VERSION 5.8 ;
BUSBITCHARS "[]" ;
DIVIDERCHAR "/" ;
UNITS
    DATABASE MICRONS 1000 ;
END UNITS

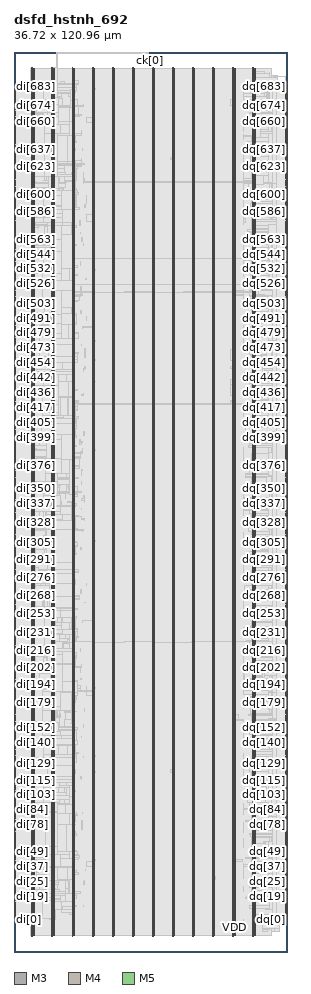
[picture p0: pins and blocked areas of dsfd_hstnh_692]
MACRO dsfd_hstnh_692
  FOREIGN dsfd_hstnh_692 0 0 ;
  CLASS BLOCK ;
  SIZE 36.72 BY 120.96 ;
  PIN ck[0]
    DIRECTION INPUT ;
    USE SIGNAL ;
    PORT
      LAYER M3 ;
        RECT  18.36 120.816 18.378 120.96 ;
    END
    PORT
      LAYER M3 ;
        RECT  18.18 120.793 18.378 120.828 ;
    END
  END ck[0]
  PIN di[0]
    DIRECTION INPUT ;
    USE SIGNAL ;
    PORT
      LAYER M4 ;
        RECT  0 4.416 0.192 4.44 ;
    END
  END di[0]
  PIN di[100]
    DIRECTION INPUT ;
    USE SIGNAL ;
    PORT
      LAYER M4 ;
        RECT  0 20.64 0.192 20.664 ;
    END
  END di[100]
  PIN di[101]
    DIRECTION INPUT ;
    USE SIGNAL ;
    PORT
      LAYER M4 ;
        RECT  0 20.784 0.192 20.808 ;
    END
  END di[101]
  PIN di[102]
    DIRECTION INPUT ;
    USE SIGNAL ;
    PORT
      LAYER M4 ;
        RECT  0 20.976 0.192 21 ;
    END
  END di[102]
  PIN di[103]
    DIRECTION INPUT ;
    USE SIGNAL ;
    PORT
      LAYER M4 ;
        RECT  0 21.12 0.192 21.144 ;
    END
  END di[103]
  PIN di[104]
    DIRECTION INPUT ;
    USE SIGNAL ;
    PORT
      LAYER M4 ;
        RECT  0 21.312 0.192 21.336 ;
    END
  END di[104]
  PIN di[105]
    DIRECTION INPUT ;
    USE SIGNAL ;
    PORT
      LAYER M4 ;
        RECT  0 21.456 0.192 21.48 ;
    END
  END di[105]
  PIN di[106]
    DIRECTION INPUT ;
    USE SIGNAL ;
    PORT
      LAYER M4 ;
        RECT  0 21.6 0.192 21.624 ;
    END
  END di[106]
  PIN di[107]
    DIRECTION INPUT ;
    USE SIGNAL ;
    PORT
      LAYER M4 ;
        RECT  0 21.792 0.192 21.816 ;
    END
  END di[107]
  PIN di[108]
    DIRECTION INPUT ;
    USE SIGNAL ;
    PORT
      LAYER M4 ;
        RECT  0 21.936 0.192 21.96 ;
    END
  END di[108]
  PIN di[109]
    DIRECTION INPUT ;
    USE SIGNAL ;
    PORT
      LAYER M4 ;
        RECT  0 22.128 0.192 22.152 ;
    END
  END di[109]
  PIN di[10]
    DIRECTION INPUT ;
    USE SIGNAL ;
    PORT
      LAYER M4 ;
        RECT  0 6.048 0.192 6.072 ;
    END
  END di[10]
  PIN di[110]
    DIRECTION INPUT ;
    USE SIGNAL ;
    PORT
      LAYER M4 ;
        RECT  0 22.272 0.192 22.296 ;
    END
  END di[110]
  PIN di[111]
    DIRECTION INPUT ;
    USE SIGNAL ;
    PORT
      LAYER M4 ;
        RECT  0 22.416 0.192 22.44 ;
    END
  END di[111]
  PIN di[112]
    DIRECTION INPUT ;
    USE SIGNAL ;
    PORT
      LAYER M4 ;
        RECT  0 22.608 0.192 22.632 ;
    END
  END di[112]
  PIN di[113]
    DIRECTION INPUT ;
    USE SIGNAL ;
    PORT
      LAYER M4 ;
        RECT  0 22.752 0.192 22.776 ;
    END
  END di[113]
  PIN di[114]
    DIRECTION INPUT ;
    USE SIGNAL ;
    PORT
      LAYER M4 ;
        RECT  0 22.896 0.192 22.92 ;
    END
  END di[114]
  PIN di[115]
    DIRECTION INPUT ;
    USE SIGNAL ;
    PORT
      LAYER M4 ;
        RECT  0 23.088 0.192 23.112 ;
    END
  END di[115]
  PIN di[116]
    DIRECTION INPUT ;
    USE SIGNAL ;
    PORT
      LAYER M4 ;
        RECT  0 23.232 0.192 23.256 ;
    END
  END di[116]
  PIN di[117]
    DIRECTION INPUT ;
    USE SIGNAL ;
    PORT
      LAYER M4 ;
        RECT  0 23.424 0.192 23.448 ;
    END
  END di[117]
  PIN di[118]
    DIRECTION INPUT ;
    USE SIGNAL ;
    PORT
      LAYER M4 ;
        RECT  0 23.568 0.192 23.592 ;
    END
  END di[118]
  PIN di[119]
    DIRECTION INPUT ;
    USE SIGNAL ;
    PORT
      LAYER M4 ;
        RECT  0 23.712 0.192 23.736 ;
    END
  END di[119]
  PIN di[11]
    DIRECTION INPUT ;
    USE SIGNAL ;
    PORT
      LAYER M4 ;
        RECT  0 6.192 0.192 6.216 ;
    END
  END di[11]
  PIN di[120]
    DIRECTION INPUT ;
    USE SIGNAL ;
    PORT
      LAYER M4 ;
        RECT  0 23.904 0.192 23.928 ;
    END
  END di[120]
  PIN di[121]
    DIRECTION INPUT ;
    USE SIGNAL ;
    PORT
      LAYER M4 ;
        RECT  0 24.048 0.192 24.072 ;
    END
  END di[121]
  PIN di[122]
    DIRECTION INPUT ;
    USE SIGNAL ;
    PORT
      LAYER M4 ;
        RECT  0 24.192 0.192 24.216 ;
    END
  END di[122]
  PIN di[123]
    DIRECTION INPUT ;
    USE SIGNAL ;
    PORT
      LAYER M4 ;
        RECT  0 24.384 0.192 24.408 ;
    END
  END di[123]
  PIN di[124]
    DIRECTION INPUT ;
    USE SIGNAL ;
    PORT
      LAYER M4 ;
        RECT  0 24.528 0.192 24.552 ;
    END
  END di[124]
  PIN di[125]
    DIRECTION INPUT ;
    USE SIGNAL ;
    PORT
      LAYER M4 ;
        RECT  0 24.72 0.192 24.744 ;
    END
  END di[125]
  PIN di[126]
    DIRECTION INPUT ;
    USE SIGNAL ;
    PORT
      LAYER M4 ;
        RECT  0 24.864 0.192 24.888 ;
    END
  END di[126]
  PIN di[127]
    DIRECTION INPUT ;
    USE SIGNAL ;
    PORT
      LAYER M4 ;
        RECT  0 25.008 0.192 25.032 ;
    END
  END di[127]
  PIN di[128]
    DIRECTION INPUT ;
    USE SIGNAL ;
    PORT
      LAYER M4 ;
        RECT  0 25.2 0.192 25.224 ;
    END
  END di[128]
  PIN di[129]
    DIRECTION INPUT ;
    USE SIGNAL ;
    PORT
      LAYER M4 ;
        RECT  0 25.344 0.192 25.368 ;
    END
  END di[129]
  PIN di[12]
    DIRECTION INPUT ;
    USE SIGNAL ;
    PORT
      LAYER M4 ;
        RECT  0 6.384 0.192 6.408 ;
    END
  END di[12]
  PIN di[130]
    DIRECTION INPUT ;
    USE SIGNAL ;
    PORT
      LAYER M4 ;
        RECT  0 25.536 0.192 25.56 ;
    END
  END di[130]
  PIN di[131]
    DIRECTION INPUT ;
    USE SIGNAL ;
    PORT
      LAYER M4 ;
        RECT  0 25.68 0.192 25.704 ;
    END
  END di[131]
  PIN di[132]
    DIRECTION INPUT ;
    USE SIGNAL ;
    PORT
      LAYER M4 ;
        RECT  0 25.824 0.192 25.848 ;
    END
  END di[132]
  PIN di[133]
    DIRECTION INPUT ;
    USE SIGNAL ;
    PORT
      LAYER M4 ;
        RECT  0 26.016 0.192 26.04 ;
    END
  END di[133]
  PIN di[134]
    DIRECTION INPUT ;
    USE SIGNAL ;
    PORT
      LAYER M4 ;
        RECT  0 26.16 0.192 26.184 ;
    END
  END di[134]
  PIN di[135]
    DIRECTION INPUT ;
    USE SIGNAL ;
    PORT
      LAYER M4 ;
        RECT  0 26.304 0.192 26.328 ;
    END
  END di[135]
  PIN di[136]
    DIRECTION INPUT ;
    USE SIGNAL ;
    PORT
      LAYER M4 ;
        RECT  0 26.496 0.192 26.52 ;
    END
  END di[136]
  PIN di[137]
    DIRECTION INPUT ;
    USE SIGNAL ;
    PORT
      LAYER M4 ;
        RECT  0 26.64 0.192 26.664 ;
    END
  END di[137]
  PIN di[138]
    DIRECTION INPUT ;
    USE SIGNAL ;
    PORT
      LAYER M4 ;
        RECT  0 26.832 0.192 26.856 ;
    END
  END di[138]
  PIN di[139]
    DIRECTION INPUT ;
    USE SIGNAL ;
    PORT
      LAYER M4 ;
        RECT  0 26.976 0.192 27 ;
    END
  END di[139]
  PIN di[13]
    DIRECTION INPUT ;
    USE SIGNAL ;
    PORT
      LAYER M4 ;
        RECT  0 6.528 0.192 6.552 ;
    END
  END di[13]
  PIN di[140]
    DIRECTION INPUT ;
    USE SIGNAL ;
    PORT
      LAYER M4 ;
        RECT  0 27.12 0.192 27.144 ;
    END
  END di[140]
  PIN di[141]
    DIRECTION INPUT ;
    USE SIGNAL ;
    PORT
      LAYER M4 ;
        RECT  0 27.312 0.192 27.336 ;
    END
  END di[141]
  PIN di[142]
    DIRECTION INPUT ;
    USE SIGNAL ;
    PORT
      LAYER M4 ;
        RECT  0 27.456 0.192 27.48 ;
    END
  END di[142]
  PIN di[143]
    DIRECTION INPUT ;
    USE SIGNAL ;
    PORT
      LAYER M4 ;
        RECT  0 27.6 0.192 27.624 ;
    END
  END di[143]
  PIN di[144]
    DIRECTION INPUT ;
    USE SIGNAL ;
    PORT
      LAYER M4 ;
        RECT  0 27.792 0.192 27.816 ;
    END
  END di[144]
  PIN di[145]
    DIRECTION INPUT ;
    USE SIGNAL ;
    PORT
      LAYER M4 ;
        RECT  0 27.936 0.192 27.96 ;
    END
  END di[145]
  PIN di[146]
    DIRECTION INPUT ;
    USE SIGNAL ;
    PORT
      LAYER M4 ;
        RECT  0 28.128 0.192 28.152 ;
    END
  END di[146]
  PIN di[147]
    DIRECTION INPUT ;
    USE SIGNAL ;
    PORT
      LAYER M4 ;
        RECT  0 28.272 0.192 28.296 ;
    END
  END di[147]
  PIN di[148]
    DIRECTION INPUT ;
    USE SIGNAL ;
    PORT
      LAYER M4 ;
        RECT  0 28.416 0.192 28.44 ;
    END
  END di[148]
  PIN di[149]
    DIRECTION INPUT ;
    USE SIGNAL ;
    PORT
      LAYER M4 ;
        RECT  0 28.608 0.192 28.632 ;
    END
  END di[149]
  PIN di[14]
    DIRECTION INPUT ;
    USE SIGNAL ;
    PORT
      LAYER M4 ;
        RECT  0 6.672 0.192 6.696 ;
    END
  END di[14]
  PIN di[150]
    DIRECTION INPUT ;
    USE SIGNAL ;
    PORT
      LAYER M4 ;
        RECT  0 28.752 0.192 28.776 ;
    END
  END di[150]
  PIN di[151]
    DIRECTION INPUT ;
    USE SIGNAL ;
    PORT
      LAYER M4 ;
        RECT  0 28.944 0.192 28.968 ;
    END
  END di[151]
  PIN di[152]
    DIRECTION INPUT ;
    USE SIGNAL ;
    PORT
      LAYER M4 ;
        RECT  0 29.088 0.192 29.112 ;
    END
  END di[152]
  PIN di[153]
    DIRECTION INPUT ;
    USE SIGNAL ;
    PORT
      LAYER M4 ;
        RECT  0 29.232 0.192 29.256 ;
    END
  END di[153]
  PIN di[154]
    DIRECTION INPUT ;
    USE SIGNAL ;
    PORT
      LAYER M4 ;
        RECT  0 29.424 0.192 29.448 ;
    END
  END di[154]
  PIN di[155]
    DIRECTION INPUT ;
    USE SIGNAL ;
    PORT
      LAYER M4 ;
        RECT  0 29.568 0.192 29.592 ;
    END
  END di[155]
  PIN di[156]
    DIRECTION INPUT ;
    USE SIGNAL ;
    PORT
      LAYER M4 ;
        RECT  0 29.712 0.192 29.736 ;
    END
  END di[156]
  PIN di[157]
    DIRECTION INPUT ;
    USE SIGNAL ;
    PORT
      LAYER M4 ;
        RECT  0 29.904 0.192 29.928 ;
    END
  END di[157]
  PIN di[158]
    DIRECTION INPUT ;
    USE SIGNAL ;
    PORT
      LAYER M4 ;
        RECT  0 30.048 0.192 30.072 ;
    END
  END di[158]
  PIN di[159]
    DIRECTION INPUT ;
    USE SIGNAL ;
    PORT
      LAYER M4 ;
        RECT  0 30.24 0.192 30.264 ;
    END
  END di[159]
  PIN di[15]
    DIRECTION INPUT ;
    USE SIGNAL ;
    PORT
      LAYER M4 ;
        RECT  0 6.864 0.192 6.888 ;
    END
  END di[15]
  PIN di[160]
    DIRECTION INPUT ;
    USE SIGNAL ;
    PORT
      LAYER M4 ;
        RECT  0 30.384 0.192 30.408 ;
    END
  END di[160]
  PIN di[161]
    DIRECTION INPUT ;
    USE SIGNAL ;
    PORT
      LAYER M4 ;
        RECT  0 30.528 0.192 30.552 ;
    END
  END di[161]
  PIN di[162]
    DIRECTION INPUT ;
    USE SIGNAL ;
    PORT
      LAYER M4 ;
        RECT  0 30.72 0.192 30.744 ;
    END
  END di[162]
  PIN di[163]
    DIRECTION INPUT ;
    USE SIGNAL ;
    PORT
      LAYER M4 ;
        RECT  0 30.864 0.192 30.888 ;
    END
  END di[163]
  PIN di[164]
    DIRECTION INPUT ;
    USE SIGNAL ;
    PORT
      LAYER M4 ;
        RECT  0 31.056 0.192 31.08 ;
    END
  END di[164]
  PIN di[165]
    DIRECTION INPUT ;
    USE SIGNAL ;
    PORT
      LAYER M4 ;
        RECT  0 31.2 0.192 31.224 ;
    END
  END di[165]
  PIN di[166]
    DIRECTION INPUT ;
    USE SIGNAL ;
    PORT
      LAYER M4 ;
        RECT  0 31.344 0.192 31.368 ;
    END
  END di[166]
  PIN di[167]
    DIRECTION INPUT ;
    USE SIGNAL ;
    PORT
      LAYER M4 ;
        RECT  0 31.536 0.192 31.56 ;
    END
  END di[167]
  PIN di[168]
    DIRECTION INPUT ;
    USE SIGNAL ;
    PORT
      LAYER M4 ;
        RECT  0 31.68 0.192 31.704 ;
    END
  END di[168]
  PIN di[169]
    DIRECTION INPUT ;
    USE SIGNAL ;
    PORT
      LAYER M4 ;
        RECT  0 31.824 0.192 31.848 ;
    END
  END di[169]
  PIN di[16]
    DIRECTION INPUT ;
    USE SIGNAL ;
    PORT
      LAYER M4 ;
        RECT  0 7.008 0.192 7.032 ;
    END
  END di[16]
  PIN di[170]
    DIRECTION INPUT ;
    USE SIGNAL ;
    PORT
      LAYER M4 ;
        RECT  0 32.016 0.192 32.04 ;
    END
  END di[170]
  PIN di[171]
    DIRECTION INPUT ;
    USE SIGNAL ;
    PORT
      LAYER M4 ;
        RECT  0 32.16 0.192 32.184 ;
    END
  END di[171]
  PIN di[172]
    DIRECTION INPUT ;
    USE SIGNAL ;
    PORT
      LAYER M4 ;
        RECT  0 32.352 0.192 32.376 ;
    END
  END di[172]
  PIN di[173]
    DIRECTION INPUT ;
    USE SIGNAL ;
    PORT
      LAYER M4 ;
        RECT  0 32.496 0.192 32.52 ;
    END
  END di[173]
  PIN di[174]
    DIRECTION INPUT ;
    USE SIGNAL ;
    PORT
      LAYER M4 ;
        RECT  0 32.64 0.192 32.664 ;
    END
  END di[174]
  PIN di[175]
    DIRECTION INPUT ;
    USE SIGNAL ;
    PORT
      LAYER M4 ;
        RECT  0 32.832 0.192 32.856 ;
    END
  END di[175]
  PIN di[176]
    DIRECTION INPUT ;
    USE SIGNAL ;
    PORT
      LAYER M4 ;
        RECT  0 32.976 0.192 33 ;
    END
  END di[176]
  PIN di[177]
    DIRECTION INPUT ;
    USE SIGNAL ;
    PORT
      LAYER M4 ;
        RECT  0 33.12 0.192 33.144 ;
    END
  END di[177]
  PIN di[178]
    DIRECTION INPUT ;
    USE SIGNAL ;
    PORT
      LAYER M4 ;
        RECT  0 33.312 0.192 33.336 ;
    END
  END di[178]
  PIN di[179]
    DIRECTION INPUT ;
    USE SIGNAL ;
    PORT
      LAYER M4 ;
        RECT  0 33.456 0.192 33.48 ;
    END
  END di[179]
  PIN di[17]
    DIRECTION INPUT ;
    USE SIGNAL ;
    PORT
      LAYER M4 ;
        RECT  0 7.152 0.192 7.176 ;
    END
  END di[17]
  PIN di[180]
    DIRECTION INPUT ;
    USE SIGNAL ;
    PORT
      LAYER M4 ;
        RECT  0 33.648 0.192 33.672 ;
    END
  END di[180]
  PIN di[181]
    DIRECTION INPUT ;
    USE SIGNAL ;
    PORT
      LAYER M4 ;
        RECT  0 33.792 0.192 33.816 ;
    END
  END di[181]
  PIN di[182]
    DIRECTION INPUT ;
    USE SIGNAL ;
    PORT
      LAYER M4 ;
        RECT  0 33.936 0.192 33.96 ;
    END
  END di[182]
  PIN di[183]
    DIRECTION INPUT ;
    USE SIGNAL ;
    PORT
      LAYER M4 ;
        RECT  0 34.128 0.192 34.152 ;
    END
  END di[183]
  PIN di[184]
    DIRECTION INPUT ;
    USE SIGNAL ;
    PORT
      LAYER M4 ;
        RECT  0 34.272 0.192 34.296 ;
    END
  END di[184]
  PIN di[185]
    DIRECTION INPUT ;
    USE SIGNAL ;
    PORT
      LAYER M4 ;
        RECT  0 34.464 0.192 34.488 ;
    END
  END di[185]
  PIN di[186]
    DIRECTION INPUT ;
    USE SIGNAL ;
    PORT
      LAYER M4 ;
        RECT  0 34.608 0.192 34.632 ;
    END
  END di[186]
  PIN di[187]
    DIRECTION INPUT ;
    USE SIGNAL ;
    PORT
      LAYER M4 ;
        RECT  0 34.752 0.192 34.776 ;
    END
  END di[187]
  PIN di[188]
    DIRECTION INPUT ;
    USE SIGNAL ;
    PORT
      LAYER M4 ;
        RECT  0 34.944 0.192 34.968 ;
    END
  END di[188]
  PIN di[189]
    DIRECTION INPUT ;
    USE SIGNAL ;
    PORT
      LAYER M4 ;
        RECT  0 35.088 0.192 35.112 ;
    END
  END di[189]
  PIN di[18]
    DIRECTION INPUT ;
    USE SIGNAL ;
    PORT
      LAYER M4 ;
        RECT  0 7.344 0.192 7.368 ;
    END
  END di[18]
  PIN di[190]
    DIRECTION INPUT ;
    USE SIGNAL ;
    PORT
      LAYER M4 ;
        RECT  0 35.232 0.192 35.256 ;
    END
  END di[190]
  PIN di[191]
    DIRECTION INPUT ;
    USE SIGNAL ;
    PORT
      LAYER M4 ;
        RECT  0 35.424 0.192 35.448 ;
    END
  END di[191]
  PIN di[192]
    DIRECTION INPUT ;
    USE SIGNAL ;
    PORT
      LAYER M4 ;
        RECT  0 35.568 0.192 35.592 ;
    END
  END di[192]
  PIN di[193]
    DIRECTION INPUT ;
    USE SIGNAL ;
    PORT
      LAYER M4 ;
        RECT  0 35.76 0.192 35.784 ;
    END
  END di[193]
  PIN di[194]
    DIRECTION INPUT ;
    USE SIGNAL ;
    PORT
      LAYER M4 ;
        RECT  0 35.904 0.192 35.928 ;
    END
  END di[194]
  PIN di[195]
    DIRECTION INPUT ;
    USE SIGNAL ;
    PORT
      LAYER M4 ;
        RECT  0 36.048 0.192 36.072 ;
    END
  END di[195]
  PIN di[196]
    DIRECTION INPUT ;
    USE SIGNAL ;
    PORT
      LAYER M4 ;
        RECT  0 36.24 0.192 36.264 ;
    END
  END di[196]
  PIN di[197]
    DIRECTION INPUT ;
    USE SIGNAL ;
    PORT
      LAYER M4 ;
        RECT  0 36.384 0.192 36.408 ;
    END
  END di[197]
  PIN di[198]
    DIRECTION INPUT ;
    USE SIGNAL ;
    PORT
      LAYER M4 ;
        RECT  0 36.528 0.192 36.552 ;
    END
  END di[198]
  PIN di[199]
    DIRECTION INPUT ;
    USE SIGNAL ;
    PORT
      LAYER M4 ;
        RECT  0 36.72 0.192 36.744 ;
    END
  END di[199]
  PIN di[19]
    DIRECTION INPUT ;
    USE SIGNAL ;
    PORT
      LAYER M4 ;
        RECT  0 7.488 0.192 7.512 ;
    END
  END di[19]
  PIN di[1]
    DIRECTION INPUT ;
    USE SIGNAL ;
    PORT
      LAYER M4 ;
        RECT  0 4.56 0.192 4.584 ;
    END
  END di[1]
  PIN di[200]
    DIRECTION INPUT ;
    USE SIGNAL ;
    PORT
      LAYER M4 ;
        RECT  0 36.864 0.192 36.888 ;
    END
  END di[200]
  PIN di[201]
    DIRECTION INPUT ;
    USE SIGNAL ;
    PORT
      LAYER M4 ;
        RECT  0 37.056 0.192 37.08 ;
    END
  END di[201]
  PIN di[202]
    DIRECTION INPUT ;
    USE SIGNAL ;
    PORT
      LAYER M4 ;
        RECT  0 37.2 0.192 37.224 ;
    END
  END di[202]
  PIN di[203]
    DIRECTION INPUT ;
    USE SIGNAL ;
    PORT
      LAYER M4 ;
        RECT  0 37.344 0.192 37.368 ;
    END
  END di[203]
  PIN di[204]
    DIRECTION INPUT ;
    USE SIGNAL ;
    PORT
      LAYER M4 ;
        RECT  0 37.536 0.192 37.56 ;
    END
  END di[204]
  PIN di[205]
    DIRECTION INPUT ;
    USE SIGNAL ;
    PORT
      LAYER M4 ;
        RECT  0 37.68 0.192 37.704 ;
    END
  END di[205]
  PIN di[206]
    DIRECTION INPUT ;
    USE SIGNAL ;
    PORT
      LAYER M4 ;
        RECT  0 37.872 0.192 37.896 ;
    END
  END di[206]
  PIN di[207]
    DIRECTION INPUT ;
    USE SIGNAL ;
    PORT
      LAYER M4 ;
        RECT  0 38.016 0.192 38.04 ;
    END
  END di[207]
  PIN di[208]
    DIRECTION INPUT ;
    USE SIGNAL ;
    PORT
      LAYER M4 ;
        RECT  0 38.16 0.192 38.184 ;
    END
  END di[208]
  PIN di[209]
    DIRECTION INPUT ;
    USE SIGNAL ;
    PORT
      LAYER M4 ;
        RECT  0 38.352 0.192 38.376 ;
    END
  END di[209]
  PIN di[20]
    DIRECTION INPUT ;
    USE SIGNAL ;
    PORT
      LAYER M4 ;
        RECT  0 7.68 0.192 7.704 ;
    END
  END di[20]
  PIN di[210]
    DIRECTION INPUT ;
    USE SIGNAL ;
    PORT
      LAYER M4 ;
        RECT  0 38.496 0.192 38.52 ;
    END
  END di[210]
  PIN di[211]
    DIRECTION INPUT ;
    USE SIGNAL ;
    PORT
      LAYER M4 ;
        RECT  0 38.64 0.192 38.664 ;
    END
  END di[211]
  PIN di[212]
    DIRECTION INPUT ;
    USE SIGNAL ;
    PORT
      LAYER M4 ;
        RECT  0 38.832 0.192 38.856 ;
    END
  END di[212]
  PIN di[213]
    DIRECTION INPUT ;
    USE SIGNAL ;
    PORT
      LAYER M4 ;
        RECT  0 38.976 0.192 39 ;
    END
  END di[213]
  PIN di[214]
    DIRECTION INPUT ;
    USE SIGNAL ;
    PORT
      LAYER M4 ;
        RECT  0 39.168 0.192 39.192 ;
    END
  END di[214]
  PIN di[215]
    DIRECTION INPUT ;
    USE SIGNAL ;
    PORT
      LAYER M4 ;
        RECT  0 39.312 0.192 39.336 ;
    END
  END di[215]
  PIN di[216]
    DIRECTION INPUT ;
    USE SIGNAL ;
    PORT
      LAYER M4 ;
        RECT  0 39.456 0.192 39.48 ;
    END
  END di[216]
  PIN di[217]
    DIRECTION INPUT ;
    USE SIGNAL ;
    PORT
      LAYER M4 ;
        RECT  0 39.648 0.192 39.672 ;
    END
  END di[217]
  PIN di[218]
    DIRECTION INPUT ;
    USE SIGNAL ;
    PORT
      LAYER M4 ;
        RECT  0 39.792 0.192 39.816 ;
    END
  END di[218]
  PIN di[219]
    DIRECTION INPUT ;
    USE SIGNAL ;
    PORT
      LAYER M4 ;
        RECT  0 39.936 0.192 39.96 ;
    END
  END di[219]
  PIN di[21]
    DIRECTION INPUT ;
    USE SIGNAL ;
    PORT
      LAYER M4 ;
        RECT  0 7.824 0.192 7.848 ;
    END
  END di[21]
  PIN di[220]
    DIRECTION INPUT ;
    USE SIGNAL ;
    PORT
      LAYER M4 ;
        RECT  0 40.128 0.192 40.152 ;
    END
  END di[220]
  PIN di[221]
    DIRECTION INPUT ;
    USE SIGNAL ;
    PORT
      LAYER M4 ;
        RECT  0 40.272 0.192 40.296 ;
    END
  END di[221]
  PIN di[222]
    DIRECTION INPUT ;
    USE SIGNAL ;
    PORT
      LAYER M4 ;
        RECT  0 40.464 0.192 40.488 ;
    END
  END di[222]
  PIN di[223]
    DIRECTION INPUT ;
    USE SIGNAL ;
    PORT
      LAYER M4 ;
        RECT  0 40.608 0.192 40.632 ;
    END
  END di[223]
  PIN di[224]
    DIRECTION INPUT ;
    USE SIGNAL ;
    PORT
      LAYER M4 ;
        RECT  0 40.752 0.192 40.776 ;
    END
  END di[224]
  PIN di[225]
    DIRECTION INPUT ;
    USE SIGNAL ;
    PORT
      LAYER M4 ;
        RECT  0 40.944 0.192 40.968 ;
    END
  END di[225]
  PIN di[226]
    DIRECTION INPUT ;
    USE SIGNAL ;
    PORT
      LAYER M4 ;
        RECT  0 41.088 0.192 41.112 ;
    END
  END di[226]
  PIN di[227]
    DIRECTION INPUT ;
    USE SIGNAL ;
    PORT
      LAYER M4 ;
        RECT  0 41.28 0.192 41.304 ;
    END
  END di[227]
  PIN di[228]
    DIRECTION INPUT ;
    USE SIGNAL ;
    PORT
      LAYER M4 ;
        RECT  0 41.424 0.192 41.448 ;
    END
  END di[228]
  PIN di[229]
    DIRECTION INPUT ;
    USE SIGNAL ;
    PORT
      LAYER M4 ;
        RECT  0 41.568 0.192 41.592 ;
    END
  END di[229]
  PIN di[22]
    DIRECTION INPUT ;
    USE SIGNAL ;
    PORT
      LAYER M4 ;
        RECT  0 7.968 0.192 7.992 ;
    END
  END di[22]
  PIN di[230]
    DIRECTION INPUT ;
    USE SIGNAL ;
    PORT
      LAYER M4 ;
        RECT  0 41.76 0.192 41.784 ;
    END
  END di[230]
  PIN di[231]
    DIRECTION INPUT ;
    USE SIGNAL ;
    PORT
      LAYER M4 ;
        RECT  0 41.904 0.192 41.928 ;
    END
  END di[231]
  PIN di[232]
    DIRECTION INPUT ;
    USE SIGNAL ;
    PORT
      LAYER M4 ;
        RECT  0 42.048 0.192 42.072 ;
    END
  END di[232]
  PIN di[233]
    DIRECTION INPUT ;
    USE SIGNAL ;
    PORT
      LAYER M4 ;
        RECT  0 42.24 0.192 42.264 ;
    END
  END di[233]
  PIN di[234]
    DIRECTION INPUT ;
    USE SIGNAL ;
    PORT
      LAYER M4 ;
        RECT  0 42.384 0.192 42.408 ;
    END
  END di[234]
  PIN di[235]
    DIRECTION INPUT ;
    USE SIGNAL ;
    PORT
      LAYER M4 ;
        RECT  0 42.576 0.192 42.6 ;
    END
  END di[235]
  PIN di[236]
    DIRECTION INPUT ;
    USE SIGNAL ;
    PORT
      LAYER M4 ;
        RECT  0 42.72 0.192 42.744 ;
    END
  END di[236]
  PIN di[237]
    DIRECTION INPUT ;
    USE SIGNAL ;
    PORT
      LAYER M4 ;
        RECT  0 42.864 0.192 42.888 ;
    END
  END di[237]
  PIN di[238]
    DIRECTION INPUT ;
    USE SIGNAL ;
    PORT
      LAYER M4 ;
        RECT  0 43.056 0.192 43.08 ;
    END
  END di[238]
  PIN di[239]
    DIRECTION INPUT ;
    USE SIGNAL ;
    PORT
      LAYER M4 ;
        RECT  0 43.2 0.192 43.224 ;
    END
  END di[239]
  PIN di[23]
    DIRECTION INPUT ;
    USE SIGNAL ;
    PORT
      LAYER M4 ;
        RECT  0 8.16 0.192 8.184 ;
    END
  END di[23]
  PIN di[240]
    DIRECTION INPUT ;
    USE SIGNAL ;
    PORT
      LAYER M4 ;
        RECT  0 43.392 0.192 43.416 ;
    END
  END di[240]
  PIN di[241]
    DIRECTION INPUT ;
    USE SIGNAL ;
    PORT
      LAYER M4 ;
        RECT  0 43.536 0.192 43.56 ;
    END
  END di[241]
  PIN di[242]
    DIRECTION INPUT ;
    USE SIGNAL ;
    PORT
      LAYER M4 ;
        RECT  0 43.68 0.192 43.704 ;
    END
  END di[242]
  PIN di[243]
    DIRECTION INPUT ;
    USE SIGNAL ;
    PORT
      LAYER M4 ;
        RECT  0 43.872 0.192 43.896 ;
    END
  END di[243]
  PIN di[244]
    DIRECTION INPUT ;
    USE SIGNAL ;
    PORT
      LAYER M4 ;
        RECT  0 44.016 0.192 44.04 ;
    END
  END di[244]
  PIN di[245]
    DIRECTION INPUT ;
    USE SIGNAL ;
    PORT
      LAYER M4 ;
        RECT  0 44.16 0.192 44.184 ;
    END
  END di[245]
  PIN di[246]
    DIRECTION INPUT ;
    USE SIGNAL ;
    PORT
      LAYER M4 ;
        RECT  0 44.352 0.192 44.376 ;
    END
  END di[246]
  PIN di[247]
    DIRECTION INPUT ;
    USE SIGNAL ;
    PORT
      LAYER M4 ;
        RECT  0 44.496 0.192 44.52 ;
    END
  END di[247]
  PIN di[248]
    DIRECTION INPUT ;
    USE SIGNAL ;
    PORT
      LAYER M4 ;
        RECT  0 44.688 0.192 44.712 ;
    END
  END di[248]
  PIN di[249]
    DIRECTION INPUT ;
    USE SIGNAL ;
    PORT
      LAYER M4 ;
        RECT  0 44.832 0.192 44.856 ;
    END
  END di[249]
  PIN di[24]
    DIRECTION INPUT ;
    USE SIGNAL ;
    PORT
      LAYER M4 ;
        RECT  0 8.304 0.192 8.328 ;
    END
  END di[24]
  PIN di[250]
    DIRECTION INPUT ;
    USE SIGNAL ;
    PORT
      LAYER M4 ;
        RECT  0 44.976 0.192 45 ;
    END
  END di[250]
  PIN di[251]
    DIRECTION INPUT ;
    USE SIGNAL ;
    PORT
      LAYER M4 ;
        RECT  0 45.168 0.192 45.192 ;
    END
  END di[251]
  PIN di[252]
    DIRECTION INPUT ;
    USE SIGNAL ;
    PORT
      LAYER M4 ;
        RECT  0 45.312 0.192 45.336 ;
    END
  END di[252]
  PIN di[253]
    DIRECTION INPUT ;
    USE SIGNAL ;
    PORT
      LAYER M4 ;
        RECT  0 45.456 0.192 45.48 ;
    END
  END di[253]
  PIN di[254]
    DIRECTION INPUT ;
    USE SIGNAL ;
    PORT
      LAYER M4 ;
        RECT  0 45.648 0.192 45.672 ;
    END
  END di[254]
  PIN di[255]
    DIRECTION INPUT ;
    USE SIGNAL ;
    PORT
      LAYER M4 ;
        RECT  0 45.792 0.192 45.816 ;
    END
  END di[255]
  PIN di[256]
    DIRECTION INPUT ;
    USE SIGNAL ;
    PORT
      LAYER M4 ;
        RECT  0 45.984 0.192 46.008 ;
    END
  END di[256]
  PIN di[257]
    DIRECTION INPUT ;
    USE SIGNAL ;
    PORT
      LAYER M4 ;
        RECT  0 46.128 0.192 46.152 ;
    END
  END di[257]
  PIN di[258]
    DIRECTION INPUT ;
    USE SIGNAL ;
    PORT
      LAYER M4 ;
        RECT  0 46.272 0.192 46.296 ;
    END
  END di[258]
  PIN di[259]
    DIRECTION INPUT ;
    USE SIGNAL ;
    PORT
      LAYER M4 ;
        RECT  0 46.464 0.192 46.488 ;
    END
  END di[259]
  PIN di[25]
    DIRECTION INPUT ;
    USE SIGNAL ;
    PORT
      LAYER M4 ;
        RECT  0 8.448 0.192 8.472 ;
    END
  END di[25]
  PIN di[260]
    DIRECTION INPUT ;
    USE SIGNAL ;
    PORT
      LAYER M4 ;
        RECT  0 46.608 0.192 46.632 ;
    END
  END di[260]
  PIN di[261]
    DIRECTION INPUT ;
    USE SIGNAL ;
    PORT
      LAYER M4 ;
        RECT  0 46.8 0.192 46.824 ;
    END
  END di[261]
  PIN di[262]
    DIRECTION INPUT ;
    USE SIGNAL ;
    PORT
      LAYER M4 ;
        RECT  0 46.944 0.192 46.968 ;
    END
  END di[262]
  PIN di[263]
    DIRECTION INPUT ;
    USE SIGNAL ;
    PORT
      LAYER M4 ;
        RECT  0 47.088 0.192 47.112 ;
    END
  END di[263]
  PIN di[264]
    DIRECTION INPUT ;
    USE SIGNAL ;
    PORT
      LAYER M4 ;
        RECT  0 47.28 0.192 47.304 ;
    END
  END di[264]
  PIN di[265]
    DIRECTION INPUT ;
    USE SIGNAL ;
    PORT
      LAYER M4 ;
        RECT  0 47.424 0.192 47.448 ;
    END
  END di[265]
  PIN di[266]
    DIRECTION INPUT ;
    USE SIGNAL ;
    PORT
      LAYER M4 ;
        RECT  0 47.568 0.192 47.592 ;
    END
  END di[266]
  PIN di[267]
    DIRECTION INPUT ;
    USE SIGNAL ;
    PORT
      LAYER M4 ;
        RECT  0 47.76 0.192 47.784 ;
    END
  END di[267]
  PIN di[268]
    DIRECTION INPUT ;
    USE SIGNAL ;
    PORT
      LAYER M4 ;
        RECT  0 47.904 0.192 47.928 ;
    END
  END di[268]
  PIN di[269]
    DIRECTION INPUT ;
    USE SIGNAL ;
    PORT
      LAYER M4 ;
        RECT  0 48.096 0.192 48.12 ;
    END
  END di[269]
  PIN di[26]
    DIRECTION INPUT ;
    USE SIGNAL ;
    PORT
      LAYER M4 ;
        RECT  0 8.64 0.192 8.664 ;
    END
  END di[26]
  PIN di[270]
    DIRECTION INPUT ;
    USE SIGNAL ;
    PORT
      LAYER M4 ;
        RECT  0 48.24 0.192 48.264 ;
    END
  END di[270]
  PIN di[271]
    DIRECTION INPUT ;
    USE SIGNAL ;
    PORT
      LAYER M4 ;
        RECT  0 48.384 0.192 48.408 ;
    END
  END di[271]
  PIN di[272]
    DIRECTION INPUT ;
    USE SIGNAL ;
    PORT
      LAYER M4 ;
        RECT  0 48.576 0.192 48.6 ;
    END
  END di[272]
  PIN di[273]
    DIRECTION INPUT ;
    USE SIGNAL ;
    PORT
      LAYER M4 ;
        RECT  0 48.72 0.192 48.744 ;
    END
  END di[273]
  PIN di[274]
    DIRECTION INPUT ;
    USE SIGNAL ;
    PORT
      LAYER M4 ;
        RECT  0 48.864 0.192 48.888 ;
    END
  END di[274]
  PIN di[275]
    DIRECTION INPUT ;
    USE SIGNAL ;
    PORT
      LAYER M4 ;
        RECT  0 49.056 0.192 49.08 ;
    END
  END di[275]
  PIN di[276]
    DIRECTION INPUT ;
    USE SIGNAL ;
    PORT
      LAYER M4 ;
        RECT  0 49.2 0.192 49.224 ;
    END
  END di[276]
  PIN di[277]
    DIRECTION INPUT ;
    USE SIGNAL ;
    PORT
      LAYER M4 ;
        RECT  0 49.392 0.192 49.416 ;
    END
  END di[277]
  PIN di[278]
    DIRECTION INPUT ;
    USE SIGNAL ;
    PORT
      LAYER M4 ;
        RECT  0 49.536 0.192 49.56 ;
    END
  END di[278]
  PIN di[279]
    DIRECTION INPUT ;
    USE SIGNAL ;
    PORT
      LAYER M4 ;
        RECT  0 49.68 0.192 49.704 ;
    END
  END di[279]
  PIN di[27]
    DIRECTION INPUT ;
    USE SIGNAL ;
    PORT
      LAYER M4 ;
        RECT  0 8.784 0.192 8.808 ;
    END
  END di[27]
  PIN di[280]
    DIRECTION INPUT ;
    USE SIGNAL ;
    PORT
      LAYER M4 ;
        RECT  0 49.872 0.192 49.896 ;
    END
  END di[280]
  PIN di[281]
    DIRECTION INPUT ;
    USE SIGNAL ;
    PORT
      LAYER M4 ;
        RECT  0 50.016 0.192 50.04 ;
    END
  END di[281]
  PIN di[282]
    DIRECTION INPUT ;
    USE SIGNAL ;
    PORT
      LAYER M4 ;
        RECT  0 50.208 0.192 50.232 ;
    END
  END di[282]
  PIN di[283]
    DIRECTION INPUT ;
    USE SIGNAL ;
    PORT
      LAYER M4 ;
        RECT  0 50.352 0.192 50.376 ;
    END
  END di[283]
  PIN di[284]
    DIRECTION INPUT ;
    USE SIGNAL ;
    PORT
      LAYER M4 ;
        RECT  0 50.496 0.192 50.52 ;
    END
  END di[284]
  PIN di[285]
    DIRECTION INPUT ;
    USE SIGNAL ;
    PORT
      LAYER M4 ;
        RECT  0 50.688 0.192 50.712 ;
    END
  END di[285]
  PIN di[286]
    DIRECTION INPUT ;
    USE SIGNAL ;
    PORT
      LAYER M4 ;
        RECT  0 50.832 0.192 50.856 ;
    END
  END di[286]
  PIN di[287]
    DIRECTION INPUT ;
    USE SIGNAL ;
    PORT
      LAYER M4 ;
        RECT  0 50.976 0.192 51 ;
    END
  END di[287]
  PIN di[288]
    DIRECTION INPUT ;
    USE SIGNAL ;
    PORT
      LAYER M4 ;
        RECT  0 51.168 0.192 51.192 ;
    END
  END di[288]
  PIN di[289]
    DIRECTION INPUT ;
    USE SIGNAL ;
    PORT
      LAYER M4 ;
        RECT  0 51.312 0.192 51.336 ;
    END
  END di[289]
  PIN di[28]
    DIRECTION INPUT ;
    USE SIGNAL ;
    PORT
      LAYER M4 ;
        RECT  0 8.976 0.192 9 ;
    END
  END di[28]
  PIN di[290]
    DIRECTION INPUT ;
    USE SIGNAL ;
    PORT
      LAYER M4 ;
        RECT  0 51.504 0.192 51.528 ;
    END
  END di[290]
  PIN di[291]
    DIRECTION INPUT ;
    USE SIGNAL ;
    PORT
      LAYER M4 ;
        RECT  0 51.648 0.192 51.672 ;
    END
  END di[291]
  PIN di[292]
    DIRECTION INPUT ;
    USE SIGNAL ;
    PORT
      LAYER M4 ;
        RECT  0 51.792 0.192 51.816 ;
    END
  END di[292]
  PIN di[293]
    DIRECTION INPUT ;
    USE SIGNAL ;
    PORT
      LAYER M4 ;
        RECT  0 51.984 0.192 52.008 ;
    END
  END di[293]
  PIN di[294]
    DIRECTION INPUT ;
    USE SIGNAL ;
    PORT
      LAYER M4 ;
        RECT  0 52.128 0.192 52.152 ;
    END
  END di[294]
  PIN di[295]
    DIRECTION INPUT ;
    USE SIGNAL ;
    PORT
      LAYER M4 ;
        RECT  0 52.272 0.192 52.296 ;
    END
  END di[295]
  PIN di[296]
    DIRECTION INPUT ;
    USE SIGNAL ;
    PORT
      LAYER M4 ;
        RECT  0 52.464 0.192 52.488 ;
    END
  END di[296]
  PIN di[297]
    DIRECTION INPUT ;
    USE SIGNAL ;
    PORT
      LAYER M4 ;
        RECT  0 52.608 0.192 52.632 ;
    END
  END di[297]
  PIN di[298]
    DIRECTION INPUT ;
    USE SIGNAL ;
    PORT
      LAYER M4 ;
        RECT  0 52.8 0.192 52.824 ;
    END
  END di[298]
  PIN di[299]
    DIRECTION INPUT ;
    USE SIGNAL ;
    PORT
      LAYER M4 ;
        RECT  0 52.944 0.192 52.968 ;
    END
  END di[299]
  PIN di[29]
    DIRECTION INPUT ;
    USE SIGNAL ;
    PORT
      LAYER M4 ;
        RECT  0 9.12 0.192 9.144 ;
    END
  END di[29]
  PIN di[2]
    DIRECTION INPUT ;
    USE SIGNAL ;
    PORT
      LAYER M4 ;
        RECT  0 4.752 0.192 4.776 ;
    END
  END di[2]
  PIN di[300]
    DIRECTION INPUT ;
    USE SIGNAL ;
    PORT
      LAYER M4 ;
        RECT  0 53.088 0.192 53.112 ;
    END
  END di[300]
  PIN di[301]
    DIRECTION INPUT ;
    USE SIGNAL ;
    PORT
      LAYER M4 ;
        RECT  0 53.28 0.192 53.304 ;
    END
  END di[301]
  PIN di[302]
    DIRECTION INPUT ;
    USE SIGNAL ;
    PORT
      LAYER M4 ;
        RECT  0 53.424 0.192 53.448 ;
    END
  END di[302]
  PIN di[303]
    DIRECTION INPUT ;
    USE SIGNAL ;
    PORT
      LAYER M4 ;
        RECT  0 53.616 0.192 53.64 ;
    END
  END di[303]
  PIN di[304]
    DIRECTION INPUT ;
    USE SIGNAL ;
    PORT
      LAYER M4 ;
        RECT  0 53.76 0.192 53.784 ;
    END
  END di[304]
  PIN di[305]
    DIRECTION INPUT ;
    USE SIGNAL ;
    PORT
      LAYER M4 ;
        RECT  0 53.904 0.192 53.928 ;
    END
  END di[305]
  PIN di[306]
    DIRECTION INPUT ;
    USE SIGNAL ;
    PORT
      LAYER M4 ;
        RECT  0 54.096 0.192 54.12 ;
    END
  END di[306]
  PIN di[307]
    DIRECTION INPUT ;
    USE SIGNAL ;
    PORT
      LAYER M4 ;
        RECT  0 54.24 0.192 54.264 ;
    END
  END di[307]
  PIN di[308]
    DIRECTION INPUT ;
    USE SIGNAL ;
    PORT
      LAYER M4 ;
        RECT  0 54.384 0.192 54.408 ;
    END
  END di[308]
  PIN di[309]
    DIRECTION INPUT ;
    USE SIGNAL ;
    PORT
      LAYER M4 ;
        RECT  0 54.576 0.192 54.6 ;
    END
  END di[309]
  PIN di[30]
    DIRECTION INPUT ;
    USE SIGNAL ;
    PORT
      LAYER M4 ;
        RECT  0 9.264 0.192 9.288 ;
    END
  END di[30]
  PIN di[310]
    DIRECTION INPUT ;
    USE SIGNAL ;
    PORT
      LAYER M4 ;
        RECT  0 54.72 0.192 54.744 ;
    END
  END di[310]
  PIN di[311]
    DIRECTION INPUT ;
    USE SIGNAL ;
    PORT
      LAYER M4 ;
        RECT  0 54.912 0.192 54.936 ;
    END
  END di[311]
  PIN di[312]
    DIRECTION INPUT ;
    USE SIGNAL ;
    PORT
      LAYER M4 ;
        RECT  0 55.056 0.192 55.08 ;
    END
  END di[312]
  PIN di[313]
    DIRECTION INPUT ;
    USE SIGNAL ;
    PORT
      LAYER M4 ;
        RECT  0 55.2 0.192 55.224 ;
    END
  END di[313]
  PIN di[314]
    DIRECTION INPUT ;
    USE SIGNAL ;
    PORT
      LAYER M4 ;
        RECT  0 55.392 0.192 55.416 ;
    END
  END di[314]
  PIN di[315]
    DIRECTION INPUT ;
    USE SIGNAL ;
    PORT
      LAYER M4 ;
        RECT  0 55.536 0.192 55.56 ;
    END
  END di[315]
  PIN di[316]
    DIRECTION INPUT ;
    USE SIGNAL ;
    PORT
      LAYER M4 ;
        RECT  0 55.68 0.192 55.704 ;
    END
  END di[316]
  PIN di[317]
    DIRECTION INPUT ;
    USE SIGNAL ;
    PORT
      LAYER M4 ;
        RECT  0 55.872 0.192 55.896 ;
    END
  END di[317]
  PIN di[318]
    DIRECTION INPUT ;
    USE SIGNAL ;
    PORT
      LAYER M4 ;
        RECT  0 56.016 0.192 56.04 ;
    END
  END di[318]
  PIN di[319]
    DIRECTION INPUT ;
    USE SIGNAL ;
    PORT
      LAYER M4 ;
        RECT  0 56.208 0.192 56.232 ;
    END
  END di[319]
  PIN di[31]
    DIRECTION INPUT ;
    USE SIGNAL ;
    PORT
      LAYER M4 ;
        RECT  0 9.456 0.192 9.48 ;
    END
  END di[31]
  PIN di[320]
    DIRECTION INPUT ;
    USE SIGNAL ;
    PORT
      LAYER M4 ;
        RECT  0 56.352 0.192 56.376 ;
    END
  END di[320]
  PIN di[321]
    DIRECTION INPUT ;
    USE SIGNAL ;
    PORT
      LAYER M4 ;
        RECT  0 56.496 0.192 56.52 ;
    END
  END di[321]
  PIN di[322]
    DIRECTION INPUT ;
    USE SIGNAL ;
    PORT
      LAYER M4 ;
        RECT  0 56.688 0.192 56.712 ;
    END
  END di[322]
  PIN di[323]
    DIRECTION INPUT ;
    USE SIGNAL ;
    PORT
      LAYER M4 ;
        RECT  0 56.832 0.192 56.856 ;
    END
  END di[323]
  PIN di[324]
    DIRECTION INPUT ;
    USE SIGNAL ;
    PORT
      LAYER M4 ;
        RECT  0 57.024 0.192 57.048 ;
    END
  END di[324]
  PIN di[325]
    DIRECTION INPUT ;
    USE SIGNAL ;
    PORT
      LAYER M4 ;
        RECT  0 57.168 0.192 57.192 ;
    END
  END di[325]
  PIN di[326]
    DIRECTION INPUT ;
    USE SIGNAL ;
    PORT
      LAYER M4 ;
        RECT  0 57.312 0.192 57.336 ;
    END
  END di[326]
  PIN di[327]
    DIRECTION INPUT ;
    USE SIGNAL ;
    PORT
      LAYER M4 ;
        RECT  0 57.504 0.192 57.528 ;
    END
  END di[327]
  PIN di[328]
    DIRECTION INPUT ;
    USE SIGNAL ;
    PORT
      LAYER M4 ;
        RECT  0 57.648 0.192 57.672 ;
    END
  END di[328]
  PIN di[329]
    DIRECTION INPUT ;
    USE SIGNAL ;
    PORT
      LAYER M4 ;
        RECT  0 57.792 0.192 57.816 ;
    END
  END di[329]
  PIN di[32]
    DIRECTION INPUT ;
    USE SIGNAL ;
    PORT
      LAYER M4 ;
        RECT  0 9.6 0.192 9.624 ;
    END
  END di[32]
  PIN di[330]
    DIRECTION INPUT ;
    USE SIGNAL ;
    PORT
      LAYER M4 ;
        RECT  0 57.984 0.192 58.008 ;
    END
  END di[330]
  PIN di[331]
    DIRECTION INPUT ;
    USE SIGNAL ;
    PORT
      LAYER M4 ;
        RECT  0 58.128 0.192 58.152 ;
    END
  END di[331]
  PIN di[332]
    DIRECTION INPUT ;
    USE SIGNAL ;
    PORT
      LAYER M4 ;
        RECT  0 58.32 0.192 58.344 ;
    END
  END di[332]
  PIN di[333]
    DIRECTION INPUT ;
    USE SIGNAL ;
    PORT
      LAYER M4 ;
        RECT  0 58.464 0.192 58.488 ;
    END
  END di[333]
  PIN di[334]
    DIRECTION INPUT ;
    USE SIGNAL ;
    PORT
      LAYER M4 ;
        RECT  0 58.608 0.192 58.632 ;
    END
  END di[334]
  PIN di[335]
    DIRECTION INPUT ;
    USE SIGNAL ;
    PORT
      LAYER M4 ;
        RECT  0 58.8 0.192 58.824 ;
    END
  END di[335]
  PIN di[336]
    DIRECTION INPUT ;
    USE SIGNAL ;
    PORT
      LAYER M4 ;
        RECT  0 58.944 0.192 58.968 ;
    END
  END di[336]
  PIN di[337]
    DIRECTION INPUT ;
    USE SIGNAL ;
    PORT
      LAYER M4 ;
        RECT  0 59.136 0.192 59.16 ;
    END
  END di[337]
  PIN di[338]
    DIRECTION INPUT ;
    USE SIGNAL ;
    PORT
      LAYER M4 ;
        RECT  0 59.28 0.192 59.304 ;
    END
  END di[338]
  PIN di[339]
    DIRECTION INPUT ;
    USE SIGNAL ;
    PORT
      LAYER M4 ;
        RECT  0 59.424 0.192 59.448 ;
    END
  END di[339]
  PIN di[33]
    DIRECTION INPUT ;
    USE SIGNAL ;
    PORT
      LAYER M4 ;
        RECT  0 9.792 0.192 9.816 ;
    END
  END di[33]
  PIN di[340]
    DIRECTION INPUT ;
    USE SIGNAL ;
    PORT
      LAYER M4 ;
        RECT  0 59.616 0.192 59.64 ;
    END
  END di[340]
  PIN di[341]
    DIRECTION INPUT ;
    USE SIGNAL ;
    PORT
      LAYER M4 ;
        RECT  0 59.76 0.192 59.784 ;
    END
  END di[341]
  PIN di[342]
    DIRECTION INPUT ;
    USE SIGNAL ;
    PORT
      LAYER M4 ;
        RECT  0 59.904 0.192 59.928 ;
    END
  END di[342]
  PIN di[343]
    DIRECTION INPUT ;
    USE SIGNAL ;
    PORT
      LAYER M4 ;
        RECT  0 60.096 0.192 60.12 ;
    END
  END di[343]
  PIN di[344]
    DIRECTION INPUT ;
    USE SIGNAL ;
    PORT
      LAYER M4 ;
        RECT  0 60.24 0.192 60.264 ;
    END
  END di[344]
  PIN di[345]
    DIRECTION INPUT ;
    USE SIGNAL ;
    PORT
      LAYER M4 ;
        RECT  0 60.432 0.192 60.456 ;
    END
  END di[345]
  PIN di[346]
    DIRECTION INPUT ;
    USE SIGNAL ;
    PORT
      LAYER M4 ;
        RECT  0 60.576 0.192 60.6 ;
    END
  END di[346]
  PIN di[347]
    DIRECTION INPUT ;
    USE SIGNAL ;
    PORT
      LAYER M4 ;
        RECT  0 60.72 0.192 60.744 ;
    END
  END di[347]
  PIN di[348]
    DIRECTION INPUT ;
    USE SIGNAL ;
    PORT
      LAYER M4 ;
        RECT  0 60.912 0.192 60.936 ;
    END
  END di[348]
  PIN di[349]
    DIRECTION INPUT ;
    USE SIGNAL ;
    PORT
      LAYER M4 ;
        RECT  0 61.056 0.192 61.08 ;
    END
  END di[349]
  PIN di[34]
    DIRECTION INPUT ;
    USE SIGNAL ;
    PORT
      LAYER M4 ;
        RECT  0 9.936 0.192 9.96 ;
    END
  END di[34]
  PIN di[350]
    DIRECTION INPUT ;
    USE SIGNAL ;
    PORT
      LAYER M4 ;
        RECT  0 61.2 0.192 61.224 ;
    END
  END di[350]
  PIN di[351]
    DIRECTION INPUT ;
    USE SIGNAL ;
    PORT
      LAYER M4 ;
        RECT  0 61.392 0.192 61.416 ;
    END
  END di[351]
  PIN di[352]
    DIRECTION INPUT ;
    USE SIGNAL ;
    PORT
      LAYER M4 ;
        RECT  0 61.536 0.192 61.56 ;
    END
  END di[352]
  PIN di[353]
    DIRECTION INPUT ;
    USE SIGNAL ;
    PORT
      LAYER M4 ;
        RECT  0 61.728 0.192 61.752 ;
    END
  END di[353]
  PIN di[354]
    DIRECTION INPUT ;
    USE SIGNAL ;
    PORT
      LAYER M4 ;
        RECT  0 61.872 0.192 61.896 ;
    END
  END di[354]
  PIN di[355]
    DIRECTION INPUT ;
    USE SIGNAL ;
    PORT
      LAYER M4 ;
        RECT  0 62.016 0.192 62.04 ;
    END
  END di[355]
  PIN di[356]
    DIRECTION INPUT ;
    USE SIGNAL ;
    PORT
      LAYER M4 ;
        RECT  0 62.208 0.192 62.232 ;
    END
  END di[356]
  PIN di[357]
    DIRECTION INPUT ;
    USE SIGNAL ;
    PORT
      LAYER M4 ;
        RECT  0 62.352 0.192 62.376 ;
    END
  END di[357]
  PIN di[358]
    DIRECTION INPUT ;
    USE SIGNAL ;
    PORT
      LAYER M4 ;
        RECT  0 62.544 0.192 62.568 ;
    END
  END di[358]
  PIN di[359]
    DIRECTION INPUT ;
    USE SIGNAL ;
    PORT
      LAYER M4 ;
        RECT  0 62.688 0.192 62.712 ;
    END
  END di[359]
  PIN di[35]
    DIRECTION INPUT ;
    USE SIGNAL ;
    PORT
      LAYER M4 ;
        RECT  0 10.08 0.192 10.104 ;
    END
  END di[35]
  PIN di[360]
    DIRECTION INPUT ;
    USE SIGNAL ;
    PORT
      LAYER M4 ;
        RECT  0 62.832 0.192 62.856 ;
    END
  END di[360]
  PIN di[361]
    DIRECTION INPUT ;
    USE SIGNAL ;
    PORT
      LAYER M4 ;
        RECT  0 63.024 0.192 63.048 ;
    END
  END di[361]
  PIN di[362]
    DIRECTION INPUT ;
    USE SIGNAL ;
    PORT
      LAYER M4 ;
        RECT  0 63.168 0.192 63.192 ;
    END
  END di[362]
  PIN di[363]
    DIRECTION INPUT ;
    USE SIGNAL ;
    PORT
      LAYER M4 ;
        RECT  0 63.312 0.192 63.336 ;
    END
  END di[363]
  PIN di[364]
    DIRECTION INPUT ;
    USE SIGNAL ;
    PORT
      LAYER M4 ;
        RECT  0 63.504 0.192 63.528 ;
    END
  END di[364]
  PIN di[365]
    DIRECTION INPUT ;
    USE SIGNAL ;
    PORT
      LAYER M4 ;
        RECT  0 63.648 0.192 63.672 ;
    END
  END di[365]
  PIN di[366]
    DIRECTION INPUT ;
    USE SIGNAL ;
    PORT
      LAYER M4 ;
        RECT  0 63.84 0.192 63.864 ;
    END
  END di[366]
  PIN di[367]
    DIRECTION INPUT ;
    USE SIGNAL ;
    PORT
      LAYER M4 ;
        RECT  0 63.984 0.192 64.008 ;
    END
  END di[367]
  PIN di[368]
    DIRECTION INPUT ;
    USE SIGNAL ;
    PORT
      LAYER M4 ;
        RECT  0 64.128 0.192 64.152 ;
    END
  END di[368]
  PIN di[369]
    DIRECTION INPUT ;
    USE SIGNAL ;
    PORT
      LAYER M4 ;
        RECT  0 64.32 0.192 64.344 ;
    END
  END di[369]
  PIN di[36]
    DIRECTION INPUT ;
    USE SIGNAL ;
    PORT
      LAYER M4 ;
        RECT  0 10.272 0.192 10.296 ;
    END
  END di[36]
  PIN di[370]
    DIRECTION INPUT ;
    USE SIGNAL ;
    PORT
      LAYER M4 ;
        RECT  0 64.464 0.192 64.488 ;
    END
  END di[370]
  PIN di[371]
    DIRECTION INPUT ;
    USE SIGNAL ;
    PORT
      LAYER M4 ;
        RECT  0 64.608 0.192 64.632 ;
    END
  END di[371]
  PIN di[372]
    DIRECTION INPUT ;
    USE SIGNAL ;
    PORT
      LAYER M4 ;
        RECT  0 64.8 0.192 64.824 ;
    END
  END di[372]
  PIN di[373]
    DIRECTION INPUT ;
    USE SIGNAL ;
    PORT
      LAYER M4 ;
        RECT  0 64.944 0.192 64.968 ;
    END
  END di[373]
  PIN di[374]
    DIRECTION INPUT ;
    USE SIGNAL ;
    PORT
      LAYER M4 ;
        RECT  0 65.136 0.192 65.16 ;
    END
  END di[374]
  PIN di[375]
    DIRECTION INPUT ;
    USE SIGNAL ;
    PORT
      LAYER M4 ;
        RECT  0 65.28 0.192 65.304 ;
    END
  END di[375]
  PIN di[376]
    DIRECTION INPUT ;
    USE SIGNAL ;
    PORT
      LAYER M4 ;
        RECT  0 65.424 0.192 65.448 ;
    END
  END di[376]
  PIN di[377]
    DIRECTION INPUT ;
    USE SIGNAL ;
    PORT
      LAYER M4 ;
        RECT  0 65.616 0.192 65.64 ;
    END
  END di[377]
  PIN di[378]
    DIRECTION INPUT ;
    USE SIGNAL ;
    PORT
      LAYER M4 ;
        RECT  0 65.76 0.192 65.784 ;
    END
  END di[378]
  PIN di[379]
    DIRECTION INPUT ;
    USE SIGNAL ;
    PORT
      LAYER M4 ;
        RECT  0 65.952 0.192 65.976 ;
    END
  END di[379]
  PIN di[37]
    DIRECTION INPUT ;
    USE SIGNAL ;
    PORT
      LAYER M4 ;
        RECT  0 10.416 0.192 10.44 ;
    END
  END di[37]
  PIN di[380]
    DIRECTION INPUT ;
    USE SIGNAL ;
    PORT
      LAYER M4 ;
        RECT  0 66.096 0.192 66.12 ;
    END
  END di[380]
  PIN di[381]
    DIRECTION INPUT ;
    USE SIGNAL ;
    PORT
      LAYER M4 ;
        RECT  0 66.24 0.192 66.264 ;
    END
  END di[381]
  PIN di[382]
    DIRECTION INPUT ;
    USE SIGNAL ;
    PORT
      LAYER M4 ;
        RECT  0 66.432 0.192 66.456 ;
    END
  END di[382]
  PIN di[383]
    DIRECTION INPUT ;
    USE SIGNAL ;
    PORT
      LAYER M4 ;
        RECT  0 66.576 0.192 66.6 ;
    END
  END di[383]
  PIN di[384]
    DIRECTION INPUT ;
    USE SIGNAL ;
    PORT
      LAYER M4 ;
        RECT  0 66.72 0.192 66.744 ;
    END
  END di[384]
  PIN di[385]
    DIRECTION INPUT ;
    USE SIGNAL ;
    PORT
      LAYER M4 ;
        RECT  0 66.912 0.192 66.936 ;
    END
  END di[385]
  PIN di[386]
    DIRECTION INPUT ;
    USE SIGNAL ;
    PORT
      LAYER M4 ;
        RECT  0 67.056 0.192 67.08 ;
    END
  END di[386]
  PIN di[387]
    DIRECTION INPUT ;
    USE SIGNAL ;
    PORT
      LAYER M4 ;
        RECT  0 67.248 0.192 67.272 ;
    END
  END di[387]
  PIN di[388]
    DIRECTION INPUT ;
    USE SIGNAL ;
    PORT
      LAYER M4 ;
        RECT  0 67.392 0.192 67.416 ;
    END
  END di[388]
  PIN di[389]
    DIRECTION INPUT ;
    USE SIGNAL ;
    PORT
      LAYER M4 ;
        RECT  0 67.536 0.192 67.56 ;
    END
  END di[389]
  PIN di[38]
    DIRECTION INPUT ;
    USE SIGNAL ;
    PORT
      LAYER M4 ;
        RECT  0 10.56 0.192 10.584 ;
    END
  END di[38]
  PIN di[390]
    DIRECTION INPUT ;
    USE SIGNAL ;
    PORT
      LAYER M4 ;
        RECT  0 67.728 0.192 67.752 ;
    END
  END di[390]
  PIN di[391]
    DIRECTION INPUT ;
    USE SIGNAL ;
    PORT
      LAYER M4 ;
        RECT  0 67.872 0.192 67.896 ;
    END
  END di[391]
  PIN di[392]
    DIRECTION INPUT ;
    USE SIGNAL ;
    PORT
      LAYER M4 ;
        RECT  0 68.016 0.192 68.04 ;
    END
  END di[392]
  PIN di[393]
    DIRECTION INPUT ;
    USE SIGNAL ;
    PORT
      LAYER M4 ;
        RECT  0 68.208 0.192 68.232 ;
    END
  END di[393]
  PIN di[394]
    DIRECTION INPUT ;
    USE SIGNAL ;
    PORT
      LAYER M4 ;
        RECT  0 68.352 0.192 68.376 ;
    END
  END di[394]
  PIN di[395]
    DIRECTION INPUT ;
    USE SIGNAL ;
    PORT
      LAYER M4 ;
        RECT  0 68.544 0.192 68.568 ;
    END
  END di[395]
  PIN di[396]
    DIRECTION INPUT ;
    USE SIGNAL ;
    PORT
      LAYER M4 ;
        RECT  0 68.688 0.192 68.712 ;
    END
  END di[396]
  PIN di[397]
    DIRECTION INPUT ;
    USE SIGNAL ;
    PORT
      LAYER M4 ;
        RECT  0 68.832 0.192 68.856 ;
    END
  END di[397]
  PIN di[398]
    DIRECTION INPUT ;
    USE SIGNAL ;
    PORT
      LAYER M4 ;
        RECT  0 69.024 0.192 69.048 ;
    END
  END di[398]
  PIN di[399]
    DIRECTION INPUT ;
    USE SIGNAL ;
    PORT
      LAYER M4 ;
        RECT  0 69.168 0.192 69.192 ;
    END
  END di[399]
  PIN di[39]
    DIRECTION INPUT ;
    USE SIGNAL ;
    PORT
      LAYER M4 ;
        RECT  0 10.752 0.192 10.776 ;
    END
  END di[39]
  PIN di[3]
    DIRECTION INPUT ;
    USE SIGNAL ;
    PORT
      LAYER M4 ;
        RECT  0 4.896 0.192 4.92 ;
    END
  END di[3]
  PIN di[400]
    DIRECTION INPUT ;
    USE SIGNAL ;
    PORT
      LAYER M4 ;
        RECT  0 69.36 0.192 69.384 ;
    END
  END di[400]
  PIN di[401]
    DIRECTION INPUT ;
    USE SIGNAL ;
    PORT
      LAYER M4 ;
        RECT  0 69.504 0.192 69.528 ;
    END
  END di[401]
  PIN di[402]
    DIRECTION INPUT ;
    USE SIGNAL ;
    PORT
      LAYER M4 ;
        RECT  0 69.648 0.192 69.672 ;
    END
  END di[402]
  PIN di[403]
    DIRECTION INPUT ;
    USE SIGNAL ;
    PORT
      LAYER M4 ;
        RECT  0 69.84 0.192 69.864 ;
    END
  END di[403]
  PIN di[404]
    DIRECTION INPUT ;
    USE SIGNAL ;
    PORT
      LAYER M4 ;
        RECT  0 69.984 0.192 70.008 ;
    END
  END di[404]
  PIN di[405]
    DIRECTION INPUT ;
    USE SIGNAL ;
    PORT
      LAYER M4 ;
        RECT  0 70.128 0.192 70.152 ;
    END
  END di[405]
  PIN di[406]
    DIRECTION INPUT ;
    USE SIGNAL ;
    PORT
      LAYER M4 ;
        RECT  0 70.32 0.192 70.344 ;
    END
  END di[406]
  PIN di[407]
    DIRECTION INPUT ;
    USE SIGNAL ;
    PORT
      LAYER M4 ;
        RECT  0 70.464 0.192 70.488 ;
    END
  END di[407]
  PIN di[408]
    DIRECTION INPUT ;
    USE SIGNAL ;
    PORT
      LAYER M4 ;
        RECT  0 70.656 0.192 70.68 ;
    END
  END di[408]
  PIN di[409]
    DIRECTION INPUT ;
    USE SIGNAL ;
    PORT
      LAYER M4 ;
        RECT  0 70.8 0.192 70.824 ;
    END
  END di[409]
  PIN di[40]
    DIRECTION INPUT ;
    USE SIGNAL ;
    PORT
      LAYER M4 ;
        RECT  0 10.896 0.192 10.92 ;
    END
  END di[40]
  PIN di[410]
    DIRECTION INPUT ;
    USE SIGNAL ;
    PORT
      LAYER M4 ;
        RECT  0 70.944 0.192 70.968 ;
    END
  END di[410]
  PIN di[411]
    DIRECTION INPUT ;
    USE SIGNAL ;
    PORT
      LAYER M4 ;
        RECT  0 71.136 0.192 71.16 ;
    END
  END di[411]
  PIN di[412]
    DIRECTION INPUT ;
    USE SIGNAL ;
    PORT
      LAYER M4 ;
        RECT  0 71.28 0.192 71.304 ;
    END
  END di[412]
  PIN di[413]
    DIRECTION INPUT ;
    USE SIGNAL ;
    PORT
      LAYER M4 ;
        RECT  0 71.472 0.192 71.496 ;
    END
  END di[413]
  PIN di[414]
    DIRECTION INPUT ;
    USE SIGNAL ;
    PORT
      LAYER M4 ;
        RECT  0 71.616 0.192 71.64 ;
    END
  END di[414]
  PIN di[415]
    DIRECTION INPUT ;
    USE SIGNAL ;
    PORT
      LAYER M4 ;
        RECT  0 71.76 0.192 71.784 ;
    END
  END di[415]
  PIN di[416]
    DIRECTION INPUT ;
    USE SIGNAL ;
    PORT
      LAYER M4 ;
        RECT  0 71.952 0.192 71.976 ;
    END
  END di[416]
  PIN di[417]
    DIRECTION INPUT ;
    USE SIGNAL ;
    PORT
      LAYER M4 ;
        RECT  0 72.096 0.192 72.12 ;
    END
  END di[417]
  PIN di[418]
    DIRECTION INPUT ;
    USE SIGNAL ;
    PORT
      LAYER M4 ;
        RECT  0 72.24 0.192 72.264 ;
    END
  END di[418]
  PIN di[419]
    DIRECTION INPUT ;
    USE SIGNAL ;
    PORT
      LAYER M4 ;
        RECT  0 72.432 0.192 72.456 ;
    END
  END di[419]
  PIN di[41]
    DIRECTION INPUT ;
    USE SIGNAL ;
    PORT
      LAYER M4 ;
        RECT  0 11.088 0.192 11.112 ;
    END
  END di[41]
  PIN di[420]
    DIRECTION INPUT ;
    USE SIGNAL ;
    PORT
      LAYER M4 ;
        RECT  0 72.576 0.192 72.6 ;
    END
  END di[420]
  PIN di[421]
    DIRECTION INPUT ;
    USE SIGNAL ;
    PORT
      LAYER M4 ;
        RECT  0 72.768 0.192 72.792 ;
    END
  END di[421]
  PIN di[422]
    DIRECTION INPUT ;
    USE SIGNAL ;
    PORT
      LAYER M4 ;
        RECT  0 72.912 0.192 72.936 ;
    END
  END di[422]
  PIN di[423]
    DIRECTION INPUT ;
    USE SIGNAL ;
    PORT
      LAYER M4 ;
        RECT  0 73.056 0.192 73.08 ;
    END
  END di[423]
  PIN di[424]
    DIRECTION INPUT ;
    USE SIGNAL ;
    PORT
      LAYER M4 ;
        RECT  0 73.248 0.192 73.272 ;
    END
  END di[424]
  PIN di[425]
    DIRECTION INPUT ;
    USE SIGNAL ;
    PORT
      LAYER M4 ;
        RECT  0 73.392 0.192 73.416 ;
    END
  END di[425]
  PIN di[426]
    DIRECTION INPUT ;
    USE SIGNAL ;
    PORT
      LAYER M4 ;
        RECT  0 73.536 0.192 73.56 ;
    END
  END di[426]
  PIN di[427]
    DIRECTION INPUT ;
    USE SIGNAL ;
    PORT
      LAYER M4 ;
        RECT  0 73.728 0.192 73.752 ;
    END
  END di[427]
  PIN di[428]
    DIRECTION INPUT ;
    USE SIGNAL ;
    PORT
      LAYER M4 ;
        RECT  0 73.872 0.192 73.896 ;
    END
  END di[428]
  PIN di[429]
    DIRECTION INPUT ;
    USE SIGNAL ;
    PORT
      LAYER M4 ;
        RECT  0 74.064 0.192 74.088 ;
    END
  END di[429]
  PIN di[42]
    DIRECTION INPUT ;
    USE SIGNAL ;
    PORT
      LAYER M4 ;
        RECT  0 11.232 0.192 11.256 ;
    END
  END di[42]
  PIN di[430]
    DIRECTION INPUT ;
    USE SIGNAL ;
    PORT
      LAYER M4 ;
        RECT  0 74.208 0.192 74.232 ;
    END
  END di[430]
  PIN di[431]
    DIRECTION INPUT ;
    USE SIGNAL ;
    PORT
      LAYER M4 ;
        RECT  0 74.352 0.192 74.376 ;
    END
  END di[431]
  PIN di[432]
    DIRECTION INPUT ;
    USE SIGNAL ;
    PORT
      LAYER M4 ;
        RECT  0 74.544 0.192 74.568 ;
    END
  END di[432]
  PIN di[433]
    DIRECTION INPUT ;
    USE SIGNAL ;
    PORT
      LAYER M4 ;
        RECT  0 74.688 0.192 74.712 ;
    END
  END di[433]
  PIN di[434]
    DIRECTION INPUT ;
    USE SIGNAL ;
    PORT
      LAYER M4 ;
        RECT  0 74.88 0.192 74.904 ;
    END
  END di[434]
  PIN di[435]
    DIRECTION INPUT ;
    USE SIGNAL ;
    PORT
      LAYER M4 ;
        RECT  0 75.024 0.192 75.048 ;
    END
  END di[435]
  PIN di[436]
    DIRECTION INPUT ;
    USE SIGNAL ;
    PORT
      LAYER M4 ;
        RECT  0 75.168 0.192 75.192 ;
    END
  END di[436]
  PIN di[437]
    DIRECTION INPUT ;
    USE SIGNAL ;
    PORT
      LAYER M4 ;
        RECT  0 75.36 0.192 75.384 ;
    END
  END di[437]
  PIN di[438]
    DIRECTION INPUT ;
    USE SIGNAL ;
    PORT
      LAYER M4 ;
        RECT  0 75.504 0.192 75.528 ;
    END
  END di[438]
  PIN di[439]
    DIRECTION INPUT ;
    USE SIGNAL ;
    PORT
      LAYER M4 ;
        RECT  0 75.648 0.192 75.672 ;
    END
  END di[439]
  PIN di[43]
    DIRECTION INPUT ;
    USE SIGNAL ;
    PORT
      LAYER M4 ;
        RECT  0 11.376 0.192 11.4 ;
    END
  END di[43]
  PIN di[440]
    DIRECTION INPUT ;
    USE SIGNAL ;
    PORT
      LAYER M4 ;
        RECT  0 75.84 0.192 75.864 ;
    END
  END di[440]
  PIN di[441]
    DIRECTION INPUT ;
    USE SIGNAL ;
    PORT
      LAYER M4 ;
        RECT  0 75.984 0.192 76.008 ;
    END
  END di[441]
  PIN di[442]
    DIRECTION INPUT ;
    USE SIGNAL ;
    PORT
      LAYER M4 ;
        RECT  0 76.176 0.192 76.2 ;
    END
  END di[442]
  PIN di[443]
    DIRECTION INPUT ;
    USE SIGNAL ;
    PORT
      LAYER M4 ;
        RECT  0 76.32 0.192 76.344 ;
    END
  END di[443]
  PIN di[444]
    DIRECTION INPUT ;
    USE SIGNAL ;
    PORT
      LAYER M4 ;
        RECT  0 76.464 0.192 76.488 ;
    END
  END di[444]
  PIN di[445]
    DIRECTION INPUT ;
    USE SIGNAL ;
    PORT
      LAYER M4 ;
        RECT  0 76.656 0.192 76.68 ;
    END
  END di[445]
  PIN di[446]
    DIRECTION INPUT ;
    USE SIGNAL ;
    PORT
      LAYER M4 ;
        RECT  0 76.8 0.192 76.824 ;
    END
  END di[446]
  PIN di[447]
    DIRECTION INPUT ;
    USE SIGNAL ;
    PORT
      LAYER M4 ;
        RECT  0 76.944 0.192 76.968 ;
    END
  END di[447]
  PIN di[448]
    DIRECTION INPUT ;
    USE SIGNAL ;
    PORT
      LAYER M4 ;
        RECT  0 77.136 0.192 77.16 ;
    END
  END di[448]
  PIN di[449]
    DIRECTION INPUT ;
    USE SIGNAL ;
    PORT
      LAYER M4 ;
        RECT  0 77.28 0.192 77.304 ;
    END
  END di[449]
  PIN di[44]
    DIRECTION INPUT ;
    USE SIGNAL ;
    PORT
      LAYER M4 ;
        RECT  0 11.568 0.192 11.592 ;
    END
  END di[44]
  PIN di[450]
    DIRECTION INPUT ;
    USE SIGNAL ;
    PORT
      LAYER M4 ;
        RECT  0 77.472 0.192 77.496 ;
    END
  END di[450]
  PIN di[451]
    DIRECTION INPUT ;
    USE SIGNAL ;
    PORT
      LAYER M4 ;
        RECT  0 77.616 0.192 77.64 ;
    END
  END di[451]
  PIN di[452]
    DIRECTION INPUT ;
    USE SIGNAL ;
    PORT
      LAYER M4 ;
        RECT  0 77.76 0.192 77.784 ;
    END
  END di[452]
  PIN di[453]
    DIRECTION INPUT ;
    USE SIGNAL ;
    PORT
      LAYER M4 ;
        RECT  0 77.952 0.192 77.976 ;
    END
  END di[453]
  PIN di[454]
    DIRECTION INPUT ;
    USE SIGNAL ;
    PORT
      LAYER M4 ;
        RECT  0 78.096 0.192 78.12 ;
    END
  END di[454]
  PIN di[455]
    DIRECTION INPUT ;
    USE SIGNAL ;
    PORT
      LAYER M4 ;
        RECT  0 78.288 0.192 78.312 ;
    END
  END di[455]
  PIN di[456]
    DIRECTION INPUT ;
    USE SIGNAL ;
    PORT
      LAYER M4 ;
        RECT  0 78.432 0.192 78.456 ;
    END
  END di[456]
  PIN di[457]
    DIRECTION INPUT ;
    USE SIGNAL ;
    PORT
      LAYER M4 ;
        RECT  0 78.576 0.192 78.6 ;
    END
  END di[457]
  PIN di[458]
    DIRECTION INPUT ;
    USE SIGNAL ;
    PORT
      LAYER M4 ;
        RECT  0 78.768 0.192 78.792 ;
    END
  END di[458]
  PIN di[459]
    DIRECTION INPUT ;
    USE SIGNAL ;
    PORT
      LAYER M4 ;
        RECT  0 78.912 0.192 78.936 ;
    END
  END di[459]
  PIN di[45]
    DIRECTION INPUT ;
    USE SIGNAL ;
    PORT
      LAYER M4 ;
        RECT  0 11.712 0.192 11.736 ;
    END
  END di[45]
  PIN di[460]
    DIRECTION INPUT ;
    USE SIGNAL ;
    PORT
      LAYER M4 ;
        RECT  0 79.056 0.192 79.08 ;
    END
  END di[460]
  PIN di[461]
    DIRECTION INPUT ;
    USE SIGNAL ;
    PORT
      LAYER M4 ;
        RECT  0 79.248 0.192 79.272 ;
    END
  END di[461]
  PIN di[462]
    DIRECTION INPUT ;
    USE SIGNAL ;
    PORT
      LAYER M4 ;
        RECT  0 79.392 0.192 79.416 ;
    END
  END di[462]
  PIN di[463]
    DIRECTION INPUT ;
    USE SIGNAL ;
    PORT
      LAYER M4 ;
        RECT  0 79.584 0.192 79.608 ;
    END
  END di[463]
  PIN di[464]
    DIRECTION INPUT ;
    USE SIGNAL ;
    PORT
      LAYER M4 ;
        RECT  0 79.728 0.192 79.752 ;
    END
  END di[464]
  PIN di[465]
    DIRECTION INPUT ;
    USE SIGNAL ;
    PORT
      LAYER M4 ;
        RECT  0 79.872 0.192 79.896 ;
    END
  END di[465]
  PIN di[466]
    DIRECTION INPUT ;
    USE SIGNAL ;
    PORT
      LAYER M4 ;
        RECT  0 80.064 0.192 80.088 ;
    END
  END di[466]
  PIN di[467]
    DIRECTION INPUT ;
    USE SIGNAL ;
    PORT
      LAYER M4 ;
        RECT  0 80.208 0.192 80.232 ;
    END
  END di[467]
  PIN di[468]
    DIRECTION INPUT ;
    USE SIGNAL ;
    PORT
      LAYER M4 ;
        RECT  0 80.352 0.192 80.376 ;
    END
  END di[468]
  PIN di[469]
    DIRECTION INPUT ;
    USE SIGNAL ;
    PORT
      LAYER M4 ;
        RECT  0 80.544 0.192 80.568 ;
    END
  END di[469]
  PIN di[46]
    DIRECTION INPUT ;
    USE SIGNAL ;
    PORT
      LAYER M4 ;
        RECT  0 11.856 0.192 11.88 ;
    END
  END di[46]
  PIN di[470]
    DIRECTION INPUT ;
    USE SIGNAL ;
    PORT
      LAYER M4 ;
        RECT  0 80.688 0.192 80.712 ;
    END
  END di[470]
  PIN di[471]
    DIRECTION INPUT ;
    USE SIGNAL ;
    PORT
      LAYER M4 ;
        RECT  0 80.88 0.192 80.904 ;
    END
  END di[471]
  PIN di[472]
    DIRECTION INPUT ;
    USE SIGNAL ;
    PORT
      LAYER M4 ;
        RECT  0 81.024 0.192 81.048 ;
    END
  END di[472]
  PIN di[473]
    DIRECTION INPUT ;
    USE SIGNAL ;
    PORT
      LAYER M4 ;
        RECT  0 81.168 0.192 81.192 ;
    END
  END di[473]
  PIN di[474]
    DIRECTION INPUT ;
    USE SIGNAL ;
    PORT
      LAYER M4 ;
        RECT  0 81.36 0.192 81.384 ;
    END
  END di[474]
  PIN di[475]
    DIRECTION INPUT ;
    USE SIGNAL ;
    PORT
      LAYER M4 ;
        RECT  0 81.504 0.192 81.528 ;
    END
  END di[475]
  PIN di[476]
    DIRECTION INPUT ;
    USE SIGNAL ;
    PORT
      LAYER M4 ;
        RECT  0 81.696 0.192 81.72 ;
    END
  END di[476]
  PIN di[477]
    DIRECTION INPUT ;
    USE SIGNAL ;
    PORT
      LAYER M4 ;
        RECT  0 81.84 0.192 81.864 ;
    END
  END di[477]
  PIN di[478]
    DIRECTION INPUT ;
    USE SIGNAL ;
    PORT
      LAYER M4 ;
        RECT  0 81.984 0.192 82.008 ;
    END
  END di[478]
  PIN di[479]
    DIRECTION INPUT ;
    USE SIGNAL ;
    PORT
      LAYER M4 ;
        RECT  0 82.176 0.192 82.2 ;
    END
  END di[479]
  PIN di[47]
    DIRECTION INPUT ;
    USE SIGNAL ;
    PORT
      LAYER M4 ;
        RECT  0 12.048 0.192 12.072 ;
    END
  END di[47]
  PIN di[480]
    DIRECTION INPUT ;
    USE SIGNAL ;
    PORT
      LAYER M4 ;
        RECT  0 82.32 0.192 82.344 ;
    END
  END di[480]
  PIN di[481]
    DIRECTION INPUT ;
    USE SIGNAL ;
    PORT
      LAYER M4 ;
        RECT  0 82.464 0.192 82.488 ;
    END
  END di[481]
  PIN di[482]
    DIRECTION INPUT ;
    USE SIGNAL ;
    PORT
      LAYER M4 ;
        RECT  0 82.656 0.192 82.68 ;
    END
  END di[482]
  PIN di[483]
    DIRECTION INPUT ;
    USE SIGNAL ;
    PORT
      LAYER M4 ;
        RECT  0 82.8 0.192 82.824 ;
    END
  END di[483]
  PIN di[484]
    DIRECTION INPUT ;
    USE SIGNAL ;
    PORT
      LAYER M4 ;
        RECT  0 82.992 0.192 83.016 ;
    END
  END di[484]
  PIN di[485]
    DIRECTION INPUT ;
    USE SIGNAL ;
    PORT
      LAYER M4 ;
        RECT  0 83.136 0.192 83.16 ;
    END
  END di[485]
  PIN di[486]
    DIRECTION INPUT ;
    USE SIGNAL ;
    PORT
      LAYER M4 ;
        RECT  0 83.28 0.192 83.304 ;
    END
  END di[486]
  PIN di[487]
    DIRECTION INPUT ;
    USE SIGNAL ;
    PORT
      LAYER M4 ;
        RECT  0 83.472 0.192 83.496 ;
    END
  END di[487]
  PIN di[488]
    DIRECTION INPUT ;
    USE SIGNAL ;
    PORT
      LAYER M4 ;
        RECT  0 83.616 0.192 83.64 ;
    END
  END di[488]
  PIN di[489]
    DIRECTION INPUT ;
    USE SIGNAL ;
    PORT
      LAYER M4 ;
        RECT  0 83.76 0.192 83.784 ;
    END
  END di[489]
  PIN di[48]
    DIRECTION INPUT ;
    USE SIGNAL ;
    PORT
      LAYER M4 ;
        RECT  0 12.192 0.192 12.216 ;
    END
  END di[48]
  PIN di[490]
    DIRECTION INPUT ;
    USE SIGNAL ;
    PORT
      LAYER M4 ;
        RECT  0 83.952 0.192 83.976 ;
    END
  END di[490]
  PIN di[491]
    DIRECTION INPUT ;
    USE SIGNAL ;
    PORT
      LAYER M4 ;
        RECT  0 84.096 0.192 84.12 ;
    END
  END di[491]
  PIN di[492]
    DIRECTION INPUT ;
    USE SIGNAL ;
    PORT
      LAYER M4 ;
        RECT  0 84.288 0.192 84.312 ;
    END
  END di[492]
  PIN di[493]
    DIRECTION INPUT ;
    USE SIGNAL ;
    PORT
      LAYER M4 ;
        RECT  0 84.432 0.192 84.456 ;
    END
  END di[493]
  PIN di[494]
    DIRECTION INPUT ;
    USE SIGNAL ;
    PORT
      LAYER M4 ;
        RECT  0 84.576 0.192 84.6 ;
    END
  END di[494]
  PIN di[495]
    DIRECTION INPUT ;
    USE SIGNAL ;
    PORT
      LAYER M4 ;
        RECT  0 84.768 0.192 84.792 ;
    END
  END di[495]
  PIN di[496]
    DIRECTION INPUT ;
    USE SIGNAL ;
    PORT
      LAYER M4 ;
        RECT  0 84.912 0.192 84.936 ;
    END
  END di[496]
  PIN di[497]
    DIRECTION INPUT ;
    USE SIGNAL ;
    PORT
      LAYER M4 ;
        RECT  0 85.104 0.192 85.128 ;
    END
  END di[497]
  PIN di[498]
    DIRECTION INPUT ;
    USE SIGNAL ;
    PORT
      LAYER M4 ;
        RECT  0 85.248 0.192 85.272 ;
    END
  END di[498]
  PIN di[499]
    DIRECTION INPUT ;
    USE SIGNAL ;
    PORT
      LAYER M4 ;
        RECT  0 85.392 0.192 85.416 ;
    END
  END di[499]
  PIN di[49]
    DIRECTION INPUT ;
    USE SIGNAL ;
    PORT
      LAYER M4 ;
        RECT  0 12.384 0.192 12.408 ;
    END
  END di[49]
  PIN di[4]
    DIRECTION INPUT ;
    USE SIGNAL ;
    PORT
      LAYER M4 ;
        RECT  0 5.04 0.192 5.064 ;
    END
  END di[4]
  PIN di[500]
    DIRECTION INPUT ;
    USE SIGNAL ;
    PORT
      LAYER M4 ;
        RECT  0 85.584 0.192 85.608 ;
    END
  END di[500]
  PIN di[501]
    DIRECTION INPUT ;
    USE SIGNAL ;
    PORT
      LAYER M4 ;
        RECT  0 85.728 0.192 85.752 ;
    END
  END di[501]
  PIN di[502]
    DIRECTION INPUT ;
    USE SIGNAL ;
    PORT
      LAYER M4 ;
        RECT  0 85.872 0.192 85.896 ;
    END
  END di[502]
  PIN di[503]
    DIRECTION INPUT ;
    USE SIGNAL ;
    PORT
      LAYER M4 ;
        RECT  0 86.064 0.192 86.088 ;
    END
  END di[503]
  PIN di[504]
    DIRECTION INPUT ;
    USE SIGNAL ;
    PORT
      LAYER M4 ;
        RECT  0 86.208 0.192 86.232 ;
    END
  END di[504]
  PIN di[505]
    DIRECTION INPUT ;
    USE SIGNAL ;
    PORT
      LAYER M4 ;
        RECT  0 86.4 0.192 86.424 ;
    END
  END di[505]
  PIN di[506]
    DIRECTION INPUT ;
    USE SIGNAL ;
    PORT
      LAYER M4 ;
        RECT  0 86.544 0.192 86.568 ;
    END
  END di[506]
  PIN di[507]
    DIRECTION INPUT ;
    USE SIGNAL ;
    PORT
      LAYER M4 ;
        RECT  0 86.688 0.192 86.712 ;
    END
  END di[507]
  PIN di[508]
    DIRECTION INPUT ;
    USE SIGNAL ;
    PORT
      LAYER M4 ;
        RECT  0 86.88 0.192 86.904 ;
    END
  END di[508]
  PIN di[509]
    DIRECTION INPUT ;
    USE SIGNAL ;
    PORT
      LAYER M4 ;
        RECT  0 87.024 0.192 87.048 ;
    END
  END di[509]
  PIN di[50]
    DIRECTION INPUT ;
    USE SIGNAL ;
    PORT
      LAYER M4 ;
        RECT  0 12.528 0.192 12.552 ;
    END
  END di[50]
  PIN di[510]
    DIRECTION INPUT ;
    USE SIGNAL ;
    PORT
      LAYER M4 ;
        RECT  0 87.216 0.192 87.24 ;
    END
  END di[510]
  PIN di[511]
    DIRECTION INPUT ;
    USE SIGNAL ;
    PORT
      LAYER M4 ;
        RECT  0 87.36 0.192 87.384 ;
    END
  END di[511]
  PIN di[512]
    DIRECTION INPUT ;
    USE SIGNAL ;
    PORT
      LAYER M4 ;
        RECT  0 87.504 0.192 87.528 ;
    END
  END di[512]
  PIN di[513]
    DIRECTION INPUT ;
    USE SIGNAL ;
    PORT
      LAYER M4 ;
        RECT  0 87.696 0.192 87.72 ;
    END
  END di[513]
  PIN di[514]
    DIRECTION INPUT ;
    USE SIGNAL ;
    PORT
      LAYER M4 ;
        RECT  0 87.84 0.192 87.864 ;
    END
  END di[514]
  PIN di[515]
    DIRECTION INPUT ;
    USE SIGNAL ;
    PORT
      LAYER M4 ;
        RECT  0 87.984 0.192 88.008 ;
    END
  END di[515]
  PIN di[516]
    DIRECTION INPUT ;
    USE SIGNAL ;
    PORT
      LAYER M4 ;
        RECT  0 88.176 0.192 88.2 ;
    END
  END di[516]
  PIN di[517]
    DIRECTION INPUT ;
    USE SIGNAL ;
    PORT
      LAYER M4 ;
        RECT  0 88.32 0.192 88.344 ;
    END
  END di[517]
  PIN di[518]
    DIRECTION INPUT ;
    USE SIGNAL ;
    PORT
      LAYER M4 ;
        RECT  0 88.512 0.192 88.536 ;
    END
  END di[518]
  PIN di[519]
    DIRECTION INPUT ;
    USE SIGNAL ;
    PORT
      LAYER M4 ;
        RECT  0 88.656 0.192 88.68 ;
    END
  END di[519]
  PIN di[51]
    DIRECTION INPUT ;
    USE SIGNAL ;
    PORT
      LAYER M4 ;
        RECT  0 12.672 0.192 12.696 ;
    END
  END di[51]
  PIN di[520]
    DIRECTION INPUT ;
    USE SIGNAL ;
    PORT
      LAYER M4 ;
        RECT  0 88.8 0.192 88.824 ;
    END
  END di[520]
  PIN di[521]
    DIRECTION INPUT ;
    USE SIGNAL ;
    PORT
      LAYER M4 ;
        RECT  0 88.992 0.192 89.016 ;
    END
  END di[521]
  PIN di[522]
    DIRECTION INPUT ;
    USE SIGNAL ;
    PORT
      LAYER M4 ;
        RECT  0 89.136 0.192 89.16 ;
    END
  END di[522]
  PIN di[523]
    DIRECTION INPUT ;
    USE SIGNAL ;
    PORT
      LAYER M4 ;
        RECT  0 89.28 0.192 89.304 ;
    END
  END di[523]
  PIN di[524]
    DIRECTION INPUT ;
    USE SIGNAL ;
    PORT
      LAYER M4 ;
        RECT  0 89.472 0.192 89.496 ;
    END
  END di[524]
  PIN di[525]
    DIRECTION INPUT ;
    USE SIGNAL ;
    PORT
      LAYER M4 ;
        RECT  0 89.616 0.192 89.64 ;
    END
  END di[525]
  PIN di[526]
    DIRECTION INPUT ;
    USE SIGNAL ;
    PORT
      LAYER M4 ;
        RECT  0 89.808 0.192 89.832 ;
    END
  END di[526]
  PIN di[527]
    DIRECTION INPUT ;
    USE SIGNAL ;
    PORT
      LAYER M4 ;
        RECT  0 89.952 0.192 89.976 ;
    END
  END di[527]
  PIN di[528]
    DIRECTION INPUT ;
    USE SIGNAL ;
    PORT
      LAYER M4 ;
        RECT  0 90.096 0.192 90.12 ;
    END
  END di[528]
  PIN di[529]
    DIRECTION INPUT ;
    USE SIGNAL ;
    PORT
      LAYER M4 ;
        RECT  0 90.288 0.192 90.312 ;
    END
  END di[529]
  PIN di[52]
    DIRECTION INPUT ;
    USE SIGNAL ;
    PORT
      LAYER M4 ;
        RECT  0 12.864 0.192 12.888 ;
    END
  END di[52]
  PIN di[530]
    DIRECTION INPUT ;
    USE SIGNAL ;
    PORT
      LAYER M4 ;
        RECT  0 90.432 0.192 90.456 ;
    END
  END di[530]
  PIN di[531]
    DIRECTION INPUT ;
    USE SIGNAL ;
    PORT
      LAYER M4 ;
        RECT  0 90.624 0.192 90.648 ;
    END
  END di[531]
  PIN di[532]
    DIRECTION INPUT ;
    USE SIGNAL ;
    PORT
      LAYER M4 ;
        RECT  0 90.768 0.192 90.792 ;
    END
  END di[532]
  PIN di[533]
    DIRECTION INPUT ;
    USE SIGNAL ;
    PORT
      LAYER M4 ;
        RECT  0 90.912 0.192 90.936 ;
    END
  END di[533]
  PIN di[534]
    DIRECTION INPUT ;
    USE SIGNAL ;
    PORT
      LAYER M4 ;
        RECT  0 91.104 0.192 91.128 ;
    END
  END di[534]
  PIN di[535]
    DIRECTION INPUT ;
    USE SIGNAL ;
    PORT
      LAYER M4 ;
        RECT  0 91.248 0.192 91.272 ;
    END
  END di[535]
  PIN di[536]
    DIRECTION INPUT ;
    USE SIGNAL ;
    PORT
      LAYER M4 ;
        RECT  0 91.392 0.192 91.416 ;
    END
  END di[536]
  PIN di[537]
    DIRECTION INPUT ;
    USE SIGNAL ;
    PORT
      LAYER M4 ;
        RECT  0 91.584 0.192 91.608 ;
    END
  END di[537]
  PIN di[538]
    DIRECTION INPUT ;
    USE SIGNAL ;
    PORT
      LAYER M4 ;
        RECT  0 91.728 0.192 91.752 ;
    END
  END di[538]
  PIN di[539]
    DIRECTION INPUT ;
    USE SIGNAL ;
    PORT
      LAYER M4 ;
        RECT  0 91.92 0.192 91.944 ;
    END
  END di[539]
  PIN di[53]
    DIRECTION INPUT ;
    USE SIGNAL ;
    PORT
      LAYER M4 ;
        RECT  0 13.008 0.192 13.032 ;
    END
  END di[53]
  PIN di[540]
    DIRECTION INPUT ;
    USE SIGNAL ;
    PORT
      LAYER M4 ;
        RECT  0 92.064 0.192 92.088 ;
    END
  END di[540]
  PIN di[541]
    DIRECTION INPUT ;
    USE SIGNAL ;
    PORT
      LAYER M4 ;
        RECT  0 92.208 0.192 92.232 ;
    END
  END di[541]
  PIN di[542]
    DIRECTION INPUT ;
    USE SIGNAL ;
    PORT
      LAYER M4 ;
        RECT  0 92.4 0.192 92.424 ;
    END
  END di[542]
  PIN di[543]
    DIRECTION INPUT ;
    USE SIGNAL ;
    PORT
      LAYER M4 ;
        RECT  0 92.544 0.192 92.568 ;
    END
  END di[543]
  PIN di[544]
    DIRECTION INPUT ;
    USE SIGNAL ;
    PORT
      LAYER M4 ;
        RECT  0 92.688 0.192 92.712 ;
    END
  END di[544]
  PIN di[545]
    DIRECTION INPUT ;
    USE SIGNAL ;
    PORT
      LAYER M4 ;
        RECT  0 92.88 0.192 92.904 ;
    END
  END di[545]
  PIN di[546]
    DIRECTION INPUT ;
    USE SIGNAL ;
    PORT
      LAYER M4 ;
        RECT  0 93.024 0.192 93.048 ;
    END
  END di[546]
  PIN di[547]
    DIRECTION INPUT ;
    USE SIGNAL ;
    PORT
      LAYER M4 ;
        RECT  0 93.216 0.192 93.24 ;
    END
  END di[547]
  PIN di[548]
    DIRECTION INPUT ;
    USE SIGNAL ;
    PORT
      LAYER M4 ;
        RECT  0 93.36 0.192 93.384 ;
    END
  END di[548]
  PIN di[549]
    DIRECTION INPUT ;
    USE SIGNAL ;
    PORT
      LAYER M4 ;
        RECT  0 93.504 0.192 93.528 ;
    END
  END di[549]
  PIN di[54]
    DIRECTION INPUT ;
    USE SIGNAL ;
    PORT
      LAYER M4 ;
        RECT  0 13.2 0.192 13.224 ;
    END
  END di[54]
  PIN di[550]
    DIRECTION INPUT ;
    USE SIGNAL ;
    PORT
      LAYER M4 ;
        RECT  0 93.696 0.192 93.72 ;
    END
  END di[550]
  PIN di[551]
    DIRECTION INPUT ;
    USE SIGNAL ;
    PORT
      LAYER M4 ;
        RECT  0 93.84 0.192 93.864 ;
    END
  END di[551]
  PIN di[552]
    DIRECTION INPUT ;
    USE SIGNAL ;
    PORT
      LAYER M4 ;
        RECT  0 94.032 0.192 94.056 ;
    END
  END di[552]
  PIN di[553]
    DIRECTION INPUT ;
    USE SIGNAL ;
    PORT
      LAYER M4 ;
        RECT  0 94.176 0.192 94.2 ;
    END
  END di[553]
  PIN di[554]
    DIRECTION INPUT ;
    USE SIGNAL ;
    PORT
      LAYER M4 ;
        RECT  0 94.32 0.192 94.344 ;
    END
  END di[554]
  PIN di[555]
    DIRECTION INPUT ;
    USE SIGNAL ;
    PORT
      LAYER M4 ;
        RECT  0 94.512 0.192 94.536 ;
    END
  END di[555]
  PIN di[556]
    DIRECTION INPUT ;
    USE SIGNAL ;
    PORT
      LAYER M4 ;
        RECT  0 94.656 0.192 94.68 ;
    END
  END di[556]
  PIN di[557]
    DIRECTION INPUT ;
    USE SIGNAL ;
    PORT
      LAYER M4 ;
        RECT  0 94.8 0.192 94.824 ;
    END
  END di[557]
  PIN di[558]
    DIRECTION INPUT ;
    USE SIGNAL ;
    PORT
      LAYER M4 ;
        RECT  0 94.992 0.192 95.016 ;
    END
  END di[558]
  PIN di[559]
    DIRECTION INPUT ;
    USE SIGNAL ;
    PORT
      LAYER M4 ;
        RECT  0 95.136 0.192 95.16 ;
    END
  END di[559]
  PIN di[55]
    DIRECTION INPUT ;
    USE SIGNAL ;
    PORT
      LAYER M4 ;
        RECT  0 13.344 0.192 13.368 ;
    END
  END di[55]
  PIN di[560]
    DIRECTION INPUT ;
    USE SIGNAL ;
    PORT
      LAYER M4 ;
        RECT  0 95.328 0.192 95.352 ;
    END
  END di[560]
  PIN di[561]
    DIRECTION INPUT ;
    USE SIGNAL ;
    PORT
      LAYER M4 ;
        RECT  0 95.472 0.192 95.496 ;
    END
  END di[561]
  PIN di[562]
    DIRECTION INPUT ;
    USE SIGNAL ;
    PORT
      LAYER M4 ;
        RECT  0 95.616 0.192 95.64 ;
    END
  END di[562]
  PIN di[563]
    DIRECTION INPUT ;
    USE SIGNAL ;
    PORT
      LAYER M4 ;
        RECT  0 95.808 0.192 95.832 ;
    END
  END di[563]
  PIN di[564]
    DIRECTION INPUT ;
    USE SIGNAL ;
    PORT
      LAYER M4 ;
        RECT  0 95.952 0.192 95.976 ;
    END
  END di[564]
  PIN di[565]
    DIRECTION INPUT ;
    USE SIGNAL ;
    PORT
      LAYER M4 ;
        RECT  0 96.096 0.192 96.12 ;
    END
  END di[565]
  PIN di[566]
    DIRECTION INPUT ;
    USE SIGNAL ;
    PORT
      LAYER M4 ;
        RECT  0 96.288 0.192 96.312 ;
    END
  END di[566]
  PIN di[567]
    DIRECTION INPUT ;
    USE SIGNAL ;
    PORT
      LAYER M4 ;
        RECT  0 96.432 0.192 96.456 ;
    END
  END di[567]
  PIN di[568]
    DIRECTION INPUT ;
    USE SIGNAL ;
    PORT
      LAYER M4 ;
        RECT  0 96.624 0.192 96.648 ;
    END
  END di[568]
  PIN di[569]
    DIRECTION INPUT ;
    USE SIGNAL ;
    PORT
      LAYER M4 ;
        RECT  0 96.768 0.192 96.792 ;
    END
  END di[569]
  PIN di[56]
    DIRECTION INPUT ;
    USE SIGNAL ;
    PORT
      LAYER M4 ;
        RECT  0 13.488 0.192 13.512 ;
    END
  END di[56]
  PIN di[570]
    DIRECTION INPUT ;
    USE SIGNAL ;
    PORT
      LAYER M4 ;
        RECT  0 96.912 0.192 96.936 ;
    END
  END di[570]
  PIN di[571]
    DIRECTION INPUT ;
    USE SIGNAL ;
    PORT
      LAYER M4 ;
        RECT  0 97.104 0.192 97.128 ;
    END
  END di[571]
  PIN di[572]
    DIRECTION INPUT ;
    USE SIGNAL ;
    PORT
      LAYER M4 ;
        RECT  0 97.248 0.192 97.272 ;
    END
  END di[572]
  PIN di[573]
    DIRECTION INPUT ;
    USE SIGNAL ;
    PORT
      LAYER M4 ;
        RECT  0 97.44 0.192 97.464 ;
    END
  END di[573]
  PIN di[574]
    DIRECTION INPUT ;
    USE SIGNAL ;
    PORT
      LAYER M4 ;
        RECT  0 97.584 0.192 97.608 ;
    END
  END di[574]
  PIN di[575]
    DIRECTION INPUT ;
    USE SIGNAL ;
    PORT
      LAYER M4 ;
        RECT  0 97.728 0.192 97.752 ;
    END
  END di[575]
  PIN di[576]
    DIRECTION INPUT ;
    USE SIGNAL ;
    PORT
      LAYER M4 ;
        RECT  0 97.92 0.192 97.944 ;
    END
  END di[576]
  PIN di[577]
    DIRECTION INPUT ;
    USE SIGNAL ;
    PORT
      LAYER M4 ;
        RECT  0 98.064 0.192 98.088 ;
    END
  END di[577]
  PIN di[578]
    DIRECTION INPUT ;
    USE SIGNAL ;
    PORT
      LAYER M4 ;
        RECT  0 98.208 0.192 98.232 ;
    END
  END di[578]
  PIN di[579]
    DIRECTION INPUT ;
    USE SIGNAL ;
    PORT
      LAYER M4 ;
        RECT  0 98.4 0.192 98.424 ;
    END
  END di[579]
  PIN di[57]
    DIRECTION INPUT ;
    USE SIGNAL ;
    PORT
      LAYER M4 ;
        RECT  0 13.68 0.192 13.704 ;
    END
  END di[57]
  PIN di[580]
    DIRECTION INPUT ;
    USE SIGNAL ;
    PORT
      LAYER M4 ;
        RECT  0 98.544 0.192 98.568 ;
    END
  END di[580]
  PIN di[581]
    DIRECTION INPUT ;
    USE SIGNAL ;
    PORT
      LAYER M4 ;
        RECT  0 98.736 0.192 98.76 ;
    END
  END di[581]
  PIN di[582]
    DIRECTION INPUT ;
    USE SIGNAL ;
    PORT
      LAYER M4 ;
        RECT  0 98.88 0.192 98.904 ;
    END
  END di[582]
  PIN di[583]
    DIRECTION INPUT ;
    USE SIGNAL ;
    PORT
      LAYER M4 ;
        RECT  0 99.024 0.192 99.048 ;
    END
  END di[583]
  PIN di[584]
    DIRECTION INPUT ;
    USE SIGNAL ;
    PORT
      LAYER M4 ;
        RECT  0 99.216 0.192 99.24 ;
    END
  END di[584]
  PIN di[585]
    DIRECTION INPUT ;
    USE SIGNAL ;
    PORT
      LAYER M4 ;
        RECT  0 99.36 0.192 99.384 ;
    END
  END di[585]
  PIN di[586]
    DIRECTION INPUT ;
    USE SIGNAL ;
    PORT
      LAYER M4 ;
        RECT  0 99.552 0.192 99.576 ;
    END
  END di[586]
  PIN di[587]
    DIRECTION INPUT ;
    USE SIGNAL ;
    PORT
      LAYER M4 ;
        RECT  0 99.696 0.192 99.72 ;
    END
  END di[587]
  PIN di[588]
    DIRECTION INPUT ;
    USE SIGNAL ;
    PORT
      LAYER M4 ;
        RECT  0 99.84 0.192 99.864 ;
    END
  END di[588]
  PIN di[589]
    DIRECTION INPUT ;
    USE SIGNAL ;
    PORT
      LAYER M4 ;
        RECT  0 100.032 0.192 100.056 ;
    END
  END di[589]
  PIN di[58]
    DIRECTION INPUT ;
    USE SIGNAL ;
    PORT
      LAYER M4 ;
        RECT  0 13.824 0.192 13.848 ;
    END
  END di[58]
  PIN di[590]
    DIRECTION INPUT ;
    USE SIGNAL ;
    PORT
      LAYER M4 ;
        RECT  0 100.176 0.192 100.2 ;
    END
  END di[590]
  PIN di[591]
    DIRECTION INPUT ;
    USE SIGNAL ;
    PORT
      LAYER M4 ;
        RECT  0 100.32 0.192 100.344 ;
    END
  END di[591]
  PIN di[592]
    DIRECTION INPUT ;
    USE SIGNAL ;
    PORT
      LAYER M4 ;
        RECT  0 100.512 0.192 100.536 ;
    END
  END di[592]
  PIN di[593]
    DIRECTION INPUT ;
    USE SIGNAL ;
    PORT
      LAYER M4 ;
        RECT  0 100.656 0.192 100.68 ;
    END
  END di[593]
  PIN di[594]
    DIRECTION INPUT ;
    USE SIGNAL ;
    PORT
      LAYER M4 ;
        RECT  0 100.848 0.192 100.872 ;
    END
  END di[594]
  PIN di[595]
    DIRECTION INPUT ;
    USE SIGNAL ;
    PORT
      LAYER M4 ;
        RECT  0 100.992 0.192 101.016 ;
    END
  END di[595]
  PIN di[596]
    DIRECTION INPUT ;
    USE SIGNAL ;
    PORT
      LAYER M4 ;
        RECT  0 101.136 0.192 101.16 ;
    END
  END di[596]
  PIN di[597]
    DIRECTION INPUT ;
    USE SIGNAL ;
    PORT
      LAYER M4 ;
        RECT  0 101.328 0.192 101.352 ;
    END
  END di[597]
  PIN di[598]
    DIRECTION INPUT ;
    USE SIGNAL ;
    PORT
      LAYER M4 ;
        RECT  0 101.472 0.192 101.496 ;
    END
  END di[598]
  PIN di[599]
    DIRECTION INPUT ;
    USE SIGNAL ;
    PORT
      LAYER M4 ;
        RECT  0 101.616 0.192 101.64 ;
    END
  END di[599]
  PIN di[59]
    DIRECTION INPUT ;
    USE SIGNAL ;
    PORT
      LAYER M4 ;
        RECT  0 13.968 0.192 13.992 ;
    END
  END di[59]
  PIN di[5]
    DIRECTION INPUT ;
    USE SIGNAL ;
    PORT
      LAYER M4 ;
        RECT  0 5.232 0.192 5.256 ;
    END
  END di[5]
  PIN di[600]
    DIRECTION INPUT ;
    USE SIGNAL ;
    PORT
      LAYER M4 ;
        RECT  0 101.808 0.192 101.832 ;
    END
  END di[600]
  PIN di[601]
    DIRECTION INPUT ;
    USE SIGNAL ;
    PORT
      LAYER M4 ;
        RECT  0 101.952 0.192 101.976 ;
    END
  END di[601]
  PIN di[602]
    DIRECTION INPUT ;
    USE SIGNAL ;
    PORT
      LAYER M4 ;
        RECT  0 102.144 0.192 102.168 ;
    END
  END di[602]
  PIN di[603]
    DIRECTION INPUT ;
    USE SIGNAL ;
    PORT
      LAYER M4 ;
        RECT  0 102.288 0.192 102.312 ;
    END
  END di[603]
  PIN di[604]
    DIRECTION INPUT ;
    USE SIGNAL ;
    PORT
      LAYER M4 ;
        RECT  0 102.432 0.192 102.456 ;
    END
  END di[604]
  PIN di[605]
    DIRECTION INPUT ;
    USE SIGNAL ;
    PORT
      LAYER M4 ;
        RECT  0 102.624 0.192 102.648 ;
    END
  END di[605]
  PIN di[606]
    DIRECTION INPUT ;
    USE SIGNAL ;
    PORT
      LAYER M4 ;
        RECT  0 102.768 0.192 102.792 ;
    END
  END di[606]
  PIN di[607]
    DIRECTION INPUT ;
    USE SIGNAL ;
    PORT
      LAYER M4 ;
        RECT  0 102.96 0.192 102.984 ;
    END
  END di[607]
  PIN di[608]
    DIRECTION INPUT ;
    USE SIGNAL ;
    PORT
      LAYER M4 ;
        RECT  0 103.104 0.192 103.128 ;
    END
  END di[608]
  PIN di[609]
    DIRECTION INPUT ;
    USE SIGNAL ;
    PORT
      LAYER M4 ;
        RECT  0 103.248 0.192 103.272 ;
    END
  END di[609]
  PIN di[60]
    DIRECTION INPUT ;
    USE SIGNAL ;
    PORT
      LAYER M4 ;
        RECT  0 14.16 0.192 14.184 ;
    END
  END di[60]
  PIN di[610]
    DIRECTION INPUT ;
    USE SIGNAL ;
    PORT
      LAYER M4 ;
        RECT  0 103.44 0.192 103.464 ;
    END
  END di[610]
  PIN di[611]
    DIRECTION INPUT ;
    USE SIGNAL ;
    PORT
      LAYER M4 ;
        RECT  0 103.584 0.192 103.608 ;
    END
  END di[611]
  PIN di[612]
    DIRECTION INPUT ;
    USE SIGNAL ;
    PORT
      LAYER M4 ;
        RECT  0 103.728 0.192 103.752 ;
    END
  END di[612]
  PIN di[613]
    DIRECTION INPUT ;
    USE SIGNAL ;
    PORT
      LAYER M4 ;
        RECT  0 103.92 0.192 103.944 ;
    END
  END di[613]
  PIN di[614]
    DIRECTION INPUT ;
    USE SIGNAL ;
    PORT
      LAYER M4 ;
        RECT  0 104.064 0.192 104.088 ;
    END
  END di[614]
  PIN di[615]
    DIRECTION INPUT ;
    USE SIGNAL ;
    PORT
      LAYER M4 ;
        RECT  0 104.256 0.192 104.28 ;
    END
  END di[615]
  PIN di[616]
    DIRECTION INPUT ;
    USE SIGNAL ;
    PORT
      LAYER M4 ;
        RECT  0 104.4 0.192 104.424 ;
    END
  END di[616]
  PIN di[617]
    DIRECTION INPUT ;
    USE SIGNAL ;
    PORT
      LAYER M4 ;
        RECT  0 104.544 0.192 104.568 ;
    END
  END di[617]
  PIN di[618]
    DIRECTION INPUT ;
    USE SIGNAL ;
    PORT
      LAYER M4 ;
        RECT  0 104.736 0.192 104.76 ;
    END
  END di[618]
  PIN di[619]
    DIRECTION INPUT ;
    USE SIGNAL ;
    PORT
      LAYER M4 ;
        RECT  0 104.88 0.192 104.904 ;
    END
  END di[619]
  PIN di[61]
    DIRECTION INPUT ;
    USE SIGNAL ;
    PORT
      LAYER M4 ;
        RECT  0 14.304 0.192 14.328 ;
    END
  END di[61]
  PIN di[620]
    DIRECTION INPUT ;
    USE SIGNAL ;
    PORT
      LAYER M4 ;
        RECT  0 105.024 0.192 105.048 ;
    END
  END di[620]
  PIN di[621]
    DIRECTION INPUT ;
    USE SIGNAL ;
    PORT
      LAYER M4 ;
        RECT  0 105.216 0.192 105.24 ;
    END
  END di[621]
  PIN di[622]
    DIRECTION INPUT ;
    USE SIGNAL ;
    PORT
      LAYER M4 ;
        RECT  0 105.36 0.192 105.384 ;
    END
  END di[622]
  PIN di[623]
    DIRECTION INPUT ;
    USE SIGNAL ;
    PORT
      LAYER M4 ;
        RECT  0 105.552 0.192 105.576 ;
    END
  END di[623]
  PIN di[624]
    DIRECTION INPUT ;
    USE SIGNAL ;
    PORT
      LAYER M4 ;
        RECT  0 105.696 0.192 105.72 ;
    END
  END di[624]
  PIN di[625]
    DIRECTION INPUT ;
    USE SIGNAL ;
    PORT
      LAYER M4 ;
        RECT  0 105.84 0.192 105.864 ;
    END
  END di[625]
  PIN di[626]
    DIRECTION INPUT ;
    USE SIGNAL ;
    PORT
      LAYER M4 ;
        RECT  0 106.032 0.192 106.056 ;
    END
  END di[626]
  PIN di[627]
    DIRECTION INPUT ;
    USE SIGNAL ;
    PORT
      LAYER M4 ;
        RECT  0 106.176 0.192 106.2 ;
    END
  END di[627]
  PIN di[628]
    DIRECTION INPUT ;
    USE SIGNAL ;
    PORT
      LAYER M4 ;
        RECT  0 106.368 0.192 106.392 ;
    END
  END di[628]
  PIN di[629]
    DIRECTION INPUT ;
    USE SIGNAL ;
    PORT
      LAYER M4 ;
        RECT  0 106.512 0.192 106.536 ;
    END
  END di[629]
  PIN di[62]
    DIRECTION INPUT ;
    USE SIGNAL ;
    PORT
      LAYER M4 ;
        RECT  0 14.496 0.192 14.52 ;
    END
  END di[62]
  PIN di[630]
    DIRECTION INPUT ;
    USE SIGNAL ;
    PORT
      LAYER M4 ;
        RECT  0 106.656 0.192 106.68 ;
    END
  END di[630]
  PIN di[631]
    DIRECTION INPUT ;
    USE SIGNAL ;
    PORT
      LAYER M4 ;
        RECT  0 106.848 0.192 106.872 ;
    END
  END di[631]
  PIN di[632]
    DIRECTION INPUT ;
    USE SIGNAL ;
    PORT
      LAYER M4 ;
        RECT  0 106.992 0.192 107.016 ;
    END
  END di[632]
  PIN di[633]
    DIRECTION INPUT ;
    USE SIGNAL ;
    PORT
      LAYER M4 ;
        RECT  0 107.136 0.192 107.16 ;
    END
  END di[633]
  PIN di[634]
    DIRECTION INPUT ;
    USE SIGNAL ;
    PORT
      LAYER M4 ;
        RECT  0 107.328 0.192 107.352 ;
    END
  END di[634]
  PIN di[635]
    DIRECTION INPUT ;
    USE SIGNAL ;
    PORT
      LAYER M4 ;
        RECT  0 107.472 0.192 107.496 ;
    END
  END di[635]
  PIN di[636]
    DIRECTION INPUT ;
    USE SIGNAL ;
    PORT
      LAYER M4 ;
        RECT  0 107.664 0.192 107.688 ;
    END
  END di[636]
  PIN di[637]
    DIRECTION INPUT ;
    USE SIGNAL ;
    PORT
      LAYER M4 ;
        RECT  0 107.808 0.192 107.832 ;
    END
  END di[637]
  PIN di[638]
    DIRECTION INPUT ;
    USE SIGNAL ;
    PORT
      LAYER M4 ;
        RECT  0 107.952 0.192 107.976 ;
    END
  END di[638]
  PIN di[639]
    DIRECTION INPUT ;
    USE SIGNAL ;
    PORT
      LAYER M4 ;
        RECT  0 108.144 0.192 108.168 ;
    END
  END di[639]
  PIN di[63]
    DIRECTION INPUT ;
    USE SIGNAL ;
    PORT
      LAYER M4 ;
        RECT  0 14.64 0.192 14.664 ;
    END
  END di[63]
  PIN di[640]
    DIRECTION INPUT ;
    USE SIGNAL ;
    PORT
      LAYER M4 ;
        RECT  0 108.288 0.192 108.312 ;
    END
  END di[640]
  PIN di[641]
    DIRECTION INPUT ;
    USE SIGNAL ;
    PORT
      LAYER M4 ;
        RECT  0 108.432 0.192 108.456 ;
    END
  END di[641]
  PIN di[642]
    DIRECTION INPUT ;
    USE SIGNAL ;
    PORT
      LAYER M4 ;
        RECT  0 108.624 0.192 108.648 ;
    END
  END di[642]
  PIN di[643]
    DIRECTION INPUT ;
    USE SIGNAL ;
    PORT
      LAYER M4 ;
        RECT  0 108.768 0.192 108.792 ;
    END
  END di[643]
  PIN di[644]
    DIRECTION INPUT ;
    USE SIGNAL ;
    PORT
      LAYER M4 ;
        RECT  0 108.96 0.192 108.984 ;
    END
  END di[644]
  PIN di[645]
    DIRECTION INPUT ;
    USE SIGNAL ;
    PORT
      LAYER M4 ;
        RECT  0 109.104 0.192 109.128 ;
    END
  END di[645]
  PIN di[646]
    DIRECTION INPUT ;
    USE SIGNAL ;
    PORT
      LAYER M4 ;
        RECT  0 109.248 0.192 109.272 ;
    END
  END di[646]
  PIN di[647]
    DIRECTION INPUT ;
    USE SIGNAL ;
    PORT
      LAYER M4 ;
        RECT  0 109.44 0.192 109.464 ;
    END
  END di[647]
  PIN di[648]
    DIRECTION INPUT ;
    USE SIGNAL ;
    PORT
      LAYER M4 ;
        RECT  0 109.584 0.192 109.608 ;
    END
  END di[648]
  PIN di[649]
    DIRECTION INPUT ;
    USE SIGNAL ;
    PORT
      LAYER M4 ;
        RECT  0 109.776 0.192 109.8 ;
    END
  END di[649]
  PIN di[64]
    DIRECTION INPUT ;
    USE SIGNAL ;
    PORT
      LAYER M4 ;
        RECT  0 14.784 0.192 14.808 ;
    END
  END di[64]
  PIN di[650]
    DIRECTION INPUT ;
    USE SIGNAL ;
    PORT
      LAYER M4 ;
        RECT  0 109.92 0.192 109.944 ;
    END
  END di[650]
  PIN di[651]
    DIRECTION INPUT ;
    USE SIGNAL ;
    PORT
      LAYER M4 ;
        RECT  0 110.064 0.192 110.088 ;
    END
  END di[651]
  PIN di[652]
    DIRECTION INPUT ;
    USE SIGNAL ;
    PORT
      LAYER M4 ;
        RECT  0 110.256 0.192 110.28 ;
    END
  END di[652]
  PIN di[653]
    DIRECTION INPUT ;
    USE SIGNAL ;
    PORT
      LAYER M4 ;
        RECT  0 110.4 0.192 110.424 ;
    END
  END di[653]
  PIN di[654]
    DIRECTION INPUT ;
    USE SIGNAL ;
    PORT
      LAYER M4 ;
        RECT  0 110.544 0.192 110.568 ;
    END
  END di[654]
  PIN di[655]
    DIRECTION INPUT ;
    USE SIGNAL ;
    PORT
      LAYER M4 ;
        RECT  0 110.736 0.192 110.76 ;
    END
  END di[655]
  PIN di[656]
    DIRECTION INPUT ;
    USE SIGNAL ;
    PORT
      LAYER M4 ;
        RECT  0 110.88 0.192 110.904 ;
    END
  END di[656]
  PIN di[657]
    DIRECTION INPUT ;
    USE SIGNAL ;
    PORT
      LAYER M4 ;
        RECT  0 111.072 0.192 111.096 ;
    END
  END di[657]
  PIN di[658]
    DIRECTION INPUT ;
    USE SIGNAL ;
    PORT
      LAYER M4 ;
        RECT  0 111.216 0.192 111.24 ;
    END
  END di[658]
  PIN di[659]
    DIRECTION INPUT ;
    USE SIGNAL ;
    PORT
      LAYER M4 ;
        RECT  0 111.36 0.192 111.384 ;
    END
  END di[659]
  PIN di[65]
    DIRECTION INPUT ;
    USE SIGNAL ;
    PORT
      LAYER M4 ;
        RECT  0 14.976 0.192 15 ;
    END
  END di[65]
  PIN di[660]
    DIRECTION INPUT ;
    USE SIGNAL ;
    PORT
      LAYER M4 ;
        RECT  0 111.552 0.192 111.576 ;
    END
  END di[660]
  PIN di[661]
    DIRECTION INPUT ;
    USE SIGNAL ;
    PORT
      LAYER M4 ;
        RECT  0 111.696 0.192 111.72 ;
    END
  END di[661]
  PIN di[662]
    DIRECTION INPUT ;
    USE SIGNAL ;
    PORT
      LAYER M4 ;
        RECT  0 111.84 0.192 111.864 ;
    END
  END di[662]
  PIN di[663]
    DIRECTION INPUT ;
    USE SIGNAL ;
    PORT
      LAYER M4 ;
        RECT  0 112.032 0.192 112.056 ;
    END
  END di[663]
  PIN di[664]
    DIRECTION INPUT ;
    USE SIGNAL ;
    PORT
      LAYER M4 ;
        RECT  0 112.176 0.192 112.2 ;
    END
  END di[664]
  PIN di[665]
    DIRECTION INPUT ;
    USE SIGNAL ;
    PORT
      LAYER M4 ;
        RECT  0 112.368 0.192 112.392 ;
    END
  END di[665]
  PIN di[666]
    DIRECTION INPUT ;
    USE SIGNAL ;
    PORT
      LAYER M4 ;
        RECT  0 112.512 0.192 112.536 ;
    END
  END di[666]
  PIN di[667]
    DIRECTION INPUT ;
    USE SIGNAL ;
    PORT
      LAYER M4 ;
        RECT  0 112.656 0.192 112.68 ;
    END
  END di[667]
  PIN di[668]
    DIRECTION INPUT ;
    USE SIGNAL ;
    PORT
      LAYER M4 ;
        RECT  0 112.848 0.192 112.872 ;
    END
  END di[668]
  PIN di[669]
    DIRECTION INPUT ;
    USE SIGNAL ;
    PORT
      LAYER M4 ;
        RECT  0 112.992 0.192 113.016 ;
    END
  END di[669]
  PIN di[66]
    DIRECTION INPUT ;
    USE SIGNAL ;
    PORT
      LAYER M4 ;
        RECT  0 15.12 0.192 15.144 ;
    END
  END di[66]
  PIN di[670]
    DIRECTION INPUT ;
    USE SIGNAL ;
    PORT
      LAYER M4 ;
        RECT  0 113.184 0.192 113.208 ;
    END
  END di[670]
  PIN di[671]
    DIRECTION INPUT ;
    USE SIGNAL ;
    PORT
      LAYER M4 ;
        RECT  0 113.328 0.192 113.352 ;
    END
  END di[671]
  PIN di[672]
    DIRECTION INPUT ;
    USE SIGNAL ;
    PORT
      LAYER M4 ;
        RECT  0 113.472 0.192 113.496 ;
    END
  END di[672]
  PIN di[673]
    DIRECTION INPUT ;
    USE SIGNAL ;
    PORT
      LAYER M4 ;
        RECT  0 113.664 0.192 113.688 ;
    END
  END di[673]
  PIN di[674]
    DIRECTION INPUT ;
    USE SIGNAL ;
    PORT
      LAYER M4 ;
        RECT  0 113.808 0.192 113.832 ;
    END
  END di[674]
  PIN di[675]
    DIRECTION INPUT ;
    USE SIGNAL ;
    PORT
      LAYER M4 ;
        RECT  0 113.952 0.192 113.976 ;
    END
  END di[675]
  PIN di[676]
    DIRECTION INPUT ;
    USE SIGNAL ;
    PORT
      LAYER M4 ;
        RECT  0 114.144 0.192 114.168 ;
    END
  END di[676]
  PIN di[677]
    DIRECTION INPUT ;
    USE SIGNAL ;
    PORT
      LAYER M4 ;
        RECT  0 114.288 0.192 114.312 ;
    END
  END di[677]
  PIN di[678]
    DIRECTION INPUT ;
    USE SIGNAL ;
    PORT
      LAYER M4 ;
        RECT  0 114.48 0.192 114.504 ;
    END
  END di[678]
  PIN di[679]
    DIRECTION INPUT ;
    USE SIGNAL ;
    PORT
      LAYER M4 ;
        RECT  0 114.624 0.192 114.648 ;
    END
  END di[679]
  PIN di[67]
    DIRECTION INPUT ;
    USE SIGNAL ;
    PORT
      LAYER M4 ;
        RECT  0 15.312 0.192 15.336 ;
    END
  END di[67]
  PIN di[680]
    DIRECTION INPUT ;
    USE SIGNAL ;
    PORT
      LAYER M4 ;
        RECT  0 114.768 0.192 114.792 ;
    END
  END di[680]
  PIN di[681]
    DIRECTION INPUT ;
    USE SIGNAL ;
    PORT
      LAYER M4 ;
        RECT  0 114.96 0.192 114.984 ;
    END
  END di[681]
  PIN di[682]
    DIRECTION INPUT ;
    USE SIGNAL ;
    PORT
      LAYER M4 ;
        RECT  0 115.104 0.192 115.128 ;
    END
  END di[682]
  PIN di[683]
    DIRECTION INPUT ;
    USE SIGNAL ;
    PORT
      LAYER M4 ;
        RECT  0 115.296 0.192 115.32 ;
    END
  END di[683]
  PIN di[684]
    DIRECTION INPUT ;
    USE SIGNAL ;
    PORT
      LAYER M4 ;
        RECT  0 115.44 0.192 115.464 ;
    END
  END di[684]
  PIN di[685]
    DIRECTION INPUT ;
    USE SIGNAL ;
    PORT
      LAYER M4 ;
        RECT  0 115.584 0.192 115.608 ;
    END
  END di[685]
  PIN di[686]
    DIRECTION INPUT ;
    USE SIGNAL ;
    PORT
      LAYER M4 ;
        RECT  0 115.776 0.192 115.8 ;
    END
  END di[686]
  PIN di[687]
    DIRECTION INPUT ;
    USE SIGNAL ;
    PORT
      LAYER M4 ;
        RECT  0 115.92 0.192 115.944 ;
    END
  END di[687]
  PIN di[688]
    DIRECTION INPUT ;
    USE SIGNAL ;
    PORT
      LAYER M4 ;
        RECT  0 116.064 0.192 116.088 ;
    END
  END di[688]
  PIN di[689]
    DIRECTION INPUT ;
    USE SIGNAL ;
    PORT
      LAYER M4 ;
        RECT  0 116.256 0.192 116.28 ;
    END
  END di[689]
  PIN di[68]
    DIRECTION INPUT ;
    USE SIGNAL ;
    PORT
      LAYER M4 ;
        RECT  0 15.456 0.192 15.48 ;
    END
  END di[68]
  PIN di[690]
    DIRECTION INPUT ;
    USE SIGNAL ;
    PORT
      LAYER M4 ;
        RECT  0 116.4 0.192 116.424 ;
    END
  END di[690]
  PIN di[691]
    DIRECTION INPUT ;
    USE SIGNAL ;
    PORT
      LAYER M4 ;
        RECT  0 116.592 0.192 116.616 ;
    END
  END di[691]
  PIN di[69]
    DIRECTION INPUT ;
    USE SIGNAL ;
    PORT
      LAYER M4 ;
        RECT  0 15.6 0.192 15.624 ;
    END
  END di[69]
  PIN di[6]
    DIRECTION INPUT ;
    USE SIGNAL ;
    PORT
      LAYER M4 ;
        RECT  0 5.376 0.192 5.4 ;
    END
  END di[6]
  PIN di[70]
    DIRECTION INPUT ;
    USE SIGNAL ;
    PORT
      LAYER M4 ;
        RECT  0 15.792 0.192 15.816 ;
    END
  END di[70]
  PIN di[71]
    DIRECTION INPUT ;
    USE SIGNAL ;
    PORT
      LAYER M4 ;
        RECT  0 15.936 0.192 15.96 ;
    END
  END di[71]
  PIN di[72]
    DIRECTION INPUT ;
    USE SIGNAL ;
    PORT
      LAYER M4 ;
        RECT  0 16.08 0.192 16.104 ;
    END
  END di[72]
  PIN di[73]
    DIRECTION INPUT ;
    USE SIGNAL ;
    PORT
      LAYER M4 ;
        RECT  0 16.272 0.192 16.296 ;
    END
  END di[73]
  PIN di[74]
    DIRECTION INPUT ;
    USE SIGNAL ;
    PORT
      LAYER M4 ;
        RECT  0 16.416 0.192 16.44 ;
    END
  END di[74]
  PIN di[75]
    DIRECTION INPUT ;
    USE SIGNAL ;
    PORT
      LAYER M4 ;
        RECT  0 16.608 0.192 16.632 ;
    END
  END di[75]
  PIN di[76]
    DIRECTION INPUT ;
    USE SIGNAL ;
    PORT
      LAYER M4 ;
        RECT  0 16.752 0.192 16.776 ;
    END
  END di[76]
  PIN di[77]
    DIRECTION INPUT ;
    USE SIGNAL ;
    PORT
      LAYER M4 ;
        RECT  0 16.896 0.192 16.92 ;
    END
  END di[77]
  PIN di[78]
    DIRECTION INPUT ;
    USE SIGNAL ;
    PORT
      LAYER M4 ;
        RECT  0 17.088 0.192 17.112 ;
    END
  END di[78]
  PIN di[79]
    DIRECTION INPUT ;
    USE SIGNAL ;
    PORT
      LAYER M4 ;
        RECT  0 17.232 0.192 17.256 ;
    END
  END di[79]
  PIN di[7]
    DIRECTION INPUT ;
    USE SIGNAL ;
    PORT
      LAYER M4 ;
        RECT  0 5.568 0.192 5.592 ;
    END
  END di[7]
  PIN di[80]
    DIRECTION INPUT ;
    USE SIGNAL ;
    PORT
      LAYER M4 ;
        RECT  0 17.376 0.192 17.4 ;
    END
  END di[80]
  PIN di[81]
    DIRECTION INPUT ;
    USE SIGNAL ;
    PORT
      LAYER M4 ;
        RECT  0 17.568 0.192 17.592 ;
    END
  END di[81]
  PIN di[82]
    DIRECTION INPUT ;
    USE SIGNAL ;
    PORT
      LAYER M4 ;
        RECT  0 17.712 0.192 17.736 ;
    END
  END di[82]
  PIN di[83]
    DIRECTION INPUT ;
    USE SIGNAL ;
    PORT
      LAYER M4 ;
        RECT  0 17.904 0.192 17.928 ;
    END
  END di[83]
  PIN di[84]
    DIRECTION INPUT ;
    USE SIGNAL ;
    PORT
      LAYER M4 ;
        RECT  0 18.048 0.192 18.072 ;
    END
  END di[84]
  PIN di[85]
    DIRECTION INPUT ;
    USE SIGNAL ;
    PORT
      LAYER M4 ;
        RECT  0 18.192 0.192 18.216 ;
    END
  END di[85]
  PIN di[86]
    DIRECTION INPUT ;
    USE SIGNAL ;
    PORT
      LAYER M4 ;
        RECT  0 18.384 0.192 18.408 ;
    END
  END di[86]
  PIN di[87]
    DIRECTION INPUT ;
    USE SIGNAL ;
    PORT
      LAYER M4 ;
        RECT  0 18.528 0.192 18.552 ;
    END
  END di[87]
  PIN di[88]
    DIRECTION INPUT ;
    USE SIGNAL ;
    PORT
      LAYER M4 ;
        RECT  0 18.72 0.192 18.744 ;
    END
  END di[88]
  PIN di[89]
    DIRECTION INPUT ;
    USE SIGNAL ;
    PORT
      LAYER M4 ;
        RECT  0 18.864 0.192 18.888 ;
    END
  END di[89]
  PIN di[8]
    DIRECTION INPUT ;
    USE SIGNAL ;
    PORT
      LAYER M4 ;
        RECT  0 5.712 0.192 5.736 ;
    END
  END di[8]
  PIN di[90]
    DIRECTION INPUT ;
    USE SIGNAL ;
    PORT
      LAYER M4 ;
        RECT  0 19.008 0.192 19.032 ;
    END
  END di[90]
  PIN di[91]
    DIRECTION INPUT ;
    USE SIGNAL ;
    PORT
      LAYER M4 ;
        RECT  0 19.2 0.192 19.224 ;
    END
  END di[91]
  PIN di[92]
    DIRECTION INPUT ;
    USE SIGNAL ;
    PORT
      LAYER M4 ;
        RECT  0 19.344 0.192 19.368 ;
    END
  END di[92]
  PIN di[93]
    DIRECTION INPUT ;
    USE SIGNAL ;
    PORT
      LAYER M4 ;
        RECT  0 19.488 0.192 19.512 ;
    END
  END di[93]
  PIN di[94]
    DIRECTION INPUT ;
    USE SIGNAL ;
    PORT
      LAYER M4 ;
        RECT  0 19.68 0.192 19.704 ;
    END
  END di[94]
  PIN di[95]
    DIRECTION INPUT ;
    USE SIGNAL ;
    PORT
      LAYER M4 ;
        RECT  0 19.824 0.192 19.848 ;
    END
  END di[95]
  PIN di[96]
    DIRECTION INPUT ;
    USE SIGNAL ;
    PORT
      LAYER M4 ;
        RECT  0 20.016 0.192 20.04 ;
    END
  END di[96]
  PIN di[97]
    DIRECTION INPUT ;
    USE SIGNAL ;
    PORT
      LAYER M4 ;
        RECT  0 20.16 0.192 20.184 ;
    END
  END di[97]
  PIN di[98]
    DIRECTION INPUT ;
    USE SIGNAL ;
    PORT
      LAYER M4 ;
        RECT  0 20.304 0.192 20.328 ;
    END
  END di[98]
  PIN di[99]
    DIRECTION INPUT ;
    USE SIGNAL ;
    PORT
      LAYER M4 ;
        RECT  0 20.496 0.192 20.52 ;
    END
  END di[99]
  PIN di[9]
    DIRECTION INPUT ;
    USE SIGNAL ;
    PORT
      LAYER M4 ;
        RECT  0 5.856 0.192 5.88 ;
    END
  END di[9]
  PIN dq[0]
    DIRECTION OUTPUT ;
    USE SIGNAL ;
    PORT
      LAYER M4 ;
        RECT  36.528 4.416 36.72 4.44 ;
    END
  END dq[0]
  PIN dq[100]
    DIRECTION OUTPUT ;
    USE SIGNAL ;
    PORT
      LAYER M4 ;
        RECT  36.528 20.64 36.72 20.664 ;
    END
  END dq[100]
  PIN dq[101]
    DIRECTION OUTPUT ;
    USE SIGNAL ;
    PORT
      LAYER M4 ;
        RECT  36.528 20.784 36.72 20.808 ;
    END
  END dq[101]
  PIN dq[102]
    DIRECTION OUTPUT ;
    USE SIGNAL ;
    PORT
      LAYER M4 ;
        RECT  36.528 20.976 36.72 21 ;
    END
  END dq[102]
  PIN dq[103]
    DIRECTION OUTPUT ;
    USE SIGNAL ;
    PORT
      LAYER M4 ;
        RECT  36.528 21.12 36.72 21.144 ;
    END
  END dq[103]
  PIN dq[104]
    DIRECTION OUTPUT ;
    USE SIGNAL ;
    PORT
      LAYER M4 ;
        RECT  36.528 21.312 36.72 21.336 ;
    END
  END dq[104]
  PIN dq[105]
    DIRECTION OUTPUT ;
    USE SIGNAL ;
    PORT
      LAYER M4 ;
        RECT  36.528 21.456 36.72 21.48 ;
    END
  END dq[105]
  PIN dq[106]
    DIRECTION OUTPUT ;
    USE SIGNAL ;
    PORT
      LAYER M4 ;
        RECT  36.528 21.6 36.72 21.624 ;
    END
  END dq[106]
  PIN dq[107]
    DIRECTION OUTPUT ;
    USE SIGNAL ;
    PORT
      LAYER M4 ;
        RECT  36.528 21.792 36.72 21.816 ;
    END
  END dq[107]
  PIN dq[108]
    DIRECTION OUTPUT ;
    USE SIGNAL ;
    PORT
      LAYER M4 ;
        RECT  36.528 21.936 36.72 21.96 ;
    END
  END dq[108]
  PIN dq[109]
    DIRECTION OUTPUT ;
    USE SIGNAL ;
    PORT
      LAYER M4 ;
        RECT  36.528 22.128 36.72 22.152 ;
    END
  END dq[109]
  PIN dq[10]
    DIRECTION OUTPUT ;
    USE SIGNAL ;
    PORT
      LAYER M4 ;
        RECT  36.528 6.048 36.72 6.072 ;
    END
  END dq[10]
  PIN dq[110]
    DIRECTION OUTPUT ;
    USE SIGNAL ;
    PORT
      LAYER M4 ;
        RECT  36.528 22.272 36.72 22.296 ;
    END
  END dq[110]
  PIN dq[111]
    DIRECTION OUTPUT ;
    USE SIGNAL ;
    PORT
      LAYER M4 ;
        RECT  36.528 22.416 36.72 22.44 ;
    END
  END dq[111]
  PIN dq[112]
    DIRECTION OUTPUT ;
    USE SIGNAL ;
    PORT
      LAYER M4 ;
        RECT  36.528 22.608 36.72 22.632 ;
    END
  END dq[112]
  PIN dq[113]
    DIRECTION OUTPUT ;
    USE SIGNAL ;
    PORT
      LAYER M4 ;
        RECT  36.528 22.752 36.72 22.776 ;
    END
  END dq[113]
  PIN dq[114]
    DIRECTION OUTPUT ;
    USE SIGNAL ;
    PORT
      LAYER M4 ;
        RECT  36.528 22.896 36.72 22.92 ;
    END
  END dq[114]
  PIN dq[115]
    DIRECTION OUTPUT ;
    USE SIGNAL ;
    PORT
      LAYER M4 ;
        RECT  36.528 23.088 36.72 23.112 ;
    END
  END dq[115]
  PIN dq[116]
    DIRECTION OUTPUT ;
    USE SIGNAL ;
    PORT
      LAYER M4 ;
        RECT  36.528 23.232 36.72 23.256 ;
    END
  END dq[116]
  PIN dq[117]
    DIRECTION OUTPUT ;
    USE SIGNAL ;
    PORT
      LAYER M4 ;
        RECT  36.528 23.424 36.72 23.448 ;
    END
  END dq[117]
  PIN dq[118]
    DIRECTION OUTPUT ;
    USE SIGNAL ;
    PORT
      LAYER M4 ;
        RECT  36.528 23.568 36.72 23.592 ;
    END
  END dq[118]
  PIN dq[119]
    DIRECTION OUTPUT ;
    USE SIGNAL ;
    PORT
      LAYER M4 ;
        RECT  36.528 23.712 36.72 23.736 ;
    END
  END dq[119]
  PIN dq[11]
    DIRECTION OUTPUT ;
    USE SIGNAL ;
    PORT
      LAYER M4 ;
        RECT  36.528 6.192 36.72 6.216 ;
    END
  END dq[11]
  PIN dq[120]
    DIRECTION OUTPUT ;
    USE SIGNAL ;
    PORT
      LAYER M4 ;
        RECT  36.528 23.904 36.72 23.928 ;
    END
  END dq[120]
  PIN dq[121]
    DIRECTION OUTPUT ;
    USE SIGNAL ;
    PORT
      LAYER M4 ;
        RECT  36.528 24.048 36.72 24.072 ;
    END
  END dq[121]
  PIN dq[122]
    DIRECTION OUTPUT ;
    USE SIGNAL ;
    PORT
      LAYER M4 ;
        RECT  36.528 24.192 36.72 24.216 ;
    END
  END dq[122]
  PIN dq[123]
    DIRECTION OUTPUT ;
    USE SIGNAL ;
    PORT
      LAYER M4 ;
        RECT  36.528 24.384 36.72 24.408 ;
    END
  END dq[123]
  PIN dq[124]
    DIRECTION OUTPUT ;
    USE SIGNAL ;
    PORT
      LAYER M4 ;
        RECT  36.528 24.528 36.72 24.552 ;
    END
  END dq[124]
  PIN dq[125]
    DIRECTION OUTPUT ;
    USE SIGNAL ;
    PORT
      LAYER M4 ;
        RECT  36.528 24.72 36.72 24.744 ;
    END
  END dq[125]
  PIN dq[126]
    DIRECTION OUTPUT ;
    USE SIGNAL ;
    PORT
      LAYER M4 ;
        RECT  36.528 24.864 36.72 24.888 ;
    END
  END dq[126]
  PIN dq[127]
    DIRECTION OUTPUT ;
    USE SIGNAL ;
    PORT
      LAYER M4 ;
        RECT  36.528 25.008 36.72 25.032 ;
    END
  END dq[127]
  PIN dq[128]
    DIRECTION OUTPUT ;
    USE SIGNAL ;
    PORT
      LAYER M4 ;
        RECT  36.528 25.2 36.72 25.224 ;
    END
  END dq[128]
  PIN dq[129]
    DIRECTION OUTPUT ;
    USE SIGNAL ;
    PORT
      LAYER M4 ;
        RECT  36.528 25.344 36.72 25.368 ;
    END
  END dq[129]
  PIN dq[12]
    DIRECTION OUTPUT ;
    USE SIGNAL ;
    PORT
      LAYER M4 ;
        RECT  36.528 6.384 36.72 6.408 ;
    END
  END dq[12]
  PIN dq[130]
    DIRECTION OUTPUT ;
    USE SIGNAL ;
    PORT
      LAYER M4 ;
        RECT  36.528 25.536 36.72 25.56 ;
    END
  END dq[130]
  PIN dq[131]
    DIRECTION OUTPUT ;
    USE SIGNAL ;
    PORT
      LAYER M4 ;
        RECT  36.528 25.68 36.72 25.704 ;
    END
  END dq[131]
  PIN dq[132]
    DIRECTION OUTPUT ;
    USE SIGNAL ;
    PORT
      LAYER M4 ;
        RECT  36.528 25.824 36.72 25.848 ;
    END
  END dq[132]
  PIN dq[133]
    DIRECTION OUTPUT ;
    USE SIGNAL ;
    PORT
      LAYER M4 ;
        RECT  36.528 26.016 36.72 26.04 ;
    END
  END dq[133]
  PIN dq[134]
    DIRECTION OUTPUT ;
    USE SIGNAL ;
    PORT
      LAYER M4 ;
        RECT  36.528 26.16 36.72 26.184 ;
    END
  END dq[134]
  PIN dq[135]
    DIRECTION OUTPUT ;
    USE SIGNAL ;
    PORT
      LAYER M4 ;
        RECT  36.528 26.304 36.72 26.328 ;
    END
  END dq[135]
  PIN dq[136]
    DIRECTION OUTPUT ;
    USE SIGNAL ;
    PORT
      LAYER M4 ;
        RECT  36.528 26.496 36.72 26.52 ;
    END
  END dq[136]
  PIN dq[137]
    DIRECTION OUTPUT ;
    USE SIGNAL ;
    PORT
      LAYER M4 ;
        RECT  36.528 26.64 36.72 26.664 ;
    END
  END dq[137]
  PIN dq[138]
    DIRECTION OUTPUT ;
    USE SIGNAL ;
    PORT
      LAYER M4 ;
        RECT  36.528 26.832 36.72 26.856 ;
    END
  END dq[138]
  PIN dq[139]
    DIRECTION OUTPUT ;
    USE SIGNAL ;
    PORT
      LAYER M4 ;
        RECT  36.528 26.976 36.72 27 ;
    END
  END dq[139]
  PIN dq[13]
    DIRECTION OUTPUT ;
    USE SIGNAL ;
    PORT
      LAYER M4 ;
        RECT  36.528 6.528 36.72 6.552 ;
    END
  END dq[13]
  PIN dq[140]
    DIRECTION OUTPUT ;
    USE SIGNAL ;
    PORT
      LAYER M4 ;
        RECT  36.528 27.12 36.72 27.144 ;
    END
  END dq[140]
  PIN dq[141]
    DIRECTION OUTPUT ;
    USE SIGNAL ;
    PORT
      LAYER M4 ;
        RECT  36.528 27.312 36.72 27.336 ;
    END
  END dq[141]
  PIN dq[142]
    DIRECTION OUTPUT ;
    USE SIGNAL ;
    PORT
      LAYER M4 ;
        RECT  36.528 27.456 36.72 27.48 ;
    END
  END dq[142]
  PIN dq[143]
    DIRECTION OUTPUT ;
    USE SIGNAL ;
    PORT
      LAYER M4 ;
        RECT  36.528 27.6 36.72 27.624 ;
    END
  END dq[143]
  PIN dq[144]
    DIRECTION OUTPUT ;
    USE SIGNAL ;
    PORT
      LAYER M4 ;
        RECT  36.528 27.792 36.72 27.816 ;
    END
  END dq[144]
  PIN dq[145]
    DIRECTION OUTPUT ;
    USE SIGNAL ;
    PORT
      LAYER M4 ;
        RECT  36.528 27.936 36.72 27.96 ;
    END
  END dq[145]
  PIN dq[146]
    DIRECTION OUTPUT ;
    USE SIGNAL ;
    PORT
      LAYER M4 ;
        RECT  36.528 28.128 36.72 28.152 ;
    END
  END dq[146]
  PIN dq[147]
    DIRECTION OUTPUT ;
    USE SIGNAL ;
    PORT
      LAYER M4 ;
        RECT  36.528 28.272 36.72 28.296 ;
    END
  END dq[147]
  PIN dq[148]
    DIRECTION OUTPUT ;
    USE SIGNAL ;
    PORT
      LAYER M4 ;
        RECT  36.528 28.416 36.72 28.44 ;
    END
  END dq[148]
  PIN dq[149]
    DIRECTION OUTPUT ;
    USE SIGNAL ;
    PORT
      LAYER M4 ;
        RECT  36.528 28.608 36.72 28.632 ;
    END
  END dq[149]
  PIN dq[14]
    DIRECTION OUTPUT ;
    USE SIGNAL ;
    PORT
      LAYER M4 ;
        RECT  36.528 6.672 36.72 6.696 ;
    END
  END dq[14]
  PIN dq[150]
    DIRECTION OUTPUT ;
    USE SIGNAL ;
    PORT
      LAYER M4 ;
        RECT  36.528 28.752 36.72 28.776 ;
    END
  END dq[150]
  PIN dq[151]
    DIRECTION OUTPUT ;
    USE SIGNAL ;
    PORT
      LAYER M4 ;
        RECT  36.528 28.944 36.72 28.968 ;
    END
  END dq[151]
  PIN dq[152]
    DIRECTION OUTPUT ;
    USE SIGNAL ;
    PORT
      LAYER M4 ;
        RECT  36.528 29.088 36.72 29.112 ;
    END
  END dq[152]
  PIN dq[153]
    DIRECTION OUTPUT ;
    USE SIGNAL ;
    PORT
      LAYER M4 ;
        RECT  36.528 29.232 36.72 29.256 ;
    END
  END dq[153]
  PIN dq[154]
    DIRECTION OUTPUT ;
    USE SIGNAL ;
    PORT
      LAYER M4 ;
        RECT  36.528 29.424 36.72 29.448 ;
    END
  END dq[154]
  PIN dq[155]
    DIRECTION OUTPUT ;
    USE SIGNAL ;
    PORT
      LAYER M4 ;
        RECT  36.528 29.568 36.72 29.592 ;
    END
  END dq[155]
  PIN dq[156]
    DIRECTION OUTPUT ;
    USE SIGNAL ;
    PORT
      LAYER M4 ;
        RECT  36.528 29.712 36.72 29.736 ;
    END
  END dq[156]
  PIN dq[157]
    DIRECTION OUTPUT ;
    USE SIGNAL ;
    PORT
      LAYER M4 ;
        RECT  36.528 29.904 36.72 29.928 ;
    END
  END dq[157]
  PIN dq[158]
    DIRECTION OUTPUT ;
    USE SIGNAL ;
    PORT
      LAYER M4 ;
        RECT  36.528 30.048 36.72 30.072 ;
    END
  END dq[158]
  PIN dq[159]
    DIRECTION OUTPUT ;
    USE SIGNAL ;
    PORT
      LAYER M4 ;
        RECT  36.528 30.24 36.72 30.264 ;
    END
  END dq[159]
  PIN dq[15]
    DIRECTION OUTPUT ;
    USE SIGNAL ;
    PORT
      LAYER M4 ;
        RECT  36.528 6.864 36.72 6.888 ;
    END
  END dq[15]
  PIN dq[160]
    DIRECTION OUTPUT ;
    USE SIGNAL ;
    PORT
      LAYER M4 ;
        RECT  36.528 30.384 36.72 30.408 ;
    END
  END dq[160]
  PIN dq[161]
    DIRECTION OUTPUT ;
    USE SIGNAL ;
    PORT
      LAYER M4 ;
        RECT  36.528 30.528 36.72 30.552 ;
    END
  END dq[161]
  PIN dq[162]
    DIRECTION OUTPUT ;
    USE SIGNAL ;
    PORT
      LAYER M4 ;
        RECT  36.528 30.72 36.72 30.744 ;
    END
  END dq[162]
  PIN dq[163]
    DIRECTION OUTPUT ;
    USE SIGNAL ;
    PORT
      LAYER M4 ;
        RECT  36.528 30.864 36.72 30.888 ;
    END
  END dq[163]
  PIN dq[164]
    DIRECTION OUTPUT ;
    USE SIGNAL ;
    PORT
      LAYER M4 ;
        RECT  36.528 31.056 36.72 31.08 ;
    END
  END dq[164]
  PIN dq[165]
    DIRECTION OUTPUT ;
    USE SIGNAL ;
    PORT
      LAYER M4 ;
        RECT  36.528 31.2 36.72 31.224 ;
    END
  END dq[165]
  PIN dq[166]
    DIRECTION OUTPUT ;
    USE SIGNAL ;
    PORT
      LAYER M4 ;
        RECT  36.528 31.344 36.72 31.368 ;
    END
  END dq[166]
  PIN dq[167]
    DIRECTION OUTPUT ;
    USE SIGNAL ;
    PORT
      LAYER M4 ;
        RECT  36.528 31.536 36.72 31.56 ;
    END
  END dq[167]
  PIN dq[168]
    DIRECTION OUTPUT ;
    USE SIGNAL ;
    PORT
      LAYER M4 ;
        RECT  36.528 31.68 36.72 31.704 ;
    END
  END dq[168]
  PIN dq[169]
    DIRECTION OUTPUT ;
    USE SIGNAL ;
    PORT
      LAYER M4 ;
        RECT  36.528 31.824 36.72 31.848 ;
    END
  END dq[169]
  PIN dq[16]
    DIRECTION OUTPUT ;
    USE SIGNAL ;
    PORT
      LAYER M4 ;
        RECT  36.528 7.008 36.72 7.032 ;
    END
  END dq[16]
  PIN dq[170]
    DIRECTION OUTPUT ;
    USE SIGNAL ;
    PORT
      LAYER M4 ;
        RECT  36.528 32.016 36.72 32.04 ;
    END
  END dq[170]
  PIN dq[171]
    DIRECTION OUTPUT ;
    USE SIGNAL ;
    PORT
      LAYER M4 ;
        RECT  36.528 32.16 36.72 32.184 ;
    END
  END dq[171]
  PIN dq[172]
    DIRECTION OUTPUT ;
    USE SIGNAL ;
    PORT
      LAYER M4 ;
        RECT  36.528 32.352 36.72 32.376 ;
    END
  END dq[172]
  PIN dq[173]
    DIRECTION OUTPUT ;
    USE SIGNAL ;
    PORT
      LAYER M4 ;
        RECT  36.528 32.496 36.72 32.52 ;
    END
  END dq[173]
  PIN dq[174]
    DIRECTION OUTPUT ;
    USE SIGNAL ;
    PORT
      LAYER M4 ;
        RECT  36.528 32.64 36.72 32.664 ;
    END
  END dq[174]
  PIN dq[175]
    DIRECTION OUTPUT ;
    USE SIGNAL ;
    PORT
      LAYER M4 ;
        RECT  36.528 32.832 36.72 32.856 ;
    END
  END dq[175]
  PIN dq[176]
    DIRECTION OUTPUT ;
    USE SIGNAL ;
    PORT
      LAYER M4 ;
        RECT  36.528 32.976 36.72 33 ;
    END
  END dq[176]
  PIN dq[177]
    DIRECTION OUTPUT ;
    USE SIGNAL ;
    PORT
      LAYER M4 ;
        RECT  36.528 33.12 36.72 33.144 ;
    END
  END dq[177]
  PIN dq[178]
    DIRECTION OUTPUT ;
    USE SIGNAL ;
    PORT
      LAYER M4 ;
        RECT  36.528 33.312 36.72 33.336 ;
    END
  END dq[178]
  PIN dq[179]
    DIRECTION OUTPUT ;
    USE SIGNAL ;
    PORT
      LAYER M4 ;
        RECT  36.528 33.456 36.72 33.48 ;
    END
  END dq[179]
  PIN dq[17]
    DIRECTION OUTPUT ;
    USE SIGNAL ;
    PORT
      LAYER M4 ;
        RECT  36.528 7.152 36.72 7.176 ;
    END
  END dq[17]
  PIN dq[180]
    DIRECTION OUTPUT ;
    USE SIGNAL ;
    PORT
      LAYER M4 ;
        RECT  36.528 33.648 36.72 33.672 ;
    END
  END dq[180]
  PIN dq[181]
    DIRECTION OUTPUT ;
    USE SIGNAL ;
    PORT
      LAYER M4 ;
        RECT  36.528 33.792 36.72 33.816 ;
    END
  END dq[181]
  PIN dq[182]
    DIRECTION OUTPUT ;
    USE SIGNAL ;
    PORT
      LAYER M4 ;
        RECT  36.528 33.936 36.72 33.96 ;
    END
  END dq[182]
  PIN dq[183]
    DIRECTION OUTPUT ;
    USE SIGNAL ;
    PORT
      LAYER M4 ;
        RECT  36.528 34.128 36.72 34.152 ;
    END
  END dq[183]
  PIN dq[184]
    DIRECTION OUTPUT ;
    USE SIGNAL ;
    PORT
      LAYER M4 ;
        RECT  36.528 34.272 36.72 34.296 ;
    END
  END dq[184]
  PIN dq[185]
    DIRECTION OUTPUT ;
    USE SIGNAL ;
    PORT
      LAYER M4 ;
        RECT  36.528 34.464 36.72 34.488 ;
    END
  END dq[185]
  PIN dq[186]
    DIRECTION OUTPUT ;
    USE SIGNAL ;
    PORT
      LAYER M4 ;
        RECT  36.528 34.608 36.72 34.632 ;
    END
  END dq[186]
  PIN dq[187]
    DIRECTION OUTPUT ;
    USE SIGNAL ;
    PORT
      LAYER M4 ;
        RECT  36.528 34.752 36.72 34.776 ;
    END
  END dq[187]
  PIN dq[188]
    DIRECTION OUTPUT ;
    USE SIGNAL ;
    PORT
      LAYER M4 ;
        RECT  36.528 34.944 36.72 34.968 ;
    END
  END dq[188]
  PIN dq[189]
    DIRECTION OUTPUT ;
    USE SIGNAL ;
    PORT
      LAYER M4 ;
        RECT  36.528 35.088 36.72 35.112 ;
    END
  END dq[189]
  PIN dq[18]
    DIRECTION OUTPUT ;
    USE SIGNAL ;
    PORT
      LAYER M4 ;
        RECT  36.528 7.344 36.72 7.368 ;
    END
  END dq[18]
  PIN dq[190]
    DIRECTION OUTPUT ;
    USE SIGNAL ;
    PORT
      LAYER M4 ;
        RECT  36.528 35.232 36.72 35.256 ;
    END
  END dq[190]
  PIN dq[191]
    DIRECTION OUTPUT ;
    USE SIGNAL ;
    PORT
      LAYER M4 ;
        RECT  36.528 35.424 36.72 35.448 ;
    END
  END dq[191]
  PIN dq[192]
    DIRECTION OUTPUT ;
    USE SIGNAL ;
    PORT
      LAYER M4 ;
        RECT  36.528 35.568 36.72 35.592 ;
    END
  END dq[192]
  PIN dq[193]
    DIRECTION OUTPUT ;
    USE SIGNAL ;
    PORT
      LAYER M4 ;
        RECT  36.528 35.76 36.72 35.784 ;
    END
  END dq[193]
  PIN dq[194]
    DIRECTION OUTPUT ;
    USE SIGNAL ;
    PORT
      LAYER M4 ;
        RECT  36.528 35.904 36.72 35.928 ;
    END
  END dq[194]
  PIN dq[195]
    DIRECTION OUTPUT ;
    USE SIGNAL ;
    PORT
      LAYER M4 ;
        RECT  36.528 36.048 36.72 36.072 ;
    END
  END dq[195]
  PIN dq[196]
    DIRECTION OUTPUT ;
    USE SIGNAL ;
    PORT
      LAYER M4 ;
        RECT  36.528 36.24 36.72 36.264 ;
    END
  END dq[196]
  PIN dq[197]
    DIRECTION OUTPUT ;
    USE SIGNAL ;
    PORT
      LAYER M4 ;
        RECT  36.528 36.384 36.72 36.408 ;
    END
  END dq[197]
  PIN dq[198]
    DIRECTION OUTPUT ;
    USE SIGNAL ;
    PORT
      LAYER M4 ;
        RECT  36.528 36.528 36.72 36.552 ;
    END
  END dq[198]
  PIN dq[199]
    DIRECTION OUTPUT ;
    USE SIGNAL ;
    PORT
      LAYER M4 ;
        RECT  36.528 36.72 36.72 36.744 ;
    END
  END dq[199]
  PIN dq[19]
    DIRECTION OUTPUT ;
    USE SIGNAL ;
    PORT
      LAYER M4 ;
        RECT  36.528 7.488 36.72 7.512 ;
    END
  END dq[19]
  PIN dq[1]
    DIRECTION OUTPUT ;
    USE SIGNAL ;
    PORT
      LAYER M4 ;
        RECT  36.528 4.56 36.72 4.584 ;
    END
  END dq[1]
  PIN dq[200]
    DIRECTION OUTPUT ;
    USE SIGNAL ;
    PORT
      LAYER M4 ;
        RECT  36.528 36.864 36.72 36.888 ;
    END
  END dq[200]
  PIN dq[201]
    DIRECTION OUTPUT ;
    USE SIGNAL ;
    PORT
      LAYER M4 ;
        RECT  36.528 37.056 36.72 37.08 ;
    END
  END dq[201]
  PIN dq[202]
    DIRECTION OUTPUT ;
    USE SIGNAL ;
    PORT
      LAYER M4 ;
        RECT  36.528 37.2 36.72 37.224 ;
    END
  END dq[202]
  PIN dq[203]
    DIRECTION OUTPUT ;
    USE SIGNAL ;
    PORT
      LAYER M4 ;
        RECT  36.528 37.344 36.72 37.368 ;
    END
  END dq[203]
  PIN dq[204]
    DIRECTION OUTPUT ;
    USE SIGNAL ;
    PORT
      LAYER M4 ;
        RECT  36.528 37.536 36.72 37.56 ;
    END
  END dq[204]
  PIN dq[205]
    DIRECTION OUTPUT ;
    USE SIGNAL ;
    PORT
      LAYER M4 ;
        RECT  36.528 37.68 36.72 37.704 ;
    END
  END dq[205]
  PIN dq[206]
    DIRECTION OUTPUT ;
    USE SIGNAL ;
    PORT
      LAYER M4 ;
        RECT  36.528 37.872 36.72 37.896 ;
    END
  END dq[206]
  PIN dq[207]
    DIRECTION OUTPUT ;
    USE SIGNAL ;
    PORT
      LAYER M4 ;
        RECT  36.528 38.016 36.72 38.04 ;
    END
  END dq[207]
  PIN dq[208]
    DIRECTION OUTPUT ;
    USE SIGNAL ;
    PORT
      LAYER M4 ;
        RECT  36.528 38.16 36.72 38.184 ;
    END
  END dq[208]
  PIN dq[209]
    DIRECTION OUTPUT ;
    USE SIGNAL ;
    PORT
      LAYER M4 ;
        RECT  36.528 38.352 36.72 38.376 ;
    END
  END dq[209]
  PIN dq[20]
    DIRECTION OUTPUT ;
    USE SIGNAL ;
    PORT
      LAYER M4 ;
        RECT  36.528 7.68 36.72 7.704 ;
    END
  END dq[20]
  PIN dq[210]
    DIRECTION OUTPUT ;
    USE SIGNAL ;
    PORT
      LAYER M4 ;
        RECT  36.528 38.496 36.72 38.52 ;
    END
  END dq[210]
  PIN dq[211]
    DIRECTION OUTPUT ;
    USE SIGNAL ;
    PORT
      LAYER M4 ;
        RECT  36.528 38.64 36.72 38.664 ;
    END
  END dq[211]
  PIN dq[212]
    DIRECTION OUTPUT ;
    USE SIGNAL ;
    PORT
      LAYER M4 ;
        RECT  36.528 38.832 36.72 38.856 ;
    END
  END dq[212]
  PIN dq[213]
    DIRECTION OUTPUT ;
    USE SIGNAL ;
    PORT
      LAYER M4 ;
        RECT  36.528 38.976 36.72 39 ;
    END
  END dq[213]
  PIN dq[214]
    DIRECTION OUTPUT ;
    USE SIGNAL ;
    PORT
      LAYER M4 ;
        RECT  36.528 39.168 36.72 39.192 ;
    END
  END dq[214]
  PIN dq[215]
    DIRECTION OUTPUT ;
    USE SIGNAL ;
    PORT
      LAYER M4 ;
        RECT  36.528 39.312 36.72 39.336 ;
    END
  END dq[215]
  PIN dq[216]
    DIRECTION OUTPUT ;
    USE SIGNAL ;
    PORT
      LAYER M4 ;
        RECT  36.528 39.456 36.72 39.48 ;
    END
  END dq[216]
  PIN dq[217]
    DIRECTION OUTPUT ;
    USE SIGNAL ;
    PORT
      LAYER M4 ;
        RECT  36.528 39.648 36.72 39.672 ;
    END
  END dq[217]
  PIN dq[218]
    DIRECTION OUTPUT ;
    USE SIGNAL ;
    PORT
      LAYER M4 ;
        RECT  36.528 39.792 36.72 39.816 ;
    END
  END dq[218]
  PIN dq[219]
    DIRECTION OUTPUT ;
    USE SIGNAL ;
    PORT
      LAYER M4 ;
        RECT  36.528 39.936 36.72 39.96 ;
    END
  END dq[219]
  PIN dq[21]
    DIRECTION OUTPUT ;
    USE SIGNAL ;
    PORT
      LAYER M4 ;
        RECT  36.528 7.824 36.72 7.848 ;
    END
  END dq[21]
  PIN dq[220]
    DIRECTION OUTPUT ;
    USE SIGNAL ;
    PORT
      LAYER M4 ;
        RECT  36.528 40.128 36.72 40.152 ;
    END
  END dq[220]
  PIN dq[221]
    DIRECTION OUTPUT ;
    USE SIGNAL ;
    PORT
      LAYER M4 ;
        RECT  36.528 40.272 36.72 40.296 ;
    END
  END dq[221]
  PIN dq[222]
    DIRECTION OUTPUT ;
    USE SIGNAL ;
    PORT
      LAYER M4 ;
        RECT  36.528 40.464 36.72 40.488 ;
    END
  END dq[222]
  PIN dq[223]
    DIRECTION OUTPUT ;
    USE SIGNAL ;
    PORT
      LAYER M4 ;
        RECT  36.528 40.608 36.72 40.632 ;
    END
  END dq[223]
  PIN dq[224]
    DIRECTION OUTPUT ;
    USE SIGNAL ;
    PORT
      LAYER M4 ;
        RECT  36.528 40.752 36.72 40.776 ;
    END
  END dq[224]
  PIN dq[225]
    DIRECTION OUTPUT ;
    USE SIGNAL ;
    PORT
      LAYER M4 ;
        RECT  36.528 40.944 36.72 40.968 ;
    END
  END dq[225]
  PIN dq[226]
    DIRECTION OUTPUT ;
    USE SIGNAL ;
    PORT
      LAYER M4 ;
        RECT  36.528 41.088 36.72 41.112 ;
    END
  END dq[226]
  PIN dq[227]
    DIRECTION OUTPUT ;
    USE SIGNAL ;
    PORT
      LAYER M4 ;
        RECT  36.528 41.28 36.72 41.304 ;
    END
  END dq[227]
  PIN dq[228]
    DIRECTION OUTPUT ;
    USE SIGNAL ;
    PORT
      LAYER M4 ;
        RECT  36.528 41.424 36.72 41.448 ;
    END
  END dq[228]
  PIN dq[229]
    DIRECTION OUTPUT ;
    USE SIGNAL ;
    PORT
      LAYER M4 ;
        RECT  36.528 41.568 36.72 41.592 ;
    END
  END dq[229]
  PIN dq[22]
    DIRECTION OUTPUT ;
    USE SIGNAL ;
    PORT
      LAYER M4 ;
        RECT  36.528 7.968 36.72 7.992 ;
    END
  END dq[22]
  PIN dq[230]
    DIRECTION OUTPUT ;
    USE SIGNAL ;
    PORT
      LAYER M4 ;
        RECT  36.528 41.76 36.72 41.784 ;
    END
  END dq[230]
  PIN dq[231]
    DIRECTION OUTPUT ;
    USE SIGNAL ;
    PORT
      LAYER M4 ;
        RECT  36.528 41.904 36.72 41.928 ;
    END
  END dq[231]
  PIN dq[232]
    DIRECTION OUTPUT ;
    USE SIGNAL ;
    PORT
      LAYER M4 ;
        RECT  36.528 42.048 36.72 42.072 ;
    END
  END dq[232]
  PIN dq[233]
    DIRECTION OUTPUT ;
    USE SIGNAL ;
    PORT
      LAYER M4 ;
        RECT  36.528 42.24 36.72 42.264 ;
    END
  END dq[233]
  PIN dq[234]
    DIRECTION OUTPUT ;
    USE SIGNAL ;
    PORT
      LAYER M4 ;
        RECT  36.528 42.384 36.72 42.408 ;
    END
  END dq[234]
  PIN dq[235]
    DIRECTION OUTPUT ;
    USE SIGNAL ;
    PORT
      LAYER M4 ;
        RECT  36.528 42.576 36.72 42.6 ;
    END
  END dq[235]
  PIN dq[236]
    DIRECTION OUTPUT ;
    USE SIGNAL ;
    PORT
      LAYER M4 ;
        RECT  36.528 42.72 36.72 42.744 ;
    END
  END dq[236]
  PIN dq[237]
    DIRECTION OUTPUT ;
    USE SIGNAL ;
    PORT
      LAYER M4 ;
        RECT  36.528 42.864 36.72 42.888 ;
    END
  END dq[237]
  PIN dq[238]
    DIRECTION OUTPUT ;
    USE SIGNAL ;
    PORT
      LAYER M4 ;
        RECT  36.528 43.056 36.72 43.08 ;
    END
  END dq[238]
  PIN dq[239]
    DIRECTION OUTPUT ;
    USE SIGNAL ;
    PORT
      LAYER M4 ;
        RECT  36.528 43.2 36.72 43.224 ;
    END
  END dq[239]
  PIN dq[23]
    DIRECTION OUTPUT ;
    USE SIGNAL ;
    PORT
      LAYER M4 ;
        RECT  36.528 8.16 36.72 8.184 ;
    END
  END dq[23]
  PIN dq[240]
    DIRECTION OUTPUT ;
    USE SIGNAL ;
    PORT
      LAYER M4 ;
        RECT  36.528 43.392 36.72 43.416 ;
    END
  END dq[240]
  PIN dq[241]
    DIRECTION OUTPUT ;
    USE SIGNAL ;
    PORT
      LAYER M4 ;
        RECT  36.528 43.536 36.72 43.56 ;
    END
  END dq[241]
  PIN dq[242]
    DIRECTION OUTPUT ;
    USE SIGNAL ;
    PORT
      LAYER M4 ;
        RECT  36.528 43.68 36.72 43.704 ;
    END
  END dq[242]
  PIN dq[243]
    DIRECTION OUTPUT ;
    USE SIGNAL ;
    PORT
      LAYER M4 ;
        RECT  36.528 43.872 36.72 43.896 ;
    END
  END dq[243]
  PIN dq[244]
    DIRECTION OUTPUT ;
    USE SIGNAL ;
    PORT
      LAYER M4 ;
        RECT  36.528 44.016 36.72 44.04 ;
    END
  END dq[244]
  PIN dq[245]
    DIRECTION OUTPUT ;
    USE SIGNAL ;
    PORT
      LAYER M4 ;
        RECT  36.528 44.16 36.72 44.184 ;
    END
  END dq[245]
  PIN dq[246]
    DIRECTION OUTPUT ;
    USE SIGNAL ;
    PORT
      LAYER M4 ;
        RECT  36.528 44.352 36.72 44.376 ;
    END
  END dq[246]
  PIN dq[247]
    DIRECTION OUTPUT ;
    USE SIGNAL ;
    PORT
      LAYER M4 ;
        RECT  36.528 44.496 36.72 44.52 ;
    END
  END dq[247]
  PIN dq[248]
    DIRECTION OUTPUT ;
    USE SIGNAL ;
    PORT
      LAYER M4 ;
        RECT  36.528 44.688 36.72 44.712 ;
    END
  END dq[248]
  PIN dq[249]
    DIRECTION OUTPUT ;
    USE SIGNAL ;
    PORT
      LAYER M4 ;
        RECT  36.528 44.832 36.72 44.856 ;
    END
  END dq[249]
  PIN dq[24]
    DIRECTION OUTPUT ;
    USE SIGNAL ;
    PORT
      LAYER M4 ;
        RECT  36.528 8.304 36.72 8.328 ;
    END
  END dq[24]
  PIN dq[250]
    DIRECTION OUTPUT ;
    USE SIGNAL ;
    PORT
      LAYER M4 ;
        RECT  36.528 44.976 36.72 45 ;
    END
  END dq[250]
  PIN dq[251]
    DIRECTION OUTPUT ;
    USE SIGNAL ;
    PORT
      LAYER M4 ;
        RECT  36.528 45.168 36.72 45.192 ;
    END
  END dq[251]
  PIN dq[252]
    DIRECTION OUTPUT ;
    USE SIGNAL ;
    PORT
      LAYER M4 ;
        RECT  36.528 45.312 36.72 45.336 ;
    END
  END dq[252]
  PIN dq[253]
    DIRECTION OUTPUT ;
    USE SIGNAL ;
    PORT
      LAYER M4 ;
        RECT  36.528 45.456 36.72 45.48 ;
    END
  END dq[253]
  PIN dq[254]
    DIRECTION OUTPUT ;
    USE SIGNAL ;
    PORT
      LAYER M4 ;
        RECT  36.528 45.648 36.72 45.672 ;
    END
  END dq[254]
  PIN dq[255]
    DIRECTION OUTPUT ;
    USE SIGNAL ;
    PORT
      LAYER M4 ;
        RECT  36.528 45.792 36.72 45.816 ;
    END
  END dq[255]
  PIN dq[256]
    DIRECTION OUTPUT ;
    USE SIGNAL ;
    PORT
      LAYER M4 ;
        RECT  36.528 45.984 36.72 46.008 ;
    END
  END dq[256]
  PIN dq[257]
    DIRECTION OUTPUT ;
    USE SIGNAL ;
    PORT
      LAYER M4 ;
        RECT  36.528 46.128 36.72 46.152 ;
    END
  END dq[257]
  PIN dq[258]
    DIRECTION OUTPUT ;
    USE SIGNAL ;
    PORT
      LAYER M4 ;
        RECT  36.528 46.272 36.72 46.296 ;
    END
  END dq[258]
  PIN dq[259]
    DIRECTION OUTPUT ;
    USE SIGNAL ;
    PORT
      LAYER M4 ;
        RECT  36.528 46.464 36.72 46.488 ;
    END
  END dq[259]
  PIN dq[25]
    DIRECTION OUTPUT ;
    USE SIGNAL ;
    PORT
      LAYER M4 ;
        RECT  36.528 8.448 36.72 8.472 ;
    END
  END dq[25]
  PIN dq[260]
    DIRECTION OUTPUT ;
    USE SIGNAL ;
    PORT
      LAYER M4 ;
        RECT  36.528 46.608 36.72 46.632 ;
    END
  END dq[260]
  PIN dq[261]
    DIRECTION OUTPUT ;
    USE SIGNAL ;
    PORT
      LAYER M4 ;
        RECT  36.528 46.8 36.72 46.824 ;
    END
  END dq[261]
  PIN dq[262]
    DIRECTION OUTPUT ;
    USE SIGNAL ;
    PORT
      LAYER M4 ;
        RECT  36.528 46.944 36.72 46.968 ;
    END
  END dq[262]
  PIN dq[263]
    DIRECTION OUTPUT ;
    USE SIGNAL ;
    PORT
      LAYER M4 ;
        RECT  36.528 47.088 36.72 47.112 ;
    END
  END dq[263]
  PIN dq[264]
    DIRECTION OUTPUT ;
    USE SIGNAL ;
    PORT
      LAYER M4 ;
        RECT  36.528 47.28 36.72 47.304 ;
    END
  END dq[264]
  PIN dq[265]
    DIRECTION OUTPUT ;
    USE SIGNAL ;
    PORT
      LAYER M4 ;
        RECT  36.528 47.424 36.72 47.448 ;
    END
  END dq[265]
  PIN dq[266]
    DIRECTION OUTPUT ;
    USE SIGNAL ;
    PORT
      LAYER M4 ;
        RECT  36.528 47.568 36.72 47.592 ;
    END
  END dq[266]
  PIN dq[267]
    DIRECTION OUTPUT ;
    USE SIGNAL ;
    PORT
      LAYER M4 ;
        RECT  36.528 47.76 36.72 47.784 ;
    END
  END dq[267]
  PIN dq[268]
    DIRECTION OUTPUT ;
    USE SIGNAL ;
    PORT
      LAYER M4 ;
        RECT  36.528 47.904 36.72 47.928 ;
    END
  END dq[268]
  PIN dq[269]
    DIRECTION OUTPUT ;
    USE SIGNAL ;
    PORT
      LAYER M4 ;
        RECT  36.528 48.096 36.72 48.12 ;
    END
  END dq[269]
  PIN dq[26]
    DIRECTION OUTPUT ;
    USE SIGNAL ;
    PORT
      LAYER M4 ;
        RECT  36.528 8.64 36.72 8.664 ;
    END
  END dq[26]
  PIN dq[270]
    DIRECTION OUTPUT ;
    USE SIGNAL ;
    PORT
      LAYER M4 ;
        RECT  36.528 48.24 36.72 48.264 ;
    END
  END dq[270]
  PIN dq[271]
    DIRECTION OUTPUT ;
    USE SIGNAL ;
    PORT
      LAYER M4 ;
        RECT  36.528 48.384 36.72 48.408 ;
    END
  END dq[271]
  PIN dq[272]
    DIRECTION OUTPUT ;
    USE SIGNAL ;
    PORT
      LAYER M4 ;
        RECT  36.528 48.576 36.72 48.6 ;
    END
  END dq[272]
  PIN dq[273]
    DIRECTION OUTPUT ;
    USE SIGNAL ;
    PORT
      LAYER M4 ;
        RECT  36.528 48.72 36.72 48.744 ;
    END
  END dq[273]
  PIN dq[274]
    DIRECTION OUTPUT ;
    USE SIGNAL ;
    PORT
      LAYER M4 ;
        RECT  36.528 48.864 36.72 48.888 ;
    END
  END dq[274]
  PIN dq[275]
    DIRECTION OUTPUT ;
    USE SIGNAL ;
    PORT
      LAYER M4 ;
        RECT  36.528 49.056 36.72 49.08 ;
    END
  END dq[275]
  PIN dq[276]
    DIRECTION OUTPUT ;
    USE SIGNAL ;
    PORT
      LAYER M4 ;
        RECT  36.528 49.2 36.72 49.224 ;
    END
  END dq[276]
  PIN dq[277]
    DIRECTION OUTPUT ;
    USE SIGNAL ;
    PORT
      LAYER M4 ;
        RECT  36.528 49.392 36.72 49.416 ;
    END
  END dq[277]
  PIN dq[278]
    DIRECTION OUTPUT ;
    USE SIGNAL ;
    PORT
      LAYER M4 ;
        RECT  36.528 49.536 36.72 49.56 ;
    END
  END dq[278]
  PIN dq[279]
    DIRECTION OUTPUT ;
    USE SIGNAL ;
    PORT
      LAYER M4 ;
        RECT  36.528 49.68 36.72 49.704 ;
    END
  END dq[279]
  PIN dq[27]
    DIRECTION OUTPUT ;
    USE SIGNAL ;
    PORT
      LAYER M4 ;
        RECT  36.528 8.784 36.72 8.808 ;
    END
  END dq[27]
  PIN dq[280]
    DIRECTION OUTPUT ;
    USE SIGNAL ;
    PORT
      LAYER M4 ;
        RECT  36.528 49.872 36.72 49.896 ;
    END
  END dq[280]
  PIN dq[281]
    DIRECTION OUTPUT ;
    USE SIGNAL ;
    PORT
      LAYER M4 ;
        RECT  36.528 50.016 36.72 50.04 ;
    END
  END dq[281]
  PIN dq[282]
    DIRECTION OUTPUT ;
    USE SIGNAL ;
    PORT
      LAYER M4 ;
        RECT  36.528 50.208 36.72 50.232 ;
    END
  END dq[282]
  PIN dq[283]
    DIRECTION OUTPUT ;
    USE SIGNAL ;
    PORT
      LAYER M4 ;
        RECT  36.528 50.352 36.72 50.376 ;
    END
  END dq[283]
  PIN dq[284]
    DIRECTION OUTPUT ;
    USE SIGNAL ;
    PORT
      LAYER M4 ;
        RECT  36.528 50.496 36.72 50.52 ;
    END
  END dq[284]
  PIN dq[285]
    DIRECTION OUTPUT ;
    USE SIGNAL ;
    PORT
      LAYER M4 ;
        RECT  36.528 50.688 36.72 50.712 ;
    END
  END dq[285]
  PIN dq[286]
    DIRECTION OUTPUT ;
    USE SIGNAL ;
    PORT
      LAYER M4 ;
        RECT  36.528 50.832 36.72 50.856 ;
    END
  END dq[286]
  PIN dq[287]
    DIRECTION OUTPUT ;
    USE SIGNAL ;
    PORT
      LAYER M4 ;
        RECT  36.528 50.976 36.72 51 ;
    END
  END dq[287]
  PIN dq[288]
    DIRECTION OUTPUT ;
    USE SIGNAL ;
    PORT
      LAYER M4 ;
        RECT  36.528 51.168 36.72 51.192 ;
    END
  END dq[288]
  PIN dq[289]
    DIRECTION OUTPUT ;
    USE SIGNAL ;
    PORT
      LAYER M4 ;
        RECT  36.528 51.312 36.72 51.336 ;
    END
  END dq[289]
  PIN dq[28]
    DIRECTION OUTPUT ;
    USE SIGNAL ;
    PORT
      LAYER M4 ;
        RECT  36.528 8.976 36.72 9 ;
    END
  END dq[28]
  PIN dq[290]
    DIRECTION OUTPUT ;
    USE SIGNAL ;
    PORT
      LAYER M4 ;
        RECT  36.528 51.504 36.72 51.528 ;
    END
  END dq[290]
  PIN dq[291]
    DIRECTION OUTPUT ;
    USE SIGNAL ;
    PORT
      LAYER M4 ;
        RECT  36.528 51.648 36.72 51.672 ;
    END
  END dq[291]
  PIN dq[292]
    DIRECTION OUTPUT ;
    USE SIGNAL ;
    PORT
      LAYER M4 ;
        RECT  36.528 51.792 36.72 51.816 ;
    END
  END dq[292]
  PIN dq[293]
    DIRECTION OUTPUT ;
    USE SIGNAL ;
    PORT
      LAYER M4 ;
        RECT  36.528 51.984 36.72 52.008 ;
    END
  END dq[293]
  PIN dq[294]
    DIRECTION OUTPUT ;
    USE SIGNAL ;
    PORT
      LAYER M4 ;
        RECT  36.528 52.128 36.72 52.152 ;
    END
  END dq[294]
  PIN dq[295]
    DIRECTION OUTPUT ;
    USE SIGNAL ;
    PORT
      LAYER M4 ;
        RECT  36.528 52.272 36.72 52.296 ;
    END
  END dq[295]
  PIN dq[296]
    DIRECTION OUTPUT ;
    USE SIGNAL ;
    PORT
      LAYER M4 ;
        RECT  36.528 52.464 36.72 52.488 ;
    END
  END dq[296]
  PIN dq[297]
    DIRECTION OUTPUT ;
    USE SIGNAL ;
    PORT
      LAYER M4 ;
        RECT  36.528 52.608 36.72 52.632 ;
    END
  END dq[297]
  PIN dq[298]
    DIRECTION OUTPUT ;
    USE SIGNAL ;
    PORT
      LAYER M4 ;
        RECT  36.528 52.8 36.72 52.824 ;
    END
  END dq[298]
  PIN dq[299]
    DIRECTION OUTPUT ;
    USE SIGNAL ;
    PORT
      LAYER M4 ;
        RECT  36.528 52.944 36.72 52.968 ;
    END
  END dq[299]
  PIN dq[29]
    DIRECTION OUTPUT ;
    USE SIGNAL ;
    PORT
      LAYER M4 ;
        RECT  36.528 9.12 36.72 9.144 ;
    END
  END dq[29]
  PIN dq[2]
    DIRECTION OUTPUT ;
    USE SIGNAL ;
    PORT
      LAYER M4 ;
        RECT  36.528 4.752 36.72 4.776 ;
    END
  END dq[2]
  PIN dq[300]
    DIRECTION OUTPUT ;
    USE SIGNAL ;
    PORT
      LAYER M4 ;
        RECT  36.528 53.088 36.72 53.112 ;
    END
  END dq[300]
  PIN dq[301]
    DIRECTION OUTPUT ;
    USE SIGNAL ;
    PORT
      LAYER M4 ;
        RECT  36.528 53.28 36.72 53.304 ;
    END
  END dq[301]
  PIN dq[302]
    DIRECTION OUTPUT ;
    USE SIGNAL ;
    PORT
      LAYER M4 ;
        RECT  36.528 53.424 36.72 53.448 ;
    END
  END dq[302]
  PIN dq[303]
    DIRECTION OUTPUT ;
    USE SIGNAL ;
    PORT
      LAYER M4 ;
        RECT  36.528 53.616 36.72 53.64 ;
    END
  END dq[303]
  PIN dq[304]
    DIRECTION OUTPUT ;
    USE SIGNAL ;
    PORT
      LAYER M4 ;
        RECT  36.528 53.76 36.72 53.784 ;
    END
  END dq[304]
  PIN dq[305]
    DIRECTION OUTPUT ;
    USE SIGNAL ;
    PORT
      LAYER M4 ;
        RECT  36.528 53.904 36.72 53.928 ;
    END
  END dq[305]
  PIN dq[306]
    DIRECTION OUTPUT ;
    USE SIGNAL ;
    PORT
      LAYER M4 ;
        RECT  36.528 54.096 36.72 54.12 ;
    END
  END dq[306]
  PIN dq[307]
    DIRECTION OUTPUT ;
    USE SIGNAL ;
    PORT
      LAYER M4 ;
        RECT  36.528 54.24 36.72 54.264 ;
    END
  END dq[307]
  PIN dq[308]
    DIRECTION OUTPUT ;
    USE SIGNAL ;
    PORT
      LAYER M4 ;
        RECT  36.528 54.384 36.72 54.408 ;
    END
  END dq[308]
  PIN dq[309]
    DIRECTION OUTPUT ;
    USE SIGNAL ;
    PORT
      LAYER M4 ;
        RECT  36.528 54.576 36.72 54.6 ;
    END
  END dq[309]
  PIN dq[30]
    DIRECTION OUTPUT ;
    USE SIGNAL ;
    PORT
      LAYER M4 ;
        RECT  36.528 9.264 36.72 9.288 ;
    END
  END dq[30]
  PIN dq[310]
    DIRECTION OUTPUT ;
    USE SIGNAL ;
    PORT
      LAYER M4 ;
        RECT  36.528 54.72 36.72 54.744 ;
    END
  END dq[310]
  PIN dq[311]
    DIRECTION OUTPUT ;
    USE SIGNAL ;
    PORT
      LAYER M4 ;
        RECT  36.528 54.912 36.72 54.936 ;
    END
  END dq[311]
  PIN dq[312]
    DIRECTION OUTPUT ;
    USE SIGNAL ;
    PORT
      LAYER M4 ;
        RECT  36.528 55.056 36.72 55.08 ;
    END
  END dq[312]
  PIN dq[313]
    DIRECTION OUTPUT ;
    USE SIGNAL ;
    PORT
      LAYER M4 ;
        RECT  36.528 55.2 36.72 55.224 ;
    END
  END dq[313]
  PIN dq[314]
    DIRECTION OUTPUT ;
    USE SIGNAL ;
    PORT
      LAYER M4 ;
        RECT  36.528 55.392 36.72 55.416 ;
    END
  END dq[314]
  PIN dq[315]
    DIRECTION OUTPUT ;
    USE SIGNAL ;
    PORT
      LAYER M4 ;
        RECT  36.528 55.536 36.72 55.56 ;
    END
  END dq[315]
  PIN dq[316]
    DIRECTION OUTPUT ;
    USE SIGNAL ;
    PORT
      LAYER M4 ;
        RECT  36.528 55.68 36.72 55.704 ;
    END
  END dq[316]
  PIN dq[317]
    DIRECTION OUTPUT ;
    USE SIGNAL ;
    PORT
      LAYER M4 ;
        RECT  36.528 55.872 36.72 55.896 ;
    END
  END dq[317]
  PIN dq[318]
    DIRECTION OUTPUT ;
    USE SIGNAL ;
    PORT
      LAYER M4 ;
        RECT  36.528 56.016 36.72 56.04 ;
    END
  END dq[318]
  PIN dq[319]
    DIRECTION OUTPUT ;
    USE SIGNAL ;
    PORT
      LAYER M4 ;
        RECT  36.528 56.208 36.72 56.232 ;
    END
  END dq[319]
  PIN dq[31]
    DIRECTION OUTPUT ;
    USE SIGNAL ;
    PORT
      LAYER M4 ;
        RECT  36.528 9.456 36.72 9.48 ;
    END
  END dq[31]
  PIN dq[320]
    DIRECTION OUTPUT ;
    USE SIGNAL ;
    PORT
      LAYER M4 ;
        RECT  36.528 56.352 36.72 56.376 ;
    END
  END dq[320]
  PIN dq[321]
    DIRECTION OUTPUT ;
    USE SIGNAL ;
    PORT
      LAYER M4 ;
        RECT  36.528 56.496 36.72 56.52 ;
    END
  END dq[321]
  PIN dq[322]
    DIRECTION OUTPUT ;
    USE SIGNAL ;
    PORT
      LAYER M4 ;
        RECT  36.528 56.688 36.72 56.712 ;
    END
  END dq[322]
  PIN dq[323]
    DIRECTION OUTPUT ;
    USE SIGNAL ;
    PORT
      LAYER M4 ;
        RECT  36.528 56.832 36.72 56.856 ;
    END
  END dq[323]
  PIN dq[324]
    DIRECTION OUTPUT ;
    USE SIGNAL ;
    PORT
      LAYER M4 ;
        RECT  36.528 57.024 36.72 57.048 ;
    END
  END dq[324]
  PIN dq[325]
    DIRECTION OUTPUT ;
    USE SIGNAL ;
    PORT
      LAYER M4 ;
        RECT  36.528 57.168 36.72 57.192 ;
    END
  END dq[325]
  PIN dq[326]
    DIRECTION OUTPUT ;
    USE SIGNAL ;
    PORT
      LAYER M4 ;
        RECT  36.528 57.312 36.72 57.336 ;
    END
  END dq[326]
  PIN dq[327]
    DIRECTION OUTPUT ;
    USE SIGNAL ;
    PORT
      LAYER M4 ;
        RECT  36.528 57.504 36.72 57.528 ;
    END
  END dq[327]
  PIN dq[328]
    DIRECTION OUTPUT ;
    USE SIGNAL ;
    PORT
      LAYER M4 ;
        RECT  36.528 57.648 36.72 57.672 ;
    END
  END dq[328]
  PIN dq[329]
    DIRECTION OUTPUT ;
    USE SIGNAL ;
    PORT
      LAYER M4 ;
        RECT  36.528 57.792 36.72 57.816 ;
    END
  END dq[329]
  PIN dq[32]
    DIRECTION OUTPUT ;
    USE SIGNAL ;
    PORT
      LAYER M4 ;
        RECT  36.528 9.6 36.72 9.624 ;
    END
  END dq[32]
  PIN dq[330]
    DIRECTION OUTPUT ;
    USE SIGNAL ;
    PORT
      LAYER M4 ;
        RECT  36.528 57.984 36.72 58.008 ;
    END
  END dq[330]
  PIN dq[331]
    DIRECTION OUTPUT ;
    USE SIGNAL ;
    PORT
      LAYER M4 ;
        RECT  36.528 58.128 36.72 58.152 ;
    END
  END dq[331]
  PIN dq[332]
    DIRECTION OUTPUT ;
    USE SIGNAL ;
    PORT
      LAYER M4 ;
        RECT  36.528 58.32 36.72 58.344 ;
    END
  END dq[332]
  PIN dq[333]
    DIRECTION OUTPUT ;
    USE SIGNAL ;
    PORT
      LAYER M4 ;
        RECT  36.528 58.464 36.72 58.488 ;
    END
  END dq[333]
  PIN dq[334]
    DIRECTION OUTPUT ;
    USE SIGNAL ;
    PORT
      LAYER M4 ;
        RECT  36.528 58.608 36.72 58.632 ;
    END
  END dq[334]
  PIN dq[335]
    DIRECTION OUTPUT ;
    USE SIGNAL ;
    PORT
      LAYER M4 ;
        RECT  36.528 58.8 36.72 58.824 ;
    END
  END dq[335]
  PIN dq[336]
    DIRECTION OUTPUT ;
    USE SIGNAL ;
    PORT
      LAYER M4 ;
        RECT  36.528 58.944 36.72 58.968 ;
    END
  END dq[336]
  PIN dq[337]
    DIRECTION OUTPUT ;
    USE SIGNAL ;
    PORT
      LAYER M4 ;
        RECT  36.528 59.136 36.72 59.16 ;
    END
  END dq[337]
  PIN dq[338]
    DIRECTION OUTPUT ;
    USE SIGNAL ;
    PORT
      LAYER M4 ;
        RECT  36.528 59.28 36.72 59.304 ;
    END
  END dq[338]
  PIN dq[339]
    DIRECTION OUTPUT ;
    USE SIGNAL ;
    PORT
      LAYER M4 ;
        RECT  36.528 59.424 36.72 59.448 ;
    END
  END dq[339]
  PIN dq[33]
    DIRECTION OUTPUT ;
    USE SIGNAL ;
    PORT
      LAYER M4 ;
        RECT  36.528 9.792 36.72 9.816 ;
    END
  END dq[33]
  PIN dq[340]
    DIRECTION OUTPUT ;
    USE SIGNAL ;
    PORT
      LAYER M4 ;
        RECT  36.528 59.616 36.72 59.64 ;
    END
  END dq[340]
  PIN dq[341]
    DIRECTION OUTPUT ;
    USE SIGNAL ;
    PORT
      LAYER M4 ;
        RECT  36.528 59.76 36.72 59.784 ;
    END
  END dq[341]
  PIN dq[342]
    DIRECTION OUTPUT ;
    USE SIGNAL ;
    PORT
      LAYER M4 ;
        RECT  36.528 59.904 36.72 59.928 ;
    END
  END dq[342]
  PIN dq[343]
    DIRECTION OUTPUT ;
    USE SIGNAL ;
    PORT
      LAYER M4 ;
        RECT  36.528 60.096 36.72 60.12 ;
    END
  END dq[343]
  PIN dq[344]
    DIRECTION OUTPUT ;
    USE SIGNAL ;
    PORT
      LAYER M4 ;
        RECT  36.528 60.24 36.72 60.264 ;
    END
  END dq[344]
  PIN dq[345]
    DIRECTION OUTPUT ;
    USE SIGNAL ;
    PORT
      LAYER M4 ;
        RECT  36.528 60.432 36.72 60.456 ;
    END
  END dq[345]
  PIN dq[346]
    DIRECTION OUTPUT ;
    USE SIGNAL ;
    PORT
      LAYER M4 ;
        RECT  36.528 60.576 36.72 60.6 ;
    END
  END dq[346]
  PIN dq[347]
    DIRECTION OUTPUT ;
    USE SIGNAL ;
    PORT
      LAYER M4 ;
        RECT  36.528 60.72 36.72 60.744 ;
    END
  END dq[347]
  PIN dq[348]
    DIRECTION OUTPUT ;
    USE SIGNAL ;
    PORT
      LAYER M4 ;
        RECT  36.528 60.912 36.72 60.936 ;
    END
  END dq[348]
  PIN dq[349]
    DIRECTION OUTPUT ;
    USE SIGNAL ;
    PORT
      LAYER M4 ;
        RECT  36.528 61.056 36.72 61.08 ;
    END
  END dq[349]
  PIN dq[34]
    DIRECTION OUTPUT ;
    USE SIGNAL ;
    PORT
      LAYER M4 ;
        RECT  36.528 9.936 36.72 9.96 ;
    END
  END dq[34]
  PIN dq[350]
    DIRECTION OUTPUT ;
    USE SIGNAL ;
    PORT
      LAYER M4 ;
        RECT  36.528 61.2 36.72 61.224 ;
    END
  END dq[350]
  PIN dq[351]
    DIRECTION OUTPUT ;
    USE SIGNAL ;
    PORT
      LAYER M4 ;
        RECT  36.528 61.392 36.72 61.416 ;
    END
  END dq[351]
  PIN dq[352]
    DIRECTION OUTPUT ;
    USE SIGNAL ;
    PORT
      LAYER M4 ;
        RECT  36.528 61.536 36.72 61.56 ;
    END
  END dq[352]
  PIN dq[353]
    DIRECTION OUTPUT ;
    USE SIGNAL ;
    PORT
      LAYER M4 ;
        RECT  36.528 61.728 36.72 61.752 ;
    END
  END dq[353]
  PIN dq[354]
    DIRECTION OUTPUT ;
    USE SIGNAL ;
    PORT
      LAYER M4 ;
        RECT  36.528 61.872 36.72 61.896 ;
    END
  END dq[354]
  PIN dq[355]
    DIRECTION OUTPUT ;
    USE SIGNAL ;
    PORT
      LAYER M4 ;
        RECT  36.528 62.016 36.72 62.04 ;
    END
  END dq[355]
  PIN dq[356]
    DIRECTION OUTPUT ;
    USE SIGNAL ;
    PORT
      LAYER M4 ;
        RECT  36.528 62.208 36.72 62.232 ;
    END
  END dq[356]
  PIN dq[357]
    DIRECTION OUTPUT ;
    USE SIGNAL ;
    PORT
      LAYER M4 ;
        RECT  36.528 62.352 36.72 62.376 ;
    END
  END dq[357]
  PIN dq[358]
    DIRECTION OUTPUT ;
    USE SIGNAL ;
    PORT
      LAYER M4 ;
        RECT  36.528 62.544 36.72 62.568 ;
    END
  END dq[358]
  PIN dq[359]
    DIRECTION OUTPUT ;
    USE SIGNAL ;
    PORT
      LAYER M4 ;
        RECT  36.528 62.688 36.72 62.712 ;
    END
  END dq[359]
  PIN dq[35]
    DIRECTION OUTPUT ;
    USE SIGNAL ;
    PORT
      LAYER M4 ;
        RECT  36.528 10.08 36.72 10.104 ;
    END
  END dq[35]
  PIN dq[360]
    DIRECTION OUTPUT ;
    USE SIGNAL ;
    PORT
      LAYER M4 ;
        RECT  36.528 62.832 36.72 62.856 ;
    END
  END dq[360]
  PIN dq[361]
    DIRECTION OUTPUT ;
    USE SIGNAL ;
    PORT
      LAYER M4 ;
        RECT  36.528 63.024 36.72 63.048 ;
    END
  END dq[361]
  PIN dq[362]
    DIRECTION OUTPUT ;
    USE SIGNAL ;
    PORT
      LAYER M4 ;
        RECT  36.528 63.168 36.72 63.192 ;
    END
  END dq[362]
  PIN dq[363]
    DIRECTION OUTPUT ;
    USE SIGNAL ;
    PORT
      LAYER M4 ;
        RECT  36.528 63.312 36.72 63.336 ;
    END
  END dq[363]
  PIN dq[364]
    DIRECTION OUTPUT ;
    USE SIGNAL ;
    PORT
      LAYER M4 ;
        RECT  36.528 63.504 36.72 63.528 ;
    END
  END dq[364]
  PIN dq[365]
    DIRECTION OUTPUT ;
    USE SIGNAL ;
    PORT
      LAYER M4 ;
        RECT  36.528 63.648 36.72 63.672 ;
    END
  END dq[365]
  PIN dq[366]
    DIRECTION OUTPUT ;
    USE SIGNAL ;
    PORT
      LAYER M4 ;
        RECT  36.528 63.84 36.72 63.864 ;
    END
  END dq[366]
  PIN dq[367]
    DIRECTION OUTPUT ;
    USE SIGNAL ;
    PORT
      LAYER M4 ;
        RECT  36.528 63.984 36.72 64.008 ;
    END
  END dq[367]
  PIN dq[368]
    DIRECTION OUTPUT ;
    USE SIGNAL ;
    PORT
      LAYER M4 ;
        RECT  36.528 64.128 36.72 64.152 ;
    END
  END dq[368]
  PIN dq[369]
    DIRECTION OUTPUT ;
    USE SIGNAL ;
    PORT
      LAYER M4 ;
        RECT  36.528 64.32 36.72 64.344 ;
    END
  END dq[369]
  PIN dq[36]
    DIRECTION OUTPUT ;
    USE SIGNAL ;
    PORT
      LAYER M4 ;
        RECT  36.528 10.272 36.72 10.296 ;
    END
  END dq[36]
  PIN dq[370]
    DIRECTION OUTPUT ;
    USE SIGNAL ;
    PORT
      LAYER M4 ;
        RECT  36.528 64.464 36.72 64.488 ;
    END
  END dq[370]
  PIN dq[371]
    DIRECTION OUTPUT ;
    USE SIGNAL ;
    PORT
      LAYER M4 ;
        RECT  36.528 64.608 36.72 64.632 ;
    END
  END dq[371]
  PIN dq[372]
    DIRECTION OUTPUT ;
    USE SIGNAL ;
    PORT
      LAYER M4 ;
        RECT  36.528 64.8 36.72 64.824 ;
    END
  END dq[372]
  PIN dq[373]
    DIRECTION OUTPUT ;
    USE SIGNAL ;
    PORT
      LAYER M4 ;
        RECT  36.528 64.944 36.72 64.968 ;
    END
  END dq[373]
  PIN dq[374]
    DIRECTION OUTPUT ;
    USE SIGNAL ;
    PORT
      LAYER M4 ;
        RECT  36.528 65.136 36.72 65.16 ;
    END
  END dq[374]
  PIN dq[375]
    DIRECTION OUTPUT ;
    USE SIGNAL ;
    PORT
      LAYER M4 ;
        RECT  36.528 65.28 36.72 65.304 ;
    END
  END dq[375]
  PIN dq[376]
    DIRECTION OUTPUT ;
    USE SIGNAL ;
    PORT
      LAYER M4 ;
        RECT  36.528 65.424 36.72 65.448 ;
    END
  END dq[376]
  PIN dq[377]
    DIRECTION OUTPUT ;
    USE SIGNAL ;
    PORT
      LAYER M4 ;
        RECT  36.528 65.616 36.72 65.64 ;
    END
  END dq[377]
  PIN dq[378]
    DIRECTION OUTPUT ;
    USE SIGNAL ;
    PORT
      LAYER M4 ;
        RECT  36.528 65.76 36.72 65.784 ;
    END
  END dq[378]
  PIN dq[379]
    DIRECTION OUTPUT ;
    USE SIGNAL ;
    PORT
      LAYER M4 ;
        RECT  36.528 65.952 36.72 65.976 ;
    END
  END dq[379]
  PIN dq[37]
    DIRECTION OUTPUT ;
    USE SIGNAL ;
    PORT
      LAYER M4 ;
        RECT  36.528 10.416 36.72 10.44 ;
    END
  END dq[37]
  PIN dq[380]
    DIRECTION OUTPUT ;
    USE SIGNAL ;
    PORT
      LAYER M4 ;
        RECT  36.528 66.096 36.72 66.12 ;
    END
  END dq[380]
  PIN dq[381]
    DIRECTION OUTPUT ;
    USE SIGNAL ;
    PORT
      LAYER M4 ;
        RECT  36.528 66.24 36.72 66.264 ;
    END
  END dq[381]
  PIN dq[382]
    DIRECTION OUTPUT ;
    USE SIGNAL ;
    PORT
      LAYER M4 ;
        RECT  36.528 66.432 36.72 66.456 ;
    END
  END dq[382]
  PIN dq[383]
    DIRECTION OUTPUT ;
    USE SIGNAL ;
    PORT
      LAYER M4 ;
        RECT  36.528 66.576 36.72 66.6 ;
    END
  END dq[383]
  PIN dq[384]
    DIRECTION OUTPUT ;
    USE SIGNAL ;
    PORT
      LAYER M4 ;
        RECT  36.528 66.72 36.72 66.744 ;
    END
  END dq[384]
  PIN dq[385]
    DIRECTION OUTPUT ;
    USE SIGNAL ;
    PORT
      LAYER M4 ;
        RECT  36.528 66.912 36.72 66.936 ;
    END
  END dq[385]
  PIN dq[386]
    DIRECTION OUTPUT ;
    USE SIGNAL ;
    PORT
      LAYER M4 ;
        RECT  36.528 67.056 36.72 67.08 ;
    END
  END dq[386]
  PIN dq[387]
    DIRECTION OUTPUT ;
    USE SIGNAL ;
    PORT
      LAYER M4 ;
        RECT  36.528 67.248 36.72 67.272 ;
    END
  END dq[387]
  PIN dq[388]
    DIRECTION OUTPUT ;
    USE SIGNAL ;
    PORT
      LAYER M4 ;
        RECT  36.528 67.392 36.72 67.416 ;
    END
  END dq[388]
  PIN dq[389]
    DIRECTION OUTPUT ;
    USE SIGNAL ;
    PORT
      LAYER M4 ;
        RECT  36.528 67.536 36.72 67.56 ;
    END
  END dq[389]
  PIN dq[38]
    DIRECTION OUTPUT ;
    USE SIGNAL ;
    PORT
      LAYER M4 ;
        RECT  36.528 10.56 36.72 10.584 ;
    END
  END dq[38]
  PIN dq[390]
    DIRECTION OUTPUT ;
    USE SIGNAL ;
    PORT
      LAYER M4 ;
        RECT  36.528 67.728 36.72 67.752 ;
    END
  END dq[390]
  PIN dq[391]
    DIRECTION OUTPUT ;
    USE SIGNAL ;
    PORT
      LAYER M4 ;
        RECT  36.528 67.872 36.72 67.896 ;
    END
  END dq[391]
  PIN dq[392]
    DIRECTION OUTPUT ;
    USE SIGNAL ;
    PORT
      LAYER M4 ;
        RECT  36.528 68.016 36.72 68.04 ;
    END
  END dq[392]
  PIN dq[393]
    DIRECTION OUTPUT ;
    USE SIGNAL ;
    PORT
      LAYER M4 ;
        RECT  36.528 68.208 36.72 68.232 ;
    END
  END dq[393]
  PIN dq[394]
    DIRECTION OUTPUT ;
    USE SIGNAL ;
    PORT
      LAYER M4 ;
        RECT  36.528 68.352 36.72 68.376 ;
    END
  END dq[394]
  PIN dq[395]
    DIRECTION OUTPUT ;
    USE SIGNAL ;
    PORT
      LAYER M4 ;
        RECT  36.528 68.544 36.72 68.568 ;
    END
  END dq[395]
  PIN dq[396]
    DIRECTION OUTPUT ;
    USE SIGNAL ;
    PORT
      LAYER M4 ;
        RECT  36.528 68.688 36.72 68.712 ;
    END
  END dq[396]
  PIN dq[397]
    DIRECTION OUTPUT ;
    USE SIGNAL ;
    PORT
      LAYER M4 ;
        RECT  36.528 68.832 36.72 68.856 ;
    END
  END dq[397]
  PIN dq[398]
    DIRECTION OUTPUT ;
    USE SIGNAL ;
    PORT
      LAYER M4 ;
        RECT  36.528 69.024 36.72 69.048 ;
    END
  END dq[398]
  PIN dq[399]
    DIRECTION OUTPUT ;
    USE SIGNAL ;
    PORT
      LAYER M4 ;
        RECT  36.528 69.168 36.72 69.192 ;
    END
  END dq[399]
  PIN dq[39]
    DIRECTION OUTPUT ;
    USE SIGNAL ;
    PORT
      LAYER M4 ;
        RECT  36.528 10.752 36.72 10.776 ;
    END
  END dq[39]
  PIN dq[3]
    DIRECTION OUTPUT ;
    USE SIGNAL ;
    PORT
      LAYER M4 ;
        RECT  36.528 4.896 36.72 4.92 ;
    END
  END dq[3]
  PIN dq[400]
    DIRECTION OUTPUT ;
    USE SIGNAL ;
    PORT
      LAYER M4 ;
        RECT  36.528 69.36 36.72 69.384 ;
    END
  END dq[400]
  PIN dq[401]
    DIRECTION OUTPUT ;
    USE SIGNAL ;
    PORT
      LAYER M4 ;
        RECT  36.528 69.504 36.72 69.528 ;
    END
  END dq[401]
  PIN dq[402]
    DIRECTION OUTPUT ;
    USE SIGNAL ;
    PORT
      LAYER M4 ;
        RECT  36.528 69.648 36.72 69.672 ;
    END
  END dq[402]
  PIN dq[403]
    DIRECTION OUTPUT ;
    USE SIGNAL ;
    PORT
      LAYER M4 ;
        RECT  36.528 69.84 36.72 69.864 ;
    END
  END dq[403]
  PIN dq[404]
    DIRECTION OUTPUT ;
    USE SIGNAL ;
    PORT
      LAYER M4 ;
        RECT  36.528 69.984 36.72 70.008 ;
    END
  END dq[404]
  PIN dq[405]
    DIRECTION OUTPUT ;
    USE SIGNAL ;
    PORT
      LAYER M4 ;
        RECT  36.528 70.128 36.72 70.152 ;
    END
  END dq[405]
  PIN dq[406]
    DIRECTION OUTPUT ;
    USE SIGNAL ;
    PORT
      LAYER M4 ;
        RECT  36.528 70.32 36.72 70.344 ;
    END
  END dq[406]
  PIN dq[407]
    DIRECTION OUTPUT ;
    USE SIGNAL ;
    PORT
      LAYER M4 ;
        RECT  36.528 70.464 36.72 70.488 ;
    END
  END dq[407]
  PIN dq[408]
    DIRECTION OUTPUT ;
    USE SIGNAL ;
    PORT
      LAYER M4 ;
        RECT  36.528 70.656 36.72 70.68 ;
    END
  END dq[408]
  PIN dq[409]
    DIRECTION OUTPUT ;
    USE SIGNAL ;
    PORT
      LAYER M4 ;
        RECT  36.528 70.8 36.72 70.824 ;
    END
  END dq[409]
  PIN dq[40]
    DIRECTION OUTPUT ;
    USE SIGNAL ;
    PORT
      LAYER M4 ;
        RECT  36.528 10.896 36.72 10.92 ;
    END
  END dq[40]
  PIN dq[410]
    DIRECTION OUTPUT ;
    USE SIGNAL ;
    PORT
      LAYER M4 ;
        RECT  36.528 70.944 36.72 70.968 ;
    END
  END dq[410]
  PIN dq[411]
    DIRECTION OUTPUT ;
    USE SIGNAL ;
    PORT
      LAYER M4 ;
        RECT  36.528 71.136 36.72 71.16 ;
    END
  END dq[411]
  PIN dq[412]
    DIRECTION OUTPUT ;
    USE SIGNAL ;
    PORT
      LAYER M4 ;
        RECT  36.528 71.28 36.72 71.304 ;
    END
  END dq[412]
  PIN dq[413]
    DIRECTION OUTPUT ;
    USE SIGNAL ;
    PORT
      LAYER M4 ;
        RECT  36.528 71.472 36.72 71.496 ;
    END
  END dq[413]
  PIN dq[414]
    DIRECTION OUTPUT ;
    USE SIGNAL ;
    PORT
      LAYER M4 ;
        RECT  36.528 71.616 36.72 71.64 ;
    END
  END dq[414]
  PIN dq[415]
    DIRECTION OUTPUT ;
    USE SIGNAL ;
    PORT
      LAYER M4 ;
        RECT  36.528 71.76 36.72 71.784 ;
    END
  END dq[415]
  PIN dq[416]
    DIRECTION OUTPUT ;
    USE SIGNAL ;
    PORT
      LAYER M4 ;
        RECT  36.528 71.952 36.72 71.976 ;
    END
  END dq[416]
  PIN dq[417]
    DIRECTION OUTPUT ;
    USE SIGNAL ;
    PORT
      LAYER M4 ;
        RECT  36.528 72.096 36.72 72.12 ;
    END
  END dq[417]
  PIN dq[418]
    DIRECTION OUTPUT ;
    USE SIGNAL ;
    PORT
      LAYER M4 ;
        RECT  36.528 72.24 36.72 72.264 ;
    END
  END dq[418]
  PIN dq[419]
    DIRECTION OUTPUT ;
    USE SIGNAL ;
    PORT
      LAYER M4 ;
        RECT  36.528 72.432 36.72 72.456 ;
    END
  END dq[419]
  PIN dq[41]
    DIRECTION OUTPUT ;
    USE SIGNAL ;
    PORT
      LAYER M4 ;
        RECT  36.528 11.088 36.72 11.112 ;
    END
  END dq[41]
  PIN dq[420]
    DIRECTION OUTPUT ;
    USE SIGNAL ;
    PORT
      LAYER M4 ;
        RECT  36.528 72.576 36.72 72.6 ;
    END
  END dq[420]
  PIN dq[421]
    DIRECTION OUTPUT ;
    USE SIGNAL ;
    PORT
      LAYER M4 ;
        RECT  36.528 72.768 36.72 72.792 ;
    END
  END dq[421]
  PIN dq[422]
    DIRECTION OUTPUT ;
    USE SIGNAL ;
    PORT
      LAYER M4 ;
        RECT  36.528 72.912 36.72 72.936 ;
    END
  END dq[422]
  PIN dq[423]
    DIRECTION OUTPUT ;
    USE SIGNAL ;
    PORT
      LAYER M4 ;
        RECT  36.528 73.056 36.72 73.08 ;
    END
  END dq[423]
  PIN dq[424]
    DIRECTION OUTPUT ;
    USE SIGNAL ;
    PORT
      LAYER M4 ;
        RECT  36.528 73.248 36.72 73.272 ;
    END
  END dq[424]
  PIN dq[425]
    DIRECTION OUTPUT ;
    USE SIGNAL ;
    PORT
      LAYER M4 ;
        RECT  36.528 73.392 36.72 73.416 ;
    END
  END dq[425]
  PIN dq[426]
    DIRECTION OUTPUT ;
    USE SIGNAL ;
    PORT
      LAYER M4 ;
        RECT  36.528 73.536 36.72 73.56 ;
    END
  END dq[426]
  PIN dq[427]
    DIRECTION OUTPUT ;
    USE SIGNAL ;
    PORT
      LAYER M4 ;
        RECT  36.528 73.728 36.72 73.752 ;
    END
  END dq[427]
  PIN dq[428]
    DIRECTION OUTPUT ;
    USE SIGNAL ;
    PORT
      LAYER M4 ;
        RECT  36.528 73.872 36.72 73.896 ;
    END
  END dq[428]
  PIN dq[429]
    DIRECTION OUTPUT ;
    USE SIGNAL ;
    PORT
      LAYER M4 ;
        RECT  36.528 74.064 36.72 74.088 ;
    END
  END dq[429]
  PIN dq[42]
    DIRECTION OUTPUT ;
    USE SIGNAL ;
    PORT
      LAYER M4 ;
        RECT  36.528 11.232 36.72 11.256 ;
    END
  END dq[42]
  PIN dq[430]
    DIRECTION OUTPUT ;
    USE SIGNAL ;
    PORT
      LAYER M4 ;
        RECT  36.528 74.208 36.72 74.232 ;
    END
  END dq[430]
  PIN dq[431]
    DIRECTION OUTPUT ;
    USE SIGNAL ;
    PORT
      LAYER M4 ;
        RECT  36.528 74.352 36.72 74.376 ;
    END
  END dq[431]
  PIN dq[432]
    DIRECTION OUTPUT ;
    USE SIGNAL ;
    PORT
      LAYER M4 ;
        RECT  36.528 74.544 36.72 74.568 ;
    END
  END dq[432]
  PIN dq[433]
    DIRECTION OUTPUT ;
    USE SIGNAL ;
    PORT
      LAYER M4 ;
        RECT  36.528 74.688 36.72 74.712 ;
    END
  END dq[433]
  PIN dq[434]
    DIRECTION OUTPUT ;
    USE SIGNAL ;
    PORT
      LAYER M4 ;
        RECT  36.528 74.88 36.72 74.904 ;
    END
  END dq[434]
  PIN dq[435]
    DIRECTION OUTPUT ;
    USE SIGNAL ;
    PORT
      LAYER M4 ;
        RECT  36.528 75.024 36.72 75.048 ;
    END
  END dq[435]
  PIN dq[436]
    DIRECTION OUTPUT ;
    USE SIGNAL ;
    PORT
      LAYER M4 ;
        RECT  36.528 75.168 36.72 75.192 ;
    END
  END dq[436]
  PIN dq[437]
    DIRECTION OUTPUT ;
    USE SIGNAL ;
    PORT
      LAYER M4 ;
        RECT  36.528 75.36 36.72 75.384 ;
    END
  END dq[437]
  PIN dq[438]
    DIRECTION OUTPUT ;
    USE SIGNAL ;
    PORT
      LAYER M4 ;
        RECT  36.528 75.504 36.72 75.528 ;
    END
  END dq[438]
  PIN dq[439]
    DIRECTION OUTPUT ;
    USE SIGNAL ;
    PORT
      LAYER M4 ;
        RECT  36.528 75.648 36.72 75.672 ;
    END
  END dq[439]
  PIN dq[43]
    DIRECTION OUTPUT ;
    USE SIGNAL ;
    PORT
      LAYER M4 ;
        RECT  36.528 11.376 36.72 11.4 ;
    END
  END dq[43]
  PIN dq[440]
    DIRECTION OUTPUT ;
    USE SIGNAL ;
    PORT
      LAYER M4 ;
        RECT  36.528 75.84 36.72 75.864 ;
    END
  END dq[440]
  PIN dq[441]
    DIRECTION OUTPUT ;
    USE SIGNAL ;
    PORT
      LAYER M4 ;
        RECT  36.528 75.984 36.72 76.008 ;
    END
  END dq[441]
  PIN dq[442]
    DIRECTION OUTPUT ;
    USE SIGNAL ;
    PORT
      LAYER M4 ;
        RECT  36.528 76.176 36.72 76.2 ;
    END
  END dq[442]
  PIN dq[443]
    DIRECTION OUTPUT ;
    USE SIGNAL ;
    PORT
      LAYER M4 ;
        RECT  36.528 76.32 36.72 76.344 ;
    END
  END dq[443]
  PIN dq[444]
    DIRECTION OUTPUT ;
    USE SIGNAL ;
    PORT
      LAYER M4 ;
        RECT  36.528 76.464 36.72 76.488 ;
    END
  END dq[444]
  PIN dq[445]
    DIRECTION OUTPUT ;
    USE SIGNAL ;
    PORT
      LAYER M4 ;
        RECT  36.528 76.656 36.72 76.68 ;
    END
  END dq[445]
  PIN dq[446]
    DIRECTION OUTPUT ;
    USE SIGNAL ;
    PORT
      LAYER M4 ;
        RECT  36.528 76.8 36.72 76.824 ;
    END
  END dq[446]
  PIN dq[447]
    DIRECTION OUTPUT ;
    USE SIGNAL ;
    PORT
      LAYER M4 ;
        RECT  36.528 76.944 36.72 76.968 ;
    END
  END dq[447]
  PIN dq[448]
    DIRECTION OUTPUT ;
    USE SIGNAL ;
    PORT
      LAYER M4 ;
        RECT  36.528 77.136 36.72 77.16 ;
    END
  END dq[448]
  PIN dq[449]
    DIRECTION OUTPUT ;
    USE SIGNAL ;
    PORT
      LAYER M4 ;
        RECT  36.528 77.28 36.72 77.304 ;
    END
  END dq[449]
  PIN dq[44]
    DIRECTION OUTPUT ;
    USE SIGNAL ;
    PORT
      LAYER M4 ;
        RECT  36.528 11.568 36.72 11.592 ;
    END
  END dq[44]
  PIN dq[450]
    DIRECTION OUTPUT ;
    USE SIGNAL ;
    PORT
      LAYER M4 ;
        RECT  36.528 77.472 36.72 77.496 ;
    END
  END dq[450]
  PIN dq[451]
    DIRECTION OUTPUT ;
    USE SIGNAL ;
    PORT
      LAYER M4 ;
        RECT  36.528 77.616 36.72 77.64 ;
    END
  END dq[451]
  PIN dq[452]
    DIRECTION OUTPUT ;
    USE SIGNAL ;
    PORT
      LAYER M4 ;
        RECT  36.528 77.76 36.72 77.784 ;
    END
  END dq[452]
  PIN dq[453]
    DIRECTION OUTPUT ;
    USE SIGNAL ;
    PORT
      LAYER M4 ;
        RECT  36.528 77.952 36.72 77.976 ;
    END
  END dq[453]
  PIN dq[454]
    DIRECTION OUTPUT ;
    USE SIGNAL ;
    PORT
      LAYER M4 ;
        RECT  36.528 78.096 36.72 78.12 ;
    END
  END dq[454]
  PIN dq[455]
    DIRECTION OUTPUT ;
    USE SIGNAL ;
    PORT
      LAYER M4 ;
        RECT  36.528 78.288 36.72 78.312 ;
    END
  END dq[455]
  PIN dq[456]
    DIRECTION OUTPUT ;
    USE SIGNAL ;
    PORT
      LAYER M4 ;
        RECT  36.528 78.432 36.72 78.456 ;
    END
  END dq[456]
  PIN dq[457]
    DIRECTION OUTPUT ;
    USE SIGNAL ;
    PORT
      LAYER M4 ;
        RECT  36.528 78.576 36.72 78.6 ;
    END
  END dq[457]
  PIN dq[458]
    DIRECTION OUTPUT ;
    USE SIGNAL ;
    PORT
      LAYER M4 ;
        RECT  36.528 78.768 36.72 78.792 ;
    END
  END dq[458]
  PIN dq[459]
    DIRECTION OUTPUT ;
    USE SIGNAL ;
    PORT
      LAYER M4 ;
        RECT  36.528 78.912 36.72 78.936 ;
    END
  END dq[459]
  PIN dq[45]
    DIRECTION OUTPUT ;
    USE SIGNAL ;
    PORT
      LAYER M4 ;
        RECT  36.528 11.712 36.72 11.736 ;
    END
  END dq[45]
  PIN dq[460]
    DIRECTION OUTPUT ;
    USE SIGNAL ;
    PORT
      LAYER M4 ;
        RECT  36.528 79.056 36.72 79.08 ;
    END
  END dq[460]
  PIN dq[461]
    DIRECTION OUTPUT ;
    USE SIGNAL ;
    PORT
      LAYER M4 ;
        RECT  36.528 79.248 36.72 79.272 ;
    END
  END dq[461]
  PIN dq[462]
    DIRECTION OUTPUT ;
    USE SIGNAL ;
    PORT
      LAYER M4 ;
        RECT  36.528 79.392 36.72 79.416 ;
    END
  END dq[462]
  PIN dq[463]
    DIRECTION OUTPUT ;
    USE SIGNAL ;
    PORT
      LAYER M4 ;
        RECT  36.528 79.584 36.72 79.608 ;
    END
  END dq[463]
  PIN dq[464]
    DIRECTION OUTPUT ;
    USE SIGNAL ;
    PORT
      LAYER M4 ;
        RECT  36.528 79.728 36.72 79.752 ;
    END
  END dq[464]
  PIN dq[465]
    DIRECTION OUTPUT ;
    USE SIGNAL ;
    PORT
      LAYER M4 ;
        RECT  36.528 79.872 36.72 79.896 ;
    END
  END dq[465]
  PIN dq[466]
    DIRECTION OUTPUT ;
    USE SIGNAL ;
    PORT
      LAYER M4 ;
        RECT  36.528 80.064 36.72 80.088 ;
    END
  END dq[466]
  PIN dq[467]
    DIRECTION OUTPUT ;
    USE SIGNAL ;
    PORT
      LAYER M4 ;
        RECT  36.528 80.208 36.72 80.232 ;
    END
  END dq[467]
  PIN dq[468]
    DIRECTION OUTPUT ;
    USE SIGNAL ;
    PORT
      LAYER M4 ;
        RECT  36.528 80.352 36.72 80.376 ;
    END
  END dq[468]
  PIN dq[469]
    DIRECTION OUTPUT ;
    USE SIGNAL ;
    PORT
      LAYER M4 ;
        RECT  36.528 80.544 36.72 80.568 ;
    END
  END dq[469]
  PIN dq[46]
    DIRECTION OUTPUT ;
    USE SIGNAL ;
    PORT
      LAYER M4 ;
        RECT  36.528 11.856 36.72 11.88 ;
    END
  END dq[46]
  PIN dq[470]
    DIRECTION OUTPUT ;
    USE SIGNAL ;
    PORT
      LAYER M4 ;
        RECT  36.528 80.688 36.72 80.712 ;
    END
  END dq[470]
  PIN dq[471]
    DIRECTION OUTPUT ;
    USE SIGNAL ;
    PORT
      LAYER M4 ;
        RECT  36.528 80.88 36.72 80.904 ;
    END
  END dq[471]
  PIN dq[472]
    DIRECTION OUTPUT ;
    USE SIGNAL ;
    PORT
      LAYER M4 ;
        RECT  36.528 81.024 36.72 81.048 ;
    END
  END dq[472]
  PIN dq[473]
    DIRECTION OUTPUT ;
    USE SIGNAL ;
    PORT
      LAYER M4 ;
        RECT  36.528 81.168 36.72 81.192 ;
    END
  END dq[473]
  PIN dq[474]
    DIRECTION OUTPUT ;
    USE SIGNAL ;
    PORT
      LAYER M4 ;
        RECT  36.528 81.36 36.72 81.384 ;
    END
  END dq[474]
  PIN dq[475]
    DIRECTION OUTPUT ;
    USE SIGNAL ;
    PORT
      LAYER M4 ;
        RECT  36.528 81.504 36.72 81.528 ;
    END
  END dq[475]
  PIN dq[476]
    DIRECTION OUTPUT ;
    USE SIGNAL ;
    PORT
      LAYER M4 ;
        RECT  36.528 81.696 36.72 81.72 ;
    END
  END dq[476]
  PIN dq[477]
    DIRECTION OUTPUT ;
    USE SIGNAL ;
    PORT
      LAYER M4 ;
        RECT  36.528 81.84 36.72 81.864 ;
    END
  END dq[477]
  PIN dq[478]
    DIRECTION OUTPUT ;
    USE SIGNAL ;
    PORT
      LAYER M4 ;
        RECT  36.528 81.984 36.72 82.008 ;
    END
  END dq[478]
  PIN dq[479]
    DIRECTION OUTPUT ;
    USE SIGNAL ;
    PORT
      LAYER M4 ;
        RECT  36.528 82.176 36.72 82.2 ;
    END
  END dq[479]
  PIN dq[47]
    DIRECTION OUTPUT ;
    USE SIGNAL ;
    PORT
      LAYER M4 ;
        RECT  36.528 12.048 36.72 12.072 ;
    END
  END dq[47]
  PIN dq[480]
    DIRECTION OUTPUT ;
    USE SIGNAL ;
    PORT
      LAYER M4 ;
        RECT  36.528 82.32 36.72 82.344 ;
    END
  END dq[480]
  PIN dq[481]
    DIRECTION OUTPUT ;
    USE SIGNAL ;
    PORT
      LAYER M4 ;
        RECT  36.528 82.464 36.72 82.488 ;
    END
  END dq[481]
  PIN dq[482]
    DIRECTION OUTPUT ;
    USE SIGNAL ;
    PORT
      LAYER M4 ;
        RECT  36.528 82.656 36.72 82.68 ;
    END
  END dq[482]
  PIN dq[483]
    DIRECTION OUTPUT ;
    USE SIGNAL ;
    PORT
      LAYER M4 ;
        RECT  36.528 82.8 36.72 82.824 ;
    END
  END dq[483]
  PIN dq[484]
    DIRECTION OUTPUT ;
    USE SIGNAL ;
    PORT
      LAYER M4 ;
        RECT  36.528 82.992 36.72 83.016 ;
    END
  END dq[484]
  PIN dq[485]
    DIRECTION OUTPUT ;
    USE SIGNAL ;
    PORT
      LAYER M4 ;
        RECT  36.528 83.136 36.72 83.16 ;
    END
  END dq[485]
  PIN dq[486]
    DIRECTION OUTPUT ;
    USE SIGNAL ;
    PORT
      LAYER M4 ;
        RECT  36.528 83.28 36.72 83.304 ;
    END
  END dq[486]
  PIN dq[487]
    DIRECTION OUTPUT ;
    USE SIGNAL ;
    PORT
      LAYER M4 ;
        RECT  36.528 83.472 36.72 83.496 ;
    END
  END dq[487]
  PIN dq[488]
    DIRECTION OUTPUT ;
    USE SIGNAL ;
    PORT
      LAYER M4 ;
        RECT  36.528 83.616 36.72 83.64 ;
    END
  END dq[488]
  PIN dq[489]
    DIRECTION OUTPUT ;
    USE SIGNAL ;
    PORT
      LAYER M4 ;
        RECT  36.528 83.76 36.72 83.784 ;
    END
  END dq[489]
  PIN dq[48]
    DIRECTION OUTPUT ;
    USE SIGNAL ;
    PORT
      LAYER M4 ;
        RECT  36.528 12.192 36.72 12.216 ;
    END
  END dq[48]
  PIN dq[490]
    DIRECTION OUTPUT ;
    USE SIGNAL ;
    PORT
      LAYER M4 ;
        RECT  36.528 83.952 36.72 83.976 ;
    END
  END dq[490]
  PIN dq[491]
    DIRECTION OUTPUT ;
    USE SIGNAL ;
    PORT
      LAYER M4 ;
        RECT  36.528 84.096 36.72 84.12 ;
    END
  END dq[491]
  PIN dq[492]
    DIRECTION OUTPUT ;
    USE SIGNAL ;
    PORT
      LAYER M4 ;
        RECT  36.528 84.288 36.72 84.312 ;
    END
  END dq[492]
  PIN dq[493]
    DIRECTION OUTPUT ;
    USE SIGNAL ;
    PORT
      LAYER M4 ;
        RECT  36.528 84.432 36.72 84.456 ;
    END
  END dq[493]
  PIN dq[494]
    DIRECTION OUTPUT ;
    USE SIGNAL ;
    PORT
      LAYER M4 ;
        RECT  36.528 84.576 36.72 84.6 ;
    END
  END dq[494]
  PIN dq[495]
    DIRECTION OUTPUT ;
    USE SIGNAL ;
    PORT
      LAYER M4 ;
        RECT  36.528 84.768 36.72 84.792 ;
    END
  END dq[495]
  PIN dq[496]
    DIRECTION OUTPUT ;
    USE SIGNAL ;
    PORT
      LAYER M4 ;
        RECT  36.528 84.912 36.72 84.936 ;
    END
  END dq[496]
  PIN dq[497]
    DIRECTION OUTPUT ;
    USE SIGNAL ;
    PORT
      LAYER M4 ;
        RECT  36.528 85.104 36.72 85.128 ;
    END
  END dq[497]
  PIN dq[498]
    DIRECTION OUTPUT ;
    USE SIGNAL ;
    PORT
      LAYER M4 ;
        RECT  36.528 85.248 36.72 85.272 ;
    END
  END dq[498]
  PIN dq[499]
    DIRECTION OUTPUT ;
    USE SIGNAL ;
    PORT
      LAYER M4 ;
        RECT  36.528 85.392 36.72 85.416 ;
    END
  END dq[499]
  PIN dq[49]
    DIRECTION OUTPUT ;
    USE SIGNAL ;
    PORT
      LAYER M4 ;
        RECT  36.528 12.384 36.72 12.408 ;
    END
  END dq[49]
  PIN dq[4]
    DIRECTION OUTPUT ;
    USE SIGNAL ;
    PORT
      LAYER M4 ;
        RECT  36.528 5.04 36.72 5.064 ;
    END
  END dq[4]
  PIN dq[500]
    DIRECTION OUTPUT ;
    USE SIGNAL ;
    PORT
      LAYER M4 ;
        RECT  36.528 85.584 36.72 85.608 ;
    END
  END dq[500]
  PIN dq[501]
    DIRECTION OUTPUT ;
    USE SIGNAL ;
    PORT
      LAYER M4 ;
        RECT  36.528 85.728 36.72 85.752 ;
    END
  END dq[501]
  PIN dq[502]
    DIRECTION OUTPUT ;
    USE SIGNAL ;
    PORT
      LAYER M4 ;
        RECT  36.528 85.872 36.72 85.896 ;
    END
  END dq[502]
  PIN dq[503]
    DIRECTION OUTPUT ;
    USE SIGNAL ;
    PORT
      LAYER M4 ;
        RECT  36.528 86.064 36.72 86.088 ;
    END
  END dq[503]
  PIN dq[504]
    DIRECTION OUTPUT ;
    USE SIGNAL ;
    PORT
      LAYER M4 ;
        RECT  36.528 86.208 36.72 86.232 ;
    END
  END dq[504]
  PIN dq[505]
    DIRECTION OUTPUT ;
    USE SIGNAL ;
    PORT
      LAYER M4 ;
        RECT  36.528 86.4 36.72 86.424 ;
    END
  END dq[505]
  PIN dq[506]
    DIRECTION OUTPUT ;
    USE SIGNAL ;
    PORT
      LAYER M4 ;
        RECT  36.528 86.544 36.72 86.568 ;
    END
  END dq[506]
  PIN dq[507]
    DIRECTION OUTPUT ;
    USE SIGNAL ;
    PORT
      LAYER M4 ;
        RECT  36.528 86.688 36.72 86.712 ;
    END
  END dq[507]
  PIN dq[508]
    DIRECTION OUTPUT ;
    USE SIGNAL ;
    PORT
      LAYER M4 ;
        RECT  36.528 86.88 36.72 86.904 ;
    END
  END dq[508]
  PIN dq[509]
    DIRECTION OUTPUT ;
    USE SIGNAL ;
    PORT
      LAYER M4 ;
        RECT  36.528 87.024 36.72 87.048 ;
    END
  END dq[509]
  PIN dq[50]
    DIRECTION OUTPUT ;
    USE SIGNAL ;
    PORT
      LAYER M4 ;
        RECT  36.528 12.528 36.72 12.552 ;
    END
  END dq[50]
  PIN dq[510]
    DIRECTION OUTPUT ;
    USE SIGNAL ;
    PORT
      LAYER M4 ;
        RECT  36.528 87.216 36.72 87.24 ;
    END
  END dq[510]
  PIN dq[511]
    DIRECTION OUTPUT ;
    USE SIGNAL ;
    PORT
      LAYER M4 ;
        RECT  36.528 87.36 36.72 87.384 ;
    END
  END dq[511]
  PIN dq[512]
    DIRECTION OUTPUT ;
    USE SIGNAL ;
    PORT
      LAYER M4 ;
        RECT  36.528 87.504 36.72 87.528 ;
    END
  END dq[512]
  PIN dq[513]
    DIRECTION OUTPUT ;
    USE SIGNAL ;
    PORT
      LAYER M4 ;
        RECT  36.528 87.696 36.72 87.72 ;
    END
  END dq[513]
  PIN dq[514]
    DIRECTION OUTPUT ;
    USE SIGNAL ;
    PORT
      LAYER M4 ;
        RECT  36.528 87.84 36.72 87.864 ;
    END
  END dq[514]
  PIN dq[515]
    DIRECTION OUTPUT ;
    USE SIGNAL ;
    PORT
      LAYER M4 ;
        RECT  36.528 87.984 36.72 88.008 ;
    END
  END dq[515]
  PIN dq[516]
    DIRECTION OUTPUT ;
    USE SIGNAL ;
    PORT
      LAYER M4 ;
        RECT  36.528 88.176 36.72 88.2 ;
    END
  END dq[516]
  PIN dq[517]
    DIRECTION OUTPUT ;
    USE SIGNAL ;
    PORT
      LAYER M4 ;
        RECT  36.528 88.32 36.72 88.344 ;
    END
  END dq[517]
  PIN dq[518]
    DIRECTION OUTPUT ;
    USE SIGNAL ;
    PORT
      LAYER M4 ;
        RECT  36.528 88.512 36.72 88.536 ;
    END
  END dq[518]
  PIN dq[519]
    DIRECTION OUTPUT ;
    USE SIGNAL ;
    PORT
      LAYER M4 ;
        RECT  36.528 88.656 36.72 88.68 ;
    END
  END dq[519]
  PIN dq[51]
    DIRECTION OUTPUT ;
    USE SIGNAL ;
    PORT
      LAYER M4 ;
        RECT  36.528 12.672 36.72 12.696 ;
    END
  END dq[51]
  PIN dq[520]
    DIRECTION OUTPUT ;
    USE SIGNAL ;
    PORT
      LAYER M4 ;
        RECT  36.528 88.8 36.72 88.824 ;
    END
  END dq[520]
  PIN dq[521]
    DIRECTION OUTPUT ;
    USE SIGNAL ;
    PORT
      LAYER M4 ;
        RECT  36.528 88.992 36.72 89.016 ;
    END
  END dq[521]
  PIN dq[522]
    DIRECTION OUTPUT ;
    USE SIGNAL ;
    PORT
      LAYER M4 ;
        RECT  36.528 89.136 36.72 89.16 ;
    END
  END dq[522]
  PIN dq[523]
    DIRECTION OUTPUT ;
    USE SIGNAL ;
    PORT
      LAYER M4 ;
        RECT  36.528 89.28 36.72 89.304 ;
    END
  END dq[523]
  PIN dq[524]
    DIRECTION OUTPUT ;
    USE SIGNAL ;
    PORT
      LAYER M4 ;
        RECT  36.528 89.472 36.72 89.496 ;
    END
  END dq[524]
  PIN dq[525]
    DIRECTION OUTPUT ;
    USE SIGNAL ;
    PORT
      LAYER M4 ;
        RECT  36.528 89.616 36.72 89.64 ;
    END
  END dq[525]
  PIN dq[526]
    DIRECTION OUTPUT ;
    USE SIGNAL ;
    PORT
      LAYER M4 ;
        RECT  36.528 89.808 36.72 89.832 ;
    END
  END dq[526]
  PIN dq[527]
    DIRECTION OUTPUT ;
    USE SIGNAL ;
    PORT
      LAYER M4 ;
        RECT  36.528 89.952 36.72 89.976 ;
    END
  END dq[527]
  PIN dq[528]
    DIRECTION OUTPUT ;
    USE SIGNAL ;
    PORT
      LAYER M4 ;
        RECT  36.528 90.096 36.72 90.12 ;
    END
  END dq[528]
  PIN dq[529]
    DIRECTION OUTPUT ;
    USE SIGNAL ;
    PORT
      LAYER M4 ;
        RECT  36.528 90.288 36.72 90.312 ;
    END
  END dq[529]
  PIN dq[52]
    DIRECTION OUTPUT ;
    USE SIGNAL ;
    PORT
      LAYER M4 ;
        RECT  36.528 12.864 36.72 12.888 ;
    END
  END dq[52]
  PIN dq[530]
    DIRECTION OUTPUT ;
    USE SIGNAL ;
    PORT
      LAYER M4 ;
        RECT  36.528 90.432 36.72 90.456 ;
    END
  END dq[530]
  PIN dq[531]
    DIRECTION OUTPUT ;
    USE SIGNAL ;
    PORT
      LAYER M4 ;
        RECT  36.528 90.624 36.72 90.648 ;
    END
  END dq[531]
  PIN dq[532]
    DIRECTION OUTPUT ;
    USE SIGNAL ;
    PORT
      LAYER M4 ;
        RECT  36.528 90.768 36.72 90.792 ;
    END
  END dq[532]
  PIN dq[533]
    DIRECTION OUTPUT ;
    USE SIGNAL ;
    PORT
      LAYER M4 ;
        RECT  36.528 90.912 36.72 90.936 ;
    END
  END dq[533]
  PIN dq[534]
    DIRECTION OUTPUT ;
    USE SIGNAL ;
    PORT
      LAYER M4 ;
        RECT  36.528 91.104 36.72 91.128 ;
    END
  END dq[534]
  PIN dq[535]
    DIRECTION OUTPUT ;
    USE SIGNAL ;
    PORT
      LAYER M4 ;
        RECT  36.528 91.248 36.72 91.272 ;
    END
  END dq[535]
  PIN dq[536]
    DIRECTION OUTPUT ;
    USE SIGNAL ;
    PORT
      LAYER M4 ;
        RECT  36.528 91.392 36.72 91.416 ;
    END
  END dq[536]
  PIN dq[537]
    DIRECTION OUTPUT ;
    USE SIGNAL ;
    PORT
      LAYER M4 ;
        RECT  36.528 91.584 36.72 91.608 ;
    END
  END dq[537]
  PIN dq[538]
    DIRECTION OUTPUT ;
    USE SIGNAL ;
    PORT
      LAYER M4 ;
        RECT  36.528 91.728 36.72 91.752 ;
    END
  END dq[538]
  PIN dq[539]
    DIRECTION OUTPUT ;
    USE SIGNAL ;
    PORT
      LAYER M4 ;
        RECT  36.528 91.92 36.72 91.944 ;
    END
  END dq[539]
  PIN dq[53]
    DIRECTION OUTPUT ;
    USE SIGNAL ;
    PORT
      LAYER M4 ;
        RECT  36.528 13.008 36.72 13.032 ;
    END
  END dq[53]
  PIN dq[540]
    DIRECTION OUTPUT ;
    USE SIGNAL ;
    PORT
      LAYER M4 ;
        RECT  36.528 92.064 36.72 92.088 ;
    END
  END dq[540]
  PIN dq[541]
    DIRECTION OUTPUT ;
    USE SIGNAL ;
    PORT
      LAYER M4 ;
        RECT  36.528 92.208 36.72 92.232 ;
    END
  END dq[541]
  PIN dq[542]
    DIRECTION OUTPUT ;
    USE SIGNAL ;
    PORT
      LAYER M4 ;
        RECT  36.528 92.4 36.72 92.424 ;
    END
  END dq[542]
  PIN dq[543]
    DIRECTION OUTPUT ;
    USE SIGNAL ;
    PORT
      LAYER M4 ;
        RECT  36.528 92.544 36.72 92.568 ;
    END
  END dq[543]
  PIN dq[544]
    DIRECTION OUTPUT ;
    USE SIGNAL ;
    PORT
      LAYER M4 ;
        RECT  36.528 92.688 36.72 92.712 ;
    END
  END dq[544]
  PIN dq[545]
    DIRECTION OUTPUT ;
    USE SIGNAL ;
    PORT
      LAYER M4 ;
        RECT  36.528 92.88 36.72 92.904 ;
    END
  END dq[545]
  PIN dq[546]
    DIRECTION OUTPUT ;
    USE SIGNAL ;
    PORT
      LAYER M4 ;
        RECT  36.528 93.024 36.72 93.048 ;
    END
  END dq[546]
  PIN dq[547]
    DIRECTION OUTPUT ;
    USE SIGNAL ;
    PORT
      LAYER M4 ;
        RECT  36.528 93.216 36.72 93.24 ;
    END
  END dq[547]
  PIN dq[548]
    DIRECTION OUTPUT ;
    USE SIGNAL ;
    PORT
      LAYER M4 ;
        RECT  36.528 93.36 36.72 93.384 ;
    END
  END dq[548]
  PIN dq[549]
    DIRECTION OUTPUT ;
    USE SIGNAL ;
    PORT
      LAYER M4 ;
        RECT  36.528 93.504 36.72 93.528 ;
    END
  END dq[549]
  PIN dq[54]
    DIRECTION OUTPUT ;
    USE SIGNAL ;
    PORT
      LAYER M4 ;
        RECT  36.528 13.2 36.72 13.224 ;
    END
  END dq[54]
  PIN dq[550]
    DIRECTION OUTPUT ;
    USE SIGNAL ;
    PORT
      LAYER M4 ;
        RECT  36.528 93.696 36.72 93.72 ;
    END
  END dq[550]
  PIN dq[551]
    DIRECTION OUTPUT ;
    USE SIGNAL ;
    PORT
      LAYER M4 ;
        RECT  36.528 93.84 36.72 93.864 ;
    END
  END dq[551]
  PIN dq[552]
    DIRECTION OUTPUT ;
    USE SIGNAL ;
    PORT
      LAYER M4 ;
        RECT  36.528 94.032 36.72 94.056 ;
    END
  END dq[552]
  PIN dq[553]
    DIRECTION OUTPUT ;
    USE SIGNAL ;
    PORT
      LAYER M4 ;
        RECT  36.528 94.176 36.72 94.2 ;
    END
  END dq[553]
  PIN dq[554]
    DIRECTION OUTPUT ;
    USE SIGNAL ;
    PORT
      LAYER M4 ;
        RECT  36.528 94.32 36.72 94.344 ;
    END
  END dq[554]
  PIN dq[555]
    DIRECTION OUTPUT ;
    USE SIGNAL ;
    PORT
      LAYER M4 ;
        RECT  36.528 94.512 36.72 94.536 ;
    END
  END dq[555]
  PIN dq[556]
    DIRECTION OUTPUT ;
    USE SIGNAL ;
    PORT
      LAYER M4 ;
        RECT  36.528 94.656 36.72 94.68 ;
    END
  END dq[556]
  PIN dq[557]
    DIRECTION OUTPUT ;
    USE SIGNAL ;
    PORT
      LAYER M4 ;
        RECT  36.528 94.8 36.72 94.824 ;
    END
  END dq[557]
  PIN dq[558]
    DIRECTION OUTPUT ;
    USE SIGNAL ;
    PORT
      LAYER M4 ;
        RECT  36.528 94.992 36.72 95.016 ;
    END
  END dq[558]
  PIN dq[559]
    DIRECTION OUTPUT ;
    USE SIGNAL ;
    PORT
      LAYER M4 ;
        RECT  36.528 95.136 36.72 95.16 ;
    END
  END dq[559]
  PIN dq[55]
    DIRECTION OUTPUT ;
    USE SIGNAL ;
    PORT
      LAYER M4 ;
        RECT  36.528 13.344 36.72 13.368 ;
    END
  END dq[55]
  PIN dq[560]
    DIRECTION OUTPUT ;
    USE SIGNAL ;
    PORT
      LAYER M4 ;
        RECT  36.528 95.328 36.72 95.352 ;
    END
  END dq[560]
  PIN dq[561]
    DIRECTION OUTPUT ;
    USE SIGNAL ;
    PORT
      LAYER M4 ;
        RECT  36.528 95.472 36.72 95.496 ;
    END
  END dq[561]
  PIN dq[562]
    DIRECTION OUTPUT ;
    USE SIGNAL ;
    PORT
      LAYER M4 ;
        RECT  36.528 95.616 36.72 95.64 ;
    END
  END dq[562]
  PIN dq[563]
    DIRECTION OUTPUT ;
    USE SIGNAL ;
    PORT
      LAYER M4 ;
        RECT  36.528 95.808 36.72 95.832 ;
    END
  END dq[563]
  PIN dq[564]
    DIRECTION OUTPUT ;
    USE SIGNAL ;
    PORT
      LAYER M4 ;
        RECT  36.528 95.952 36.72 95.976 ;
    END
  END dq[564]
  PIN dq[565]
    DIRECTION OUTPUT ;
    USE SIGNAL ;
    PORT
      LAYER M4 ;
        RECT  36.528 96.096 36.72 96.12 ;
    END
  END dq[565]
  PIN dq[566]
    DIRECTION OUTPUT ;
    USE SIGNAL ;
    PORT
      LAYER M4 ;
        RECT  36.528 96.288 36.72 96.312 ;
    END
  END dq[566]
  PIN dq[567]
    DIRECTION OUTPUT ;
    USE SIGNAL ;
    PORT
      LAYER M4 ;
        RECT  36.528 96.432 36.72 96.456 ;
    END
  END dq[567]
  PIN dq[568]
    DIRECTION OUTPUT ;
    USE SIGNAL ;
    PORT
      LAYER M4 ;
        RECT  36.528 96.624 36.72 96.648 ;
    END
  END dq[568]
  PIN dq[569]
    DIRECTION OUTPUT ;
    USE SIGNAL ;
    PORT
      LAYER M4 ;
        RECT  36.528 96.768 36.72 96.792 ;
    END
  END dq[569]
  PIN dq[56]
    DIRECTION OUTPUT ;
    USE SIGNAL ;
    PORT
      LAYER M4 ;
        RECT  36.528 13.488 36.72 13.512 ;
    END
  END dq[56]
  PIN dq[570]
    DIRECTION OUTPUT ;
    USE SIGNAL ;
    PORT
      LAYER M4 ;
        RECT  36.528 96.912 36.72 96.936 ;
    END
  END dq[570]
  PIN dq[571]
    DIRECTION OUTPUT ;
    USE SIGNAL ;
    PORT
      LAYER M4 ;
        RECT  36.528 97.104 36.72 97.128 ;
    END
  END dq[571]
  PIN dq[572]
    DIRECTION OUTPUT ;
    USE SIGNAL ;
    PORT
      LAYER M4 ;
        RECT  36.528 97.248 36.72 97.272 ;
    END
  END dq[572]
  PIN dq[573]
    DIRECTION OUTPUT ;
    USE SIGNAL ;
    PORT
      LAYER M4 ;
        RECT  36.528 97.44 36.72 97.464 ;
    END
  END dq[573]
  PIN dq[574]
    DIRECTION OUTPUT ;
    USE SIGNAL ;
    PORT
      LAYER M4 ;
        RECT  36.528 97.584 36.72 97.608 ;
    END
  END dq[574]
  PIN dq[575]
    DIRECTION OUTPUT ;
    USE SIGNAL ;
    PORT
      LAYER M4 ;
        RECT  36.528 97.728 36.72 97.752 ;
    END
  END dq[575]
  PIN dq[576]
    DIRECTION OUTPUT ;
    USE SIGNAL ;
    PORT
      LAYER M4 ;
        RECT  36.528 97.92 36.72 97.944 ;
    END
  END dq[576]
  PIN dq[577]
    DIRECTION OUTPUT ;
    USE SIGNAL ;
    PORT
      LAYER M4 ;
        RECT  36.528 98.064 36.72 98.088 ;
    END
  END dq[577]
  PIN dq[578]
    DIRECTION OUTPUT ;
    USE SIGNAL ;
    PORT
      LAYER M4 ;
        RECT  36.528 98.208 36.72 98.232 ;
    END
  END dq[578]
  PIN dq[579]
    DIRECTION OUTPUT ;
    USE SIGNAL ;
    PORT
      LAYER M4 ;
        RECT  36.528 98.4 36.72 98.424 ;
    END
  END dq[579]
  PIN dq[57]
    DIRECTION OUTPUT ;
    USE SIGNAL ;
    PORT
      LAYER M4 ;
        RECT  36.528 13.68 36.72 13.704 ;
    END
  END dq[57]
  PIN dq[580]
    DIRECTION OUTPUT ;
    USE SIGNAL ;
    PORT
      LAYER M4 ;
        RECT  36.528 98.544 36.72 98.568 ;
    END
  END dq[580]
  PIN dq[581]
    DIRECTION OUTPUT ;
    USE SIGNAL ;
    PORT
      LAYER M4 ;
        RECT  36.528 98.736 36.72 98.76 ;
    END
  END dq[581]
  PIN dq[582]
    DIRECTION OUTPUT ;
    USE SIGNAL ;
    PORT
      LAYER M4 ;
        RECT  36.528 98.88 36.72 98.904 ;
    END
  END dq[582]
  PIN dq[583]
    DIRECTION OUTPUT ;
    USE SIGNAL ;
    PORT
      LAYER M4 ;
        RECT  36.528 99.024 36.72 99.048 ;
    END
  END dq[583]
  PIN dq[584]
    DIRECTION OUTPUT ;
    USE SIGNAL ;
    PORT
      LAYER M4 ;
        RECT  36.528 99.216 36.72 99.24 ;
    END
  END dq[584]
  PIN dq[585]
    DIRECTION OUTPUT ;
    USE SIGNAL ;
    PORT
      LAYER M4 ;
        RECT  36.528 99.36 36.72 99.384 ;
    END
  END dq[585]
  PIN dq[586]
    DIRECTION OUTPUT ;
    USE SIGNAL ;
    PORT
      LAYER M4 ;
        RECT  36.528 99.552 36.72 99.576 ;
    END
  END dq[586]
  PIN dq[587]
    DIRECTION OUTPUT ;
    USE SIGNAL ;
    PORT
      LAYER M4 ;
        RECT  36.528 99.696 36.72 99.72 ;
    END
  END dq[587]
  PIN dq[588]
    DIRECTION OUTPUT ;
    USE SIGNAL ;
    PORT
      LAYER M4 ;
        RECT  36.528 99.84 36.72 99.864 ;
    END
  END dq[588]
  PIN dq[589]
    DIRECTION OUTPUT ;
    USE SIGNAL ;
    PORT
      LAYER M4 ;
        RECT  36.528 100.032 36.72 100.056 ;
    END
  END dq[589]
  PIN dq[58]
    DIRECTION OUTPUT ;
    USE SIGNAL ;
    PORT
      LAYER M4 ;
        RECT  36.528 13.824 36.72 13.848 ;
    END
  END dq[58]
  PIN dq[590]
    DIRECTION OUTPUT ;
    USE SIGNAL ;
    PORT
      LAYER M4 ;
        RECT  36.528 100.176 36.72 100.2 ;
    END
  END dq[590]
  PIN dq[591]
    DIRECTION OUTPUT ;
    USE SIGNAL ;
    PORT
      LAYER M4 ;
        RECT  36.528 100.32 36.72 100.344 ;
    END
  END dq[591]
  PIN dq[592]
    DIRECTION OUTPUT ;
    USE SIGNAL ;
    PORT
      LAYER M4 ;
        RECT  36.528 100.512 36.72 100.536 ;
    END
  END dq[592]
  PIN dq[593]
    DIRECTION OUTPUT ;
    USE SIGNAL ;
    PORT
      LAYER M4 ;
        RECT  36.528 100.656 36.72 100.68 ;
    END
  END dq[593]
  PIN dq[594]
    DIRECTION OUTPUT ;
    USE SIGNAL ;
    PORT
      LAYER M4 ;
        RECT  36.528 100.848 36.72 100.872 ;
    END
  END dq[594]
  PIN dq[595]
    DIRECTION OUTPUT ;
    USE SIGNAL ;
    PORT
      LAYER M4 ;
        RECT  36.528 100.992 36.72 101.016 ;
    END
  END dq[595]
  PIN dq[596]
    DIRECTION OUTPUT ;
    USE SIGNAL ;
    PORT
      LAYER M4 ;
        RECT  36.528 101.136 36.72 101.16 ;
    END
  END dq[596]
  PIN dq[597]
    DIRECTION OUTPUT ;
    USE SIGNAL ;
    PORT
      LAYER M4 ;
        RECT  36.528 101.328 36.72 101.352 ;
    END
  END dq[597]
  PIN dq[598]
    DIRECTION OUTPUT ;
    USE SIGNAL ;
    PORT
      LAYER M4 ;
        RECT  36.528 101.472 36.72 101.496 ;
    END
  END dq[598]
  PIN dq[599]
    DIRECTION OUTPUT ;
    USE SIGNAL ;
    PORT
      LAYER M4 ;
        RECT  36.528 101.616 36.72 101.64 ;
    END
  END dq[599]
  PIN dq[59]
    DIRECTION OUTPUT ;
    USE SIGNAL ;
    PORT
      LAYER M4 ;
        RECT  36.528 13.968 36.72 13.992 ;
    END
  END dq[59]
  PIN dq[5]
    DIRECTION OUTPUT ;
    USE SIGNAL ;
    PORT
      LAYER M4 ;
        RECT  36.528 5.232 36.72 5.256 ;
    END
  END dq[5]
  PIN dq[600]
    DIRECTION OUTPUT ;
    USE SIGNAL ;
    PORT
      LAYER M4 ;
        RECT  36.528 101.808 36.72 101.832 ;
    END
  END dq[600]
  PIN dq[601]
    DIRECTION OUTPUT ;
    USE SIGNAL ;
    PORT
      LAYER M4 ;
        RECT  36.528 101.952 36.72 101.976 ;
    END
  END dq[601]
  PIN dq[602]
    DIRECTION OUTPUT ;
    USE SIGNAL ;
    PORT
      LAYER M4 ;
        RECT  36.528 102.144 36.72 102.168 ;
    END
  END dq[602]
  PIN dq[603]
    DIRECTION OUTPUT ;
    USE SIGNAL ;
    PORT
      LAYER M4 ;
        RECT  36.528 102.288 36.72 102.312 ;
    END
  END dq[603]
  PIN dq[604]
    DIRECTION OUTPUT ;
    USE SIGNAL ;
    PORT
      LAYER M4 ;
        RECT  36.528 102.432 36.72 102.456 ;
    END
  END dq[604]
  PIN dq[605]
    DIRECTION OUTPUT ;
    USE SIGNAL ;
    PORT
      LAYER M4 ;
        RECT  36.528 102.624 36.72 102.648 ;
    END
  END dq[605]
  PIN dq[606]
    DIRECTION OUTPUT ;
    USE SIGNAL ;
    PORT
      LAYER M4 ;
        RECT  36.528 102.768 36.72 102.792 ;
    END
  END dq[606]
  PIN dq[607]
    DIRECTION OUTPUT ;
    USE SIGNAL ;
    PORT
      LAYER M4 ;
        RECT  36.528 102.96 36.72 102.984 ;
    END
  END dq[607]
  PIN dq[608]
    DIRECTION OUTPUT ;
    USE SIGNAL ;
    PORT
      LAYER M4 ;
        RECT  36.528 103.104 36.72 103.128 ;
    END
  END dq[608]
  PIN dq[609]
    DIRECTION OUTPUT ;
    USE SIGNAL ;
    PORT
      LAYER M4 ;
        RECT  36.528 103.248 36.72 103.272 ;
    END
  END dq[609]
  PIN dq[60]
    DIRECTION OUTPUT ;
    USE SIGNAL ;
    PORT
      LAYER M4 ;
        RECT  36.528 14.16 36.72 14.184 ;
    END
  END dq[60]
  PIN dq[610]
    DIRECTION OUTPUT ;
    USE SIGNAL ;
    PORT
      LAYER M4 ;
        RECT  36.528 103.44 36.72 103.464 ;
    END
  END dq[610]
  PIN dq[611]
    DIRECTION OUTPUT ;
    USE SIGNAL ;
    PORT
      LAYER M4 ;
        RECT  36.528 103.584 36.72 103.608 ;
    END
  END dq[611]
  PIN dq[612]
    DIRECTION OUTPUT ;
    USE SIGNAL ;
    PORT
      LAYER M4 ;
        RECT  36.528 103.728 36.72 103.752 ;
    END
  END dq[612]
  PIN dq[613]
    DIRECTION OUTPUT ;
    USE SIGNAL ;
    PORT
      LAYER M4 ;
        RECT  36.528 103.92 36.72 103.944 ;
    END
  END dq[613]
  PIN dq[614]
    DIRECTION OUTPUT ;
    USE SIGNAL ;
    PORT
      LAYER M4 ;
        RECT  36.528 104.064 36.72 104.088 ;
    END
  END dq[614]
  PIN dq[615]
    DIRECTION OUTPUT ;
    USE SIGNAL ;
    PORT
      LAYER M4 ;
        RECT  36.528 104.256 36.72 104.28 ;
    END
  END dq[615]
  PIN dq[616]
    DIRECTION OUTPUT ;
    USE SIGNAL ;
    PORT
      LAYER M4 ;
        RECT  36.528 104.4 36.72 104.424 ;
    END
  END dq[616]
  PIN dq[617]
    DIRECTION OUTPUT ;
    USE SIGNAL ;
    PORT
      LAYER M4 ;
        RECT  36.528 104.544 36.72 104.568 ;
    END
  END dq[617]
  PIN dq[618]
    DIRECTION OUTPUT ;
    USE SIGNAL ;
    PORT
      LAYER M4 ;
        RECT  36.528 104.736 36.72 104.76 ;
    END
  END dq[618]
  PIN dq[619]
    DIRECTION OUTPUT ;
    USE SIGNAL ;
    PORT
      LAYER M4 ;
        RECT  36.528 104.88 36.72 104.904 ;
    END
  END dq[619]
  PIN dq[61]
    DIRECTION OUTPUT ;
    USE SIGNAL ;
    PORT
      LAYER M4 ;
        RECT  36.528 14.304 36.72 14.328 ;
    END
  END dq[61]
  PIN dq[620]
    DIRECTION OUTPUT ;
    USE SIGNAL ;
    PORT
      LAYER M4 ;
        RECT  36.528 105.024 36.72 105.048 ;
    END
  END dq[620]
  PIN dq[621]
    DIRECTION OUTPUT ;
    USE SIGNAL ;
    PORT
      LAYER M4 ;
        RECT  36.528 105.216 36.72 105.24 ;
    END
  END dq[621]
  PIN dq[622]
    DIRECTION OUTPUT ;
    USE SIGNAL ;
    PORT
      LAYER M4 ;
        RECT  36.528 105.36 36.72 105.384 ;
    END
  END dq[622]
  PIN dq[623]
    DIRECTION OUTPUT ;
    USE SIGNAL ;
    PORT
      LAYER M4 ;
        RECT  36.528 105.552 36.72 105.576 ;
    END
  END dq[623]
  PIN dq[624]
    DIRECTION OUTPUT ;
    USE SIGNAL ;
    PORT
      LAYER M4 ;
        RECT  36.528 105.696 36.72 105.72 ;
    END
  END dq[624]
  PIN dq[625]
    DIRECTION OUTPUT ;
    USE SIGNAL ;
    PORT
      LAYER M4 ;
        RECT  36.528 105.84 36.72 105.864 ;
    END
  END dq[625]
  PIN dq[626]
    DIRECTION OUTPUT ;
    USE SIGNAL ;
    PORT
      LAYER M4 ;
        RECT  36.528 106.032 36.72 106.056 ;
    END
  END dq[626]
  PIN dq[627]
    DIRECTION OUTPUT ;
    USE SIGNAL ;
    PORT
      LAYER M4 ;
        RECT  36.528 106.176 36.72 106.2 ;
    END
  END dq[627]
  PIN dq[628]
    DIRECTION OUTPUT ;
    USE SIGNAL ;
    PORT
      LAYER M4 ;
        RECT  36.528 106.368 36.72 106.392 ;
    END
  END dq[628]
  PIN dq[629]
    DIRECTION OUTPUT ;
    USE SIGNAL ;
    PORT
      LAYER M4 ;
        RECT  36.528 106.512 36.72 106.536 ;
    END
  END dq[629]
  PIN dq[62]
    DIRECTION OUTPUT ;
    USE SIGNAL ;
    PORT
      LAYER M4 ;
        RECT  36.528 14.496 36.72 14.52 ;
    END
  END dq[62]
  PIN dq[630]
    DIRECTION OUTPUT ;
    USE SIGNAL ;
    PORT
      LAYER M4 ;
        RECT  36.528 106.656 36.72 106.68 ;
    END
  END dq[630]
  PIN dq[631]
    DIRECTION OUTPUT ;
    USE SIGNAL ;
    PORT
      LAYER M4 ;
        RECT  36.528 106.848 36.72 106.872 ;
    END
  END dq[631]
  PIN dq[632]
    DIRECTION OUTPUT ;
    USE SIGNAL ;
    PORT
      LAYER M4 ;
        RECT  36.528 106.992 36.72 107.016 ;
    END
  END dq[632]
  PIN dq[633]
    DIRECTION OUTPUT ;
    USE SIGNAL ;
    PORT
      LAYER M4 ;
        RECT  36.528 107.136 36.72 107.16 ;
    END
  END dq[633]
  PIN dq[634]
    DIRECTION OUTPUT ;
    USE SIGNAL ;
    PORT
      LAYER M4 ;
        RECT  36.528 107.328 36.72 107.352 ;
    END
  END dq[634]
  PIN dq[635]
    DIRECTION OUTPUT ;
    USE SIGNAL ;
    PORT
      LAYER M4 ;
        RECT  36.528 107.472 36.72 107.496 ;
    END
  END dq[635]
  PIN dq[636]
    DIRECTION OUTPUT ;
    USE SIGNAL ;
    PORT
      LAYER M4 ;
        RECT  36.528 107.664 36.72 107.688 ;
    END
  END dq[636]
  PIN dq[637]
    DIRECTION OUTPUT ;
    USE SIGNAL ;
    PORT
      LAYER M4 ;
        RECT  36.528 107.808 36.72 107.832 ;
    END
  END dq[637]
  PIN dq[638]
    DIRECTION OUTPUT ;
    USE SIGNAL ;
    PORT
      LAYER M4 ;
        RECT  36.528 107.952 36.72 107.976 ;
    END
  END dq[638]
  PIN dq[639]
    DIRECTION OUTPUT ;
    USE SIGNAL ;
    PORT
      LAYER M4 ;
        RECT  36.528 108.144 36.72 108.168 ;
    END
  END dq[639]
  PIN dq[63]
    DIRECTION OUTPUT ;
    USE SIGNAL ;
    PORT
      LAYER M4 ;
        RECT  36.528 14.64 36.72 14.664 ;
    END
  END dq[63]
  PIN dq[640]
    DIRECTION OUTPUT ;
    USE SIGNAL ;
    PORT
      LAYER M4 ;
        RECT  36.528 108.288 36.72 108.312 ;
    END
  END dq[640]
  PIN dq[641]
    DIRECTION OUTPUT ;
    USE SIGNAL ;
    PORT
      LAYER M4 ;
        RECT  36.528 108.432 36.72 108.456 ;
    END
  END dq[641]
  PIN dq[642]
    DIRECTION OUTPUT ;
    USE SIGNAL ;
    PORT
      LAYER M4 ;
        RECT  36.528 108.624 36.72 108.648 ;
    END
  END dq[642]
  PIN dq[643]
    DIRECTION OUTPUT ;
    USE SIGNAL ;
    PORT
      LAYER M4 ;
        RECT  36.528 108.768 36.72 108.792 ;
    END
  END dq[643]
  PIN dq[644]
    DIRECTION OUTPUT ;
    USE SIGNAL ;
    PORT
      LAYER M4 ;
        RECT  36.528 108.96 36.72 108.984 ;
    END
  END dq[644]
  PIN dq[645]
    DIRECTION OUTPUT ;
    USE SIGNAL ;
    PORT
      LAYER M4 ;
        RECT  36.528 109.104 36.72 109.128 ;
    END
  END dq[645]
  PIN dq[646]
    DIRECTION OUTPUT ;
    USE SIGNAL ;
    PORT
      LAYER M4 ;
        RECT  36.528 109.248 36.72 109.272 ;
    END
  END dq[646]
  PIN dq[647]
    DIRECTION OUTPUT ;
    USE SIGNAL ;
    PORT
      LAYER M4 ;
        RECT  36.528 109.44 36.72 109.464 ;
    END
  END dq[647]
  PIN dq[648]
    DIRECTION OUTPUT ;
    USE SIGNAL ;
    PORT
      LAYER M4 ;
        RECT  36.528 109.584 36.72 109.608 ;
    END
  END dq[648]
  PIN dq[649]
    DIRECTION OUTPUT ;
    USE SIGNAL ;
    PORT
      LAYER M4 ;
        RECT  36.528 109.776 36.72 109.8 ;
    END
  END dq[649]
  PIN dq[64]
    DIRECTION OUTPUT ;
    USE SIGNAL ;
    PORT
      LAYER M4 ;
        RECT  36.528 14.784 36.72 14.808 ;
    END
  END dq[64]
  PIN dq[650]
    DIRECTION OUTPUT ;
    USE SIGNAL ;
    PORT
      LAYER M4 ;
        RECT  36.528 109.92 36.72 109.944 ;
    END
  END dq[650]
  PIN dq[651]
    DIRECTION OUTPUT ;
    USE SIGNAL ;
    PORT
      LAYER M4 ;
        RECT  36.528 110.064 36.72 110.088 ;
    END
  END dq[651]
  PIN dq[652]
    DIRECTION OUTPUT ;
    USE SIGNAL ;
    PORT
      LAYER M4 ;
        RECT  36.528 110.256 36.72 110.28 ;
    END
  END dq[652]
  PIN dq[653]
    DIRECTION OUTPUT ;
    USE SIGNAL ;
    PORT
      LAYER M4 ;
        RECT  36.528 110.4 36.72 110.424 ;
    END
  END dq[653]
  PIN dq[654]
    DIRECTION OUTPUT ;
    USE SIGNAL ;
    PORT
      LAYER M4 ;
        RECT  36.528 110.544 36.72 110.568 ;
    END
  END dq[654]
  PIN dq[655]
    DIRECTION OUTPUT ;
    USE SIGNAL ;
    PORT
      LAYER M4 ;
        RECT  36.528 110.736 36.72 110.76 ;
    END
  END dq[655]
  PIN dq[656]
    DIRECTION OUTPUT ;
    USE SIGNAL ;
    PORT
      LAYER M4 ;
        RECT  36.528 110.88 36.72 110.904 ;
    END
  END dq[656]
  PIN dq[657]
    DIRECTION OUTPUT ;
    USE SIGNAL ;
    PORT
      LAYER M4 ;
        RECT  36.528 111.072 36.72 111.096 ;
    END
  END dq[657]
  PIN dq[658]
    DIRECTION OUTPUT ;
    USE SIGNAL ;
    PORT
      LAYER M4 ;
        RECT  36.528 111.216 36.72 111.24 ;
    END
  END dq[658]
  PIN dq[659]
    DIRECTION OUTPUT ;
    USE SIGNAL ;
    PORT
      LAYER M4 ;
        RECT  36.528 111.36 36.72 111.384 ;
    END
  END dq[659]
  PIN dq[65]
    DIRECTION OUTPUT ;
    USE SIGNAL ;
    PORT
      LAYER M4 ;
        RECT  36.528 14.976 36.72 15 ;
    END
  END dq[65]
  PIN dq[660]
    DIRECTION OUTPUT ;
    USE SIGNAL ;
    PORT
      LAYER M4 ;
        RECT  36.528 111.552 36.72 111.576 ;
    END
  END dq[660]
  PIN dq[661]
    DIRECTION OUTPUT ;
    USE SIGNAL ;
    PORT
      LAYER M4 ;
        RECT  36.528 111.696 36.72 111.72 ;
    END
  END dq[661]
  PIN dq[662]
    DIRECTION OUTPUT ;
    USE SIGNAL ;
    PORT
      LAYER M4 ;
        RECT  36.528 111.84 36.72 111.864 ;
    END
  END dq[662]
  PIN dq[663]
    DIRECTION OUTPUT ;
    USE SIGNAL ;
    PORT
      LAYER M4 ;
        RECT  36.528 112.032 36.72 112.056 ;
    END
  END dq[663]
  PIN dq[664]
    DIRECTION OUTPUT ;
    USE SIGNAL ;
    PORT
      LAYER M4 ;
        RECT  36.528 112.176 36.72 112.2 ;
    END
  END dq[664]
  PIN dq[665]
    DIRECTION OUTPUT ;
    USE SIGNAL ;
    PORT
      LAYER M4 ;
        RECT  36.528 112.368 36.72 112.392 ;
    END
  END dq[665]
  PIN dq[666]
    DIRECTION OUTPUT ;
    USE SIGNAL ;
    PORT
      LAYER M4 ;
        RECT  36.528 112.512 36.72 112.536 ;
    END
  END dq[666]
  PIN dq[667]
    DIRECTION OUTPUT ;
    USE SIGNAL ;
    PORT
      LAYER M4 ;
        RECT  36.528 112.656 36.72 112.68 ;
    END
  END dq[667]
  PIN dq[668]
    DIRECTION OUTPUT ;
    USE SIGNAL ;
    PORT
      LAYER M4 ;
        RECT  36.528 112.848 36.72 112.872 ;
    END
  END dq[668]
  PIN dq[669]
    DIRECTION OUTPUT ;
    USE SIGNAL ;
    PORT
      LAYER M4 ;
        RECT  36.528 112.992 36.72 113.016 ;
    END
  END dq[669]
  PIN dq[66]
    DIRECTION OUTPUT ;
    USE SIGNAL ;
    PORT
      LAYER M4 ;
        RECT  36.528 15.12 36.72 15.144 ;
    END
  END dq[66]
  PIN dq[670]
    DIRECTION OUTPUT ;
    USE SIGNAL ;
    PORT
      LAYER M4 ;
        RECT  36.528 113.184 36.72 113.208 ;
    END
  END dq[670]
  PIN dq[671]
    DIRECTION OUTPUT ;
    USE SIGNAL ;
    PORT
      LAYER M4 ;
        RECT  36.528 113.328 36.72 113.352 ;
    END
  END dq[671]
  PIN dq[672]
    DIRECTION OUTPUT ;
    USE SIGNAL ;
    PORT
      LAYER M4 ;
        RECT  36.528 113.472 36.72 113.496 ;
    END
  END dq[672]
  PIN dq[673]
    DIRECTION OUTPUT ;
    USE SIGNAL ;
    PORT
      LAYER M4 ;
        RECT  36.528 113.664 36.72 113.688 ;
    END
  END dq[673]
  PIN dq[674]
    DIRECTION OUTPUT ;
    USE SIGNAL ;
    PORT
      LAYER M4 ;
        RECT  36.528 113.808 36.72 113.832 ;
    END
  END dq[674]
  PIN dq[675]
    DIRECTION OUTPUT ;
    USE SIGNAL ;
    PORT
      LAYER M4 ;
        RECT  36.528 113.952 36.72 113.976 ;
    END
  END dq[675]
  PIN dq[676]
    DIRECTION OUTPUT ;
    USE SIGNAL ;
    PORT
      LAYER M4 ;
        RECT  36.528 114.144 36.72 114.168 ;
    END
  END dq[676]
  PIN dq[677]
    DIRECTION OUTPUT ;
    USE SIGNAL ;
    PORT
      LAYER M4 ;
        RECT  36.528 114.288 36.72 114.312 ;
    END
  END dq[677]
  PIN dq[678]
    DIRECTION OUTPUT ;
    USE SIGNAL ;
    PORT
      LAYER M4 ;
        RECT  36.528 114.48 36.72 114.504 ;
    END
  END dq[678]
  PIN dq[679]
    DIRECTION OUTPUT ;
    USE SIGNAL ;
    PORT
      LAYER M4 ;
        RECT  36.528 114.624 36.72 114.648 ;
    END
  END dq[679]
  PIN dq[67]
    DIRECTION OUTPUT ;
    USE SIGNAL ;
    PORT
      LAYER M4 ;
        RECT  36.528 15.312 36.72 15.336 ;
    END
  END dq[67]
  PIN dq[680]
    DIRECTION OUTPUT ;
    USE SIGNAL ;
    PORT
      LAYER M4 ;
        RECT  36.528 114.768 36.72 114.792 ;
    END
  END dq[680]
  PIN dq[681]
    DIRECTION OUTPUT ;
    USE SIGNAL ;
    PORT
      LAYER M4 ;
        RECT  36.528 114.96 36.72 114.984 ;
    END
  END dq[681]
  PIN dq[682]
    DIRECTION OUTPUT ;
    USE SIGNAL ;
    PORT
      LAYER M4 ;
        RECT  36.528 115.104 36.72 115.128 ;
    END
  END dq[682]
  PIN dq[683]
    DIRECTION OUTPUT ;
    USE SIGNAL ;
    PORT
      LAYER M4 ;
        RECT  36.528 115.296 36.72 115.32 ;
    END
  END dq[683]
  PIN dq[684]
    DIRECTION OUTPUT ;
    USE SIGNAL ;
    PORT
      LAYER M4 ;
        RECT  36.528 115.44 36.72 115.464 ;
    END
  END dq[684]
  PIN dq[685]
    DIRECTION OUTPUT ;
    USE SIGNAL ;
    PORT
      LAYER M4 ;
        RECT  36.528 115.584 36.72 115.608 ;
    END
  END dq[685]
  PIN dq[686]
    DIRECTION OUTPUT ;
    USE SIGNAL ;
    PORT
      LAYER M4 ;
        RECT  36.528 115.776 36.72 115.8 ;
    END
  END dq[686]
  PIN dq[687]
    DIRECTION OUTPUT ;
    USE SIGNAL ;
    PORT
      LAYER M4 ;
        RECT  36.528 115.92 36.72 115.944 ;
    END
  END dq[687]
  PIN dq[688]
    DIRECTION OUTPUT ;
    USE SIGNAL ;
    PORT
      LAYER M4 ;
        RECT  36.528 116.064 36.72 116.088 ;
    END
  END dq[688]
  PIN dq[689]
    DIRECTION OUTPUT ;
    USE SIGNAL ;
    PORT
      LAYER M4 ;
        RECT  36.528 116.256 36.72 116.28 ;
    END
  END dq[689]
  PIN dq[68]
    DIRECTION OUTPUT ;
    USE SIGNAL ;
    PORT
      LAYER M4 ;
        RECT  36.528 15.456 36.72 15.48 ;
    END
  END dq[68]
  PIN dq[690]
    DIRECTION OUTPUT ;
    USE SIGNAL ;
    PORT
      LAYER M4 ;
        RECT  36.528 116.4 36.72 116.424 ;
    END
  END dq[690]
  PIN dq[691]
    DIRECTION OUTPUT ;
    USE SIGNAL ;
    PORT
      LAYER M4 ;
        RECT  36.528 116.592 36.72 116.616 ;
    END
  END dq[691]
  PIN dq[69]
    DIRECTION OUTPUT ;
    USE SIGNAL ;
    PORT
      LAYER M4 ;
        RECT  36.528 15.6 36.72 15.624 ;
    END
  END dq[69]
  PIN dq[6]
    DIRECTION OUTPUT ;
    USE SIGNAL ;
    PORT
      LAYER M4 ;
        RECT  36.528 5.376 36.72 5.4 ;
    END
  END dq[6]
  PIN dq[70]
    DIRECTION OUTPUT ;
    USE SIGNAL ;
    PORT
      LAYER M4 ;
        RECT  36.528 15.792 36.72 15.816 ;
    END
  END dq[70]
  PIN dq[71]
    DIRECTION OUTPUT ;
    USE SIGNAL ;
    PORT
      LAYER M4 ;
        RECT  36.528 15.936 36.72 15.96 ;
    END
  END dq[71]
  PIN dq[72]
    DIRECTION OUTPUT ;
    USE SIGNAL ;
    PORT
      LAYER M4 ;
        RECT  36.528 16.08 36.72 16.104 ;
    END
  END dq[72]
  PIN dq[73]
    DIRECTION OUTPUT ;
    USE SIGNAL ;
    PORT
      LAYER M4 ;
        RECT  36.528 16.272 36.72 16.296 ;
    END
  END dq[73]
  PIN dq[74]
    DIRECTION OUTPUT ;
    USE SIGNAL ;
    PORT
      LAYER M4 ;
        RECT  36.528 16.416 36.72 16.44 ;
    END
  END dq[74]
  PIN dq[75]
    DIRECTION OUTPUT ;
    USE SIGNAL ;
    PORT
      LAYER M4 ;
        RECT  36.528 16.608 36.72 16.632 ;
    END
  END dq[75]
  PIN dq[76]
    DIRECTION OUTPUT ;
    USE SIGNAL ;
    PORT
      LAYER M4 ;
        RECT  36.528 16.752 36.72 16.776 ;
    END
  END dq[76]
  PIN dq[77]
    DIRECTION OUTPUT ;
    USE SIGNAL ;
    PORT
      LAYER M4 ;
        RECT  36.528 16.896 36.72 16.92 ;
    END
  END dq[77]
  PIN dq[78]
    DIRECTION OUTPUT ;
    USE SIGNAL ;
    PORT
      LAYER M4 ;
        RECT  36.528 17.088 36.72 17.112 ;
    END
  END dq[78]
  PIN dq[79]
    DIRECTION OUTPUT ;
    USE SIGNAL ;
    PORT
      LAYER M4 ;
        RECT  36.528 17.232 36.72 17.256 ;
    END
  END dq[79]
  PIN dq[7]
    DIRECTION OUTPUT ;
    USE SIGNAL ;
    PORT
      LAYER M4 ;
        RECT  36.528 5.568 36.72 5.592 ;
    END
  END dq[7]
  PIN dq[80]
    DIRECTION OUTPUT ;
    USE SIGNAL ;
    PORT
      LAYER M4 ;
        RECT  36.528 17.376 36.72 17.4 ;
    END
  END dq[80]
  PIN dq[81]
    DIRECTION OUTPUT ;
    USE SIGNAL ;
    PORT
      LAYER M4 ;
        RECT  36.528 17.568 36.72 17.592 ;
    END
  END dq[81]
  PIN dq[82]
    DIRECTION OUTPUT ;
    USE SIGNAL ;
    PORT
      LAYER M4 ;
        RECT  36.528 17.712 36.72 17.736 ;
    END
  END dq[82]
  PIN dq[83]
    DIRECTION OUTPUT ;
    USE SIGNAL ;
    PORT
      LAYER M4 ;
        RECT  36.528 17.904 36.72 17.928 ;
    END
  END dq[83]
  PIN dq[84]
    DIRECTION OUTPUT ;
    USE SIGNAL ;
    PORT
      LAYER M4 ;
        RECT  36.528 18.048 36.72 18.072 ;
    END
  END dq[84]
  PIN dq[85]
    DIRECTION OUTPUT ;
    USE SIGNAL ;
    PORT
      LAYER M4 ;
        RECT  36.528 18.192 36.72 18.216 ;
    END
  END dq[85]
  PIN dq[86]
    DIRECTION OUTPUT ;
    USE SIGNAL ;
    PORT
      LAYER M4 ;
        RECT  36.528 18.384 36.72 18.408 ;
    END
  END dq[86]
  PIN dq[87]
    DIRECTION OUTPUT ;
    USE SIGNAL ;
    PORT
      LAYER M4 ;
        RECT  36.528 18.528 36.72 18.552 ;
    END
  END dq[87]
  PIN dq[88]
    DIRECTION OUTPUT ;
    USE SIGNAL ;
    PORT
      LAYER M4 ;
        RECT  36.528 18.72 36.72 18.744 ;
    END
  END dq[88]
  PIN dq[89]
    DIRECTION OUTPUT ;
    USE SIGNAL ;
    PORT
      LAYER M4 ;
        RECT  36.528 18.864 36.72 18.888 ;
    END
  END dq[89]
  PIN dq[8]
    DIRECTION OUTPUT ;
    USE SIGNAL ;
    PORT
      LAYER M4 ;
        RECT  36.528 5.712 36.72 5.736 ;
    END
  END dq[8]
  PIN dq[90]
    DIRECTION OUTPUT ;
    USE SIGNAL ;
    PORT
      LAYER M4 ;
        RECT  36.528 19.008 36.72 19.032 ;
    END
  END dq[90]
  PIN dq[91]
    DIRECTION OUTPUT ;
    USE SIGNAL ;
    PORT
      LAYER M4 ;
        RECT  36.528 19.2 36.72 19.224 ;
    END
  END dq[91]
  PIN dq[92]
    DIRECTION OUTPUT ;
    USE SIGNAL ;
    PORT
      LAYER M4 ;
        RECT  36.528 19.344 36.72 19.368 ;
    END
  END dq[92]
  PIN dq[93]
    DIRECTION OUTPUT ;
    USE SIGNAL ;
    PORT
      LAYER M4 ;
        RECT  36.528 19.488 36.72 19.512 ;
    END
  END dq[93]
  PIN dq[94]
    DIRECTION OUTPUT ;
    USE SIGNAL ;
    PORT
      LAYER M4 ;
        RECT  36.528 19.68 36.72 19.704 ;
    END
  END dq[94]
  PIN dq[95]
    DIRECTION OUTPUT ;
    USE SIGNAL ;
    PORT
      LAYER M4 ;
        RECT  36.528 19.824 36.72 19.848 ;
    END
  END dq[95]
  PIN dq[96]
    DIRECTION OUTPUT ;
    USE SIGNAL ;
    PORT
      LAYER M4 ;
        RECT  36.528 20.016 36.72 20.04 ;
    END
  END dq[96]
  PIN dq[97]
    DIRECTION OUTPUT ;
    USE SIGNAL ;
    PORT
      LAYER M4 ;
        RECT  36.528 20.16 36.72 20.184 ;
    END
  END dq[97]
  PIN dq[98]
    DIRECTION OUTPUT ;
    USE SIGNAL ;
    PORT
      LAYER M4 ;
        RECT  36.528 20.304 36.72 20.328 ;
    END
  END dq[98]
  PIN dq[99]
    DIRECTION OUTPUT ;
    USE SIGNAL ;
    PORT
      LAYER M4 ;
        RECT  36.528 20.496 36.72 20.52 ;
    END
  END dq[99]
  PIN dq[9]
    DIRECTION OUTPUT ;
    USE SIGNAL ;
    PORT
      LAYER M4 ;
        RECT  36.528 5.856 36.72 5.88 ;
    END
  END dq[9]
  PIN VDD
    DIRECTION INOUT ;
    USE POWER ;
    PORT
      LAYER M5 ;
        RECT  32.292 2.151 32.412 118.809 ;
        RECT  29.592 2.151 29.712 118.809 ;
        RECT  26.892 2.151 27.012 118.809 ;
        RECT  24.192 2.151 24.312 118.809 ;
        RECT  21.492 2.151 21.612 118.809 ;
        RECT  18.792 2.151 18.912 118.809 ;
        RECT  16.092 2.151 16.212 118.809 ;
        RECT  13.392 2.151 13.512 118.809 ;
        RECT  10.692 2.151 10.812 118.809 ;
        RECT  7.992 2.151 8.112 118.809 ;
        RECT  5.292 2.151 5.412 118.809 ;
        RECT  2.592 2.151 2.712 118.809 ;
    END
  END VDD
  PIN VSS
    DIRECTION INOUT ;
    USE GROUND ;
    PORT
      LAYER M5 ;
        RECT  32.1 2.137 32.22 118.823 ;
        RECT  29.4 2.137 29.52 118.823 ;
        RECT  26.7 2.137 26.82 118.823 ;
        RECT  24 2.137 24.12 118.823 ;
        RECT  21.3 2.137 21.42 118.823 ;
        RECT  18.6 2.137 18.72 118.823 ;
        RECT  15.9 2.137 16.02 118.823 ;
        RECT  13.2 2.137 13.32 118.823 ;
        RECT  10.5 2.137 10.62 118.823 ;
        RECT  7.8 2.137 7.92 118.823 ;
        RECT  5.1 2.137 5.22 118.823 ;
        RECT  2.4 2.137 2.52 118.823 ;
    END
  END VSS
  # OT_OBS_CLOSED layer=M5 d_um=1.536 added=108
  OBS
    LAYER RVTN ;
     RECT  2.16 2.16 34.56 2.295 ;
     RECT  2.16 2.565 34.56 2.835 ;
     RECT  2.16 3.105 34.56 3.375 ;
     RECT  2.16 3.645 34.56 3.915 ;
     RECT  2.16 4.185 34.56 4.455 ;
     RECT  2.16 4.725 34.56 4.995 ;
     RECT  2.16 5.265 34.56 5.535 ;
     RECT  2.16 5.805 34.56 6.075 ;
     RECT  2.16 6.345 34.56 6.615 ;
     RECT  2.16 6.885 34.56 7.155 ;
     RECT  2.16 7.425 34.56 7.695 ;
     RECT  2.16 7.965 34.56 8.235 ;
     RECT  2.16 8.505 34.56 8.775 ;
     RECT  2.16 9.045 34.56 9.315 ;
     RECT  2.16 9.585 34.56 9.855 ;
     RECT  2.16 10.125 34.56 10.395 ;
     RECT  2.16 10.665 34.56 10.935 ;
     RECT  2.16 11.205 34.56 11.475 ;
     RECT  2.16 11.745 34.56 12.015 ;
     RECT  2.16 12.285 34.56 12.555 ;
     RECT  2.16 12.825 34.56 13.095 ;
     RECT  2.16 13.365 34.56 13.635 ;
     RECT  2.16 13.905 34.56 14.175 ;
     RECT  2.16 14.445 34.56 14.715 ;
     RECT  2.16 14.985 34.56 15.255 ;
     RECT  2.16 15.525 34.56 15.795 ;
     RECT  2.16 16.065 34.56 16.335 ;
     RECT  2.16 16.605 34.56 16.875 ;
     RECT  2.16 17.145 34.56 17.415 ;
     RECT  2.16 17.685 34.56 17.955 ;
     RECT  2.16 18.225 34.56 18.495 ;
     RECT  2.16 18.765 34.56 19.035 ;
     RECT  2.16 19.305 34.56 19.575 ;
     RECT  2.16 19.845 34.56 20.115 ;
     RECT  2.16 20.385 34.56 20.655 ;
     RECT  2.16 20.925 34.56 21.195 ;
     RECT  2.16 21.465 34.56 21.735 ;
     RECT  2.16 22.005 34.56 22.275 ;
     RECT  2.16 22.545 34.56 22.815 ;
     RECT  2.16 23.085 34.56 23.355 ;
     RECT  2.16 23.625 34.56 23.895 ;
     RECT  2.16 24.165 34.56 24.435 ;
     RECT  2.16 24.705 34.56 24.975 ;
     RECT  2.16 25.245 34.56 25.515 ;
     RECT  2.16 25.785 34.56 26.055 ;
     RECT  2.16 26.325 34.56 26.595 ;
     RECT  2.16 26.865 34.56 27.135 ;
     RECT  2.16 27.405 34.56 27.675 ;
     RECT  2.16 27.945 34.56 28.215 ;
     RECT  2.16 28.485 34.56 28.755 ;
     RECT  2.16 29.025 34.56 29.295 ;
     RECT  2.16 29.565 34.56 29.835 ;
     RECT  2.16 30.105 34.56 30.375 ;
     RECT  2.16 30.645 34.56 30.915 ;
     RECT  2.16 31.185 34.56 31.455 ;
     RECT  2.16 31.725 34.56 31.995 ;
     RECT  2.16 32.265 34.56 32.535 ;
     RECT  2.16 32.805 34.56 33.075 ;
     RECT  2.16 33.345 34.56 33.615 ;
     RECT  2.16 33.885 34.56 34.155 ;
     RECT  2.16 34.425 34.56 34.695 ;
     RECT  2.16 34.965 34.56 35.235 ;
     RECT  2.16 35.505 34.56 35.775 ;
     RECT  2.16 36.045 34.56 36.315 ;
     RECT  2.16 36.585 34.56 36.855 ;
     RECT  2.16 37.125 34.56 37.395 ;
     RECT  2.16 37.665 34.56 37.935 ;
     RECT  2.16 38.205 34.56 38.475 ;
     RECT  2.16 38.745 34.56 39.015 ;
     RECT  2.16 39.285 34.56 39.555 ;
     RECT  2.16 39.825 34.56 40.095 ;
     RECT  2.16 40.365 34.56 40.635 ;
     RECT  2.16 40.905 34.56 41.175 ;
     RECT  2.16 41.445 34.56 41.715 ;
     RECT  2.16 41.985 34.56 42.255 ;
     RECT  2.16 42.525 34.56 42.795 ;
     RECT  2.16 43.065 34.56 43.335 ;
     RECT  2.16 43.605 34.56 43.875 ;
     RECT  2.16 44.145 34.56 44.415 ;
     RECT  2.16 44.685 34.56 44.955 ;
     RECT  2.16 45.225 34.56 45.495 ;
     RECT  2.16 45.765 34.56 46.035 ;
     RECT  2.16 46.305 34.56 46.575 ;
     RECT  2.16 46.845 34.56 47.115 ;
     RECT  2.16 47.385 34.56 47.655 ;
     RECT  2.16 47.925 34.56 48.195 ;
     RECT  2.16 48.465 34.56 48.735 ;
     RECT  2.16 49.005 34.56 49.275 ;
     RECT  2.16 49.545 34.56 49.815 ;
     RECT  2.16 50.085 34.56 50.355 ;
     RECT  2.16 50.625 34.56 50.895 ;
     RECT  2.16 51.165 34.56 51.435 ;
     RECT  2.16 51.705 34.56 51.975 ;
     RECT  2.16 52.245 34.56 52.515 ;
     RECT  2.16 52.785 34.56 53.055 ;
     RECT  2.16 53.325 34.56 53.595 ;
     RECT  2.16 53.865 34.56 54.135 ;
     RECT  2.16 54.405 34.56 54.675 ;
     RECT  2.16 54.945 34.56 55.215 ;
     RECT  2.16 55.485 34.56 55.755 ;
     RECT  2.16 56.025 34.56 56.295 ;
     RECT  2.16 56.565 34.56 56.835 ;
     RECT  2.16 57.105 34.56 57.375 ;
     RECT  2.16 57.645 34.56 57.915 ;
     RECT  2.16 58.185 34.56 58.455 ;
     RECT  2.16 58.725 34.56 58.995 ;
     RECT  2.16 59.265 34.56 59.535 ;
     RECT  2.16 59.805 34.56 60.075 ;
     RECT  2.16 60.345 34.56 60.615 ;
     RECT  2.16 60.885 34.56 61.155 ;
     RECT  2.16 61.425 34.56 61.695 ;
     RECT  2.16 61.965 34.56 62.235 ;
     RECT  2.16 62.505 34.56 62.775 ;
     RECT  2.16 63.045 34.56 63.315 ;
     RECT  2.16 63.585 34.56 63.855 ;
     RECT  2.16 64.125 34.56 64.395 ;
     RECT  2.16 64.665 34.56 64.935 ;
     RECT  2.16 65.205 34.56 65.475 ;
     RECT  2.16 65.745 34.56 66.015 ;
     RECT  2.16 66.285 34.56 66.555 ;
     RECT  2.16 66.825 34.56 67.095 ;
     RECT  2.16 67.365 34.56 67.635 ;
     RECT  2.16 67.905 34.56 68.175 ;
     RECT  2.16 68.445 34.56 68.715 ;
     RECT  2.16 68.985 34.56 69.255 ;
     RECT  2.16 69.525 34.56 69.795 ;
     RECT  2.16 70.065 34.56 70.335 ;
     RECT  2.16 70.605 34.56 70.875 ;
     RECT  2.16 71.145 34.56 71.415 ;
     RECT  2.16 71.685 34.56 71.955 ;
     RECT  2.16 72.225 34.56 72.495 ;
     RECT  2.16 72.765 34.56 73.035 ;
     RECT  2.16 73.305 34.56 73.575 ;
     RECT  2.16 73.845 34.56 74.115 ;
     RECT  2.16 74.385 34.56 74.655 ;
     RECT  2.16 74.925 34.56 75.195 ;
     RECT  2.16 75.465 34.56 75.735 ;
     RECT  2.16 76.005 34.56 76.275 ;
     RECT  2.16 76.545 34.56 76.815 ;
     RECT  2.16 77.085 34.56 77.355 ;
     RECT  2.16 77.625 34.56 77.895 ;
     RECT  2.16 78.165 34.56 78.435 ;
     RECT  2.16 78.705 34.56 78.975 ;
     RECT  2.16 79.245 34.56 79.515 ;
     RECT  2.16 79.785 34.56 80.055 ;
     RECT  2.16 80.325 34.56 80.595 ;
     RECT  2.16 80.865 34.56 81.135 ;
     RECT  2.16 81.405 34.56 81.675 ;
     RECT  2.16 81.945 34.56 82.215 ;
     RECT  2.16 82.485 34.56 82.755 ;
     RECT  2.16 83.025 34.56 83.295 ;
     RECT  2.16 83.565 34.56 83.835 ;
     RECT  2.16 84.105 34.56 84.375 ;
     RECT  2.16 84.645 34.56 84.915 ;
     RECT  2.16 85.185 34.56 85.455 ;
     RECT  2.16 85.725 34.56 85.995 ;
     RECT  2.16 86.265 34.56 86.535 ;
     RECT  2.16 86.805 34.56 87.075 ;
     RECT  2.16 87.345 34.56 87.615 ;
     RECT  2.16 87.885 34.56 88.155 ;
     RECT  2.16 88.425 34.56 88.695 ;
     RECT  2.16 88.965 34.56 89.235 ;
     RECT  2.16 89.505 34.56 89.775 ;
     RECT  2.16 90.045 34.56 90.315 ;
     RECT  2.16 90.585 34.56 90.855 ;
     RECT  2.16 91.125 34.56 91.395 ;
     RECT  2.16 91.665 34.56 91.935 ;
     RECT  2.16 92.205 34.56 92.475 ;
     RECT  2.16 92.745 34.56 93.015 ;
     RECT  2.16 93.285 34.56 93.555 ;
     RECT  2.16 93.825 34.56 94.095 ;
     RECT  2.16 94.365 34.56 94.635 ;
     RECT  2.16 94.905 34.56 95.175 ;
     RECT  2.16 95.445 34.56 95.715 ;
     RECT  2.16 95.985 34.56 96.255 ;
     RECT  2.16 96.525 34.56 96.795 ;
     RECT  2.16 97.065 34.56 97.335 ;
     RECT  2.16 97.605 34.56 97.875 ;
     RECT  2.16 98.145 34.56 98.415 ;
     RECT  2.16 98.685 34.56 98.955 ;
     RECT  2.16 99.225 34.56 99.495 ;
     RECT  2.16 99.765 34.56 100.035 ;
     RECT  2.16 100.305 34.56 100.575 ;
     RECT  2.16 100.845 34.56 101.115 ;
     RECT  2.16 101.385 34.56 101.655 ;
     RECT  2.16 101.925 34.56 102.195 ;
     RECT  2.16 102.465 34.56 102.735 ;
     RECT  2.16 103.005 34.56 103.275 ;
     RECT  2.16 103.545 34.56 103.815 ;
     RECT  2.16 104.085 34.56 104.355 ;
     RECT  2.16 104.625 34.56 104.895 ;
     RECT  2.16 105.165 34.56 105.435 ;
     RECT  2.16 105.705 34.56 105.975 ;
     RECT  2.16 106.245 34.56 106.515 ;
     RECT  2.16 106.785 34.56 107.055 ;
     RECT  2.16 107.325 34.56 107.595 ;
     RECT  2.16 107.865 34.56 108.135 ;
     RECT  2.16 108.405 34.56 108.675 ;
     RECT  2.16 108.945 34.56 109.215 ;
     RECT  2.16 109.485 34.56 109.755 ;
     RECT  2.16 110.025 34.56 110.295 ;
     RECT  2.16 110.565 34.56 110.835 ;
     RECT  2.16 111.105 34.56 111.375 ;
     RECT  2.16 111.645 34.56 111.915 ;
     RECT  2.16 112.185 34.56 112.455 ;
     RECT  2.16 112.725 34.56 112.995 ;
     RECT  2.16 113.265 34.56 113.535 ;
     RECT  2.16 113.805 34.56 114.075 ;
     RECT  2.16 114.345 34.56 114.615 ;
     RECT  2.16 114.885 34.56 115.155 ;
     RECT  2.16 115.425 34.56 115.695 ;
     RECT  2.16 115.965 34.56 116.235 ;
     RECT  2.16 116.505 34.56 116.775 ;
     RECT  2.16 117.045 34.56 117.315 ;
     RECT  2.16 117.585 34.56 117.855 ;
     RECT  2.16 118.125 34.56 118.395 ;
     RECT  2.16 118.665 34.56 118.8 ;
    LAYER RVTP ;
     RECT  2.16 2.295 34.56 2.565 ;
     RECT  2.16 2.835 34.56 3.105 ;
     RECT  2.16 3.375 34.56 3.645 ;
     RECT  2.16 3.915 34.56 4.185 ;
     RECT  2.16 4.455 34.56 4.725 ;
     RECT  2.16 4.995 34.56 5.265 ;
     RECT  2.16 5.535 34.56 5.805 ;
     RECT  2.16 6.075 34.56 6.345 ;
     RECT  2.16 6.615 34.56 6.885 ;
     RECT  2.16 7.155 34.56 7.425 ;
     RECT  2.16 7.695 34.56 7.965 ;
     RECT  2.16 8.235 34.56 8.505 ;
     RECT  2.16 8.775 34.56 9.045 ;
     RECT  2.16 9.315 34.56 9.585 ;
     RECT  2.16 9.855 34.56 10.125 ;
     RECT  2.16 10.395 34.56 10.665 ;
     RECT  2.16 10.935 34.56 11.205 ;
     RECT  2.16 11.475 34.56 11.745 ;
     RECT  2.16 12.015 34.56 12.285 ;
     RECT  2.16 12.555 34.56 12.825 ;
     RECT  2.16 13.095 34.56 13.365 ;
     RECT  2.16 13.635 34.56 13.905 ;
     RECT  2.16 14.175 34.56 14.445 ;
     RECT  2.16 14.715 34.56 14.985 ;
     RECT  2.16 15.255 34.56 15.525 ;
     RECT  2.16 15.795 34.56 16.065 ;
     RECT  2.16 16.335 34.56 16.605 ;
     RECT  2.16 16.875 34.56 17.145 ;
     RECT  2.16 17.415 34.56 17.685 ;
     RECT  2.16 17.955 34.56 18.225 ;
     RECT  2.16 18.495 34.56 18.765 ;
     RECT  2.16 19.035 34.56 19.305 ;
     RECT  2.16 19.575 34.56 19.845 ;
     RECT  2.16 20.115 34.56 20.385 ;
     RECT  2.16 20.655 34.56 20.925 ;
     RECT  2.16 21.195 34.56 21.465 ;
     RECT  2.16 21.735 34.56 22.005 ;
     RECT  2.16 22.275 34.56 22.545 ;
     RECT  2.16 22.815 34.56 23.085 ;
     RECT  2.16 23.355 34.56 23.625 ;
     RECT  2.16 23.895 34.56 24.165 ;
     RECT  2.16 24.435 34.56 24.705 ;
     RECT  2.16 24.975 34.56 25.245 ;
     RECT  2.16 25.515 34.56 25.785 ;
     RECT  2.16 26.055 34.56 26.325 ;
     RECT  2.16 26.595 34.56 26.865 ;
     RECT  2.16 27.135 34.56 27.405 ;
     RECT  2.16 27.675 34.56 27.945 ;
     RECT  2.16 28.215 34.56 28.485 ;
     RECT  2.16 28.755 34.56 29.025 ;
     RECT  2.16 29.295 34.56 29.565 ;
     RECT  2.16 29.835 34.56 30.105 ;
     RECT  2.16 30.375 34.56 30.645 ;
     RECT  2.16 30.915 34.56 31.185 ;
     RECT  2.16 31.455 34.56 31.725 ;
     RECT  2.16 31.995 34.56 32.265 ;
     RECT  2.16 32.535 34.56 32.805 ;
     RECT  2.16 33.075 34.56 33.345 ;
     RECT  2.16 33.615 34.56 33.885 ;
     RECT  2.16 34.155 34.56 34.425 ;
     RECT  2.16 34.695 34.56 34.965 ;
     RECT  2.16 35.235 34.56 35.505 ;
     RECT  2.16 35.775 34.56 36.045 ;
     RECT  2.16 36.315 34.56 36.585 ;
     RECT  2.16 36.855 34.56 37.125 ;
     RECT  2.16 37.395 34.56 37.665 ;
     RECT  2.16 37.935 34.56 38.205 ;
     RECT  2.16 38.475 34.56 38.745 ;
     RECT  2.16 39.015 34.56 39.285 ;
     RECT  2.16 39.555 34.56 39.825 ;
     RECT  2.16 40.095 34.56 40.365 ;
     RECT  2.16 40.635 34.56 40.905 ;
     RECT  2.16 41.175 34.56 41.445 ;
     RECT  2.16 41.715 34.56 41.985 ;
     RECT  2.16 42.255 34.56 42.525 ;
     RECT  2.16 42.795 34.56 43.065 ;
     RECT  2.16 43.335 34.56 43.605 ;
     RECT  2.16 43.875 34.56 44.145 ;
     RECT  2.16 44.415 34.56 44.685 ;
     RECT  2.16 44.955 34.56 45.225 ;
     RECT  2.16 45.495 34.56 45.765 ;
     RECT  2.16 46.035 34.56 46.305 ;
     RECT  2.16 46.575 34.56 46.845 ;
     RECT  2.16 47.115 34.56 47.385 ;
     RECT  2.16 47.655 34.56 47.925 ;
     RECT  2.16 48.195 34.56 48.465 ;
     RECT  2.16 48.735 34.56 49.005 ;
     RECT  2.16 49.275 34.56 49.545 ;
     RECT  2.16 49.815 34.56 50.085 ;
     RECT  2.16 50.355 34.56 50.625 ;
     RECT  2.16 50.895 34.56 51.165 ;
     RECT  2.16 51.435 34.56 51.705 ;
     RECT  2.16 51.975 34.56 52.245 ;
     RECT  2.16 52.515 34.56 52.785 ;
     RECT  2.16 53.055 34.56 53.325 ;
     RECT  2.16 53.595 34.56 53.865 ;
     RECT  2.16 54.135 34.56 54.405 ;
     RECT  2.16 54.675 34.56 54.945 ;
     RECT  2.16 55.215 34.56 55.485 ;
     RECT  2.16 55.755 34.56 56.025 ;
     RECT  2.16 56.295 34.56 56.565 ;
     RECT  2.16 56.835 34.56 57.105 ;
     RECT  2.16 57.375 34.56 57.645 ;
     RECT  2.16 57.915 34.56 58.185 ;
     RECT  2.16 58.455 34.56 58.725 ;
     RECT  2.16 58.995 34.56 59.265 ;
     RECT  2.16 59.535 34.56 59.805 ;
     RECT  2.16 60.075 34.56 60.345 ;
     RECT  2.16 60.615 34.56 60.885 ;
     RECT  2.16 61.155 34.56 61.425 ;
     RECT  2.16 61.695 34.56 61.965 ;
     RECT  2.16 62.235 34.56 62.505 ;
     RECT  2.16 62.775 34.56 63.045 ;
     RECT  2.16 63.315 34.56 63.585 ;
     RECT  2.16 63.855 34.56 64.125 ;
     RECT  2.16 64.395 34.56 64.665 ;
     RECT  2.16 64.935 34.56 65.205 ;
     RECT  2.16 65.475 34.56 65.745 ;
     RECT  2.16 66.015 34.56 66.285 ;
     RECT  2.16 66.555 34.56 66.825 ;
     RECT  2.16 67.095 34.56 67.365 ;
     RECT  2.16 67.635 34.56 67.905 ;
     RECT  2.16 68.175 34.56 68.445 ;
     RECT  2.16 68.715 34.56 68.985 ;
     RECT  2.16 69.255 34.56 69.525 ;
     RECT  2.16 69.795 34.56 70.065 ;
     RECT  2.16 70.335 34.56 70.605 ;
     RECT  2.16 70.875 34.56 71.145 ;
     RECT  2.16 71.415 34.56 71.685 ;
     RECT  2.16 71.955 34.56 72.225 ;
     RECT  2.16 72.495 34.56 72.765 ;
     RECT  2.16 73.035 34.56 73.305 ;
     RECT  2.16 73.575 34.56 73.845 ;
     RECT  2.16 74.115 34.56 74.385 ;
     RECT  2.16 74.655 34.56 74.925 ;
     RECT  2.16 75.195 34.56 75.465 ;
     RECT  2.16 75.735 34.56 76.005 ;
     RECT  2.16 76.275 34.56 76.545 ;
     RECT  2.16 76.815 34.56 77.085 ;
     RECT  2.16 77.355 34.56 77.625 ;
     RECT  2.16 77.895 34.56 78.165 ;
     RECT  2.16 78.435 34.56 78.705 ;
     RECT  2.16 78.975 34.56 79.245 ;
     RECT  2.16 79.515 34.56 79.785 ;
     RECT  2.16 80.055 34.56 80.325 ;
     RECT  2.16 80.595 34.56 80.865 ;
     RECT  2.16 81.135 34.56 81.405 ;
     RECT  2.16 81.675 34.56 81.945 ;
     RECT  2.16 82.215 34.56 82.485 ;
     RECT  2.16 82.755 34.56 83.025 ;
     RECT  2.16 83.295 34.56 83.565 ;
     RECT  2.16 83.835 34.56 84.105 ;
     RECT  2.16 84.375 34.56 84.645 ;
     RECT  2.16 84.915 34.56 85.185 ;
     RECT  2.16 85.455 34.56 85.725 ;
     RECT  2.16 85.995 34.56 86.265 ;
     RECT  2.16 86.535 34.56 86.805 ;
     RECT  2.16 87.075 34.56 87.345 ;
     RECT  2.16 87.615 34.56 87.885 ;
     RECT  2.16 88.155 34.56 88.425 ;
     RECT  2.16 88.695 34.56 88.965 ;
     RECT  2.16 89.235 34.56 89.505 ;
     RECT  2.16 89.775 34.56 90.045 ;
     RECT  2.16 90.315 34.56 90.585 ;
     RECT  2.16 90.855 34.56 91.125 ;
     RECT  2.16 91.395 34.56 91.665 ;
     RECT  2.16 91.935 34.56 92.205 ;
     RECT  2.16 92.475 34.56 92.745 ;
     RECT  2.16 93.015 34.56 93.285 ;
     RECT  2.16 93.555 34.56 93.825 ;
     RECT  2.16 94.095 34.56 94.365 ;
     RECT  2.16 94.635 34.56 94.905 ;
     RECT  2.16 95.175 34.56 95.445 ;
     RECT  2.16 95.715 34.56 95.985 ;
     RECT  2.16 96.255 34.56 96.525 ;
     RECT  2.16 96.795 34.56 97.065 ;
     RECT  2.16 97.335 34.56 97.605 ;
     RECT  2.16 97.875 34.56 98.145 ;
     RECT  2.16 98.415 34.56 98.685 ;
     RECT  2.16 98.955 34.56 99.225 ;
     RECT  2.16 99.495 34.56 99.765 ;
     RECT  2.16 100.035 34.56 100.305 ;
     RECT  2.16 100.575 34.56 100.845 ;
     RECT  2.16 101.115 34.56 101.385 ;
     RECT  2.16 101.655 34.56 101.925 ;
     RECT  2.16 102.195 34.56 102.465 ;
     RECT  2.16 102.735 34.56 103.005 ;
     RECT  2.16 103.275 34.56 103.545 ;
     RECT  2.16 103.815 34.56 104.085 ;
     RECT  2.16 104.355 34.56 104.625 ;
     RECT  2.16 104.895 34.56 105.165 ;
     RECT  2.16 105.435 34.56 105.705 ;
     RECT  2.16 105.975 34.56 106.245 ;
     RECT  2.16 106.515 34.56 106.785 ;
     RECT  2.16 107.055 34.56 107.325 ;
     RECT  2.16 107.595 34.56 107.865 ;
     RECT  2.16 108.135 34.56 108.405 ;
     RECT  2.16 108.675 34.56 108.945 ;
     RECT  2.16 109.215 34.56 109.485 ;
     RECT  2.16 109.755 34.56 110.025 ;
     RECT  2.16 110.295 34.56 110.565 ;
     RECT  2.16 110.835 34.56 111.105 ;
     RECT  2.16 111.375 34.56 111.645 ;
     RECT  2.16 111.915 34.56 112.185 ;
     RECT  2.16 112.455 34.56 112.725 ;
     RECT  2.16 112.995 34.56 113.265 ;
     RECT  2.16 113.535 34.56 113.805 ;
     RECT  2.16 114.075 34.56 114.345 ;
     RECT  2.16 114.615 34.56 114.885 ;
     RECT  2.16 115.155 34.56 115.425 ;
     RECT  2.16 115.695 34.56 115.965 ;
     RECT  2.16 116.235 34.56 116.505 ;
     RECT  2.16 116.775 34.56 117.045 ;
     RECT  2.16 117.315 34.56 117.585 ;
     RECT  2.16 117.855 34.56 118.125 ;
     RECT  2.16 118.395 34.56 118.665 ;
    LAYER M1 ;
     RECT  2.16 2.151 34.56 118.809 ;
    LAYER M2 ;
     RECT  0.211 32.472 2.16 32.49 ;
     RECT  0.535 42.606 2.16 42.624 ;
     RECT  0.211 73.512 2.16 73.53 ;
     RECT  0.535 79.218 2.16 79.236 ;
     RECT  0.211 116.172 2.16 116.19 ;
     RECT  18.175 120.798 18.383 120.816 ;
     RECT  2.16 2.151 34.56 118.809 ;
     RECT  34.56 6.624 34.763 14.004 ;
     RECT  34.56 38.826 34.763 105.534 ;
     RECT  34.56 106.29 34.763 115.524 ;
     RECT  34.763 6.624 34.799 11.232 ;
     RECT  34.56 22.446 34.799 38.034 ;
     RECT  34.763 47.196 34.799 68.364 ;
     RECT  34.763 69.264 34.799 105.534 ;
     RECT  34.763 112.896 34.799 115.524 ;
     RECT  34.799 115.128 34.835 115.146 ;
     RECT  34.56 116.946 34.835 117.774 ;
     RECT  34.763 106.29 34.907 112.104 ;
     RECT  34.799 22.626 34.979 32.904 ;
     RECT  34.835 117.486 35.051 117.774 ;
     RECT  34.56 15.156 35.339 16.902 ;
     RECT  34.763 38.826 35.339 46.404 ;
     RECT  34.56 2.736 35.375 5.094 ;
     RECT  34.799 8.136 35.375 8.874 ;
     RECT  34.799 9.756 35.375 10.224 ;
     RECT  34.763 12.33 35.375 14.004 ;
     RECT  35.339 15.336 35.375 16.902 ;
     RECT  34.56 17.856 35.375 21.492 ;
     RECT  34.979 23.904 35.375 32.904 ;
     RECT  34.799 33.66 35.375 38.034 ;
     RECT  35.339 39.096 35.375 46.404 ;
     RECT  34.799 47.196 35.375 68.202 ;
     RECT  34.799 69.264 35.375 103.842 ;
     RECT  34.907 107.766 35.375 112.104 ;
     RECT  34.799 113.04 35.375 113.994 ;
     RECT  35.051 117.666 35.375 117.774 ;
     RECT  34.799 6.624 35.383 6.984 ;
     RECT  35.375 18.396 35.411 21.492 ;
     RECT  35.375 27.45 35.411 32.904 ;
     RECT  35.375 39.096 35.411 43.398 ;
     RECT  35.375 47.196 35.411 52.578 ;
     RECT  35.375 69.264 35.411 73.404 ;
     RECT  35.375 84.996 35.411 90.306 ;
     RECT  35.375 98.118 35.411 101.484 ;
     RECT  35.375 109.836 35.411 111.744 ;
     RECT  35.375 113.04 35.411 113.868 ;
     RECT  35.375 2.736 35.447 5.022 ;
     RECT  35.411 47.196 35.447 50.112 ;
     RECT  35.383 6.471 35.483 6.984 ;
     RECT  35.447 3.888 35.519 5.022 ;
     RECT  35.519 5.004 35.555 5.022 ;
     RECT  35.447 2.736 35.699 2.754 ;
     RECT  35.411 43.236 35.879 43.398 ;
     RECT  35.375 63.018 35.915 66.924 ;
     RECT  35.375 107.91 35.915 109.044 ;
     RECT  35.519 3.888 35.951 4.104 ;
     RECT  35.483 6.966 35.951 6.984 ;
     RECT  35.375 8.676 35.951 8.874 ;
     RECT  35.375 9.864 35.951 10.224 ;
     RECT  34.799 11.016 35.951 11.232 ;
     RECT  35.375 12.33 35.951 12.924 ;
     RECT  35.375 13.986 35.951 14.004 ;
     RECT  35.375 15.426 35.951 16.902 ;
     RECT  35.411 18.972 35.951 21.492 ;
     RECT  34.979 22.626 35.951 22.914 ;
     RECT  35.375 23.904 35.951 26.586 ;
     RECT  35.411 27.45 35.951 29.898 ;
     RECT  35.411 30.888 35.951 32.904 ;
     RECT  35.375 33.66 35.951 37.962 ;
     RECT  35.411 39.096 35.951 42.318 ;
     RECT  35.879 43.38 35.951 43.398 ;
     RECT  35.375 44.154 35.951 46.404 ;
     RECT  35.447 47.196 35.951 48.024 ;
     RECT  35.447 48.978 35.951 50.112 ;
     RECT  35.411 50.904 35.951 52.578 ;
     RECT  35.375 53.568 35.951 54.504 ;
     RECT  35.375 55.53 35.951 58.014 ;
     RECT  35.375 58.77 35.951 62.262 ;
     RECT  35.915 63.054 35.951 66.924 ;
     RECT  35.375 67.716 35.951 68.202 ;
     RECT  35.411 69.264 35.951 72.594 ;
     RECT  35.411 73.386 35.951 73.404 ;
     RECT  35.375 74.466 35.951 75.294 ;
     RECT  35.375 76.086 35.951 84.204 ;
     RECT  35.411 84.996 35.951 88.254 ;
     RECT  35.411 89.046 35.951 90.306 ;
     RECT  35.375 91.944 35.951 93.114 ;
     RECT  35.375 94.878 35.951 97.362 ;
     RECT  35.411 98.118 35.951 99.864 ;
     RECT  35.411 100.89 35.951 101.484 ;
     RECT  35.375 102.708 35.951 103.842 ;
     RECT  34.799 104.706 35.951 105.534 ;
     RECT  34.907 106.29 35.951 106.884 ;
     RECT  35.915 107.946 35.951 109.044 ;
     RECT  35.411 109.836 35.951 109.854 ;
     RECT  35.411 110.646 35.951 111.744 ;
     RECT  35.411 113.04 35.951 113.796 ;
     RECT  35.951 4.086 35.987 4.104 ;
     RECT  35.951 8.676 35.987 8.694 ;
     RECT  35.951 9.936 35.987 9.954 ;
     RECT  35.951 12.906 35.987 12.924 ;
     RECT  35.951 15.804 35.987 16.164 ;
     RECT  35.951 18.972 35.987 19.404 ;
     RECT  35.951 20.16 35.987 21.222 ;
     RECT  35.951 22.86 35.987 22.878 ;
     RECT  35.951 23.976 35.987 24.156 ;
     RECT  35.951 25.182 35.987 25.236 ;
     RECT  35.951 26.568 35.987 26.586 ;
     RECT  35.951 29.34 35.987 29.898 ;
     RECT  35.951 30.888 35.987 30.906 ;
     RECT  35.951 32.004 35.987 32.904 ;
     RECT  35.951 33.66 35.987 34.218 ;
     RECT  35.951 35.478 35.987 35.604 ;
     RECT  35.951 37.134 35.987 37.224 ;
     RECT  35.951 39.096 35.987 39.312 ;
     RECT  35.951 40.104 35.987 40.122 ;
     RECT  35.951 41.256 35.987 41.274 ;
     RECT  35.951 42.066 35.987 42.084 ;
     RECT  35.951 44.154 35.987 44.172 ;
     RECT  35.951 45.306 35.987 46.404 ;
     RECT  35.951 47.466 35.987 47.988 ;
     RECT  35.951 48.978 35.987 48.996 ;
     RECT  35.951 50.094 35.987 50.112 ;
     RECT  35.951 50.904 35.987 52.344 ;
     RECT  35.951 53.946 35.987 53.964 ;
     RECT  35.951 55.998 35.987 57.096 ;
     RECT  35.951 57.996 35.987 58.014 ;
     RECT  35.951 58.77 35.987 59.526 ;
     RECT  35.951 61.704 35.987 62.262 ;
     RECT  35.951 66.906 35.987 66.924 ;
     RECT  35.951 71.46 35.987 71.514 ;
     RECT  35.951 72.468 35.987 72.486 ;
     RECT  35.951 75.006 35.987 75.024 ;
     RECT  35.951 76.59 35.987 76.608 ;
     RECT  35.951 77.436 35.987 77.652 ;
     RECT  35.951 78.444 35.987 78.804 ;
     RECT  35.951 79.56 35.987 79.884 ;
     RECT  35.951 80.676 35.987 80.694 ;
     RECT  35.951 81.684 35.987 81.702 ;
     RECT  35.951 83.304 35.987 83.709 ;
     RECT  35.951 85.464 35.987 86.364 ;
     RECT  35.951 87.318 35.987 87.336 ;
     RECT  35.951 89.28 35.987 90.036 ;
     RECT  35.951 92.484 35.987 93.114 ;
     RECT  35.951 94.986 35.987 95.706 ;
     RECT  35.951 96.876 35.987 96.894 ;
     RECT  35.951 98.118 35.987 98.982 ;
     RECT  35.951 100.89 35.987 100.908 ;
     RECT  35.951 102.708 35.987 103.644 ;
     RECT  35.951 105.408 35.987 105.426 ;
     RECT  35.951 106.866 35.987 106.884 ;
     RECT  35.951 108.216 35.987 108.504 ;
     RECT  35.951 110.646 35.987 110.664 ;
     RECT  35.951 111.456 35.987 111.636 ;
     RECT  35.951 113.544 35.987 113.562 ;
     RECT  35.987 16.146 36.023 16.164 ;
     RECT  35.987 19.386 36.023 19.404 ;
     RECT  35.987 23.976 36.023 23.994 ;
     RECT  35.987 25.182 36.023 25.2 ;
     RECT  35.987 32.274 36.023 32.904 ;
     RECT  35.987 33.66 36.023 33.678 ;
     RECT  35.987 35.586 36.023 35.604 ;
     RECT  35.987 37.134 36.023 37.152 ;
     RECT  35.987 39.294 36.023 39.312 ;
     RECT  35.987 45.846 36.023 46.062 ;
     RECT  35.987 47.736 36.023 47.988 ;
     RECT  35.987 56.574 36.023 56.592 ;
     RECT  35.951 60.66 36.023 60.678 ;
     RECT  35.987 62.244 36.023 62.262 ;
     RECT  35.951 65.016 36.023 66.042 ;
     RECT  35.951 67.95 36.023 68.202 ;
     RECT  35.951 69.264 36.023 69.282 ;
     RECT  35.987 77.436 36.023 77.454 ;
     RECT  35.987 79.56 36.023 79.578 ;
     RECT  35.987 83.691 36.023 83.709 ;
     RECT  35.987 86.346 36.023 86.364 ;
     RECT  35.987 90.018 36.023 90.036 ;
     RECT  35.987 92.754 36.023 93.114 ;
     RECT  35.987 98.586 36.023 98.604 ;
     RECT  35.987 103.248 36.023 103.464 ;
     RECT  35.987 108.486 36.023 108.504 ;
     RECT  35.987 111.456 36.023 111.474 ;
     RECT  36.023 32.274 36.059 32.292 ;
     RECT  36.023 46.044 36.059 46.062 ;
     RECT  36.023 47.97 36.059 47.988 ;
     RECT  35.987 52.326 36.059 52.344 ;
     RECT  35.987 58.806 36.059 58.824 ;
     RECT  36.023 65.556 36.059 65.574 ;
     RECT  36.023 67.95 36.059 67.968 ;
     RECT  35.987 71.496 36.059 71.514 ;
     RECT  35.987 78.642 36.059 78.804 ;
     RECT  36.023 103.248 36.059 103.266 ;
     RECT  36.059 78.642 36.167 78.66 ;
     RECT  35.375 117.666 36.491 117.684 ;
     RECT  35.951 63.666 36.527 63.684 ;
     RECT  36.499 93.258 36.599 93.276 ;
    LAYER M3 ;
     RECT  2.415 2.143 2.505 2.413 ;
     RECT  5.115 2.143 5.205 2.413 ;
     RECT  7.815 2.143 7.905 2.413 ;
     RECT  10.515 2.143 10.605 2.413 ;
     RECT  13.215 2.143 13.305 2.413 ;
     RECT  15.915 2.143 16.005 2.413 ;
     RECT  18.615 2.143 18.705 2.413 ;
     RECT  21.315 2.143 21.405 2.413 ;
     RECT  24.015 2.143 24.105 2.413 ;
     RECT  26.715 2.143 26.805 2.413 ;
     RECT  29.415 2.143 29.505 2.413 ;
     RECT  32.115 2.143 32.205 2.413 ;
     RECT  34.02 2.767 34.038 2.803 ;
     RECT  35.676 2.731 35.694 2.803 ;
     RECT  33.336 2.803 34.038 3.001 ;
     RECT  33.336 3.001 34.29 3.145 ;
     RECT  35.028 2.803 35.694 3.145 ;
     RECT  33.336 3.145 35.694 3.883 ;
     RECT  33.336 3.883 35.946 4.081 ;
     RECT  5.115 2.413 5.397 4.351 ;
     RECT  30.78 4.261 30.798 4.379 ;
     RECT  2.415 2.413 2.697 4.387 ;
     RECT  5.115 4.351 5.526 4.423 ;
     RECT  4.716 4.423 5.526 4.495 ;
     RECT  32.115 2.413 32.397 4.495 ;
     RECT  33.336 4.081 35.982 4.495 ;
     RECT  3.492 4.495 3.51 4.531 ;
     RECT  2.412 4.387 2.697 4.555 ;
     RECT  3.42 4.531 3.654 4.801 ;
     RECT  2.304 4.555 2.697 4.891 ;
     RECT  32.115 4.495 35.982 5.069 ;
     RECT  3.42 4.801 3.798 5.071 ;
     RECT  4.536 4.495 5.526 5.071 ;
     RECT  7.815 2.413 8.097 5.071 ;
     RECT  2.268 4.891 2.697 5.225 ;
     RECT  2.304 5.225 2.697 5.341 ;
     RECT  3.42 5.071 5.526 5.341 ;
     RECT  6.516 5.305 6.534 5.341 ;
     RECT  7.488 5.071 8.097 5.341 ;
     RECT  2.304 5.341 5.598 5.639 ;
     RECT  32.115 5.069 35.946 5.809 ;
     RECT  6.372 5.341 8.097 6.035 ;
     RECT  7.815 6.035 8.097 6.091 ;
     RECT  3.564 5.639 5.598 6.151 ;
     RECT  6.372 6.035 7.002 6.151 ;
     RECT  7.815 6.091 8.226 6.151 ;
     RECT  31.68 5.809 35.946 6.221 ;
     RECT  7.815 6.151 8.37 6.269 ;
     RECT  9.288 6.151 9.306 6.269 ;
     RECT  31.68 6.221 35.478 6.269 ;
     RECT  2.304 5.639 2.697 6.691 ;
     RECT  3.564 6.151 7.002 6.691 ;
     RECT  2.304 6.691 7.002 6.781 ;
     RECT  7.815 6.269 8.097 6.781 ;
     RECT  2.304 6.781 8.097 6.845 ;
     RECT  32.076 6.269 35.478 6.961 ;
     RECT  2.304 6.845 6.246 7.003 ;
     RECT  2.268 7.003 6.246 7.187 ;
     RECT  7.056 6.845 8.097 7.195 ;
     RECT  31.14 7.231 31.23 7.349 ;
     RECT  31.212 7.349 31.23 7.421 ;
     RECT  32.076 6.961 35.946 7.517 ;
     RECT  2.304 7.187 6.246 7.591 ;
     RECT  7.056 7.195 8.406 7.591 ;
     RECT  32.076 7.517 35.406 7.663 ;
     RECT  2.304 7.591 8.406 7.897 ;
     RECT  2.304 7.897 8.946 8.159 ;
     RECT  31.932 7.663 35.406 8.299 ;
     RECT  30.852 8.167 30.87 8.311 ;
     RECT  2.304 8.159 6.138 8.339 ;
     RECT  30.78 8.311 30.87 8.339 ;
     RECT  2.304 8.339 5.886 8.429 ;
     RECT  31.932 8.299 35.946 8.669 ;
     RECT  35.928 8.669 35.946 8.671 ;
     RECT  31.932 8.669 34.794 8.707 ;
     RECT  30.78 8.339 30.798 8.843 ;
     RECT  31.68 8.707 34.794 9.041 ;
     RECT  4.392 8.429 5.886 9.121 ;
     RECT  31.68 9.041 34.254 9.239 ;
     RECT  9.324 9.121 9.414 9.275 ;
     RECT  2.304 8.429 3.474 9.391 ;
     RECT  4.392 9.121 6.03 9.391 ;
     RECT  9.396 9.275 9.414 9.391 ;
     RECT  9.396 9.391 9.486 9.419 ;
     RECT  10.515 2.413 10.797 9.517 ;
     RECT  9.468 9.419 9.486 9.581 ;
     RECT  35.928 8.671 35.982 9.595 ;
     RECT  2.304 9.391 6.03 9.677 ;
     RECT  10.515 9.517 10.818 9.689 ;
     RECT  6.876 8.159 8.097 9.779 ;
     RECT  35.352 9.595 35.982 9.779 ;
     RECT  26.715 2.413 26.997 9.787 ;
     RECT  6.876 9.779 7.074 9.859 ;
     RECT  35.928 9.779 35.982 9.959 ;
     RECT  30.78 9.823 30.798 10.021 ;
     RECT  31.824 9.239 34.254 10.049 ;
     RECT  31.932 10.049 34.254 10.075 ;
     RECT  26.715 9.787 27.054 10.085 ;
     RECT  7.815 9.779 8.097 10.363 ;
     RECT  2.304 9.677 5.922 10.435 ;
     RECT  6.804 9.859 7.074 10.493 ;
     RECT  31.932 10.075 34.794 10.589 ;
     RECT  7.815 10.363 8.622 10.661 ;
     RECT  0.216 10.555 0.234 10.685 ;
     RECT  6.804 10.493 6.858 10.741 ;
     RECT  7.815 10.661 8.406 10.931 ;
     RECT  32.04 10.589 34.794 11.083 ;
     RECT  35.928 9.959 35.946 11.083 ;
     RECT  2.304 10.435 5.994 11.101 ;
     RECT  6.732 10.741 6.858 11.101 ;
     RECT  9.612 11.011 9.63 11.129 ;
     RECT  32.04 11.083 35.946 11.129 ;
     RECT  30.78 10.021 30.87 11.201 ;
     RECT  2.304 11.101 6.858 11.371 ;
     RECT  7.815 10.931 8.097 11.371 ;
     RECT  32.04 11.129 34.758 11.371 ;
     RECT  0.252 11.179 0.27 11.405 ;
     RECT  30.852 11.201 30.87 11.479 ;
     RECT  31.968 11.371 34.758 11.479 ;
     RECT  10.515 9.689 10.797 11.551 ;
     RECT  30.852 11.479 34.758 11.705 ;
     RECT  30.852 11.705 30.87 11.849 ;
     RECT  2.304 11.371 8.097 11.851 ;
     RECT  31.932 11.705 34.758 12.187 ;
     RECT  9.756 11.551 10.797 12.209 ;
     RECT  10.515 12.209 10.797 12.217 ;
     RECT  29.415 2.413 29.697 12.217 ;
     RECT  2.268 11.851 8.097 12.245 ;
     RECT  10.515 12.217 10.854 12.289 ;
     RECT  35.928 11.129 35.946 12.379 ;
     RECT  10.515 12.289 10.926 12.389 ;
     RECT  2.304 12.245 8.097 12.451 ;
     RECT  29.415 12.217 30.654 12.479 ;
     RECT  0.252 12.379 0.27 12.509 ;
     RECT  31.932 12.187 34.794 12.595 ;
     RECT  31.536 12.595 34.794 12.631 ;
     RECT  2.304 12.451 8.694 12.721 ;
     RECT  31.176 12.631 34.794 12.749 ;
     RECT  2.304 12.721 8.802 12.929 ;
     RECT  35.928 12.379 35.982 12.929 ;
     RECT  31.968 12.749 34.794 12.991 ;
     RECT  35.928 12.929 35.946 12.991 ;
     RECT  2.304 12.929 8.766 13.019 ;
     RECT  2.304 13.019 8.622 13.091 ;
     RECT  31.968 12.991 35.946 13.469 ;
     RECT  31.968 13.469 34.29 13.531 ;
     RECT  2.304 13.091 8.514 13.559 ;
     RECT  6.84 13.559 8.37 13.613 ;
     RECT  35.352 13.469 35.946 13.853 ;
     RECT  35.928 13.853 35.946 14.009 ;
     RECT  31.932 13.531 34.29 14.521 ;
     RECT  2.304 13.559 6.03 14.639 ;
     RECT  2.304 14.639 2.862 14.909 ;
     RECT  3.6 14.639 6.03 14.909 ;
     RECT  35.316 14.635 35.334 14.971 ;
     RECT  3.672 14.909 6.03 15.179 ;
     RECT  30.78 14.071 30.798 15.287 ;
     RECT  35.316 14.971 35.946 15.307 ;
     RECT  3.96 15.179 6.03 15.331 ;
     RECT  6.84 13.613 8.097 15.331 ;
     RECT  35.316 15.307 35.982 15.359 ;
     RECT  3.96 15.331 8.097 15.389 ;
     RECT  31.932 14.521 34.362 15.421 ;
     RECT  6.912 15.389 8.097 15.449 ;
     RECT  31.932 15.421 34.434 15.451 ;
     RECT  31.932 15.451 34.794 15.457 ;
     RECT  7.815 15.449 8.097 15.691 ;
     RECT  2.304 14.909 2.697 15.787 ;
     RECT  35.892 15.359 35.982 15.787 ;
     RECT  2.304 15.787 2.754 15.835 ;
     RECT  31.752 15.457 34.794 15.835 ;
     RECT  7.815 15.691 8.37 15.989 ;
     RECT  31.68 15.835 34.794 15.989 ;
     RECT  30.852 16.033 30.87 16.141 ;
     RECT  35.892 15.787 36.018 16.169 ;
     RECT  6.912 15.449 6.93 16.219 ;
     RECT  7.815 15.989 8.262 16.259 ;
     RECT  32.04 15.989 34.794 16.267 ;
     RECT  35.892 16.169 35.946 16.267 ;
     RECT  2.304 15.835 3.006 16.315 ;
     RECT  32.04 16.267 35.946 16.367 ;
     RECT  3.96 15.389 5.994 16.405 ;
     RECT  3.924 16.405 5.994 16.411 ;
     RECT  6.912 16.219 6.966 16.411 ;
     RECT  0.252 15.835 0.27 16.445 ;
     RECT  9.072 16.411 9.09 16.501 ;
     RECT  9.072 16.501 9.162 16.529 ;
     RECT  2.304 16.315 3.114 16.681 ;
     RECT  3.852 16.411 6.966 16.681 ;
     RECT  2.304 16.681 6.966 16.747 ;
     RECT  2.268 16.747 6.966 16.835 ;
     RECT  35.352 16.367 35.946 16.907 ;
     RECT  2.268 16.835 3.042 16.943 ;
     RECT  3.816 16.835 6.966 16.951 ;
     RECT  7.815 16.259 8.154 17.083 ;
     RECT  3.816 16.951 7.038 17.113 ;
     RECT  7.815 17.083 8.19 17.113 ;
     RECT  9.108 16.529 9.162 17.221 ;
     RECT  32.04 16.367 34.362 17.339 ;
     RECT  32.04 17.339 34.326 17.383 ;
     RECT  30.78 16.141 30.87 17.447 ;
     RECT  3.816 17.113 8.19 17.491 ;
     RECT  31.608 17.383 34.326 17.491 ;
     RECT  2.304 16.943 3.042 17.608 ;
     RECT  3.816 17.491 8.262 17.609 ;
     RECT  9.108 17.221 9.198 17.609 ;
     RECT  31.14 17.491 34.326 17.609 ;
     RECT  10.515 12.389 10.797 17.761 ;
     RECT  35.352 16.907 35.406 18.077 ;
     RECT  2.304 17.608 3.078 18.193 ;
     RECT  3.816 17.609 6.246 18.193 ;
     RECT  7.02 17.609 8.262 18.301 ;
     RECT  35.388 18.077 35.406 18.379 ;
     RECT  2.304 18.193 6.246 18.391 ;
     RECT  7.02 18.301 8.55 18.391 ;
     RECT  2.304 18.391 8.55 18.491 ;
     RECT  10.515 17.761 10.818 18.491 ;
     RECT  35.388 18.379 35.91 18.523 ;
     RECT  30.852 18.463 30.87 18.535 ;
     RECT  31.968 17.609 34.326 18.571 ;
     RECT  2.304 18.491 8.406 18.689 ;
     RECT  9.144 18.571 9.162 18.689 ;
     RECT  35.388 18.523 35.946 18.715 ;
     RECT  2.304 18.689 8.097 18.761 ;
     RECT  30.78 18.535 30.87 18.797 ;
     RECT  35.388 18.715 35.982 18.859 ;
     RECT  3.888 18.761 8.097 18.959 ;
     RECT  31.968 18.571 34.362 18.967 ;
     RECT  35.352 18.859 35.982 18.967 ;
     RECT  31.968 18.967 35.982 18.994 ;
     RECT  2.304 18.761 3.078 18.995 ;
     RECT  4.032 18.959 8.097 18.995 ;
     RECT  31.968 18.994 36.018 19.103 ;
     RECT  30.816 18.797 30.87 19.111 ;
     RECT  31.968 19.103 34.47 19.111 ;
     RECT  30.816 19.111 34.47 19.229 ;
     RECT  0.252 19.195 0.27 19.325 ;
     RECT  31.68 19.229 34.47 19.373 ;
     RECT  35.352 19.103 36.018 19.409 ;
     RECT  4.176 18.995 8.097 19.499 ;
     RECT  30.816 19.229 30.834 19.543 ;
     RECT  4.176 19.499 6.102 19.777 ;
     RECT  4.104 19.777 6.102 19.849 ;
     RECT  30.78 19.543 30.834 19.949 ;
     RECT  31.68 19.373 34.218 20.039 ;
     RECT  2.304 18.995 2.97 20.047 ;
     RECT  3.996 19.849 6.102 20.047 ;
     RECT  31.68 20.039 33.75 20.083 ;
     RECT  0.216 20.395 0.234 20.525 ;
     RECT  2.304 20.047 6.102 20.551 ;
     RECT  6.84 19.499 8.097 20.551 ;
     RECT  35.352 19.409 35.982 20.669 ;
     RECT  31.356 20.083 33.75 20.893 ;
     RECT  30.96 20.893 33.75 20.929 ;
     RECT  2.304 20.551 8.097 21.029 ;
     RECT  30.96 20.929 34.074 21.163 ;
     RECT  35.928 20.669 35.982 21.227 ;
     RECT  30.78 21.163 34.074 21.299 ;
     RECT  30.816 21.299 34.074 21.307 ;
     RECT  2.304 21.029 7.002 21.389 ;
     RECT  30.816 21.307 34.218 21.389 ;
     RECT  32.04 21.389 34.218 21.433 ;
     RECT  30.816 21.389 30.834 21.497 ;
     RECT  7.815 21.029 8.097 21.505 ;
     RECT  7.815 21.505 8.226 21.541 ;
     RECT  7.815 21.541 8.262 21.731 ;
     RECT  32.04 21.433 34.254 21.787 ;
     RECT  6.804 21.389 7.002 22.081 ;
     RECT  7.815 21.731 8.097 22.081 ;
     RECT  6.804 22.081 8.097 22.199 ;
     RECT  2.304 21.389 6.03 22.207 ;
     RECT  6.804 22.199 6.822 22.207 ;
     RECT  32.04 21.787 34.794 22.267 ;
     RECT  2.304 22.207 6.822 22.469 ;
     RECT  2.304 22.469 6.714 22.603 ;
     RECT  35.928 21.227 35.946 22.603 ;
     RECT  32.04 22.267 34.974 22.621 ;
     RECT  2.268 22.603 6.714 22.775 ;
     RECT  30.852 22.585 30.87 22.775 ;
     RECT  35.928 22.603 35.982 22.882 ;
     RECT  31.932 22.621 34.974 23.053 ;
     RECT  2.304 22.775 6.714 23.251 ;
     RECT  31.896 23.053 34.974 23.315 ;
     RECT  9.072 23.251 9.09 23.323 ;
     RECT  31.932 23.315 34.974 23.351 ;
     RECT  9 23.323 9.09 23.521 ;
     RECT  30.78 22.981 30.798 23.557 ;
     RECT  8.928 23.521 9.09 23.621 ;
     RECT  30.78 23.557 30.87 23.657 ;
     RECT  35.928 22.882 36.018 23.707 ;
     RECT  31.932 23.351 34.794 23.729 ;
     RECT  2.304 23.251 6.858 23.803 ;
     RECT  7.815 22.199 8.097 23.803 ;
     RECT  2.304 23.803 8.097 23.855 ;
     RECT  7.815 23.855 8.097 23.971 ;
     RECT  10.515 18.491 10.797 24.133 ;
     RECT  21.315 2.413 21.597 24.133 ;
     RECT  9.504 24.061 9.522 24.161 ;
     RECT  31.932 23.729 34.758 24.205 ;
     RECT  10.515 24.133 10.926 24.233 ;
     RECT  7.815 23.971 8.226 24.503 ;
     RECT  30.78 23.657 30.798 24.511 ;
     RECT  21.096 24.133 21.597 24.539 ;
     RECT  31.608 24.205 34.758 24.629 ;
     RECT  2.304 23.855 6.858 24.665 ;
     RECT  3.636 24.665 6.858 24.709 ;
     RECT  30.78 24.511 30.87 24.809 ;
     RECT  31.824 24.629 34.758 25.003 ;
     RECT  3.636 24.709 6.966 25.079 ;
     RECT  10.515 24.233 10.797 25.177 ;
     RECT  31.824 25.003 34.794 25.195 ;
     RECT  35.892 23.707 36.018 25.195 ;
     RECT  31.824 25.195 36.018 25.205 ;
     RECT  10.515 25.177 10.818 25.349 ;
     RECT  2.304 24.665 2.862 25.435 ;
     RECT  3.636 25.079 5.598 25.435 ;
     RECT  6.948 25.079 6.966 25.435 ;
     RECT  7.815 24.503 8.097 25.435 ;
     RECT  31.824 25.205 35.982 25.439 ;
     RECT  30.852 24.809 30.87 25.447 ;
     RECT  0.216 25.339 0.234 25.469 ;
     RECT  6.948 25.435 8.097 25.475 ;
     RECT  7.815 25.475 8.097 25.483 ;
     RECT  30.852 25.447 30.906 25.619 ;
     RECT  2.304 25.435 5.598 25.861 ;
     RECT  6.948 25.475 6.966 25.861 ;
     RECT  31.896 25.439 34.794 25.979 ;
     RECT  30.852 25.619 30.87 26.221 ;
     RECT  9.324 26.131 9.342 26.249 ;
     RECT  32.076 25.979 34.794 26.249 ;
     RECT  10.515 25.349 10.797 26.257 ;
     RECT  2.304 25.861 5.706 26.285 ;
     RECT  6.732 25.861 6.966 26.329 ;
     RECT  7.815 25.483 8.37 26.329 ;
     RECT  10.515 26.257 10.926 26.393 ;
     RECT  30.78 26.221 30.87 26.429 ;
     RECT  32.115 26.249 34.794 26.491 ;
     RECT  35.928 25.439 35.982 26.491 ;
     RECT  6.3 26.329 8.37 26.519 ;
     RECT  2.304 26.285 5.397 26.555 ;
     RECT  0.252 26.059 0.27 26.621 ;
     RECT  30.852 26.429 30.87 26.627 ;
     RECT  7.815 26.519 8.37 26.635 ;
     RECT  7.815 26.635 8.658 26.789 ;
     RECT  32.115 26.491 35.982 27.005 ;
     RECT  32.115 27.005 35.946 27.239 ;
     RECT  3.96 26.555 5.397 27.301 ;
     RECT  3.96 27.301 5.562 27.481 ;
     RECT  6.372 26.519 6.966 27.481 ;
     RECT  2.304 26.555 2.934 27.607 ;
     RECT  3.78 27.481 5.562 27.607 ;
     RECT  6.3 27.481 6.966 27.643 ;
     RECT  7.815 26.789 8.262 27.643 ;
     RECT  30.852 27.643 30.87 27.743 ;
     RECT  32.115 27.239 34.326 27.751 ;
     RECT  6.3 27.643 8.262 27.877 ;
     RECT  32.076 27.751 34.326 27.905 ;
     RECT  2.304 27.607 5.562 27.913 ;
     RECT  6.3 27.877 8.586 27.913 ;
     RECT  32.115 27.905 34.326 28.219 ;
     RECT  35.352 27.239 35.946 28.219 ;
     RECT  2.304 27.913 8.586 28.409 ;
     RECT  32.115 28.219 35.946 28.747 ;
     RECT  9.072 28.831 9.09 28.949 ;
     RECT  32.115 28.747 35.982 29.065 ;
     RECT  32.076 29.065 35.982 29.227 ;
     RECT  30.78 28.687 30.798 29.362 ;
     RECT  30.78 29.362 30.834 29.363 ;
     RECT  31.644 29.227 35.982 29.453 ;
     RECT  0.252 29.419 0.27 29.549 ;
     RECT  30.816 29.363 30.834 29.597 ;
     RECT  2.304 28.409 8.334 29.759 ;
     RECT  31.644 29.453 34.83 29.759 ;
     RECT  4.68 29.759 8.334 29.795 ;
     RECT  35.928 29.453 35.982 29.903 ;
     RECT  4.788 29.795 8.334 29.911 ;
     RECT  4.788 29.911 8.55 30.209 ;
     RECT  2.304 29.759 3.654 30.235 ;
     RECT  31.716 29.759 34.83 30.299 ;
     RECT  4.788 30.209 8.097 30.371 ;
     RECT  32.004 30.299 34.83 30.379 ;
     RECT  35.928 29.903 35.946 30.379 ;
     RECT  2.268 30.235 3.654 30.407 ;
     RECT  30.888 30.343 30.906 30.451 ;
     RECT  30.852 30.451 30.906 30.452 ;
     RECT  9.36 30.181 9.378 30.569 ;
     RECT  30.852 30.452 30.87 30.641 ;
     RECT  32.004 30.379 35.946 30.715 ;
     RECT  4.788 30.371 6.066 30.721 ;
     RECT  0.216 30.619 0.234 30.749 ;
     RECT  2.304 30.407 3.654 30.811 ;
     RECT  4.5 30.721 6.066 30.811 ;
     RECT  2.304 30.811 6.066 30.875 ;
     RECT  32.004 30.715 35.982 30.911 ;
     RECT  32.004 30.911 35.946 31.081 ;
     RECT  29.415 12.479 29.697 31.117 ;
     RECT  30.78 30.991 30.798 31.117 ;
     RECT  6.84 30.371 8.097 31.181 ;
     RECT  31.896 31.081 35.946 31.217 ;
     RECT  29.415 31.117 30.798 31.289 ;
     RECT  2.304 30.875 2.754 31.339 ;
     RECT  2.268 31.339 2.754 31.523 ;
     RECT  3.492 30.875 6.066 31.531 ;
     RECT  3.492 31.531 6.21 31.559 ;
     RECT  2.304 31.523 2.754 31.621 ;
     RECT  3.852 31.559 6.21 31.649 ;
     RECT  31.896 31.217 34.794 31.765 ;
     RECT  35.928 31.217 35.946 31.819 ;
     RECT  29.415 31.289 30.222 31.919 ;
     RECT  31.572 31.765 34.794 31.919 ;
     RECT  3.96 31.649 6.21 31.991 ;
     RECT  31.824 31.919 34.794 32.045 ;
     RECT  6.984 31.181 8.097 32.233 ;
     RECT  35.928 31.819 35.982 32.269 ;
     RECT  6.84 32.233 8.097 32.299 ;
     RECT  6.84 32.299 8.406 32.339 ;
     RECT  2.304 31.621 3.042 32.341 ;
     RECT  9.504 32.305 9.522 32.341 ;
     RECT  10.515 26.393 10.797 32.341 ;
     RECT  9.432 32.341 9.522 32.459 ;
     RECT  3.96 31.991 6.066 32.477 ;
     RECT  10.515 32.341 10.818 32.495 ;
     RECT  0.216 32.251 0.234 32.525 ;
     RECT  35.928 32.269 36.054 32.525 ;
     RECT  2.304 32.341 3.078 32.575 ;
     RECT  2.304 32.575 3.222 32.611 ;
     RECT  3.96 32.477 5.886 32.611 ;
     RECT  6.84 32.339 8.097 32.729 ;
     RECT  9.432 32.459 9.45 32.729 ;
     RECT  30.78 32.773 30.798 32.873 ;
     RECT  2.304 32.611 5.886 32.881 ;
     RECT  31.824 32.045 34.29 32.965 ;
     RECT  6.948 32.729 8.097 32.999 ;
     RECT  2.268 32.881 5.886 33.005 ;
     RECT  31.824 32.965 34.794 33.005 ;
     RECT  2.304 33.005 5.886 33.149 ;
     RECT  31.824 33.005 34.254 33.385 ;
     RECT  3.456 33.149 5.886 33.539 ;
     RECT  7.02 32.999 8.097 33.595 ;
     RECT  30.852 33.313 30.87 33.611 ;
     RECT  35.928 32.525 36.018 33.683 ;
     RECT  31.608 33.385 34.254 33.691 ;
     RECT  7.02 33.595 8.262 33.719 ;
     RECT  30.924 33.691 34.254 33.787 ;
     RECT  30.924 33.787 34.794 33.809 ;
     RECT  7.488 33.719 8.262 33.925 ;
     RECT  2.304 33.149 2.697 34.087 ;
     RECT  3.456 33.539 5.397 34.087 ;
     RECT  31.716 33.809 34.794 34.267 ;
     RECT  35.928 33.683 35.982 34.267 ;
     RECT  31.716 34.267 35.982 34.349 ;
     RECT  35.352 34.349 35.982 34.457 ;
     RECT  2.304 34.087 5.397 34.459 ;
     RECT  6.3 33.889 6.714 34.459 ;
     RECT  7.488 33.925 8.442 34.459 ;
     RECT  35.856 34.457 35.982 34.459 ;
     RECT  2.304 34.459 6.714 34.501 ;
     RECT  7.488 34.459 8.586 34.501 ;
     RECT  10.515 32.495 10.797 34.501 ;
     RECT  31.716 34.349 34.254 34.627 ;
     RECT  35.856 34.459 36.018 34.651 ;
     RECT  31.428 34.627 34.254 34.663 ;
     RECT  35.856 34.651 36.126 34.781 ;
     RECT  2.304 34.501 8.586 35.041 ;
     RECT  9.792 34.501 10.797 35.041 ;
     RECT  2.304 35.041 10.797 35.159 ;
     RECT  30.78 34.663 34.254 35.159 ;
     RECT  30.78 35.159 30.906 35.339 ;
     RECT  10.515 35.159 10.797 35.401 ;
     RECT  31.896 35.159 34.254 35.401 ;
     RECT  31.896 35.401 34.434 35.419 ;
     RECT  2.304 35.159 8.91 35.429 ;
     RECT  2.304 35.429 6.786 35.465 ;
     RECT  10.515 35.401 10.89 35.501 ;
     RECT  2.304 35.465 2.718 35.563 ;
     RECT  31.896 35.419 34.794 35.563 ;
     RECT  10.515 35.501 10.818 35.573 ;
     RECT  9.684 35.159 9.774 35.609 ;
     RECT  35.856 34.781 36.018 35.609 ;
     RECT  9.684 35.609 9.702 35.699 ;
     RECT  2.268 35.563 2.718 35.735 ;
     RECT  31.896 35.563 34.83 35.735 ;
     RECT  31.968 35.735 34.83 35.771 ;
     RECT  2.304 35.735 2.718 35.807 ;
     RECT  30.852 35.339 30.906 35.807 ;
     RECT  30.888 35.807 30.906 35.843 ;
     RECT  7.815 35.429 8.91 35.879 ;
     RECT  32.04 35.771 34.83 35.899 ;
     RECT  35.856 35.609 35.946 35.899 ;
     RECT  3.672 35.465 6.786 36.247 ;
     RECT  3.672 36.247 6.858 36.331 ;
     RECT  7.815 35.879 8.514 36.331 ;
     RECT  32.04 35.899 35.946 36.419 ;
     RECT  3.672 36.331 8.514 36.545 ;
     RECT  2.304 35.807 2.697 36.625 ;
     RECT  3.672 36.545 8.097 36.625 ;
     RECT  32.04 36.419 34.398 36.625 ;
     RECT  30.78 36.625 30.798 36.661 ;
     RECT  31.572 36.625 34.398 36.661 ;
     RECT  2.304 36.625 8.097 36.689 ;
     RECT  2.304 36.689 6.246 36.715 ;
     RECT  9 36.625 9.09 36.779 ;
     RECT  30.78 36.661 34.398 36.779 ;
     RECT  7.38 36.689 8.097 37.049 ;
     RECT  2.268 36.715 6.246 37.085 ;
     RECT  35.352 36.419 35.946 37.129 ;
     RECT  10.515 35.573 10.797 37.201 ;
     RECT  32.004 36.779 34.398 37.201 ;
     RECT  35.352 37.129 36.018 37.201 ;
     RECT  10.515 37.201 10.818 37.319 ;
     RECT  30.78 36.779 30.942 37.319 ;
     RECT  30.78 37.319 30.87 37.391 ;
     RECT  2.268 37.085 2.697 37.427 ;
     RECT  30.816 37.391 30.834 37.463 ;
     RECT  7.452 37.049 8.097 37.499 ;
     RECT  32.004 37.201 36.018 37.499 ;
     RECT  32.004 37.499 34.254 37.669 ;
     RECT  35.352 37.499 36.018 37.709 ;
     RECT  2.304 37.427 2.697 38.011 ;
     RECT  3.42 37.085 6.246 38.011 ;
     RECT  2.304 38.011 6.642 38.129 ;
     RECT  31.788 37.669 34.254 38.129 ;
     RECT  8.928 37.597 8.946 38.173 ;
     RECT  3.96 38.129 6.642 38.281 ;
     RECT  7.815 37.499 8.097 38.281 ;
     RECT  8.928 38.173 9.054 38.281 ;
     RECT  10.515 37.319 10.797 38.281 ;
     RECT  3.96 38.281 6.714 38.371 ;
     RECT  2.304 38.129 3.222 38.399 ;
     RECT  7.815 38.281 9.054 38.399 ;
     RECT  3.96 38.371 6.822 38.443 ;
     RECT  7.815 38.399 8.298 38.443 ;
     RECT  10.515 38.281 10.818 38.471 ;
     RECT  9.036 38.399 9.054 38.579 ;
     RECT  3.96 38.443 8.298 38.621 ;
     RECT  35.352 37.709 35.982 38.635 ;
     RECT  2.304 38.399 2.97 38.705 ;
     RECT  31.824 38.129 34.254 38.749 ;
     RECT  31.824 38.749 34.398 38.765 ;
     RECT  31.932 38.765 34.398 38.849 ;
     RECT  35.316 38.635 35.982 38.849 ;
     RECT  35.892 38.849 35.982 38.971 ;
     RECT  30.78 38.371 30.798 39.091 ;
     RECT  32.115 38.849 34.398 39.163 ;
     RECT  30.78 39.091 30.87 39.281 ;
     RECT  35.892 38.971 36.018 39.317 ;
     RECT  2.304 38.705 2.898 39.451 ;
     RECT  7.056 38.621 8.298 39.487 ;
     RECT  7.056 39.487 8.442 39.595 ;
     RECT  32.115 39.163 34.794 39.595 ;
     RECT  3.96 38.621 6.102 39.631 ;
     RECT  6.948 39.595 8.442 39.631 ;
     RECT  31.932 39.595 34.794 39.659 ;
     RECT  2.268 39.451 2.898 39.721 ;
     RECT  3.96 39.631 8.442 39.721 ;
     RECT  2.268 39.721 8.442 39.785 ;
     RECT  2.268 39.785 2.697 39.857 ;
     RECT  35.892 39.317 35.982 39.931 ;
     RECT  31.932 39.659 34.29 39.991 ;
     RECT  35.352 39.931 35.982 40.127 ;
     RECT  3.42 39.785 8.442 40.199 ;
     RECT  31.716 39.991 34.29 40.297 ;
     RECT  3.42 40.199 8.097 40.445 ;
     RECT  7.452 40.445 8.097 40.469 ;
     RECT  30.78 39.281 30.798 40.469 ;
     RECT  35.352 40.127 35.946 40.637 ;
     RECT  2.304 39.857 2.697 40.639 ;
     RECT  3.42 40.445 6.642 40.639 ;
     RECT  8.928 40.441 8.946 40.739 ;
     RECT  35.928 40.637 35.946 40.939 ;
     RECT  2.304 40.639 6.642 40.973 ;
     RECT  31.68 40.297 34.29 40.981 ;
     RECT  31.68 40.981 34.362 41.071 ;
     RECT  30.852 41.143 30.87 41.243 ;
     RECT  2.304 40.973 2.97 41.441 ;
     RECT  3.852 40.973 6.642 41.521 ;
     RECT  7.632 40.469 8.097 41.521 ;
     RECT  13.215 2.413 13.497 41.611 ;
     RECT  21.315 24.539 21.597 41.611 ;
     RECT  26.715 10.085 26.997 41.611 ;
     RECT  13.104 41.611 13.497 41.648 ;
     RECT  21.204 41.611 21.597 41.648 ;
     RECT  3.852 41.521 8.097 41.683 ;
     RECT  31.68 41.071 34.794 41.707 ;
     RECT  14.832 41.611 14.85 41.741 ;
     RECT  26.676 41.611 26.997 41.741 ;
     RECT  3.852 41.683 8.37 41.747 ;
     RECT  31.284 41.707 34.794 41.899 ;
     RECT  35.928 40.939 35.982 41.899 ;
     RECT  31.284 41.899 35.982 41.909 ;
     RECT  2.34 41.441 2.97 41.947 ;
     RECT  0.252 41.467 0.27 42.077 ;
     RECT  31.896 41.909 35.982 42.089 ;
     RECT  6.12 41.747 8.37 42.179 ;
     RECT  2.34 41.947 3.006 42.215 ;
     RECT  2.34 42.215 2.754 42.235 ;
     RECT  7.815 42.179 8.37 42.259 ;
     RECT  10.515 38.471 10.797 42.259 ;
     RECT  31.896 42.089 35.946 42.323 ;
     RECT  3.852 41.747 5.397 42.331 ;
     RECT  7.815 42.259 8.658 42.359 ;
     RECT  7.815 42.359 8.586 42.449 ;
     RECT  10.515 42.259 10.854 42.449 ;
     RECT  3.78 42.331 5.397 42.601 ;
     RECT  3.564 42.601 5.397 42.811 ;
     RECT  6.12 42.179 6.966 42.811 ;
     RECT  0.54 42.601 0.558 42.893 ;
     RECT  3.564 42.811 6.966 42.955 ;
     RECT  31.896 42.323 35.874 42.997 ;
     RECT  31.356 42.997 35.874 43.051 ;
     RECT  7.815 42.449 8.478 43.099 ;
     RECT  2.304 42.235 2.754 43.141 ;
     RECT  3.492 42.955 6.966 43.141 ;
     RECT  7.704 43.099 8.478 43.141 ;
     RECT  10.515 42.449 10.797 43.231 ;
     RECT  2.304 43.141 8.478 43.403 ;
     RECT  7.416 43.403 8.478 43.411 ;
     RECT  31.356 43.051 35.946 43.439 ;
     RECT  7.416 43.411 8.586 43.529 ;
     RECT  31.356 43.439 34.758 43.537 ;
     RECT  30.78 43.537 34.758 43.637 ;
     RECT  31.356 43.637 34.758 43.709 ;
     RECT  10.515 43.231 10.818 43.799 ;
     RECT  2.304 43.403 6.426 43.835 ;
     RECT  0.252 43.675 0.27 43.853 ;
     RECT  35.928 43.439 35.946 44.011 ;
     RECT  4.32 43.835 6.426 44.347 ;
     RECT  31.932 43.709 34.758 44.347 ;
     RECT  35.928 44.011 35.982 44.347 ;
     RECT  31.932 44.347 35.982 44.411 ;
     RECT  4.32 44.347 6.462 44.483 ;
     RECT  9.144 44.221 9.162 44.491 ;
     RECT  10.515 43.799 10.797 44.491 ;
     RECT  9.144 44.491 10.797 44.609 ;
     RECT  10.515 44.609 10.797 44.617 ;
     RECT  10.515 44.617 10.818 44.717 ;
     RECT  6.192 44.483 6.462 44.725 ;
     RECT  7.416 43.529 8.262 44.725 ;
     RECT  2.304 43.835 3.546 44.761 ;
     RECT  4.32 44.483 5.454 44.761 ;
     RECT  6.192 44.725 8.262 44.761 ;
     RECT  32.115 44.411 35.982 44.879 ;
     RECT  2.304 44.761 5.454 44.951 ;
     RECT  6.192 44.761 8.334 45.059 ;
     RECT  35.928 44.879 35.982 45.307 ;
     RECT  32.115 44.879 34.794 45.419 ;
     RECT  3.996 44.951 5.454 45.451 ;
     RECT  6.192 45.059 8.097 45.451 ;
     RECT  30.78 45.121 30.798 45.463 ;
     RECT  2.304 44.951 3.114 45.536 ;
     RECT  3.996 45.451 8.097 45.581 ;
     RECT  3.996 45.581 5.397 45.691 ;
     RECT  6.192 45.581 8.097 45.725 ;
     RECT  35.928 45.307 36.018 45.787 ;
     RECT  32.115 45.419 34.29 45.805 ;
     RECT  6.336 45.725 8.097 46.003 ;
     RECT  30.78 45.463 30.834 46.003 ;
     RECT  32.004 45.805 34.29 46.031 ;
     RECT  35.928 45.787 36.054 46.067 ;
     RECT  30.78 46.003 30.87 46.103 ;
     RECT  6.336 46.003 8.55 46.229 ;
     RECT  3.924 45.691 5.397 46.265 ;
     RECT  32.04 46.031 34.29 46.265 ;
     RECT  3.924 46.265 4.05 46.381 ;
     RECT  2.304 45.536 2.754 46.459 ;
     RECT  2.268 46.459 2.754 46.471 ;
     RECT  32.115 46.265 34.29 46.579 ;
     RECT  2.268 46.471 2.934 46.603 ;
     RECT  4.788 46.265 5.397 46.651 ;
     RECT  2.268 46.603 3.006 46.741 ;
     RECT  3.816 46.381 4.05 46.741 ;
     RECT  4.788 46.651 5.454 46.741 ;
     RECT  6.336 46.229 6.642 46.741 ;
     RECT  30.78 46.103 30.834 46.921 ;
     RECT  10.515 44.717 10.797 47.011 ;
     RECT  9.54 46.921 9.558 47.039 ;
     RECT  2.268 46.741 4.05 47.083 ;
     RECT  4.788 46.741 6.642 47.083 ;
     RECT  35.928 46.067 35.982 47.083 ;
     RECT  10.515 47.011 10.818 47.147 ;
     RECT  2.268 47.083 6.642 47.191 ;
     RECT  7.596 46.229 8.097 47.191 ;
     RECT  2.268 47.191 6.858 47.227 ;
     RECT  7.596 47.191 8.19 47.227 ;
     RECT  32.115 46.579 34.758 47.275 ;
     RECT  35.928 47.083 36.018 47.275 ;
     RECT  2.268 47.227 8.19 47.389 ;
     RECT  32.115 47.275 36.018 47.461 ;
     RECT  2.268 47.389 8.802 47.501 ;
     RECT  32.076 47.461 36.018 47.563 ;
     RECT  30.78 46.921 30.87 47.587 ;
     RECT  32.076 47.563 36.054 47.587 ;
     RECT  2.268 47.501 2.697 47.687 ;
     RECT  3.492 47.501 8.802 47.731 ;
     RECT  3.492 47.731 8.838 47.849 ;
     RECT  30.78 47.587 36.054 47.849 ;
     RECT  3.492 47.849 8.097 47.885 ;
     RECT  30.78 47.849 30.798 47.885 ;
     RECT  31.932 47.849 36.054 47.933 ;
     RECT  8.892 47.857 8.91 47.957 ;
     RECT  35.352 47.933 36.054 47.993 ;
     RECT  31.932 47.933 34.362 48.119 ;
     RECT  2.304 47.687 2.697 48.235 ;
     RECT  3.492 47.885 6.858 48.235 ;
     RECT  2.304 48.235 6.858 48.299 ;
     RECT  9 48.127 9.09 48.299 ;
     RECT  9 48.299 9.018 48.659 ;
     RECT  30.924 48.703 30.942 48.775 ;
     RECT  31.932 48.119 34.254 48.775 ;
     RECT  35.352 47.993 35.946 48.973 ;
     RECT  0.216 48.859 0.234 48.989 ;
     RECT  30.924 48.775 34.254 49.199 ;
     RECT  2.304 48.299 6.534 49.235 ;
     RECT  31.932 49.199 34.254 49.243 ;
     RECT  35.352 48.973 35.982 49.243 ;
     RECT  7.815 47.885 8.097 49.351 ;
     RECT  7.815 49.351 8.298 49.441 ;
     RECT  9.72 49.315 9.738 49.469 ;
     RECT  2.304 49.235 3.546 49.517 ;
     RECT  7.596 49.441 8.298 49.531 ;
     RECT  4.284 49.235 6.534 49.621 ;
     RECT  7.416 49.531 8.298 49.621 ;
     RECT  2.304 49.517 3.438 49.675 ;
     RECT  4.284 49.621 8.298 49.739 ;
     RECT  30.852 49.747 30.87 49.783 ;
     RECT  4.284 49.739 6.858 49.919 ;
     RECT  7.815 49.739 8.298 49.919 ;
     RECT  30.78 49.783 30.87 50.017 ;
     RECT  31.932 49.243 35.982 50.017 ;
     RECT  7.815 49.919 8.19 50.045 ;
     RECT  4.284 49.919 6.786 50.125 ;
     RECT  2.268 49.675 3.438 50.237 ;
     RECT  2.304 50.237 3.438 50.395 ;
     RECT  4.248 50.125 6.786 50.395 ;
     RECT  30.78 50.017 35.982 50.657 ;
     RECT  31.752 50.657 35.982 50.693 ;
     RECT  2.304 50.395 6.786 50.791 ;
     RECT  7.815 50.045 8.097 50.971 ;
     RECT  7.776 50.971 8.097 51.061 ;
     RECT  0.252 50.971 0.27 51.149 ;
     RECT  7.776 51.061 8.622 51.169 ;
     RECT  31.932 50.693 34.254 51.269 ;
     RECT  2.304 50.791 6.822 51.307 ;
     RECT  7.596 51.169 8.622 51.359 ;
     RECT  2.268 51.307 6.822 51.367 ;
     RECT  2.268 51.367 6.858 51.475 ;
     RECT  7.596 51.359 8.097 51.475 ;
     RECT  32.115 51.269 34.254 51.643 ;
     RECT  35.352 50.693 35.982 51.643 ;
     RECT  32.115 51.643 35.982 51.899 ;
     RECT  35.928 51.899 35.982 52.321 ;
     RECT  30.78 50.657 30.798 52.349 ;
     RECT  32.115 51.899 34.794 52.439 ;
     RECT  32.115 52.439 33.822 52.483 ;
     RECT  35.928 52.321 36.054 52.637 ;
     RECT  34.74 52.439 34.794 52.789 ;
     RECT  35.928 52.637 35.946 52.789 ;
     RECT  31.968 52.483 33.822 52.861 ;
     RECT  2.268 51.475 8.097 52.973 ;
     RECT  31.608 52.861 33.822 52.979 ;
     RECT  2.304 52.973 8.097 53.015 ;
     RECT  3.672 53.015 8.097 53.023 ;
     RECT  3.672 53.023 8.154 53.365 ;
     RECT  31.716 52.979 33.822 53.365 ;
     RECT  34.74 52.789 35.946 53.365 ;
     RECT  3.672 53.365 8.442 53.519 ;
     RECT  0.216 53.419 0.234 53.549 ;
     RECT  3.672 53.519 8.226 53.591 ;
     RECT  31.716 53.365 35.946 53.825 ;
     RECT  32.04 53.825 35.946 53.941 ;
     RECT  2.304 53.015 2.862 54.091 ;
     RECT  32.04 53.941 35.982 54.269 ;
     RECT  9 54.103 9.018 54.329 ;
     RECT  2.304 54.091 2.97 54.409 ;
     RECT  2.304 54.409 3.33 54.481 ;
     RECT  4.104 53.591 8.226 54.481 ;
     RECT  32.04 54.269 35.946 54.599 ;
     RECT  2.304 54.481 8.586 54.635 ;
     RECT  30.78 54.337 30.798 54.751 ;
     RECT  30.78 54.751 30.87 54.868 ;
     RECT  2.34 54.635 8.586 54.977 ;
     RECT  2.34 54.977 8.55 55.013 ;
     RECT  30.78 54.868 30.906 55.021 ;
     RECT  2.34 55.013 8.37 55.139 ;
     RECT  30.78 55.021 31.158 55.139 ;
     RECT  0.252 54.571 0.27 55.181 ;
     RECT  10.515 47.147 10.797 55.183 ;
     RECT  30.78 55.139 30.906 55.247 ;
     RECT  10.515 55.183 10.926 55.283 ;
     RECT  2.34 55.139 8.118 55.387 ;
     RECT  32.076 54.599 35.946 55.387 ;
     RECT  32.076 55.387 35.982 55.409 ;
     RECT  35.928 55.409 35.982 55.531 ;
     RECT  2.304 55.387 8.118 55.679 ;
     RECT  6.804 55.679 8.118 55.751 ;
     RECT  30.78 55.247 30.87 55.751 ;
     RECT  32.076 55.409 34.794 55.831 ;
     RECT  32.04 55.831 34.794 56.101 ;
     RECT  31.86 56.101 34.794 56.129 ;
     RECT  35.928 55.531 36.018 56.191 ;
     RECT  30.78 55.751 30.798 56.363 ;
     RECT  31.86 56.129 34.29 56.533 ;
     RECT  35.352 56.191 36.018 56.597 ;
     RECT  2.304 55.679 6.066 56.605 ;
     RECT  6.804 55.751 8.097 56.605 ;
     RECT  2.304 56.605 8.37 56.641 ;
     RECT  9.144 56.569 9.162 56.641 ;
     RECT  10.515 55.283 10.797 56.641 ;
     RECT  2.304 56.641 9.306 56.759 ;
     RECT  10.515 56.641 10.818 56.759 ;
     RECT  35.352 56.597 35.982 56.867 ;
     RECT  2.304 56.759 8.514 56.909 ;
     RECT  31.5 56.533 34.29 57.019 ;
     RECT  31.5 57.019 34.794 57.029 ;
     RECT  32.004 57.029 34.794 57.299 ;
     RECT  30.924 57.307 30.942 57.343 ;
     RECT  30.852 57.343 30.942 57.407 ;
     RECT  30.852 57.407 30.87 57.443 ;
     RECT  2.304 56.909 8.262 57.787 ;
     RECT  32.004 57.299 34.29 57.919 ;
     RECT  2.268 57.787 8.262 57.947 ;
     RECT  30.78 57.883 30.798 57.983 ;
     RECT  31.716 57.919 34.29 58.019 ;
     RECT  9.468 57.991 9.486 58.189 ;
     RECT  9.108 58.189 9.486 58.289 ;
     RECT  9.108 58.289 9.126 58.378 ;
     RECT  9.072 58.378 9.126 58.379 ;
     RECT  2.304 57.947 8.262 58.451 ;
     RECT  35.928 56.867 35.982 58.459 ;
     RECT  7.668 58.451 8.262 58.531 ;
     RECT  9.072 58.379 9.09 58.531 ;
     RECT  2.304 58.451 6.894 58.559 ;
     RECT  7.668 58.531 9.09 58.559 ;
     RECT  35.352 58.459 35.982 58.559 ;
     RECT  31.932 58.019 34.29 58.603 ;
     RECT  7.668 58.559 8.694 58.649 ;
     RECT  35.928 58.559 35.982 58.801 ;
     RECT  2.304 58.559 6.75 58.919 ;
     RECT  31.932 58.603 34.83 58.927 ;
     RECT  30.78 58.729 30.798 58.963 ;
     RECT  35.928 58.801 36.054 59.165 ;
     RECT  2.304 58.919 6.426 59.189 ;
     RECT  7.668 58.649 8.097 59.233 ;
     RECT  0.252 59.131 0.27 59.261 ;
     RECT  31.68 58.927 34.83 59.305 ;
     RECT  35.928 59.165 35.982 59.305 ;
     RECT  7.56 59.233 8.097 59.333 ;
     RECT  30.78 58.963 30.87 59.341 ;
     RECT  31.68 59.305 35.982 59.341 ;
     RECT  2.304 59.189 6.318 59.419 ;
     RECT  30.78 59.341 35.982 59.459 ;
     RECT  9.108 59.431 9.126 59.531 ;
     RECT  31.932 59.459 35.982 59.531 ;
     RECT  2.268 59.419 6.318 59.567 ;
     RECT  9.036 59.539 9.054 59.639 ;
     RECT  31.932 59.531 35.946 59.639 ;
     RECT  30.78 59.459 30.87 59.801 ;
     RECT  30.852 59.801 30.87 59.837 ;
     RECT  7.74 59.333 8.097 59.851 ;
     RECT  7.74 59.851 8.19 59.995 ;
     RECT  7.74 59.995 8.37 60.269 ;
     RECT  7.74 60.269 8.19 60.305 ;
     RECT  7.74 60.305 8.097 60.385 ;
     RECT  2.304 59.567 6.318 60.412 ;
     RECT  2.268 60.412 6.318 60.421 ;
     RECT  31.932 59.639 34.434 60.449 ;
     RECT  2.268 60.421 6.39 60.539 ;
     RECT  7.2 60.385 8.097 60.539 ;
     RECT  31.932 60.449 34.362 60.655 ;
     RECT  35.352 59.639 35.946 60.655 ;
     RECT  9.468 60.385 9.486 60.691 ;
     RECT  2.268 60.539 5.778 60.845 ;
     RECT  31.392 60.655 34.362 60.853 ;
     RECT  9.036 60.691 9.486 60.917 ;
     RECT  3.996 60.845 5.778 60.953 ;
     RECT  30.78 60.853 34.362 60.953 ;
     RECT  9.396 60.917 9.486 61.079 ;
     RECT  30.852 60.953 34.362 61.079 ;
     RECT  2.268 60.845 3.186 61.187 ;
     RECT  7.815 60.539 8.097 61.195 ;
     RECT  4.14 60.953 5.778 61.291 ;
     RECT  10.515 56.759 10.797 61.321 ;
     RECT  9.396 61.079 9.414 61.349 ;
     RECT  30.852 61.079 30.87 61.457 ;
     RECT  10.515 61.321 10.854 61.529 ;
     RECT  0.252 61.435 0.27 61.565 ;
     RECT  4.14 61.291 6.138 61.627 ;
     RECT  6.876 60.961 6.966 61.627 ;
     RECT  7.815 61.195 8.478 61.627 ;
     RECT  4.14 61.627 8.478 61.771 ;
     RECT  4.14 61.771 9.126 61.889 ;
     RECT  2.304 61.187 3.186 61.969 ;
     RECT  32.115 61.079 34.326 62.005 ;
     RECT  32.115 62.005 34.362 62.011 ;
     RECT  35.352 60.655 36.018 62.011 ;
     RECT  32.115 62.011 36.018 62.069 ;
     RECT  32.115 62.069 34.362 62.203 ;
     RECT  2.304 61.969 3.402 62.401 ;
     RECT  4.14 61.889 6.138 62.401 ;
     RECT  35.352 62.069 36.018 62.537 ;
     RECT  7.02 61.889 8.478 62.609 ;
     RECT  2.304 62.401 6.138 62.671 ;
     RECT  35.892 62.537 36.018 62.683 ;
     RECT  31.068 62.203 34.362 62.699 ;
     RECT  0.252 62.683 0.27 62.813 ;
     RECT  2.304 62.671 6.282 62.815 ;
     RECT  7.02 62.609 8.097 62.815 ;
     RECT  31.86 62.699 34.362 62.827 ;
     RECT  31.86 62.827 34.794 62.969 ;
     RECT  9.036 62.851 9.054 63.085 ;
     RECT  9.036 63.085 9.126 63.275 ;
     RECT  34.704 62.969 34.794 63.499 ;
     RECT  35.892 62.683 36.522 63.499 ;
     RECT  2.304 62.815 8.097 63.509 ;
     RECT  3.6 63.509 8.097 63.661 ;
     RECT  34.704 63.499 36.522 63.689 ;
     RECT  10.515 61.529 10.797 63.751 ;
     RECT  3.6 63.661 8.658 63.779 ;
     RECT  31.86 62.969 33.966 63.787 ;
     RECT  31.572 63.787 33.966 63.823 ;
     RECT  10.515 63.751 10.818 63.851 ;
     RECT  31.068 63.823 33.966 63.859 ;
     RECT  34.704 63.689 35.946 63.859 ;
     RECT  31.068 63.859 35.946 64.157 ;
     RECT  3.6 63.779 7.074 64.319 ;
     RECT  31.068 64.157 34.254 64.319 ;
     RECT  7.056 64.319 7.074 64.355 ;
     RECT  2.304 63.509 2.79 64.363 ;
     RECT  3.6 64.319 6.21 64.363 ;
     RECT  2.304 64.363 6.21 64.391 ;
     RECT  35.352 64.157 35.946 64.603 ;
     RECT  2.304 64.391 6.138 64.733 ;
     RECT  9.036 64.021 9.126 64.741 ;
     RECT  7.815 63.779 8.097 64.795 ;
     RECT  9.036 64.741 9.162 64.859 ;
     RECT  31.716 64.319 34.218 64.895 ;
     RECT  7.236 64.795 8.097 65.011 ;
     RECT  2.304 64.733 6.102 65.201 ;
     RECT  2.304 65.201 5.742 65.275 ;
     RECT  7.236 65.011 8.838 65.281 ;
     RECT  7.164 65.281 8.838 65.399 ;
     RECT  35.352 64.603 36.018 65.419 ;
     RECT  7.164 65.399 8.097 65.435 ;
     RECT  31.932 64.895 34.218 65.467 ;
     RECT  35.352 65.419 36.054 65.579 ;
     RECT  2.268 65.275 5.742 65.669 ;
     RECT  30.78 65.281 30.798 65.677 ;
     RECT  31.932 65.467 34.29 65.713 ;
     RECT  35.352 65.579 36.018 65.713 ;
     RECT  30.78 65.677 30.87 65.813 ;
     RECT  31.608 65.713 36.018 65.849 ;
     RECT  31.608 65.849 34.434 65.939 ;
     RECT  2.268 65.669 5.67 65.984 ;
     RECT  35.352 65.849 36.018 66.047 ;
     RECT  6.732 65.515 6.822 66.187 ;
     RECT  7.632 65.435 8.097 66.187 ;
     RECT  31.932 65.939 34.434 66.209 ;
     RECT  6.732 66.187 8.097 66.289 ;
     RECT  6.516 66.289 8.097 66.361 ;
     RECT  8.82 65.399 8.838 66.361 ;
     RECT  2.304 65.984 5.67 66.523 ;
     RECT  6.516 66.361 8.982 66.523 ;
     RECT  2.304 66.523 8.982 66.551 ;
     RECT  31.932 66.209 34.254 67.019 ;
     RECT  7.02 66.551 8.982 67.063 ;
     RECT  7.02 67.063 9.198 67.091 ;
     RECT  8.892 67.091 9.198 67.289 ;
     RECT  10.515 63.851 10.797 67.297 ;
     RECT  30.78 65.813 30.798 67.297 ;
     RECT  2.304 66.551 6.246 67.369 ;
     RECT  7.02 67.091 8.097 67.369 ;
     RECT  10.515 67.297 10.854 67.369 ;
     RECT  2.304 67.369 8.097 67.559 ;
     RECT  10.515 67.369 10.926 67.559 ;
     RECT  35.352 66.047 35.982 67.565 ;
     RECT  0.216 67.531 0.234 67.661 ;
     RECT  9.18 67.289 9.198 67.667 ;
     RECT  30.78 67.297 30.87 67.703 ;
     RECT  35.928 67.565 35.982 67.723 ;
     RECT  30.816 67.703 30.87 67.739 ;
     RECT  32.04 67.019 34.254 67.801 ;
     RECT  31.5 67.801 34.254 67.867 ;
     RECT  7.092 67.559 8.097 67.909 ;
     RECT  35.928 67.723 36.018 67.945 ;
     RECT  31.5 67.867 34.758 68.009 ;
     RECT  2.304 67.559 6.102 68.099 ;
     RECT  7.092 67.909 8.442 68.099 ;
     RECT  35.928 67.945 36.054 68.237 ;
     RECT  31.716 68.009 34.758 68.341 ;
     RECT  31.716 68.341 34.794 68.381 ;
     RECT  10.515 67.559 10.797 68.413 ;
     RECT  8.856 68.143 9.054 68.485 ;
     RECT  3.42 68.099 6.102 68.635 ;
     RECT  8.856 68.485 9.162 68.639 ;
     RECT  10.515 68.413 10.818 68.719 ;
     RECT  10.515 68.719 10.854 68.819 ;
     RECT  2.304 68.099 2.697 68.881 ;
     RECT  3.42 68.635 6.318 68.881 ;
     RECT  8.856 68.639 8.874 68.909 ;
     RECT  2.304 68.881 6.318 68.957 ;
     RECT  3.996 68.957 6.318 69.151 ;
     RECT  7.2 68.099 8.097 69.151 ;
     RECT  2.304 68.957 2.934 69.163 ;
     RECT  31.716 68.381 34.758 69.163 ;
     RECT  35.928 68.237 35.946 69.163 ;
     RECT  30.78 68.647 30.798 69.223 ;
     RECT  31.716 69.163 35.946 69.259 ;
     RECT  30.78 69.223 30.87 69.295 ;
     RECT  31.716 69.259 36.018 69.295 ;
     RECT  3.996 69.151 8.37 69.359 ;
     RECT  2.268 69.163 2.934 69.449 ;
     RECT  30.78 69.295 36.018 69.521 ;
     RECT  31.068 69.521 36.018 69.677 ;
     RECT  3.996 69.359 8.298 69.871 ;
     RECT  9.396 69.421 9.414 69.899 ;
     RECT  3.816 69.871 8.298 70.069 ;
     RECT  2.268 69.449 2.862 70.097 ;
     RECT  3.744 70.069 8.298 70.141 ;
     RECT  2.304 70.097 2.862 70.411 ;
     RECT  3.6 70.141 8.298 70.411 ;
     RECT  31.068 69.677 35.946 70.493 ;
     RECT  10.515 68.819 10.797 70.573 ;
     RECT  0.216 70.459 0.234 70.589 ;
     RECT  10.515 70.573 10.818 70.673 ;
     RECT  31.068 70.493 34.758 70.681 ;
     RECT  35.928 70.493 35.946 70.795 ;
     RECT  2.304 70.411 8.37 70.799 ;
     RECT  30.852 70.681 34.758 70.799 ;
     RECT  30.852 70.799 30.87 70.907 ;
     RECT  35.928 70.795 35.982 71.131 ;
     RECT  30.78 70.915 30.798 71.177 ;
     RECT  31.824 70.799 34.758 71.221 ;
     RECT  35.928 71.131 36.054 71.519 ;
     RECT  31.824 71.221 34.794 71.609 ;
     RECT  32.115 71.609 34.794 71.611 ;
     RECT  35.928 71.519 35.982 71.611 ;
     RECT  7.236 70.799 8.37 71.761 ;
     RECT  0.252 70.939 0.27 71.789 ;
     RECT  10.515 70.673 10.797 71.851 ;
     RECT  7.236 71.761 8.622 71.951 ;
     RECT  30.852 71.923 30.87 71.959 ;
     RECT  10.515 71.851 10.818 71.987 ;
     RECT  7.236 71.951 8.154 72.023 ;
     RECT  32.115 71.611 35.982 72.059 ;
     RECT  2.304 70.799 6.426 72.091 ;
     RECT  7.236 72.023 8.097 72.091 ;
     RECT  30.78 71.959 30.87 72.463 ;
     RECT  35.352 72.059 35.982 72.491 ;
     RECT  2.304 72.091 8.097 72.599 ;
     RECT  30.78 72.463 30.942 72.599 ;
     RECT  2.304 72.599 6.39 72.689 ;
     RECT  30.78 72.599 30.87 72.689 ;
     RECT  0.252 72.571 0.27 72.749 ;
     RECT  7.344 72.599 8.097 72.805 ;
     RECT  7.344 72.805 8.55 72.869 ;
     RECT  30.78 72.689 30.798 72.869 ;
     RECT  7.416 72.869 8.55 72.959 ;
     RECT  32.115 72.059 34.218 73.051 ;
     RECT  35.352 72.491 35.946 73.051 ;
     RECT  32.115 73.051 35.946 73.201 ;
     RECT  31.824 73.201 35.946 73.535 ;
     RECT  29.415 31.919 29.697 73.543 ;
     RECT  0.216 73.507 0.234 73.565 ;
     RECT  2.304 72.689 6.318 73.769 ;
     RECT  9.324 73.543 9.342 73.769 ;
     RECT  2.304 73.769 6.138 73.811 ;
     RECT  7.416 72.959 8.514 73.885 ;
     RECT  7.416 73.885 8.622 73.921 ;
     RECT  29.124 73.543 29.697 73.949 ;
     RECT  7.092 73.921 8.622 74.039 ;
     RECT  29.16 73.949 29.697 74.075 ;
     RECT  7.2 74.039 8.622 74.111 ;
     RECT  32.115 73.535 35.946 74.111 ;
     RECT  32.115 74.111 34.758 74.237 ;
     RECT  32.115 74.237 34.29 74.587 ;
     RECT  2.304 73.811 6.03 74.623 ;
     RECT  2.304 74.623 6.138 74.821 ;
     RECT  7.2 74.111 8.097 74.821 ;
     RECT  9.108 74.731 9.198 74.821 ;
     RECT  29.415 74.075 29.697 74.821 ;
     RECT  2.304 74.821 8.097 74.849 ;
     RECT  9.108 74.821 9.27 74.857 ;
     RECT  35.892 74.111 35.946 74.875 ;
     RECT  9.108 74.857 9.342 74.921 ;
     RECT  31.572 74.587 34.29 74.993 ;
     RECT  9.324 74.921 9.342 75.029 ;
     RECT  35.892 74.875 35.982 75.029 ;
     RECT  31.572 74.993 34.254 75.271 ;
     RECT  35.892 75.029 35.946 75.355 ;
     RECT  31.284 75.271 34.254 75.389 ;
     RECT  35.352 75.355 35.946 75.395 ;
     RECT  6.84 74.849 8.097 75.425 ;
     RECT  7.815 75.425 8.097 75.469 ;
     RECT  6.84 75.425 6.894 75.533 ;
     RECT  10.515 71.987 10.797 75.541 ;
     RECT  7.815 75.469 8.586 75.569 ;
     RECT  2.304 74.849 5.814 75.595 ;
     RECT  2.304 75.595 5.85 75.643 ;
     RECT  6.84 75.533 6.858 75.659 ;
     RECT  10.515 75.541 10.818 75.659 ;
     RECT  31.932 75.389 34.254 75.811 ;
     RECT  2.268 75.643 5.85 75.965 ;
     RECT  35.928 75.395 35.946 75.979 ;
     RECT  2.304 75.965 5.85 76.081 ;
     RECT  2.304 76.081 5.886 76.171 ;
     RECT  6.624 76.027 6.822 76.171 ;
     RECT  31.932 75.811 34.758 76.171 ;
     RECT  29.124 74.821 29.697 76.243 ;
     RECT  0.252 76.171 0.27 76.301 ;
     RECT  2.304 76.171 6.822 76.441 ;
     RECT  7.815 75.569 8.154 76.441 ;
     RECT  31.932 76.171 34.794 76.441 ;
     RECT  35.928 75.979 35.982 76.459 ;
     RECT  10.515 75.659 10.797 76.549 ;
     RECT  10.515 76.549 10.854 76.621 ;
     RECT  10.515 76.621 10.926 76.739 ;
     RECT  29.088 76.243 29.697 76.883 ;
     RECT  2.304 76.441 8.154 77.117 ;
     RECT  7.74 77.117 8.154 77.126 ;
     RECT  2.304 77.117 6.858 77.189 ;
     RECT  31.716 76.441 34.794 77.275 ;
     RECT  35.928 76.459 36.018 77.275 ;
     RECT  7.74 77.126 8.118 77.279 ;
     RECT  31.716 77.275 36.018 77.395 ;
     RECT  31.392 77.395 36.018 77.557 ;
     RECT  2.304 77.189 6.282 77.665 ;
     RECT  2.268 77.665 6.282 77.789 ;
     RECT  31.032 77.557 36.018 77.819 ;
     RECT  31.932 77.819 36.018 77.891 ;
     RECT  2.304 77.789 6.282 77.971 ;
     RECT  32.004 77.891 36.018 78.089 ;
     RECT  35.928 78.089 36.018 78.091 ;
     RECT  2.304 77.971 6.858 78.169 ;
     RECT  7.74 77.279 8.097 78.169 ;
     RECT  9.36 78.061 9.378 78.241 ;
     RECT  9.36 78.241 9.486 78.359 ;
     RECT  29.415 76.883 29.697 78.403 ;
     RECT  2.304 78.169 8.097 78.431 ;
     RECT  32.004 78.089 34.758 78.461 ;
     RECT  35.928 78.091 36.09 78.571 ;
     RECT  9.54 78.367 9.558 78.629 ;
     RECT  29.088 78.403 29.697 78.629 ;
     RECT  32.004 78.461 34.722 78.637 ;
     RECT  2.304 78.431 7.074 78.665 ;
     RECT  35.928 78.571 36.162 78.665 ;
     RECT  31.932 78.637 34.722 78.809 ;
     RECT  35.928 78.665 36.054 78.809 ;
     RECT  32.004 78.809 34.722 79.213 ;
     RECT  7.815 78.431 8.097 79.243 ;
     RECT  3.6 78.665 7.074 79.277 ;
     RECT  32.004 79.213 34.794 79.277 ;
     RECT  2.304 78.665 2.862 79.387 ;
     RECT  29.415 78.629 29.697 79.447 ;
     RECT  10.515 76.739 10.797 79.483 ;
     RECT  2.268 79.387 2.862 79.583 ;
     RECT  10.515 79.483 10.926 79.583 ;
     RECT  35.928 78.809 36.018 79.583 ;
     RECT  2.304 79.583 2.862 79.681 ;
     RECT  3.6 79.277 6.426 79.681 ;
     RECT  7.815 79.243 8.478 79.681 ;
     RECT  32.004 79.277 34.254 79.709 ;
     RECT  35.928 79.583 35.982 79.723 ;
     RECT  2.304 79.681 6.426 79.745 ;
     RECT  2.304 79.745 3.654 79.853 ;
     RECT  4.536 79.745 6.426 80.059 ;
     RECT  7.38 79.681 8.478 80.059 ;
     RECT  32.004 79.709 34.002 80.059 ;
     RECT  10.515 79.583 10.818 80.087 ;
     RECT  9.54 79.861 9.558 80.131 ;
     RECT  31.968 80.059 34.002 80.131 ;
     RECT  0.54 79.213 0.558 80.237 ;
     RECT  2.304 79.853 3.618 80.249 ;
     RECT  35.352 79.723 35.982 80.249 ;
     RECT  31.788 80.131 34.002 80.293 ;
     RECT  4.536 80.059 8.478 80.401 ;
     RECT  9.54 80.131 9.63 80.429 ;
     RECT  4.536 80.401 8.622 80.519 ;
     RECT  4.536 80.519 6.21 80.555 ;
     RECT  7.272 80.519 8.478 80.555 ;
     RECT  34.776 80.329 34.794 80.599 ;
     RECT  0.216 80.683 0.234 80.813 ;
     RECT  4.536 80.555 5.85 80.869 ;
     RECT  34.74 80.599 34.794 80.909 ;
     RECT  29.088 79.447 29.697 80.933 ;
     RECT  31.716 80.293 34.002 80.941 ;
     RECT  35.928 80.249 35.982 81.019 ;
     RECT  9.54 80.429 9.558 81.059 ;
     RECT  2.304 80.249 3.474 81.211 ;
     RECT  4.356 80.869 5.85 81.211 ;
     RECT  2.304 81.211 5.85 81.301 ;
     RECT  7.272 80.555 8.097 81.301 ;
     RECT  30.852 81.103 30.87 81.409 ;
     RECT  9.108 81.481 9.126 81.599 ;
     RECT  2.304 81.301 8.097 81.671 ;
     RECT  35.352 81.019 35.982 81.707 ;
     RECT  31.716 80.941 34.182 81.743 ;
     RECT  32.115 81.743 34.182 81.751 ;
     RECT  35.352 81.707 35.946 81.835 ;
     RECT  10.515 80.087 10.797 82.111 ;
     RECT  3.852 81.671 8.097 82.139 ;
     RECT  10.515 82.111 10.926 82.247 ;
     RECT  2.304 81.671 2.697 82.411 ;
     RECT  0.252 82.315 0.27 82.445 ;
     RECT  7.344 82.139 8.097 82.489 ;
     RECT  32.115 81.751 34.254 82.525 ;
     RECT  2.304 82.411 2.898 82.561 ;
     RECT  3.852 82.139 6.57 82.561 ;
     RECT  32.004 82.525 34.254 82.561 ;
     RECT  10.515 82.247 10.818 82.589 ;
     RECT  30.78 81.409 30.87 82.589 ;
     RECT  35.316 81.835 35.946 82.679 ;
     RECT  32.004 82.561 34.326 82.993 ;
     RECT  2.304 82.561 6.57 83.065 ;
     RECT  7.344 82.489 8.694 83.065 ;
     RECT  31.032 82.993 34.326 83.065 ;
     RECT  35.928 82.679 35.946 83.131 ;
     RECT  2.304 83.065 8.694 83.219 ;
     RECT  31.032 83.065 34.794 83.219 ;
     RECT  2.304 83.219 8.097 83.525 ;
     RECT  3.42 83.525 8.097 83.633 ;
     RECT  35.928 83.131 35.982 83.686 ;
     RECT  9.144 83.767 9.162 83.911 ;
     RECT  10.515 82.589 10.797 83.911 ;
     RECT  35.928 83.686 36.018 83.981 ;
     RECT  9.144 83.911 10.797 84.029 ;
     RECT  31.824 83.219 34.794 84.029 ;
     RECT  30.78 83.497 30.798 84.073 ;
     RECT  3.456 83.633 8.097 84.173 ;
     RECT  30.78 84.073 30.87 84.173 ;
     RECT  3.708 84.173 8.097 84.209 ;
     RECT  30.78 84.173 30.798 84.209 ;
     RECT  2.304 83.525 2.697 84.283 ;
     RECT  3.744 84.209 8.097 84.331 ;
     RECT  3.744 84.331 8.37 84.371 ;
     RECT  32.076 84.029 34.794 84.427 ;
     RECT  35.928 83.981 35.946 84.427 ;
     RECT  2.268 84.283 2.697 84.451 ;
     RECT  3.852 84.371 8.37 84.569 ;
     RECT  2.268 84.451 2.934 84.605 ;
     RECT  32.076 84.427 35.946 84.677 ;
     RECT  32.076 84.677 34.794 84.847 ;
     RECT  35.928 84.677 35.946 84.907 ;
     RECT  31.86 84.847 34.794 85.109 ;
     RECT  31.968 85.109 34.794 85.181 ;
     RECT  30.78 85.153 30.798 85.225 ;
     RECT  3.852 84.569 5.67 85.261 ;
     RECT  30.78 85.225 30.942 85.289 ;
     RECT  3.708 85.261 5.67 85.339 ;
     RECT  6.84 84.569 7.002 85.339 ;
     RECT  9.756 84.811 9.774 85.379 ;
     RECT  30.852 85.289 30.942 85.451 ;
     RECT  2.304 84.605 2.934 85.459 ;
     RECT  3.708 85.339 7.002 85.459 ;
     RECT  30.852 85.451 30.87 85.487 ;
     RECT  2.304 85.459 7.002 85.531 ;
     RECT  7.815 84.569 8.37 85.531 ;
     RECT  32.115 85.181 34.794 85.649 ;
     RECT  35.928 84.907 35.982 85.723 ;
     RECT  10.515 84.029 10.797 85.729 ;
     RECT  2.304 85.531 8.37 85.757 ;
     RECT  3.708 85.757 8.37 85.793 ;
     RECT  32.115 85.649 34.218 86.035 ;
     RECT  35.928 85.723 36.018 86.059 ;
     RECT  9 85.801 9.018 86.071 ;
     RECT  2.304 85.757 2.97 86.189 ;
     RECT  9 86.071 9.09 86.189 ;
     RECT  10.515 85.729 10.818 86.333 ;
     RECT  35.352 86.059 36.018 86.369 ;
     RECT  0.252 86.395 0.27 86.525 ;
     RECT  31.932 86.035 34.218 86.539 ;
     RECT  35.352 86.369 35.982 86.539 ;
     RECT  3.708 85.793 8.154 86.575 ;
     RECT  30.78 86.503 30.798 86.603 ;
     RECT  31.932 86.539 35.982 86.611 ;
     RECT  2.304 86.189 2.862 86.971 ;
     RECT  3.636 86.575 8.154 86.971 ;
     RECT  30.852 86.611 35.982 86.999 ;
     RECT  31.788 86.999 35.982 87.035 ;
     RECT  31.932 87.035 35.982 87.107 ;
     RECT  31.932 87.107 34.254 87.269 ;
     RECT  35.352 87.107 35.982 87.341 ;
     RECT  2.304 86.971 8.154 87.421 ;
     RECT  2.304 87.421 8.514 87.583 ;
     RECT  31.932 87.269 34.218 87.853 ;
     RECT  31.716 87.853 34.218 88.051 ;
     RECT  0.216 87.499 0.234 88.109 ;
     RECT  2.304 87.583 8.802 88.159 ;
     RECT  31.68 88.051 34.218 88.171 ;
     RECT  35.352 87.341 35.946 88.171 ;
     RECT  2.304 88.159 8.874 88.231 ;
     RECT  29.415 80.933 29.697 88.231 ;
     RECT  30.852 86.999 30.87 88.231 ;
     RECT  29.415 88.231 30.87 88.321 ;
     RECT  2.304 88.231 9.234 88.349 ;
     RECT  13.215 41.648 13.497 88.591 ;
     RECT  21.315 41.648 21.597 88.591 ;
     RECT  13.104 88.591 13.497 88.637 ;
     RECT  21.204 88.591 21.597 88.637 ;
     RECT  14.832 88.603 14.85 88.733 ;
     RECT  22.824 88.603 22.842 88.733 ;
     RECT  29.415 88.321 30.906 88.799 ;
     RECT  29.415 88.799 30.798 88.889 ;
     RECT  31.68 88.171 35.946 88.889 ;
     RECT  31.788 88.889 35.946 88.987 ;
     RECT  2.304 88.349 8.097 89.131 ;
     RECT  31.788 88.987 35.982 89.159 ;
     RECT  35.928 89.159 35.982 89.275 ;
     RECT  2.268 89.131 8.097 89.429 ;
     RECT  9 88.349 9.018 89.429 ;
     RECT  2.268 89.429 7.002 89.645 ;
     RECT  31.788 89.159 34.794 89.707 ;
     RECT  30.78 88.889 30.798 89.843 ;
     RECT  2.304 89.645 7.002 89.879 ;
     RECT  31.68 89.707 34.794 89.879 ;
     RECT  31.824 89.879 34.794 89.969 ;
     RECT  31.932 89.969 34.794 90.005 ;
     RECT  35.928 89.275 36.018 90.041 ;
     RECT  32.004 90.005 34.794 90.091 ;
     RECT  6.876 89.879 7.002 90.187 ;
     RECT  7.815 89.429 8.097 90.187 ;
     RECT  32.004 90.091 34.866 90.283 ;
     RECT  35.928 90.041 35.946 90.283 ;
     RECT  9.576 90.391 9.702 90.509 ;
     RECT  6.876 90.187 8.097 90.625 ;
     RECT  6.876 90.625 8.118 90.751 ;
     RECT  6.84 90.751 8.118 90.787 ;
     RECT  32.004 90.283 35.946 90.859 ;
     RECT  2.304 89.879 6.066 90.931 ;
     RECT  6.804 90.787 8.118 90.931 ;
     RECT  2.304 90.931 8.514 91.049 ;
     RECT  10.515 86.333 10.797 91.093 ;
     RECT  31.824 90.859 35.946 91.165 ;
     RECT  30.852 90.823 30.87 91.291 ;
     RECT  31.68 91.165 35.946 91.291 ;
     RECT  30.852 91.291 35.946 91.463 ;
     RECT  10.515 91.093 10.818 91.597 ;
     RECT  30.852 91.463 34.794 91.633 ;
     RECT  10.515 91.597 10.926 91.697 ;
     RECT  35.928 91.463 35.946 91.723 ;
     RECT  2.304 91.049 8.097 91.733 ;
     RECT  2.304 91.733 6.03 91.859 ;
     RECT  30.78 91.633 34.794 91.895 ;
     RECT  6.804 91.733 8.097 92.011 ;
     RECT  0.252 92.059 0.27 92.189 ;
     RECT  35.928 91.723 35.982 92.203 ;
     RECT  6.804 92.011 8.478 92.237 ;
     RECT  31.86 91.895 34.794 92.539 ;
     RECT  35.928 92.203 36.018 92.539 ;
     RECT  31.86 92.539 36.018 92.579 ;
     RECT  30.78 91.895 30.798 92.713 ;
     RECT  8.892 92.281 8.91 92.813 ;
     RECT  2.304 91.859 5.994 92.911 ;
     RECT  6.804 92.237 8.097 92.911 ;
     RECT  30.78 92.713 30.87 92.911 ;
     RECT  31.86 92.579 34.254 92.911 ;
     RECT  35.352 92.579 36.018 93.119 ;
     RECT  36.504 93.211 36.522 93.253 ;
     RECT  36.504 93.253 36.594 93.281 ;
     RECT  36.576 93.281 36.594 93.293 ;
     RECT  30.78 92.911 34.254 93.353 ;
     RECT  31.716 93.353 34.254 93.355 ;
     RECT  35.352 93.119 35.37 93.355 ;
     RECT  30.78 93.353 30.942 93.389 ;
     RECT  30.852 93.389 30.942 93.479 ;
     RECT  2.304 92.911 8.097 93.929 ;
     RECT  31.716 93.355 35.37 93.929 ;
     RECT  6.552 93.929 6.93 94.019 ;
     RECT  31.716 93.929 34.326 94.055 ;
     RECT  10.515 91.697 10.797 94.297 ;
     RECT  35.352 93.929 35.37 94.315 ;
     RECT  10.515 94.297 10.854 94.433 ;
     RECT  32.04 94.055 34.326 94.637 ;
     RECT  35.352 94.315 35.946 94.651 ;
     RECT  30.78 94.297 30.798 94.675 ;
     RECT  2.304 93.929 5.742 94.711 ;
     RECT  6.84 94.019 6.93 94.711 ;
     RECT  7.815 93.929 8.097 94.711 ;
     RECT  2.304 94.711 5.85 94.945 ;
     RECT  6.84 94.711 8.097 94.945 ;
     RECT  2.304 94.945 8.097 94.981 ;
     RECT  30.78 94.675 30.87 95.009 ;
     RECT  2.304 94.981 8.334 95.021 ;
     RECT  32.04 94.637 34.254 95.071 ;
     RECT  6.588 95.021 8.334 95.099 ;
     RECT  9.288 94.981 9.306 95.171 ;
     RECT  31.932 95.071 34.254 95.369 ;
     RECT  31.932 95.369 34.218 95.405 ;
     RECT  30.78 95.009 30.798 95.819 ;
     RECT  9.108 95.521 9.198 95.917 ;
     RECT  9.108 95.917 9.27 96.053 ;
     RECT  32.115 95.405 34.218 96.151 ;
     RECT  0.216 96.091 0.234 96.221 ;
     RECT  2.304 95.021 5.85 96.295 ;
     RECT  6.588 95.099 8.097 96.295 ;
     RECT  2.304 96.295 8.097 96.449 ;
     RECT  2.304 96.449 3.33 96.485 ;
     RECT  31.968 96.151 34.218 96.565 ;
     RECT  2.304 96.485 2.754 96.619 ;
     RECT  4.14 96.449 8.097 96.629 ;
     RECT  8.928 96.601 8.946 96.719 ;
     RECT  2.268 96.619 2.754 96.755 ;
     RECT  31.968 96.565 34.29 96.763 ;
     RECT  31.32 96.763 34.29 96.835 ;
     RECT  35.352 94.651 35.982 96.899 ;
     RECT  31.32 96.835 34.326 97.169 ;
     RECT  31.896 97.169 34.326 97.259 ;
     RECT  2.304 96.755 2.754 97.411 ;
     RECT  7.815 96.629 8.097 97.411 ;
     RECT  4.14 96.629 6.93 97.537 ;
     RECT  31.932 97.259 34.326 97.579 ;
     RECT  35.352 96.899 35.946 97.579 ;
     RECT  4.104 97.537 6.93 97.609 ;
     RECT  7.815 97.411 8.406 97.673 ;
     RECT  2.304 97.411 3.294 97.681 ;
     RECT  4.104 97.609 7.002 97.681 ;
     RECT  2.304 97.681 7.002 97.709 ;
     RECT  2.304 97.709 6.858 97.723 ;
     RECT  30.78 97.807 30.798 98.041 ;
     RECT  7.815 97.673 8.097 98.059 ;
     RECT  8.856 97.681 8.946 98.069 ;
     RECT  2.268 97.723 6.858 98.105 ;
     RECT  31.932 97.579 35.946 98.113 ;
     RECT  10.515 94.433 10.797 98.221 ;
     RECT  8.856 98.069 8.874 98.339 ;
     RECT  31.932 98.113 35.982 98.395 ;
     RECT  31.932 98.395 36.018 98.447 ;
     RECT  2.268 98.105 2.697 98.483 ;
     RECT  3.456 98.105 6.858 98.519 ;
     RECT  30.78 98.041 31.086 98.609 ;
     RECT  35.316 98.447 36.018 98.609 ;
     RECT  3.78 98.519 6.858 98.621 ;
     RECT  7.632 98.059 8.097 98.725 ;
     RECT  3.96 98.621 6.858 98.789 ;
     RECT  6.84 98.789 6.858 98.959 ;
     RECT  7.596 98.725 8.097 98.959 ;
     RECT  35.316 98.609 35.982 98.987 ;
     RECT  2.304 98.483 2.697 99.031 ;
     RECT  9.792 98.221 10.797 99.149 ;
     RECT  31.932 98.447 34.434 99.157 ;
     RECT  31.572 99.157 34.434 99.211 ;
     RECT  35.316 98.987 35.946 99.211 ;
     RECT  31.572 99.211 35.946 99.419 ;
     RECT  30.78 98.609 30.798 99.463 ;
     RECT  31.572 99.419 33.93 99.463 ;
     RECT  3.96 98.789 5.994 99.571 ;
     RECT  6.84 98.959 8.097 99.571 ;
     RECT  30.78 99.463 33.93 99.689 ;
     RECT  10.515 99.149 10.797 99.769 ;
     RECT  3.78 99.571 8.097 99.841 ;
     RECT  10.515 99.769 10.818 99.869 ;
     RECT  34.74 99.419 35.946 99.869 ;
     RECT  3.78 99.841 8.766 100.031 ;
     RECT  3.78 100.031 8.406 100.139 ;
     RECT  30.78 99.689 30.87 100.139 ;
     RECT  2.304 99.031 3.042 100.201 ;
     RECT  3.78 100.139 6.678 100.201 ;
     RECT  31.824 99.689 33.93 100.201 ;
     RECT  34.74 99.869 35.406 100.201 ;
     RECT  2.304 100.201 6.678 100.253 ;
     RECT  2.304 100.253 2.934 100.301 ;
     RECT  9.54 100.111 9.63 100.499 ;
     RECT  31.824 100.201 35.406 100.535 ;
     RECT  31.896 100.535 35.406 100.651 ;
     RECT  0.252 100.651 0.27 100.829 ;
     RECT  31.896 100.651 35.946 100.843 ;
     RECT  31.896 100.843 35.982 100.913 ;
     RECT  2.304 100.301 2.862 100.987 ;
     RECT  9.684 100.651 9.774 101.039 ;
     RECT  2.268 100.987 2.862 101.147 ;
     RECT  31.896 100.913 35.946 101.183 ;
     RECT  2.304 101.147 2.862 101.191 ;
     RECT  3.78 100.253 6.57 101.191 ;
     RECT  2.304 101.191 6.57 101.551 ;
     RECT  7.452 100.139 8.406 101.551 ;
     RECT  31.932 101.183 35.946 101.579 ;
     RECT  30.78 100.139 30.798 101.623 ;
     RECT  9.684 101.039 9.702 101.651 ;
     RECT  10.515 99.869 10.797 101.731 ;
     RECT  2.304 101.551 8.406 101.759 ;
     RECT  30.78 101.623 30.87 101.759 ;
     RECT  7.524 101.759 8.406 101.821 ;
     RECT  7.524 101.821 8.658 102.029 ;
     RECT  10.515 101.731 10.854 102.029 ;
     RECT  32.004 101.579 35.946 102.119 ;
     RECT  35.352 102.119 35.946 102.317 ;
     RECT  7.524 102.029 8.586 102.389 ;
     RECT  32.004 102.119 34.326 102.397 ;
     RECT  35.928 102.317 35.946 102.427 ;
     RECT  7.815 102.389 8.334 102.605 ;
     RECT  35.928 102.427 35.982 102.619 ;
     RECT  7.815 102.605 8.262 102.659 ;
     RECT  2.304 101.759 6.678 102.703 ;
     RECT  35.928 102.619 36.018 103.099 ;
     RECT  30.78 101.759 30.798 103.243 ;
     RECT  31.572 102.397 34.326 103.243 ;
     RECT  35.928 103.099 36.054 103.271 ;
     RECT  2.304 102.703 6.93 103.351 ;
     RECT  30.78 103.243 34.758 103.435 ;
     RECT  9.324 103.243 9.342 103.441 ;
     RECT  2.304 103.351 6.966 103.469 ;
     RECT  9.324 103.441 9.414 103.469 ;
     RECT  35.928 103.271 36.018 103.469 ;
     RECT  6.84 103.469 6.966 103.477 ;
     RECT  6.84 103.477 7.002 103.549 ;
     RECT  7.815 102.659 8.154 103.549 ;
     RECT  30.78 103.435 34.794 103.649 ;
     RECT  35.928 103.469 35.982 103.649 ;
     RECT  6.84 103.549 8.154 103.723 ;
     RECT  30.852 103.649 34.794 103.723 ;
     RECT  9.36 103.469 9.414 103.891 ;
     RECT  9.36 103.891 9.486 104.009 ;
     RECT  30.852 103.723 34.83 104.009 ;
     RECT  31.932 104.009 34.83 104.189 ;
     RECT  2.304 103.469 6.066 104.251 ;
     RECT  6.84 103.723 8.406 104.251 ;
     RECT  35.928 103.649 35.946 104.251 ;
     RECT  35.352 104.251 35.946 104.539 ;
     RECT  2.304 104.251 8.406 104.549 ;
     RECT  2.304 104.549 6.966 104.729 ;
     RECT  2.304 104.729 6.894 104.819 ;
     RECT  7.74 104.549 8.406 104.819 ;
     RECT  9.36 104.009 9.378 104.819 ;
     RECT  30.852 104.009 30.87 104.827 ;
     RECT  0.252 104.731 0.27 104.861 ;
     RECT  30.78 104.827 30.87 104.935 ;
     RECT  31.932 104.189 34.218 104.935 ;
     RECT  10.515 102.029 10.797 105.205 ;
     RECT  30.78 104.935 34.254 105.211 ;
     RECT  35.352 104.539 35.982 105.211 ;
     RECT  7.815 104.819 8.406 105.241 ;
     RECT  30.78 105.211 35.982 105.269 ;
     RECT  2.304 104.819 6.786 105.359 ;
     RECT  10.515 105.205 10.818 105.359 ;
     RECT  35.352 105.269 35.982 105.431 ;
     RECT  7.815 105.241 8.586 105.511 ;
     RECT  4.032 105.359 6.786 105.665 ;
     RECT  4.104 105.665 6.786 105.745 ;
     RECT  7.815 105.511 9.09 105.745 ;
     RECT  4.104 105.745 9.09 105.781 ;
     RECT  2.304 105.359 3.222 105.835 ;
     RECT  30.78 105.269 34.326 105.899 ;
     RECT  4.104 105.781 9.522 105.971 ;
     RECT  30.852 105.899 34.326 106.169 ;
     RECT  31.752 106.169 34.326 106.171 ;
     RECT  35.352 105.431 35.946 106.171 ;
     RECT  2.268 105.835 3.222 106.205 ;
     RECT  2.304 106.205 3.222 106.321 ;
     RECT  31.752 106.171 35.946 106.363 ;
     RECT  2.304 106.321 3.258 106.411 ;
     RECT  4.104 105.971 9.09 106.439 ;
     RECT  6.336 106.439 8.097 106.475 ;
     RECT  10.515 105.359 10.797 106.483 ;
     RECT  21.315 88.637 21.597 106.483 ;
     RECT  6.336 106.475 6.93 106.583 ;
     RECT  9.072 106.439 9.09 106.583 ;
     RECT  10.515 106.483 10.854 106.583 ;
     RECT  21.096 106.483 21.597 106.745 ;
     RECT  30.852 106.169 30.87 106.789 ;
     RECT  30.78 106.789 30.87 106.817 ;
     RECT  2.304 106.411 3.366 106.825 ;
     RECT  4.104 106.439 5.397 106.825 ;
     RECT  31.752 106.363 35.982 106.889 ;
     RECT  31.752 106.889 35.946 106.979 ;
     RECT  0.252 107.035 0.27 107.165 ;
     RECT  6.336 106.583 6.858 107.321 ;
     RECT  6.696 107.321 6.858 107.401 ;
     RECT  6.696 107.401 6.966 107.429 ;
     RECT  6.804 107.429 6.966 107.527 ;
     RECT  7.815 106.475 8.097 107.527 ;
     RECT  2.304 106.825 5.397 107.563 ;
     RECT  32.115 106.979 35.946 107.659 ;
     RECT  6.804 107.527 8.097 107.671 ;
     RECT  30.78 106.817 30.834 107.761 ;
     RECT  32.115 107.659 35.982 107.803 ;
     RECT  32.115 107.803 36.018 107.905 ;
     RECT  6.804 107.671 8.226 107.933 ;
     RECT  9.144 107.761 9.162 107.933 ;
     RECT  30.78 107.761 30.87 107.969 ;
     RECT  31.716 107.905 36.018 108.103 ;
     RECT  31.356 108.103 36.018 108.509 ;
     RECT  2.304 107.563 5.886 108.751 ;
     RECT  6.804 107.933 8.097 108.751 ;
     RECT  0.252 107.947 0.27 108.797 ;
     RECT  2.304 108.751 8.37 108.869 ;
     RECT  31.356 108.509 35.946 108.869 ;
     RECT  2.304 108.869 6.21 109.049 ;
     RECT  30.78 109.147 30.87 109.247 ;
     RECT  2.304 109.049 2.97 109.319 ;
     RECT  2.304 109.319 2.754 109.561 ;
     RECT  2.268 109.561 2.754 109.613 ;
     RECT  30.852 109.247 30.87 109.651 ;
     RECT  31.86 108.869 35.946 109.651 ;
     RECT  30.852 109.651 35.946 109.679 ;
     RECT  3.744 109.049 6.21 109.751 ;
     RECT  30.852 109.679 31.23 109.751 ;
     RECT  6.948 108.869 8.298 109.759 ;
     RECT  30.852 109.751 30.87 109.823 ;
     RECT  6.948 109.759 9.018 109.949 ;
     RECT  6.948 109.949 8.19 109.957 ;
     RECT  6.768 109.957 8.19 110.021 ;
     RECT  2.304 109.613 2.754 110.065 ;
     RECT  3.744 109.751 5.994 110.065 ;
     RECT  32.04 109.679 35.946 110.327 ;
     RECT  9.036 109.993 9.054 110.399 ;
     RECT  0.252 110.395 0.27 110.525 ;
     RECT  32.04 110.327 34.254 110.525 ;
     RECT  35.352 110.327 35.946 110.539 ;
     RECT  2.304 110.065 5.994 110.641 ;
     RECT  2.304 110.641 6.03 110.839 ;
     RECT  6.768 110.021 8.097 110.839 ;
     RECT  30.78 110.335 30.798 110.875 ;
     RECT  2.304 110.839 8.097 111.001 ;
     RECT  35.352 110.539 35.982 111.067 ;
     RECT  30.78 110.875 30.87 111.101 ;
     RECT  2.304 111.001 8.154 111.137 ;
     RECT  35.352 111.067 36.018 111.479 ;
     RECT  10.515 106.583 10.797 111.541 ;
     RECT  32.115 110.525 34.254 111.547 ;
     RECT  35.352 111.479 35.982 111.547 ;
     RECT  32.115 111.547 35.982 111.641 ;
     RECT  0.252 111.547 0.27 111.677 ;
     RECT  32.115 111.641 35.946 111.685 ;
     RECT  30.78 111.101 30.798 112.019 ;
     RECT  32.004 111.685 35.946 112.081 ;
     RECT  9.792 111.541 10.797 112.109 ;
     RECT  2.304 111.137 8.118 112.261 ;
     RECT  10.515 112.109 10.797 112.351 ;
     RECT  2.304 112.261 8.802 112.387 ;
     RECT  10.515 112.351 10.818 112.451 ;
     RECT  2.304 112.387 8.946 112.459 ;
     RECT  2.304 112.459 9.018 112.559 ;
     RECT  31.716 112.081 35.946 112.651 ;
     RECT  31.716 112.651 35.982 112.829 ;
     RECT  30.852 113.035 30.87 113.333 ;
     RECT  32.004 112.829 35.982 113.567 ;
     RECT  2.304 112.559 8.658 113.575 ;
     RECT  2.304 113.575 9.306 113.611 ;
     RECT  2.304 113.611 9.342 113.729 ;
     RECT  29.415 88.889 29.697 113.773 ;
     RECT  0.252 113.659 0.27 113.789 ;
     RECT  2.304 113.729 6.858 113.801 ;
     RECT  32.004 113.567 35.946 113.801 ;
     RECT  9.324 113.729 9.342 113.837 ;
     RECT  32.004 113.801 35.406 113.845 ;
     RECT  31.068 113.845 35.406 113.873 ;
     RECT  31.068 113.873 35.37 113.999 ;
     RECT  0.216 114.379 0.234 114.509 ;
     RECT  7.704 113.729 8.55 114.539 ;
     RECT  29.088 113.773 29.697 114.539 ;
     RECT  31.068 113.999 35.046 114.547 ;
     RECT  2.304 113.801 6.534 114.647 ;
     RECT  2.304 114.647 6.39 114.955 ;
     RECT  7.704 114.539 8.097 114.961 ;
     RECT  30.78 114.547 35.046 114.989 ;
     RECT  30.816 114.989 35.046 115.349 ;
     RECT  2.268 114.955 6.39 115.393 ;
     RECT  7.272 114.961 8.097 115.393 ;
     RECT  2.268 115.393 8.097 115.501 ;
     RECT  2.268 115.501 8.226 115.771 ;
     RECT  10.515 112.451 10.797 115.771 ;
     RECT  31.824 115.349 35.046 115.799 ;
     RECT  10.515 115.771 10.854 115.897 ;
     RECT  30.816 115.349 30.87 115.897 ;
     RECT  30.78 115.897 30.87 115.961 ;
     RECT  30.78 115.961 30.834 116.033 ;
     RECT  10.515 115.897 10.926 116.069 ;
     RECT  2.268 115.771 8.37 116.195 ;
     RECT  32.115 115.799 35.046 116.395 ;
     RECT  0.216 115.579 0.234 116.429 ;
     RECT  2.268 116.195 4.05 116.465 ;
     RECT  4.824 116.195 8.37 116.581 ;
     RECT  30.78 116.033 30.798 116.609 ;
     RECT  4.824 116.581 8.694 116.699 ;
     RECT  2.304 116.465 4.05 116.735 ;
     RECT  6.228 116.699 6.93 116.735 ;
     RECT  7.815 116.699 8.694 116.735 ;
     RECT  3.564 116.735 4.05 116.771 ;
     RECT  4.032 116.771 4.05 116.969 ;
     RECT  6.228 116.735 6.75 116.969 ;
     RECT  2.415 116.735 2.79 117.005 ;
     RECT  4.824 116.699 5.397 117.005 ;
     RECT  7.815 116.735 8.622 117.149 ;
     RECT  32.115 116.395 35.37 117.509 ;
     RECT  36.468 114.475 36.486 117.689 ;
     RECT  35.352 117.509 35.37 117.779 ;
     RECT  32.115 117.509 34.398 118.085 ;
     RECT  34.38 118.085 34.398 118.157 ;
     RECT  32.115 118.085 33.606 118.319 ;
     RECT  32.115 118.319 32.886 118.355 ;
     RECT  2.415 117.005 2.697 118.547 ;
     RECT  5.115 117.005 5.397 118.547 ;
     RECT  7.815 117.149 8.097 118.547 ;
     RECT  10.515 116.069 10.797 118.547 ;
     RECT  13.215 88.637 13.497 118.547 ;
     RECT  15.915 2.413 16.197 118.547 ;
     RECT  18.615 2.413 18.897 118.547 ;
     RECT  21.315 106.745 21.597 118.547 ;
     RECT  24.015 2.413 24.297 118.547 ;
     RECT  26.715 41.741 26.997 118.547 ;
     RECT  29.415 114.539 29.697 118.547 ;
     RECT  32.115 118.355 32.397 118.547 ;
     RECT  2.415 118.547 2.505 118.817 ;
     RECT  5.115 118.547 5.205 118.817 ;
     RECT  7.815 118.547 7.905 118.817 ;
     RECT  10.515 118.547 10.605 118.817 ;
     RECT  13.215 118.547 13.305 118.817 ;
     RECT  15.915 118.547 16.005 118.817 ;
     RECT  18.615 118.547 18.705 118.817 ;
     RECT  21.315 118.547 21.405 118.817 ;
     RECT  24.015 118.547 24.105 118.817 ;
     RECT  26.715 118.547 26.805 118.817 ;
     RECT  29.415 118.547 29.505 118.817 ;
     RECT  32.115 118.547 32.205 118.817 ;
     RECT  18.18 120.828 18.198 120.845 ;
    LAYER M4 ;
     RECT  0.156 4.416 2.408 116.616 ;
     RECT  2.408 2.148 2.512 118.812 ;
     RECT  2.512 2.418 2.704 118.542 ;
     RECT  2.704 99.696 2.729 101.976 ;
     RECT  2.704 12.864 2.765 12.888 ;
     RECT  2.704 14.496 2.765 14.52 ;
     RECT  2.704 15.792 2.765 16.344 ;
     RECT  2.704 17.712 2.765 17.736 ;
     RECT  2.704 32.256 2.765 36.888 ;
     RECT  2.704 53.52 2.765 57.096 ;
     RECT  2.704 68.928 2.765 75.192 ;
     RECT  2.704 76.272 2.765 76.392 ;
     RECT  2.704 91.104 2.765 93.864 ;
     RECT  2.704 102.96 2.765 103.608 ;
     RECT  2.704 104.832 2.765 107.064 ;
     RECT  2.704 108.096 2.765 109.272 ;
     RECT  2.704 110.256 2.765 110.52 ;
     RECT  2.704 28.272 2.801 29.592 ;
     RECT  2.704 66.336 2.801 67.656 ;
     RECT  2.704 82.416 2.801 82.824 ;
     RECT  2.765 93.84 2.801 93.864 ;
     RECT  2.704 116.256 2.801 116.28 ;
     RECT  2.704 25.44 2.837 27.144 ;
     RECT  2.765 70.56 2.837 75.192 ;
     RECT  2.704 18.72 2.873 21.48 ;
     RECT  2.837 25.44 2.873 26.616 ;
     RECT  2.765 53.52 2.873 55.704 ;
     RECT  2.704 60.912 2.873 61.464 ;
     RECT  2.704 86.496 2.873 86.52 ;
     RECT  2.704 87.6 2.873 88.536 ;
     RECT  2.704 97.92 2.873 98.04 ;
     RECT  2.765 104.832 2.873 104.856 ;
     RECT  2.765 106.512 2.873 107.064 ;
     RECT  2.765 108.096 2.873 108.696 ;
     RECT  2.765 110.496 2.873 110.52 ;
     RECT  2.704 112.656 2.873 114.408 ;
     RECT  2.704 38.208 2.909 39.768 ;
     RECT  2.704 41.472 2.909 47.496 ;
     RECT  2.704 48.96 2.909 52.296 ;
     RECT  2.801 82.416 2.909 82.68 ;
     RECT  2.729 99.696 2.909 100.824 ;
     RECT  2.765 103.584 2.909 103.608 ;
     RECT  2.873 108.144 2.909 108.696 ;
     RECT  2.704 10.08 2.981 11.208 ;
     RECT  2.909 41.472 2.981 44.376 ;
     RECT  2.765 56.832 2.981 57.096 ;
     RECT  2.729 101.952 2.981 101.976 ;
     RECT  2.873 106.512 2.981 107.016 ;
     RECT  2.765 15.84 3.017 16.344 ;
     RECT  2.873 20.16 3.017 21.48 ;
     RECT  2.765 33.024 3.017 36.888 ;
     RECT  2.801 67.632 3.017 67.656 ;
     RECT  2.873 112.656 3.017 113.88 ;
     RECT  2.873 18.72 3.089 18.744 ;
     RECT  2.801 66.336 3.089 66.6 ;
     RECT  3.017 16.32 3.125 16.344 ;
     RECT  3.017 21.456 3.125 21.48 ;
     RECT  2.704 30.624 3.125 30.648 ;
     RECT  2.873 61.392 3.197 61.416 ;
     RECT  2.981 10.656 3.233 11.208 ;
     RECT  2.704 23.904 3.233 24.408 ;
     RECT  2.909 49.488 3.233 51.672 ;
     RECT  2.981 106.992 3.233 107.016 ;
     RECT  2.909 108.144 3.233 108.264 ;
     RECT  2.765 91.104 3.269 92.184 ;
     RECT  3.269 91.104 3.305 91.8 ;
     RECT  3.233 11.184 3.341 11.208 ;
     RECT  2.873 25.44 3.341 26.184 ;
     RECT  2.704 96.192 3.341 96.216 ;
     RECT  2.704 111.648 3.341 111.672 ;
     RECT  3.017 20.16 3.377 20.424 ;
     RECT  2.981 41.664 3.377 44.376 ;
     RECT  2.801 29.088 3.413 29.544 ;
     RECT  3.233 49.488 3.413 51.144 ;
     RECT  2.704 64.944 3.413 64.968 ;
     RECT  3.017 33.024 3.443 36.696 ;
     RECT  2.704 58.272 3.457 59.928 ;
     RECT  2.704 79.824 3.491 81.384 ;
     RECT  3.017 113.856 3.521 113.88 ;
     RECT  2.909 82.656 3.529 82.68 ;
     RECT  3.491 79.824 3.683 80.088 ;
     RECT  2.765 68.928 3.733 69.576 ;
     RECT  2.837 70.56 3.733 74.712 ;
     RECT  2.704 77.616 3.769 78.648 ;
     RECT  2.873 98.016 3.769 98.04 ;
     RECT  2.909 100.224 3.805 100.824 ;
     RECT  2.873 88.224 3.829 88.536 ;
     RECT  2.704 89.52 3.829 89.88 ;
     RECT  3.733 68.928 3.836 74.712 ;
     RECT  3.491 81.36 3.841 81.384 ;
     RECT  2.704 4.512 3.875 4.536 ;
     RECT  3.788 25.056 3.875 25.08 ;
     RECT  3.829 88.224 3.875 89.88 ;
     RECT  3.805 23.088 3.877 23.544 ;
     RECT  2.909 45.504 3.877 47.496 ;
     RECT  3.836 68.928 3.877 75.384 ;
     RECT  2.765 76.368 3.877 76.392 ;
     RECT  3.877 22.752 3.913 23.544 ;
     RECT  3.829 6.528 3.916 6.888 ;
     RECT  3.829 30.816 3.917 31.032 ;
     RECT  3.877 68.928 3.925 76.392 ;
     RECT  3.769 77.52 3.925 78.648 ;
     RECT  3.769 98.016 3.925 98.616 ;
     RECT  3.841 114.576 3.925 114.6 ;
     RECT  3.877 115.728 3.925 115.752 ;
     RECT  2.873 54.048 3.949 55.704 ;
     RECT  2.981 57.024 3.949 57.096 ;
     RECT  3.457 58.272 3.949 59.88 ;
     RECT  3.917 30.816 3.961 30.84 ;
     RECT  3.805 94.08 3.971 94.104 ;
     RECT  3.925 114.576 3.971 115.752 ;
     RECT  3.877 27.888 3.973 27.912 ;
     RECT  3.377 41.664 3.98 42.984 ;
     RECT  3.017 112.656 3.985 112.872 ;
     RECT  3.413 29.088 4.019 29.112 ;
     RECT  3.949 12.528 4.021 12.936 ;
     RECT  3.913 18.768 4.021 18.792 ;
     RECT  3.877 45.504 4.021 48.408 ;
     RECT  2.704 62.64 4.021 62.664 ;
     RECT  3.733 86.64 4.021 87.144 ;
     RECT  3.973 27.216 4.025 27.912 ;
     RECT  4.021 45.408 4.057 48.408 ;
     RECT  3.341 26.16 4.06 26.184 ;
     RECT  4.025 27.216 4.06 27.24 ;
     RECT  3.841 81.36 4.061 81.432 ;
     RECT  3.875 88.368 4.061 89.88 ;
     RECT  4.021 86.016 4.067 87.144 ;
     RECT  4.021 18.768 4.093 18.936 ;
     RECT  3.925 68.928 4.097 78.648 ;
     RECT  4.093 18.72 4.105 18.936 ;
     RECT  4.067 86.016 4.108 86.664 ;
     RECT  3.913 103.728 4.117 103.752 ;
     RECT  3.913 16.416 4.172 16.44 ;
     RECT  3.233 108.24 4.201 108.264 ;
     RECT  4.165 11.472 4.237 11.496 ;
     RECT  4.021 12.528 4.237 13.08 ;
     RECT  3.949 54.048 4.268 55.992 ;
     RECT  3.949 57.024 4.268 59.88 ;
     RECT  3.805 14.256 4.309 14.28 ;
     RECT  3.925 98.016 4.309 98.664 ;
     RECT  4.237 11.472 4.316 13.08 ;
     RECT  4.097 70.08 4.345 78.648 ;
     RECT  3.683 79.824 4.345 79.848 ;
     RECT  4.337 9.12 4.357 9.144 ;
     RECT  4.316 11.424 4.357 13.08 ;
     RECT  4.309 14.256 4.357 14.376 ;
     RECT  3.089 66.336 4.357 66.36 ;
     RECT  4.117 103.728 4.381 104.28 ;
     RECT  3.913 22.176 4.412 23.544 ;
     RECT  2.909 38.208 4.412 38.232 ;
     RECT  2.909 39.744 4.412 39.768 ;
     RECT  4.345 17.616 4.417 17.64 ;
     RECT  4.412 37.44 4.417 39.768 ;
     RECT  3.98 41.232 4.417 42.984 ;
     RECT  4.172 16.416 4.453 16.488 ;
     RECT  4.417 17.616 4.453 17.688 ;
     RECT  3.377 20.16 4.453 20.184 ;
     RECT  3.443 33.024 4.453 36.264 ;
     RECT  4.268 52.416 4.453 52.44 ;
     RECT  4.061 81.408 4.453 81.432 ;
     RECT  4.309 98.016 4.453 99.192 ;
     RECT  3.805 100.224 4.453 101.304 ;
     RECT  4.076 106.368 4.453 106.392 ;
     RECT  3.985 112.32 4.453 112.872 ;
     RECT  4.412 21.552 4.489 23.544 ;
     RECT  3.769 110.736 4.489 110.76 ;
     RECT  4.453 112.32 4.489 113.448 ;
     RECT  4.268 54.048 4.501 59.88 ;
     RECT  4.453 97.776 4.501 99.192 ;
     RECT  3.413 49.488 4.517 50.808 ;
     RECT  4.201 108.24 4.525 108.504 ;
     RECT  4.501 96.864 4.549 99.192 ;
     RECT  2.704 7.92 4.556 7.944 ;
     RECT  4.357 9.12 4.556 9.96 ;
     RECT  3.377 44.352 4.556 44.376 ;
     RECT  4.057 45.36 4.556 48.408 ;
     RECT  4.489 110.736 4.556 113.448 ;
     RECT  3.925 61.632 4.561 61.656 ;
     RECT  4.093 64.464 4.561 64.776 ;
     RECT  4.357 66.336 4.561 67.176 ;
     RECT  3.916 6.864 4.597 6.888 ;
     RECT  4.556 7.92 4.597 9.96 ;
     RECT  4.453 33.024 4.597 36.456 ;
     RECT  4.453 52.416 4.597 52.872 ;
     RECT  4.453 100.224 4.597 101.352 ;
     RECT  3.973 102.624 4.597 102.648 ;
     RECT  4.453 106.368 4.597 107.16 ;
     RECT  4.525 108.24 4.597 109.464 ;
     RECT  3.949 83.232 4.645 83.256 ;
     RECT  4.061 89.52 4.669 89.88 ;
     RECT  4.357 11.424 4.741 14.376 ;
     RECT  3.305 91.152 4.741 91.8 ;
     RECT  4.46 95.712 4.741 95.736 ;
     RECT  4.597 100.224 4.741 102.648 ;
     RECT  4.381 103.728 4.741 104.856 ;
     RECT  4.597 32.208 4.777 36.456 ;
     RECT  4.417 37.44 4.777 42.984 ;
     RECT  4.645 83.088 4.813 83.256 ;
     RECT  4.741 91.152 4.844 93 ;
     RECT  4.093 94.032 4.844 94.056 ;
     RECT  4.741 95.04 4.844 95.736 ;
     RECT  4.549 96.768 4.844 99.192 ;
     RECT  4.597 52.32 4.885 52.872 ;
     RECT  4.556 110.544 4.885 113.448 ;
     RECT  4.597 106.368 4.957 109.464 ;
     RECT  4.777 32.208 4.981 42.984 ;
     RECT  4.501 54.048 5.065 60.216 ;
     RECT  4.561 61.536 5.065 61.656 ;
     RECT  4.525 4.944 5.108 4.968 ;
     RECT  4.597 6.864 5.108 9.96 ;
     RECT  4.741 11.424 5.108 14.904 ;
     RECT  4.453 16.416 5.108 17.688 ;
     RECT  4.105 18.72 5.108 18.792 ;
     RECT  4.453 19.872 5.108 20.184 ;
     RECT  4.489 21.552 5.108 24.504 ;
     RECT  4.345 26.544 5.108 26.76 ;
     RECT  4.405 28.416 5.108 28.44 ;
     RECT  4.669 29.76 5.108 29.784 ;
     RECT  4.981 32.208 5.108 43.32 ;
     RECT  4.556 44.352 5.108 48.408 ;
     RECT  4.517 49.488 5.108 51.336 ;
     RECT  4.885 52.32 5.108 52.968 ;
     RECT  5.065 54.048 5.108 61.656 ;
     RECT  4.021 62.64 5.108 63.24 ;
     RECT  4.561 64.464 5.108 67.704 ;
     RECT  4.316 68.784 5.108 68.808 ;
     RECT  4.345 70.08 5.108 79.848 ;
     RECT  4.453 81.408 5.108 81.624 ;
     RECT  4.813 82.704 5.108 83.256 ;
     RECT  4.561 84.384 5.108 84.408 ;
     RECT  4.933 85.584 5.108 85.608 ;
     RECT  4.108 86.64 5.108 86.664 ;
     RECT  4.061 88.368 5.108 88.536 ;
     RECT  4.669 89.52 5.108 90.024 ;
     RECT  4.844 91.152 5.108 94.056 ;
     RECT  4.844 95.04 5.108 99.192 ;
     RECT  4.741 100.224 5.108 104.856 ;
     RECT  4.957 105.984 5.108 109.464 ;
     RECT  4.885 110.544 5.108 113.88 ;
     RECT  3.971 114.96 5.108 115.176 ;
     RECT  5.108 2.148 5.212 118.812 ;
     RECT  5.212 2.418 5.404 118.542 ;
     RECT  5.404 101.28 5.465 104.856 ;
     RECT  5.404 70.08 5.537 78.696 ;
     RECT  5.404 26.208 5.555 30.84 ;
     RECT  5.404 44.352 5.555 51.24 ;
     RECT  5.404 107.28 5.555 107.832 ;
     RECT  5.404 108.96 5.555 108.984 ;
     RECT  5.404 15.36 5.603 17.64 ;
     RECT  5.404 8.544 5.609 8.568 ;
     RECT  5.555 26.208 5.609 26.472 ;
     RECT  5.404 53.904 5.609 61.608 ;
     RECT  5.404 88.608 5.609 90.024 ;
     RECT  5.404 94.992 5.609 95.688 ;
     RECT  5.404 22.176 5.644 25.176 ;
     RECT  5.555 27.744 5.651 30.84 ;
     RECT  5.404 31.824 5.651 38.712 ;
     RECT  5.465 101.28 5.651 104.28 ;
     RECT  5.404 96.768 5.653 100.248 ;
     RECT  5.404 14.112 5.681 14.232 ;
     RECT  5.404 84.192 5.681 85.896 ;
     RECT  5.609 56.88 5.699 61.608 ;
     RECT  5.404 65.376 5.699 66.216 ;
     RECT  5.404 67.248 5.699 68.664 ;
     RECT  5.404 80.736 5.699 83.208 ;
     RECT  5.651 27.744 5.753 29.688 ;
     RECT  5.651 31.824 5.753 38.616 ;
     RECT  5.404 105.984 5.753 106.008 ;
     RECT  5.404 9.648 5.789 11.496 ;
     RECT  5.753 31.824 5.789 36.6 ;
     RECT  5.537 70.08 5.789 78.072 ;
     RECT  5.555 44.352 5.825 50.328 ;
     RECT  5.404 62.832 5.825 64.344 ;
     RECT  5.699 56.88 5.833 61.32 ;
     RECT  5.603 17.088 5.891 17.64 ;
     RECT  5.404 19.2 5.891 20.04 ;
     RECT  5.699 80.736 5.891 82.104 ;
     RECT  5.609 94.992 5.891 95.16 ;
     RECT  5.653 96.768 5.891 97.704 ;
     RECT  5.653 99.12 5.891 100.248 ;
     RECT  5.699 67.248 5.897 67.272 ;
     RECT  5.681 14.208 5.932 14.232 ;
     RECT  5.603 15.36 5.932 15.864 ;
     RECT  5.891 19.824 5.933 20.04 ;
     RECT  5.753 37.584 5.933 38.616 ;
     RECT  5.789 70.656 5.939 78.072 ;
     RECT  5.939 70.656 5.987 74.664 ;
     RECT  5.644 22.176 6.035 24.792 ;
     RECT  5.651 30.816 6.035 30.84 ;
     RECT  5.651 101.28 6.035 102.648 ;
     RECT  5.404 111.12 6.035 112.056 ;
     RECT  5.789 9.648 6.041 11.4 ;
     RECT  6.035 22.176 6.076 24.072 ;
     RECT  5.404 113.616 6.076 113.64 ;
     RECT  5.833 56.88 6.077 60.264 ;
     RECT  6.035 101.28 6.077 102.552 ;
     RECT  5.404 52.416 6.083 52.44 ;
     RECT  5.609 53.904 6.083 55.272 ;
     RECT  6.076 22.176 6.085 22.824 ;
     RECT  5.699 68.256 6.113 68.664 ;
     RECT  5.789 31.824 6.149 32.472 ;
     RECT  5.404 114.816 6.149 114.84 ;
     RECT  6.085 22.224 6.185 22.776 ;
     RECT  5.833 61.296 6.227 61.32 ;
     RECT  5.404 13.056 6.275 13.08 ;
     RECT  5.753 29.04 6.275 29.688 ;
     RECT  6.149 32.448 6.275 32.472 ;
     RECT  6.077 56.88 6.275 60.024 ;
     RECT  5.932 15.36 6.293 15.384 ;
     RECT  5.987 71.28 6.293 74.664 ;
     RECT  5.404 92.304 6.323 92.328 ;
     RECT  5.789 34.08 6.329 36.6 ;
     RECT  6.275 59.712 6.329 60.024 ;
     RECT  5.891 94.992 6.364 95.016 ;
     RECT  5.404 93.888 6.365 93.912 ;
     RECT  5.555 107.28 6.365 107.304 ;
     RECT  6.113 68.64 6.371 68.664 ;
     RECT  5.681 85.344 6.371 85.896 ;
     RECT  5.404 42.72 6.397 43.32 ;
     RECT  5.609 26.448 6.419 26.472 ;
     RECT  5.825 44.352 6.419 50.04 ;
     RECT  5.404 5.856 6.421 6.84 ;
     RECT  6.275 29.04 6.429 29.064 ;
     RECT  5.404 79.68 6.437 79.704 ;
     RECT  5.753 27.744 6.46 27.768 ;
     RECT  6.421 5.712 6.467 6.84 ;
     RECT  6.397 42.72 6.467 43.368 ;
     RECT  6.467 43.248 6.481 43.368 ;
     RECT  6.329 34.608 6.515 36.6 ;
     RECT  5.933 37.584 6.515 37.608 ;
     RECT  5.933 38.592 6.515 38.616 ;
     RECT  5.404 39.744 6.515 41.736 ;
     RECT  6.083 54.048 6.545 55.272 ;
     RECT  6.077 101.712 6.545 102.552 ;
     RECT  6.419 44.352 6.563 47.88 ;
     RECT  5.939 76.032 6.563 78.072 ;
     RECT  5.891 97.68 6.563 97.704 ;
     RECT  5.891 17.088 6.577 17.112 ;
     RECT  6.275 56.88 6.589 58.728 ;
     RECT  5.891 99.744 6.589 100.248 ;
     RECT  6.572 51.216 6.613 51.24 ;
     RECT  6.035 111.12 6.653 111.144 ;
     RECT  6.076 24.048 6.659 24.072 ;
     RECT  6.613 51.216 6.659 51.912 ;
     RECT  6.185 22.416 6.661 22.776 ;
     RECT  5.699 83.184 6.685 83.208 ;
     RECT  5.681 84.192 6.685 84.216 ;
     RECT  6.685 83.184 6.689 84.216 ;
     RECT  6.589 100.224 6.689 100.248 ;
     RECT  6.661 22.416 6.725 22.728 ;
     RECT  6.721 87.072 6.829 87.096 ;
     RECT  5.609 88.608 6.829 89.736 ;
     RECT  6.829 87.072 6.833 89.736 ;
     RECT  6.888 7.872 6.937 7.896 ;
     RECT  6.577 16.416 6.937 17.112 ;
     RECT  6.937 26.016 7.093 26.04 ;
     RECT  6.833 87.888 7.1 89.736 ;
     RECT  6.041 10.464 7.103 11.4 ;
     RECT  6.545 55.152 7.117 55.272 ;
     RECT  6.689 83.664 7.117 84.216 ;
     RECT  7.1 87.888 7.117 90.216 ;
     RECT  7.103 9.744 7.141 11.4 ;
     RECT  5.404 109.968 7.148 109.992 ;
     RECT  6.721 105.936 7.151 105.96 ;
     RECT  7.148 109.68 7.153 109.992 ;
     RECT  7.117 108.528 7.189 108.552 ;
     RECT  6.515 41.616 7.225 41.736 ;
     RECT  5.825 64.32 7.225 64.344 ;
     RECT  7.196 27.84 7.237 27.864 ;
     RECT  5.891 81.6 7.237 82.104 ;
     RECT  6.293 71.76 7.244 74.664 ;
     RECT  6.563 76.032 7.244 76.824 ;
     RECT  5.825 62.832 7.261 62.856 ;
     RECT  7.244 71.76 7.261 76.824 ;
     RECT  7.117 55.152 7.285 55.848 ;
     RECT  6.589 56.88 7.285 58.152 ;
     RECT  7.117 83.664 7.333 84.264 ;
     RECT  6.937 7.872 7.381 8.52 ;
     RECT  7.141 9.744 7.381 11.448 ;
     RECT  6.911 18.672 7.381 18.696 ;
     RECT  7.261 38.64 7.397 38.664 ;
     RECT  6.515 39.744 7.397 40.44 ;
     RECT  7.261 62.16 7.429 62.856 ;
     RECT  7.225 64.32 7.429 64.824 ;
     RECT  7.117 87.888 7.429 90.984 ;
     RECT  7.381 111.552 7.429 111.576 ;
     RECT  7.153 112.896 7.429 112.92 ;
     RECT  6.419 49.488 7.477 50.04 ;
     RECT  6.515 34.608 7.649 34.632 ;
     RECT  6.515 35.76 7.649 36.6 ;
     RECT  6.371 85.872 7.657 85.896 ;
     RECT  6.329 60 7.669 60.024 ;
     RECT  7.657 85.872 7.669 86.664 ;
     RECT  7.649 34.608 7.693 36.6 ;
     RECT  6.481 43.248 7.693 43.272 ;
     RECT  6.467 5.712 7.808 6.12 ;
     RECT  7.381 7.872 7.808 11.448 ;
     RECT  7.381 12.528 7.808 12.552 ;
     RECT  7.045 13.584 7.808 13.608 ;
     RECT  7.004 14.88 7.808 14.904 ;
     RECT  6.937 16.224 7.808 17.112 ;
     RECT  7.381 18.144 7.808 18.696 ;
     RECT  5.933 19.824 7.808 19.896 ;
     RECT  7.477 20.976 7.808 21 ;
     RECT  6.725 22.416 7.808 22.44 ;
     RECT  7.052 23.808 7.808 23.832 ;
     RECT  7.093 25.44 7.808 26.04 ;
     RECT  7.237 27.84 7.808 28.68 ;
     RECT  7.657 30.72 7.808 30.744 ;
     RECT  7.669 32.304 7.808 32.328 ;
     RECT  7.693 34.464 7.808 36.6 ;
     RECT  7.397 38.64 7.808 40.44 ;
     RECT  7.225 41.616 7.808 42.024 ;
     RECT  7.693 43.104 7.808 43.272 ;
     RECT  6.563 44.352 7.808 46.152 ;
     RECT  6.563 47.232 7.808 47.88 ;
     RECT  7.477 49.488 7.808 50.136 ;
     RECT  6.659 51.504 7.808 51.912 ;
     RECT  6.545 54.048 7.808 54.12 ;
     RECT  7.285 55.152 7.808 58.152 ;
     RECT  7.669 59.232 7.808 60.024 ;
     RECT  7.429 61.44 7.808 66.216 ;
     RECT  7.333 67.248 7.808 67.272 ;
     RECT  7.297 68.352 7.808 68.376 ;
     RECT  6.613 69.504 7.808 69.528 ;
     RECT  7.117 70.704 7.808 70.728 ;
     RECT  7.261 71.712 7.808 76.824 ;
     RECT  6.901 78.24 7.808 78.264 ;
     RECT  6.901 79.248 7.808 79.272 ;
     RECT  7.237 81.312 7.808 82.392 ;
     RECT  7.333 83.664 7.808 84.36 ;
     RECT  7.669 85.776 7.808 86.664 ;
     RECT  7.429 87.888 7.808 91.8 ;
     RECT  7.009 93.216 7.808 93.24 ;
     RECT  7.669 96.48 7.808 96.504 ;
     RECT  7.608 98.064 7.808 98.088 ;
     RECT  7.765 100.32 7.808 100.344 ;
     RECT  6.545 101.712 7.808 102.36 ;
     RECT  5.651 104.256 7.808 104.28 ;
     RECT  7.151 105.936 7.808 106.296 ;
     RECT  7.189 107.76 7.808 108.552 ;
     RECT  7.153 109.68 7.808 110.328 ;
     RECT  7.429 111.552 7.808 113.448 ;
     RECT  7.621 114.432 7.808 114.456 ;
     RECT  7.117 115.824 7.808 115.848 ;
     RECT  7.808 2.148 7.912 118.812 ;
     RECT  7.912 2.418 8.104 118.542 ;
     RECT  8.104 17.088 8.201 17.112 ;
     RECT  8.104 26.016 8.201 26.04 ;
     RECT  8.104 50.016 8.201 50.04 ;
     RECT  8.104 59.856 8.201 60.024 ;
     RECT  8.104 6.096 8.237 6.12 ;
     RECT  8.104 104.832 8.237 106.296 ;
     RECT  8.104 41.712 8.243 43.128 ;
     RECT  8.104 70.992 8.243 71.736 ;
     RECT  8.104 100.32 8.243 102.6 ;
     RECT  8.237 106.272 8.243 106.296 ;
     RECT  8.243 42.768 8.245 43.128 ;
     RECT  8.104 33.6 8.273 34.536 ;
     RECT  8.104 44.448 8.273 44.472 ;
     RECT  8.104 56.784 8.273 57.864 ;
     RECT  8.243 100.32 8.273 101.208 ;
     RECT  8.243 70.992 8.281 71.016 ;
     RECT  8.245 43.104 8.309 43.128 ;
     RECT  8.243 102.576 8.345 102.6 ;
     RECT  8.104 13.584 8.381 13.608 ;
     RECT  8.273 56.784 8.381 56.904 ;
     RECT  8.201 60 8.381 60.024 ;
     RECT  8.104 84.336 8.381 84.36 ;
     RECT  8.104 32.304 8.417 32.328 ;
     RECT  8.273 101.184 8.417 101.208 ;
     RECT  8.104 103.728 8.417 103.752 ;
     RECT  8.237 104.832 8.417 104.856 ;
     RECT  8.273 34.464 8.483 34.536 ;
     RECT  8.104 35.664 8.483 36.36 ;
     RECT  8.104 61.44 8.489 61.464 ;
     RECT  8.104 79.248 8.489 79.272 ;
     RECT  8.381 56.88 8.525 56.904 ;
     RECT  8.104 73.344 8.525 73.656 ;
     RECT  8.483 34.464 8.597 34.488 ;
     RECT  8.483 35.76 8.597 35.784 ;
     RECT  8.243 41.712 10.508 41.736 ;
     RECT  8.525 73.632 10.508 73.656 ;
     RECT  8.104 88.704 10.508 88.728 ;
     RECT  8.104 89.712 10.508 89.736 ;
     RECT  8.104 93.216 10.508 93.24 ;
     RECT  9.385 103.488 10.508 103.512 ;
     RECT  10.508 2.148 10.612 118.812 ;
     RECT  10.612 2.418 10.804 118.542 ;
     RECT  10.804 41.616 13.208 41.64 ;
     RECT  10.804 73.632 13.208 73.656 ;
     RECT  10.804 88.608 13.208 88.632 ;
     RECT  10.804 89.712 13.208 89.736 ;
     RECT  10.804 93.216 13.208 93.24 ;
     RECT  10.804 103.488 13.208 103.512 ;
     RECT  13.208 2.148 13.312 118.812 ;
     RECT  13.312 2.418 13.504 118.542 ;
     RECT  13.504 41.616 14.821 41.64 ;
     RECT  13.504 88.608 14.821 88.632 ;
     RECT  14.821 41.616 14.861 41.736 ;
     RECT  14.821 88.608 14.861 88.728 ;
     RECT  14.861 41.712 15.908 41.736 ;
     RECT  13.504 73.632 15.908 73.656 ;
     RECT  14.861 88.704 15.908 88.728 ;
     RECT  13.504 89.712 15.908 89.736 ;
     RECT  13.504 93.216 15.908 93.24 ;
     RECT  13.504 103.488 15.908 103.512 ;
     RECT  15.908 2.148 16.012 118.812 ;
     RECT  16.012 2.418 16.204 118.542 ;
     RECT  5.749 120.816 18.209 120.84 ;
     RECT  16.204 41.712 18.608 41.736 ;
     RECT  16.204 73.632 18.608 73.656 ;
     RECT  16.204 88.704 18.608 88.728 ;
     RECT  16.204 89.712 18.608 89.736 ;
     RECT  16.204 93.216 18.608 93.24 ;
     RECT  16.204 103.488 18.608 103.512 ;
     RECT  18.608 2.148 18.712 118.812 ;
     RECT  18.712 2.418 18.904 118.542 ;
     RECT  18.904 41.616 21.308 41.64 ;
     RECT  18.904 73.632 21.308 73.656 ;
     RECT  18.904 88.608 21.308 88.632 ;
     RECT  18.904 89.712 21.308 89.736 ;
     RECT  18.904 93.216 21.308 93.24 ;
     RECT  18.904 103.488 21.308 103.512 ;
     RECT  21.308 2.148 21.412 118.812 ;
     RECT  21.412 2.418 21.604 118.542 ;
     RECT  21.604 88.608 22.813 88.632 ;
     RECT  22.813 88.608 22.853 88.728 ;
     RECT  21.604 41.616 23.893 41.64 ;
     RECT  23.893 41.616 24.008 41.736 ;
     RECT  21.604 73.632 24.008 73.656 ;
     RECT  22.853 88.704 24.008 88.728 ;
     RECT  21.604 89.712 24.008 89.736 ;
     RECT  21.604 93.216 24.008 93.24 ;
     RECT  21.604 103.488 24.008 103.512 ;
     RECT  24.008 2.148 24.112 118.812 ;
     RECT  24.112 2.418 24.304 118.542 ;
     RECT  24.304 41.712 26.708 41.736 ;
     RECT  24.304 73.632 26.708 73.656 ;
     RECT  24.304 88.704 26.708 88.728 ;
     RECT  24.304 89.712 26.708 89.736 ;
     RECT  24.304 93.216 26.708 93.24 ;
     RECT  24.304 103.488 26.708 103.512 ;
     RECT  26.708 2.148 26.812 118.812 ;
     RECT  26.812 2.418 27.004 118.542 ;
     RECT  27.004 41.712 29.408 41.736 ;
     RECT  27.004 73.632 29.408 73.656 ;
     RECT  27.004 88.704 29.408 88.728 ;
     RECT  27.004 89.712 29.408 89.736 ;
     RECT  27.004 93.216 29.408 93.24 ;
     RECT  27.004 103.488 29.408 103.512 ;
     RECT  29.408 2.148 29.512 118.812 ;
     RECT  29.512 2.418 29.704 118.542 ;
     RECT  29.704 88.608 30.769 88.632 ;
     RECT  30.769 88.608 30.809 88.728 ;
     RECT  29.704 103.488 32.065 103.512 ;
     RECT  31.885 19.248 32.108 19.272 ;
     RECT  31.813 38.736 32.108 38.76 ;
     RECT  29.704 41.712 32.108 41.736 ;
     RECT  32.065 52.992 32.108 53.016 ;
     RECT  31.921 70.608 32.108 70.632 ;
     RECT  29.704 73.632 32.108 73.656 ;
     RECT  30.809 88.704 32.108 88.728 ;
     RECT  29.704 89.712 32.108 89.736 ;
     RECT  29.704 93.216 32.108 93.24 ;
     RECT  32.065 103.488 32.108 104.328 ;
     RECT  32.108 2.148 32.212 118.812 ;
     RECT  32.212 2.418 32.404 118.542 ;
     RECT  32.404 88.368 32.465 89.736 ;
     RECT  32.404 82.656 32.681 82.68 ;
     RECT  32.404 27.36 32.753 27.384 ;
     RECT  32.404 85.344 32.825 85.464 ;
     RECT  32.465 88.368 32.825 89.496 ;
     RECT  32.404 50.832 32.861 51.288 ;
     RECT  32.404 84.288 33.041 84.312 ;
     RECT  32.404 22.704 33.077 23.016 ;
     RECT  32.404 98.448 33.113 98.472 ;
     RECT  32.404 43.296 33.149 43.32 ;
     RECT  32.861 50.832 33.185 50.856 ;
     RECT  32.825 85.392 33.185 85.464 ;
     RECT  32.404 109.44 33.185 110.76 ;
     RECT  32.404 36.912 33.397 37.032 ;
     RECT  32.404 93.216 33.397 93.24 ;
     RECT  32.404 77.808 33.401 79.752 ;
     RECT  32.404 61.632 33.437 62.232 ;
     RECT  32.404 86.496 33.437 86.52 ;
     RECT  32.404 103.2 33.473 104.328 ;
     RECT  33.397 92.928 33.505 93.24 ;
     RECT  32.404 39.216 33.509 39.24 ;
     RECT  32.404 54.096 33.613 54.504 ;
     RECT  32.404 99.648 33.617 100.296 ;
     RECT  32.404 114.96 33.649 114.984 ;
     RECT  32.825 88.368 33.653 88.392 ;
     RECT  33.617 100.272 33.653 100.296 ;
     RECT  32.404 19.008 33.689 19.272 ;
     RECT  33.077 22.704 33.689 22.728 ;
     RECT  32.404 31.92 33.689 31.944 ;
     RECT  33.401 79.392 33.689 79.752 ;
     RECT  33.397 36.912 33.725 37.608 ;
     RECT  33.613 54.096 33.725 55.176 ;
     RECT  33.401 77.808 33.725 78.408 ;
     RECT  33.469 98.16 33.725 98.184 ;
     RECT  33.577 14.784 33.757 14.808 ;
     RECT  33.689 19.248 33.869 19.272 ;
     RECT  33.541 21.6 33.973 21.624 ;
     RECT  33.649 114.96 33.973 115.464 ;
     RECT  33.973 114.768 34.009 115.464 ;
     RECT  33.973 21.6 34.153 22.44 ;
     RECT  33.757 14.16 34.189 14.808 ;
     RECT  34.153 21.456 34.189 22.44 ;
     RECT  32.404 25.152 34.189 25.176 ;
     RECT  32.404 29.808 34.189 29.832 ;
     RECT  33.725 37.536 34.189 37.608 ;
     RECT  33.541 42.576 34.189 42.6 ;
     RECT  32.404 52.368 34.189 53.016 ;
     RECT  33.725 54.096 34.189 54.504 ;
     RECT  32.404 57.312 34.189 58.488 ;
     RECT  32.404 65.472 34.189 65.496 ;
     RECT  32.404 68.4 34.189 68.424 ;
     RECT  32.404 72.576 34.189 72.792 ;
     RECT  33.725 77.808 34.189 77.832 ;
     RECT  33.469 83.472 34.189 83.496 ;
     RECT  33.185 85.44 34.189 85.464 ;
     RECT  33.505 92.928 34.189 93.72 ;
     RECT  33.865 95.616 34.189 95.64 ;
     RECT  33.473 103.488 34.189 104.328 ;
     RECT  33.901 107.472 34.189 107.496 ;
     RECT  33.185 109.44 34.189 109.944 ;
     RECT  33.505 111.696 34.189 111.72 ;
     RECT  32.404 112.896 34.189 113.064 ;
     RECT  34.009 114.768 34.189 115.8 ;
     RECT  34.189 16.608 34.225 17.736 ;
     RECT  34.189 29.712 34.225 29.832 ;
     RECT  34.189 40.128 34.225 40.152 ;
     RECT  34.189 76.656 34.225 76.68 ;
     RECT  34.189 77.76 34.225 77.832 ;
     RECT  34.189 90.624 34.225 94.2 ;
     RECT  34.189 7.008 34.261 7.032 ;
     RECT  34.225 16.608 34.261 17.928 ;
     RECT  34.225 90.624 34.337 94.632 ;
     RECT  34.189 112.848 34.369 116.088 ;
     RECT  33.865 5.712 34.405 5.736 ;
     RECT  34.261 7.008 34.405 7.176 ;
     RECT  34.189 27.792 34.621 27.816 ;
     RECT  34.657 4.56 34.693 4.584 ;
     RECT  34.405 5.712 34.693 7.176 ;
     RECT  34.189 12.048 34.693 12.072 ;
     RECT  34.261 16.608 34.693 18.216 ;
     RECT  34.189 23.424 34.693 26.328 ;
     RECT  34.621 27.792 34.693 28.296 ;
     RECT  34.189 31.344 34.693 31.368 ;
     RECT  34.189 49.872 34.693 51.336 ;
     RECT  34.189 52.368 34.693 54.504 ;
     RECT  34.189 63.984 34.693 67.08 ;
     RECT  34.405 8.16 34.729 8.184 ;
     RECT  34.189 9.264 34.729 10.584 ;
     RECT  34.693 11.856 34.729 12.072 ;
     RECT  34.189 13.488 34.729 14.808 ;
     RECT  34.189 41.76 34.729 43.56 ;
     RECT  34.189 44.832 34.729 44.856 ;
     RECT  34.189 45.984 34.729 46.296 ;
     RECT  34.693 49.872 34.729 54.504 ;
     RECT  33.973 55.68 34.729 55.704 ;
     RECT  33.437 62.208 34.729 62.232 ;
     RECT  34.693 63.312 34.729 67.08 ;
     RECT  34.189 68.4 34.729 69.048 ;
     RECT  34.189 71.472 34.729 75.528 ;
     RECT  34.225 76.656 34.729 77.832 ;
     RECT  33.689 79.392 34.729 79.608 ;
     RECT  34.189 82.176 34.729 83.496 ;
     RECT  34.189 84.576 34.729 85.896 ;
     RECT  34.189 87.36 34.729 87.864 ;
     RECT  32.825 89.472 34.729 89.496 ;
     RECT  34.189 98.736 34.729 98.76 ;
     RECT  34.657 100.32 34.729 100.344 ;
     RECT  34.189 101.952 34.729 101.976 ;
     RECT  34.189 103.488 34.729 109.944 ;
     RECT  34.189 111.216 34.729 111.72 ;
     RECT  34.369 112.848 34.729 116.616 ;
     RECT  34.693 4.56 34.765 7.176 ;
     RECT  34.729 8.16 34.765 14.808 ;
     RECT  34.693 16.08 34.765 18.216 ;
     RECT  34.189 21.312 34.765 22.44 ;
     RECT  34.693 23.424 34.765 28.296 ;
     RECT  34.225 29.712 34.765 29.928 ;
     RECT  34.693 31.344 34.765 31.56 ;
     RECT  34.189 32.64 34.765 33.144 ;
     RECT  34.189 34.944 34.765 34.968 ;
     RECT  34.657 36.048 34.765 36.072 ;
     RECT  34.189 37.536 34.765 38.52 ;
     RECT  34.225 40.128 34.765 40.488 ;
     RECT  34.729 41.568 34.765 44.856 ;
     RECT  34.729 45.984 34.765 46.968 ;
     RECT  34.189 48.384 34.765 48.888 ;
     RECT  34.729 49.872 34.765 55.704 ;
     RECT  34.189 56.832 34.765 60.744 ;
     RECT  34.729 62.016 34.765 62.232 ;
     RECT  34.729 63.312 34.765 69.048 ;
     RECT  34.729 71.472 34.765 79.608 ;
     RECT  34.729 80.88 34.765 80.904 ;
     RECT  34.729 82.176 34.765 89.496 ;
     RECT  34.337 90.624 34.765 94.536 ;
     RECT  34.729 98.736 34.765 100.344 ;
     RECT  34.729 101.616 34.765 101.976 ;
     RECT  34.765 34.944 34.801 36.072 ;
     RECT  34.765 31.344 35.305 33.816 ;
     RECT  34.765 71.28 35.305 80.904 ;
     RECT  34.765 82.176 35.305 94.536 ;
     RECT  34.189 95.616 35.305 97.752 ;
     RECT  34.765 98.736 35.305 101.976 ;
     RECT  34.765 4.56 35.341 18.216 ;
     RECT  34.441 19.344 35.341 19.368 ;
     RECT  34.765 21.312 35.341 30.072 ;
     RECT  35.305 31.056 35.341 33.816 ;
     RECT  34.801 34.944 35.341 36.264 ;
     RECT  34.765 37.536 35.341 60.744 ;
     RECT  34.765 62.016 35.341 70.008 ;
     RECT  35.305 71.28 35.341 94.536 ;
     RECT  35.305 95.616 35.341 101.976 ;
     RECT  34.729 103.248 35.341 116.616 ;
     RECT  35.341 4.416 36.54 116.616 ;
     RECT  36.54 93.264 36.605 93.288 ;
    LAYER M5 ;
     RECT  2.4 2.137 2.52 2.151 ;
     RECT  5.1 2.137 5.22 2.151 ;
     RECT  7.8 2.137 7.92 2.151 ;
     RECT  10.5 2.137 10.62 2.151 ;
     RECT  13.2 2.137 13.32 2.151 ;
     RECT  15.9 2.137 16.02 2.151 ;
     RECT  18.6 2.137 18.72 2.151 ;
     RECT  21.3 2.137 21.42 2.151 ;
     RECT  24 2.137 24.12 2.151 ;
     RECT  26.7 2.137 26.82 2.151 ;
     RECT  29.4 2.137 29.52 2.151 ;
     RECT  32.1 2.137 32.22 2.151 ;
     RECT  6.432 5.701 6.456 6.085 ;
     RECT  7.8 2.151 8.112 6.085 ;
     RECT  6.432 6.085 8.112 6.851 ;
     RECT  3.84 4.501 3.864 6.899 ;
     RECT  5.1 2.151 5.412 7.381 ;
     RECT  6.96 6.851 8.112 7.907 ;
     RECT  4.608 7.381 5.412 7.909 ;
     RECT  4.368 7.909 5.412 9.637 ;
     RECT  7.392 7.907 8.112 9.733 ;
     RECT  4.368 9.637 5.88 11.365 ;
     RECT  7.152 9.733 8.112 11.365 ;
     RECT  4.368 11.365 8.112 11.459 ;
     RECT  7.8 11.459 8.112 12.517 ;
     RECT  4.368 11.459 6.264 13.091 ;
     RECT  7.392 12.517 8.112 13.573 ;
     RECT  4.368 13.091 5.88 14.245 ;
     RECT  7.056 13.573 8.112 17.123 ;
     RECT  7.392 17.123 8.112 18.661 ;
     RECT  4.224 14.245 5.88 18.757 ;
     RECT  4.032 18.757 5.88 18.947 ;
     RECT  6.96 18.661 8.112 19.859 ;
     RECT  4.224 18.947 5.88 20.051 ;
     RECT  4.224 20.051 5.592 20.149 ;
     RECT  7.8 19.859 8.112 20.965 ;
     RECT  3.936 20.149 5.592 22.165 ;
     RECT  7.488 20.965 8.112 22.405 ;
     RECT  3.936 22.165 6.072 22.741 ;
     RECT  7.104 22.405 8.112 22.741 ;
     RECT  3.936 22.741 8.112 23.123 ;
     RECT  4.08 23.123 8.112 23.555 ;
     RECT  4.464 23.555 8.112 25.045 ;
     RECT  3.84 25.045 8.112 26.195 ;
     RECT  3.984 26.195 8.112 26.483 ;
     RECT  3.984 26.483 6.024 27.733 ;
     RECT  7.248 26.483 8.112 27.733 ;
     RECT  3.984 27.733 8.112 27.877 ;
     RECT  3.888 27.877 8.112 28.691 ;
     RECT  3.888 28.691 6.408 29.075 ;
     RECT  3.888 29.075 6.264 29.699 ;
     RECT  7.8 28.691 8.112 30.709 ;
     RECT  3.888 29.699 6.024 30.851 ;
     RECT  3.888 30.851 5.544 30.997 ;
     RECT  3.84 30.997 5.544 32.437 ;
     RECT  3.84 32.437 6.264 33.059 ;
     RECT  7.68 30.709 8.112 34.501 ;
     RECT  7.68 34.501 8.472 34.835 ;
     RECT  3.888 33.059 6.264 35.029 ;
     RECT  3.888 35.029 6.504 35.075 ;
     RECT  2.4 2.151 2.712 35.317 ;
     RECT  3.888 35.075 5.412 35.317 ;
     RECT  2.4 35.317 5.412 35.363 ;
     RECT  6.48 35.075 6.504 36.325 ;
     RECT  7.8 34.835 8.472 36.325 ;
     RECT  6.48 36.325 8.472 36.371 ;
     RECT  4.848 35.363 5.412 37.429 ;
     RECT  2.4 35.363 3.432 38.243 ;
     RECT  4.464 37.429 5.412 38.677 ;
     RECT  6.48 36.371 8.112 38.677 ;
     RECT  4.464 38.677 8.112 38.819 ;
     RECT  4.464 38.819 6.504 40.019 ;
     RECT  4.848 40.019 6.504 40.405 ;
     RECT  7.8 38.819 8.112 40.405 ;
     RECT  4.848 40.405 8.112 40.835 ;
     RECT  4.848 40.835 5.64 40.981 ;
     RECT  4.56 40.981 5.64 41.221 ;
     RECT  24 2.151 24.312 41.605 ;
     RECT  7.392 40.835 8.112 41.651 ;
     RECT  23.904 41.605 24.312 41.747 ;
     RECT  7.8 41.651 8.112 41.989 ;
     RECT  4.032 41.221 5.64 42.709 ;
     RECT  7.8 41.989 8.232 42.803 ;
     RECT  3.696 42.709 6.456 42.851 ;
     RECT  4.032 42.851 6.456 43.379 ;
     RECT  7.8 42.803 8.112 44.341 ;
     RECT  7.68 44.341 8.112 44.771 ;
     RECT  4.032 43.379 5.64 45.013 ;
     RECT  2.4 38.243 2.712 45.301 ;
     RECT  4.032 45.013 6.216 45.877 ;
     RECT  7.8 44.771 8.112 46.117 ;
     RECT  2.4 45.301 2.856 46.211 ;
     RECT  4.032 45.877 6.312 46.211 ;
     RECT  5.1 46.211 6.312 46.261 ;
     RECT  7.44 46.117 8.112 46.261 ;
     RECT  4.032 46.211 4.056 46.499 ;
     RECT  5.1 46.261 8.112 47.845 ;
     RECT  4.8 47.845 8.112 49.525 ;
     RECT  4.272 49.525 8.112 50.819 ;
     RECT  4.56 50.819 8.112 51.347 ;
     RECT  4.992 51.347 8.112 52.309 ;
     RECT  4.608 52.309 8.112 52.405 ;
     RECT  4.32 52.405 8.112 56.723 ;
     RECT  4.656 56.723 8.112 57.971 ;
     RECT  4.656 57.971 6.552 58.117 ;
     RECT  4.368 58.117 6.552 58.739 ;
     RECT  2.4 46.211 2.712 59.173 ;
     RECT  4.368 58.739 6.264 59.173 ;
     RECT  7.68 57.971 8.112 59.891 ;
     RECT  2.4 59.173 6.264 59.939 ;
     RECT  3.936 59.939 6.264 60.035 ;
     RECT  3.936 60.035 6.216 61.331 ;
     RECT  7.8 59.891 8.112 61.429 ;
     RECT  3.936 61.331 5.784 61.667 ;
     RECT  4.512 61.667 5.784 63.205 ;
     RECT  4.224 63.205 5.784 64.309 ;
     RECT  7.44 61.429 8.112 66.227 ;
     RECT  4.224 64.309 6.36 66.371 ;
     RECT  2.4 59.939 2.712 68.917 ;
     RECT  4.368 66.371 6.36 68.917 ;
     RECT  2.4 68.917 6.36 69.493 ;
     RECT  7.8 66.227 8.112 69.493 ;
     RECT  2.4 69.493 8.112 69.587 ;
     RECT  3.744 69.587 8.112 70.981 ;
     RECT  3.744 70.981 8.232 71.747 ;
     RECT  3.744 71.747 6.648 71.891 ;
     RECT  3.888 71.891 6.648 72.131 ;
     RECT  3.888 72.131 5.976 72.467 ;
     RECT  2.4 69.587 2.712 72.997 ;
     RECT  4.368 72.467 5.976 73.525 ;
     RECT  2.4 72.997 2.856 73.571 ;
     RECT  7.8 71.747 8.232 73.571 ;
     RECT  7.8 73.571 8.112 74.533 ;
     RECT  7.2 74.533 8.112 74.675 ;
     RECT  3.888 73.525 5.976 76.163 ;
     RECT  7.296 74.675 8.112 76.645 ;
     RECT  3.936 76.163 5.976 77.557 ;
     RECT  7.104 76.645 8.112 77.557 ;
     RECT  2.4 73.571 2.712 78.085 ;
     RECT  3.936 77.557 8.112 78.085 ;
     RECT  2.4 78.085 8.112 78.275 ;
     RECT  2.4 78.275 6.552 79.237 ;
     RECT  7.8 78.275 8.112 79.237 ;
     RECT  2.4 79.237 8.112 80.099 ;
     RECT  4.608 80.099 8.112 81.635 ;
     RECT  5.1 81.635 8.112 82.403 ;
     RECT  2.4 80.099 3.48 82.691 ;
     RECT  5.1 82.403 6.36 83.077 ;
     RECT  7.344 82.403 8.112 84.371 ;
     RECT  4.656 83.077 6.36 84.419 ;
     RECT  4.944 84.419 6.36 85.619 ;
     RECT  7.8 84.371 8.112 85.765 ;
     RECT  7.68 85.765 8.112 86.675 ;
     RECT  4.032 86.005 4.056 87.109 ;
     RECT  3.84 87.109 4.056 87.155 ;
     RECT  5.1 85.619 6.36 88.885 ;
     RECT  7.8 86.675 8.112 88.885 ;
     RECT  5.1 88.885 8.112 90.227 ;
     RECT  3.84 87.155 3.864 91.141 ;
     RECT  5.1 90.227 6.36 91.141 ;
     RECT  3.84 91.141 6.36 91.187 ;
     RECT  7.44 90.227 8.112 91.811 ;
     RECT  3.936 91.187 6.36 94.115 ;
     RECT  4.896 94.115 6.36 95.701 ;
     RECT  7.8 91.811 8.112 96.469 ;
     RECT  4.512 95.701 6.36 97.669 ;
     RECT  4.512 97.669 6.552 98.005 ;
     RECT  7.68 96.469 8.112 98.099 ;
     RECT  3.936 98.005 6.552 98.675 ;
     RECT  4.512 98.675 6.552 99.203 ;
     RECT  4.608 99.203 6.552 99.779 ;
     RECT  4.608 99.779 6.36 100.261 ;
     RECT  3.984 100.261 6.36 100.355 ;
     RECT  7.8 98.099 8.112 101.173 ;
     RECT  3.984 100.355 4.008 101.701 ;
     RECT  5.1 100.355 6.36 101.701 ;
     RECT  3.984 101.701 6.36 102.371 ;
     RECT  3.984 102.371 6.024 102.659 ;
     RECT  7.8 101.173 8.232 103.763 ;
     RECT  4.608 102.659 6.024 104.245 ;
     RECT  4.128 104.245 6.024 104.291 ;
     RECT  7.8 103.763 8.112 104.821 ;
     RECT  7.8 104.821 8.232 106.261 ;
     RECT  7.2 106.261 8.232 106.307 ;
     RECT  7.2 106.307 8.112 109.715 ;
     RECT  4.128 104.291 5.784 109.957 ;
     RECT  4.128 109.957 6.264 111.155 ;
     RECT  7.392 109.715 8.112 111.587 ;
     RECT  4.128 111.155 6.024 112.355 ;
     RECT  4.56 112.355 6.024 112.883 ;
     RECT  7.44 111.587 8.112 113.459 ;
     RECT  4.896 112.883 6.024 113.891 ;
     RECT  7.8 113.459 8.112 114.421 ;
     RECT  5.1 113.891 6.024 114.851 ;
     RECT  3.936 114.565 3.96 115.763 ;
     RECT  7.632 114.421 8.112 115.859 ;
     RECT  2.4 82.691 2.712 118.809 ;
     RECT  7.8 115.859 8.112 118.809 ;
     RECT  10.5 2.151 10.812 118.809 ;
     RECT  13.2 2.151 13.512 118.809 ;
     RECT  15.9 2.151 16.212 118.809 ;
     RECT  18.6 2.151 18.912 118.809 ;
     RECT  21.3 2.151 21.612 118.809 ;
     RECT  24 41.747 24.312 118.809 ;
     RECT  26.7 2.151 27.012 118.809 ;
     RECT  29.4 2.151 29.712 118.809 ;
     RECT  32.1 2.151 32.412 118.809 ;
     RECT  2.4 118.809 2.52 118.823 ;
     RECT  5.1 114.851 5.784 118.823 ;
     RECT  7.8 118.809 7.92 118.823 ;
     RECT  10.5 118.809 10.62 118.823 ;
     RECT  13.2 118.809 13.32 118.823 ;
     RECT  15.9 118.809 16.02 118.823 ;
     RECT  18.6 118.809 18.72 118.823 ;
     RECT  21.3 118.809 21.42 118.823 ;
     RECT  24 118.809 24.12 118.823 ;
     RECT  26.7 118.809 26.82 118.823 ;
     RECT  29.4 118.809 29.52 118.823 ;
     RECT  32.1 118.809 32.22 118.823 ;
     RECT  5.76 118.823 5.784 120.851 ;
     RECT  2.712 4.501 3.84 6.899 ;
     RECT  3.864 4.501 5.1 6.899 ;
     RECT  5.412 5.701 6.432 6.851 ;
     RECT  6.456 5.701 7.8 6.085 ;
     RECT  4.368 6.899 5.1 7.381 ;
     RECT  4.368 7.381 4.608 7.909 ;
     RECT  5.88 9.637 7.392 9.733 ;
     RECT  5.88 9.733 7.152 11.365 ;
     RECT  6.264 11.459 7.8 12.517 ;
     RECT  6.264 12.517 7.392 13.091 ;
     RECT  5.88 13.091 7.392 13.573 ;
     RECT  5.88 13.573 7.056 17.123 ;
     RECT  2.712 14.245 4.224 18.757 ;
     RECT  5.88 17.123 7.392 18.661 ;
     RECT  5.88 18.661 6.96 19.859 ;
     RECT  2.712 18.757 4.032 18.947 ;
     RECT  2.712 18.947 4.224 20.149 ;
     RECT  7.488 19.859 7.8 20.965 ;
     RECT  2.712 20.149 3.936 23.123 ;
     RECT  6.072 22.165 7.488 22.405 ;
     RECT  6.072 22.405 7.104 22.741 ;
     RECT  2.712 23.123 4.08 23.555 ;
     RECT  2.712 23.555 4.464 25.045 ;
     RECT  2.712 25.045 3.84 26.195 ;
     RECT  2.712 26.195 3.984 27.877 ;
     RECT  6.024 26.483 7.248 27.733 ;
     RECT  2.712 27.877 3.888 30.997 ;
     RECT  6.408 28.691 7.8 29.075 ;
     RECT  2.712 30.997 3.84 33.059 ;
     RECT  6.264 32.437 7.68 34.835 ;
     RECT  2.712 33.059 3.888 35.317 ;
     RECT  6.264 34.835 7.8 35.029 ;
     RECT  6.504 35.029 7.8 36.325 ;
     RECT  5.412 35.075 6.48 38.677 ;
     RECT  3.432 35.363 4.848 37.429 ;
     RECT  3.432 37.429 4.464 38.243 ;
     RECT  6.504 38.819 7.8 40.405 ;
     RECT  4.464 40.019 4.848 40.981 ;
     RECT  4.464 40.981 4.56 41.221 ;
     RECT  2.712 41.221 4.032 42.709 ;
     RECT  7.392 41.651 7.8 42.709 ;
     RECT  2.712 42.709 3.696 42.851 ;
     RECT  6.456 42.709 7.8 43.379 ;
     RECT  2.712 42.851 4.032 45.301 ;
     RECT  7.68 43.379 7.8 44.341 ;
     RECT  7.68 44.771 7.8 45.013 ;
     RECT  6.216 45.013 7.8 45.877 ;
     RECT  2.856 45.301 4.032 46.211 ;
     RECT  6.312 45.877 7.8 46.117 ;
     RECT  6.312 46.117 7.44 46.261 ;
     RECT  2.712 46.211 4.032 46.499 ;
     RECT  4.056 46.211 5.1 46.499 ;
     RECT  4.8 46.499 5.1 47.845 ;
     RECT  4.56 51.347 4.992 52.309 ;
     RECT  4.56 52.309 4.608 52.405 ;
     RECT  4.368 56.723 4.656 58.117 ;
     RECT  6.552 57.971 7.68 58.739 ;
     RECT  6.264 58.739 7.68 59.891 ;
     RECT  2.712 59.939 3.936 61.667 ;
     RECT  2.712 63.205 4.224 66.371 ;
     RECT  6.36 64.309 7.44 66.227 ;
     RECT  6.36 66.227 7.8 69.493 ;
     RECT  2.712 69.587 3.744 71.891 ;
     RECT  6.648 71.747 7.8 72.131 ;
     RECT  2.712 71.891 3.888 72.467 ;
     RECT  2.712 72.467 4.368 72.997 ;
     RECT  2.856 72.997 4.368 73.525 ;
     RECT  2.856 73.525 3.888 73.571 ;
     RECT  2.712 73.571 3.888 76.163 ;
     RECT  5.976 74.533 7.2 74.675 ;
     RECT  5.976 74.675 7.296 76.645 ;
     RECT  2.712 76.163 3.936 78.085 ;
     RECT  5.976 76.645 7.104 77.557 ;
     RECT  6.552 78.275 7.8 79.237 ;
     RECT  3.48 80.099 4.608 81.635 ;
     RECT  3.48 81.635 5.1 82.691 ;
     RECT  6.36 82.403 7.344 84.371 ;
     RECT  4.656 82.691 5.1 83.077 ;
     RECT  6.36 84.371 7.8 85.765 ;
     RECT  4.944 85.619 5.1 86.005 ;
     RECT  6.36 85.765 7.68 86.675 ;
     RECT  2.712 86.005 4.032 87.109 ;
     RECT  4.056 86.005 5.1 87.155 ;
     RECT  6.36 86.675 7.8 88.885 ;
     RECT  2.712 87.109 3.84 91.187 ;
     RECT  3.864 87.155 5.1 91.141 ;
     RECT  6.36 90.227 7.44 91.811 ;
     RECT  2.712 91.187 3.936 94.115 ;
     RECT  6.36 91.811 7.8 96.469 ;
     RECT  6.36 96.469 7.68 97.669 ;
     RECT  6.552 97.669 7.68 98.099 ;
     RECT  2.712 98.005 3.936 98.675 ;
     RECT  6.552 98.099 7.8 99.779 ;
     RECT  4.512 99.203 4.608 100.261 ;
     RECT  6.36 99.779 7.8 102.371 ;
     RECT  2.712 100.261 3.984 102.659 ;
     RECT  4.008 100.355 5.1 101.701 ;
     RECT  8.112 103.763 8.232 104.821 ;
     RECT  2.712 104.245 4.128 112.355 ;
     RECT  5.784 106.261 7.2 109.715 ;
     RECT  5.784 109.715 7.392 109.957 ;
     RECT  6.264 109.957 7.392 111.155 ;
     RECT  6.024 111.155 7.392 111.587 ;
     RECT  6.024 111.587 7.44 113.459 ;
     RECT  7.632 113.459 7.8 114.421 ;
     RECT  4.896 113.891 5.1 114.565 ;
     RECT  2.712 114.565 3.936 115.763 ;
     RECT  3.96 114.565 5.1 115.763 ;
  END
END dsfd_hstnh_692
END LIBRARY
